VERSION 5.8 ;
BUSBITCHARS "[]" ;
DIVIDERCHAR "/" ;
UNITS
    DATABASE MICRONS 1000 ;
END UNITS

VIA CF_CARAVEL_SOC_via2_3_3100_480_1_9_320_320
  VIARULE M1M2_PR ;
  CUTSIZE 0.15 0.15 ;
  LAYERS met1 via met2 ;
  CUTSPACING 0.17 0.17 ;
  ENCLOSURE 0.085 0.165 0.055 0.085 ;
  ROWCOL 1 9 ;
END CF_CARAVEL_SOC_via2_3_3100_480_1_9_320_320

VIA CF_CARAVEL_SOC_via3_4_3100_480_1_7_400_400
  VIARULE M2M3_PR ;
  CUTSIZE 0.2 0.2 ;
  LAYERS met2 via2 met3 ;
  CUTSPACING 0.2 0.2 ;
  ENCLOSURE 0.04 0.085 0.065 0.065 ;
  ROWCOL 1 7 ;
END CF_CARAVEL_SOC_via3_4_3100_480_1_7_400_400

VIA CF_CARAVEL_SOC_via4_5_3100_480_1_7_400_400
  VIARULE M3M4_PR ;
  CUTSIZE 0.2 0.2 ;
  LAYERS met3 via3 met4 ;
  CUTSPACING 0.2 0.2 ;
  ENCLOSURE 0.09 0.06 0.25 0.065 ;
  ROWCOL 1 7 ;
END CF_CARAVEL_SOC_via4_5_3100_480_1_7_400_400

VIA CF_CARAVEL_SOC_via5_6_3100_3100_2_2_1600_1600
  VIARULE M4M5_PR ;
  CUTSIZE 0.8 0.8 ;
  LAYERS met4 via4 met5 ;
  CUTSPACING 0.8 0.8 ;
  ENCLOSURE 0.35 0.19 0.31 0.35 ;
  ROWCOL 2 2 ;
END CF_CARAVEL_SOC_via5_6_3100_3100_2_2_1600_1600

VIA CF_CARAVEL_SOC_via5_6_1600_3100_2_1_1600_1600
  VIARULE M4M5_PR ;
  CUTSIZE 0.8 0.8 ;
  LAYERS met4 via4 met5 ;
  CUTSPACING 0.8 0.8 ;
  ENCLOSURE 0.4 0.35 0.31 0.35 ;
  ROWCOL 2 1 ;
END CF_CARAVEL_SOC_via5_6_1600_3100_2_1_1600_1600

VIA CF_CARAVEL_SOC_via5_6_1600_1600_1_1_1600_1600
  VIARULE M4M5_PR ;
  CUTSIZE 0.8 0.8 ;
  LAYERS met4 via4 met5 ;
  CUTSPACING 0.8 0.8 ;
  ENCLOSURE 0.4 0.4 0.4 0.4 ;
END CF_CARAVEL_SOC_via5_6_1600_1600_1_1_1600_1600

VIA CF_CARAVEL_SOC_via5_6_3100_1600_1_2_1600_1600
  VIARULE M4M5_PR ;
  CUTSIZE 0.8 0.8 ;
  LAYERS met4 via4 met5 ;
  CUTSPACING 0.8 0.8 ;
  ENCLOSURE 0.35 0.19 0.35 0.4 ;
  ROWCOL 1 2 ;
END CF_CARAVEL_SOC_via5_6_3100_1600_1_2_1600_1600

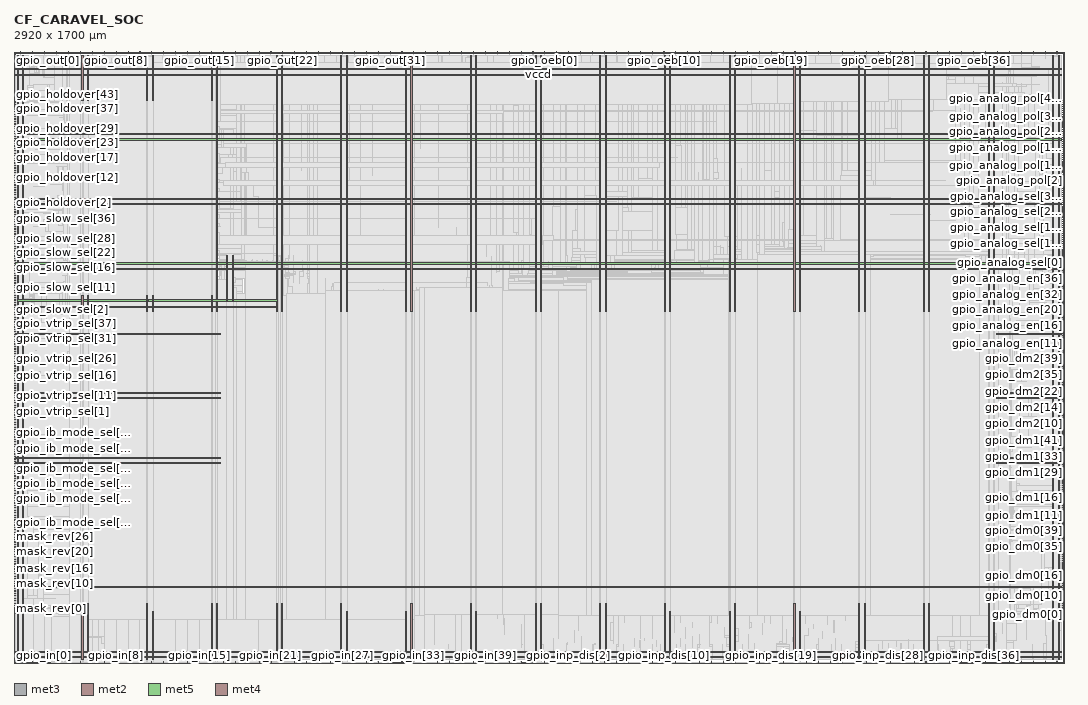
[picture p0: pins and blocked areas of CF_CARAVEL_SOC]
MACRO CF_CARAVEL_SOC
  FOREIGN CF_CARAVEL_SOC 0 0 ;
  CLASS BLOCK ;
  SIZE 2920 BY 1700 ;
  PIN gpio_analog_en[0]
    DIRECTION OUTPUT ;
    USE SIGNAL ;
    PORT
      LAYER met3 ;
        RECT  2916 851.4 2920 852 ;
    END
  END gpio_analog_en[0]
  PIN gpio_analog_en[10]
    DIRECTION OUTPUT ;
    USE SIGNAL ;
    PORT
      LAYER met3 ;
        RECT  2916 905.8 2920 906.4 ;
    END
  END gpio_analog_en[10]
  PIN gpio_analog_en[11]
    DIRECTION OUTPUT ;
    USE SIGNAL ;
    PORT
      LAYER met3 ;
        RECT  2916 911.24 2920 911.84 ;
    END
  END gpio_analog_en[11]
  PIN gpio_analog_en[12]
    DIRECTION OUTPUT ;
    USE SIGNAL ;
    PORT
      LAYER met3 ;
        RECT  2916 916.68 2920 917.28 ;
    END
  END gpio_analog_en[12]
  PIN gpio_analog_en[13]
    DIRECTION OUTPUT ;
    USE SIGNAL ;
    PORT
      LAYER met3 ;
        RECT  2916 922.12 2920 922.72 ;
    END
  END gpio_analog_en[13]
  PIN gpio_analog_en[14]
    DIRECTION OUTPUT ;
    USE SIGNAL ;
    PORT
      LAYER met3 ;
        RECT  2916 927.56 2920 928.16 ;
    END
  END gpio_analog_en[14]
  PIN gpio_analog_en[15]
    DIRECTION OUTPUT ;
    USE SIGNAL ;
    PORT
      LAYER met3 ;
        RECT  2916 933 2920 933.6 ;
    END
  END gpio_analog_en[15]
  PIN gpio_analog_en[16]
    DIRECTION OUTPUT ;
    USE SIGNAL ;
    PORT
      LAYER met3 ;
        RECT  2916 938.44 2920 939.04 ;
    END
  END gpio_analog_en[16]
  PIN gpio_analog_en[17]
    DIRECTION OUTPUT ;
    USE SIGNAL ;
    PORT
      LAYER met3 ;
        RECT  2916 943.88 2920 944.48 ;
    END
  END gpio_analog_en[17]
  PIN gpio_analog_en[18]
    DIRECTION OUTPUT ;
    USE SIGNAL ;
    PORT
      LAYER met3 ;
        RECT  2916 949.32 2920 949.92 ;
    END
  END gpio_analog_en[18]
  PIN gpio_analog_en[19]
    DIRECTION OUTPUT ;
    USE SIGNAL ;
    PORT
      LAYER met3 ;
        RECT  2916 954.76 2920 955.36 ;
    END
  END gpio_analog_en[19]
  PIN gpio_analog_en[1]
    DIRECTION OUTPUT ;
    USE SIGNAL ;
    PORT
      LAYER met3 ;
        RECT  2916 856.84 2920 857.44 ;
    END
  END gpio_analog_en[1]
  PIN gpio_analog_en[20]
    DIRECTION OUTPUT ;
    USE SIGNAL ;
    PORT
      LAYER met3 ;
        RECT  2916 960.2 2920 960.8 ;
    END
  END gpio_analog_en[20]
  PIN gpio_analog_en[21]
    DIRECTION OUTPUT ;
    USE SIGNAL ;
    PORT
      LAYER met3 ;
        RECT  2916 965.64 2920 966.24 ;
    END
  END gpio_analog_en[21]
  PIN gpio_analog_en[22]
    DIRECTION OUTPUT ;
    USE SIGNAL ;
    PORT
      LAYER met3 ;
        RECT  2916 971.08 2920 971.68 ;
    END
  END gpio_analog_en[22]
  PIN gpio_analog_en[23]
    DIRECTION OUTPUT ;
    USE SIGNAL ;
    PORT
      LAYER met3 ;
        RECT  2916 976.52 2920 977.12 ;
    END
  END gpio_analog_en[23]
  PIN gpio_analog_en[24]
    DIRECTION OUTPUT ;
    USE SIGNAL ;
    PORT
      LAYER met3 ;
        RECT  2916 981.96 2920 982.56 ;
    END
  END gpio_analog_en[24]
  PIN gpio_analog_en[25]
    DIRECTION OUTPUT ;
    USE SIGNAL ;
    PORT
      LAYER met3 ;
        RECT  2916 987.4 2920 988 ;
    END
  END gpio_analog_en[25]
  PIN gpio_analog_en[26]
    DIRECTION OUTPUT ;
    USE SIGNAL ;
    PORT
      LAYER met3 ;
        RECT  2916 992.84 2920 993.44 ;
    END
  END gpio_analog_en[26]
  PIN gpio_analog_en[27]
    DIRECTION OUTPUT ;
    USE SIGNAL ;
    PORT
      LAYER met3 ;
        RECT  2916 998.28 2920 998.88 ;
    END
  END gpio_analog_en[27]
  PIN gpio_analog_en[28]
    DIRECTION OUTPUT ;
    USE SIGNAL ;
    PORT
      LAYER met3 ;
        RECT  2916 1003.72 2920 1004.32 ;
    END
  END gpio_analog_en[28]
  PIN gpio_analog_en[29]
    DIRECTION OUTPUT ;
    USE SIGNAL ;
    PORT
      LAYER met3 ;
        RECT  2916 1009.16 2920 1009.76 ;
    END
  END gpio_analog_en[29]
  PIN gpio_analog_en[2]
    DIRECTION OUTPUT ;
    USE SIGNAL ;
    PORT
      LAYER met3 ;
        RECT  2916 862.28 2920 862.88 ;
    END
  END gpio_analog_en[2]
  PIN gpio_analog_en[30]
    DIRECTION OUTPUT ;
    USE SIGNAL ;
    PORT
      LAYER met3 ;
        RECT  2916 1014.6 2920 1015.2 ;
    END
  END gpio_analog_en[30]
  PIN gpio_analog_en[31]
    DIRECTION OUTPUT ;
    USE SIGNAL ;
    PORT
      LAYER met3 ;
        RECT  2916 1020.04 2920 1020.64 ;
    END
  END gpio_analog_en[31]
  PIN gpio_analog_en[32]
    DIRECTION OUTPUT ;
    USE SIGNAL ;
    PORT
      LAYER met3 ;
        RECT  2916 1025.48 2920 1026.08 ;
    END
  END gpio_analog_en[32]
  PIN gpio_analog_en[33]
    DIRECTION OUTPUT ;
    USE SIGNAL ;
    PORT
      LAYER met3 ;
        RECT  2916 1030.92 2920 1031.52 ;
    END
  END gpio_analog_en[33]
  PIN gpio_analog_en[34]
    DIRECTION OUTPUT ;
    USE SIGNAL ;
    PORT
      LAYER met3 ;
        RECT  2916 1036.36 2920 1036.96 ;
    END
  END gpio_analog_en[34]
  PIN gpio_analog_en[35]
    DIRECTION OUTPUT ;
    USE SIGNAL ;
    PORT
      LAYER met3 ;
        RECT  2916 1041.8 2920 1042.4 ;
    END
  END gpio_analog_en[35]
  PIN gpio_analog_en[36]
    DIRECTION OUTPUT ;
    USE SIGNAL ;
    PORT
      LAYER met3 ;
        RECT  2916 1047.24 2920 1047.84 ;
    END
  END gpio_analog_en[36]
  PIN gpio_analog_en[37]
    DIRECTION OUTPUT ;
    USE SIGNAL ;
    PORT
      LAYER met3 ;
        RECT  2916 1052.68 2920 1053.28 ;
    END
  END gpio_analog_en[37]
  PIN gpio_analog_en[38]
    DIRECTION OUTPUT ;
    USE SIGNAL ;
    PORT
      LAYER met3 ;
        RECT  2916 1058.12 2920 1058.72 ;
    END
  END gpio_analog_en[38]
  PIN gpio_analog_en[39]
    DIRECTION OUTPUT ;
    USE SIGNAL ;
    PORT
      LAYER met3 ;
        RECT  2916 1063.56 2920 1064.16 ;
    END
  END gpio_analog_en[39]
  PIN gpio_analog_en[3]
    DIRECTION OUTPUT ;
    USE SIGNAL ;
    PORT
      LAYER met3 ;
        RECT  2916 867.72 2920 868.32 ;
    END
  END gpio_analog_en[3]
  PIN gpio_analog_en[40]
    DIRECTION OUTPUT ;
    USE SIGNAL ;
    PORT
      LAYER met3 ;
        RECT  2916 1069 2920 1069.6 ;
    END
  END gpio_analog_en[40]
  PIN gpio_analog_en[41]
    DIRECTION OUTPUT ;
    USE SIGNAL ;
    PORT
      LAYER met3 ;
        RECT  2916 1074.44 2920 1075.04 ;
    END
  END gpio_analog_en[41]
  PIN gpio_analog_en[42]
    DIRECTION OUTPUT ;
    USE SIGNAL ;
    PORT
      LAYER met3 ;
        RECT  2916 1079.88 2920 1080.48 ;
    END
  END gpio_analog_en[42]
  PIN gpio_analog_en[43]
    DIRECTION OUTPUT ;
    USE SIGNAL ;
    PORT
      LAYER met3 ;
        RECT  2916 1085.32 2920 1085.92 ;
    END
  END gpio_analog_en[43]
  PIN gpio_analog_en[4]
    DIRECTION OUTPUT ;
    USE SIGNAL ;
    PORT
      LAYER met3 ;
        RECT  2916 873.16 2920 873.76 ;
    END
  END gpio_analog_en[4]
  PIN gpio_analog_en[5]
    DIRECTION OUTPUT ;
    USE SIGNAL ;
    PORT
      LAYER met3 ;
        RECT  2916 878.6 2920 879.2 ;
    END
  END gpio_analog_en[5]
  PIN gpio_analog_en[6]
    DIRECTION OUTPUT ;
    USE SIGNAL ;
    PORT
      LAYER met3 ;
        RECT  2916 884.04 2920 884.64 ;
    END
  END gpio_analog_en[6]
  PIN gpio_analog_en[7]
    DIRECTION OUTPUT ;
    USE SIGNAL ;
    PORT
      LAYER met3 ;
        RECT  2916 889.48 2920 890.08 ;
    END
  END gpio_analog_en[7]
  PIN gpio_analog_en[8]
    DIRECTION OUTPUT ;
    USE SIGNAL ;
    PORT
      LAYER met3 ;
        RECT  2916 894.92 2920 895.52 ;
    END
  END gpio_analog_en[8]
  PIN gpio_analog_en[9]
    DIRECTION OUTPUT ;
    USE SIGNAL ;
    PORT
      LAYER met3 ;
        RECT  2916 900.36 2920 900.96 ;
    END
  END gpio_analog_en[9]
  PIN gpio_analog_pol[0]
    DIRECTION OUTPUT ;
    USE SIGNAL ;
    PORT
      LAYER met3 ;
        RECT  2916 1330.12 2920 1330.72 ;
    END
  END gpio_analog_pol[0]
  PIN gpio_analog_pol[10]
    DIRECTION OUTPUT ;
    USE SIGNAL ;
    PORT
      LAYER met3 ;
        RECT  2916 1384.52 2920 1385.12 ;
    END
  END gpio_analog_pol[10]
  PIN gpio_analog_pol[11]
    DIRECTION OUTPUT ;
    USE SIGNAL ;
    PORT
      LAYER met3 ;
        RECT  2916 1389.96 2920 1390.56 ;
    END
  END gpio_analog_pol[11]
  PIN gpio_analog_pol[12]
    DIRECTION OUTPUT ;
    USE SIGNAL ;
    PORT
      LAYER met3 ;
        RECT  2916 1395.4 2920 1396 ;
    END
  END gpio_analog_pol[12]
  PIN gpio_analog_pol[13]
    DIRECTION OUTPUT ;
    USE SIGNAL ;
    PORT
      LAYER met3 ;
        RECT  2916 1400.84 2920 1401.44 ;
    END
  END gpio_analog_pol[13]
  PIN gpio_analog_pol[14]
    DIRECTION OUTPUT ;
    USE SIGNAL ;
    PORT
      LAYER met3 ;
        RECT  2916 1406.28 2920 1406.88 ;
    END
  END gpio_analog_pol[14]
  PIN gpio_analog_pol[15]
    DIRECTION OUTPUT ;
    USE SIGNAL ;
    PORT
      LAYER met3 ;
        RECT  2916 1411.72 2920 1412.32 ;
    END
  END gpio_analog_pol[15]
  PIN gpio_analog_pol[16]
    DIRECTION OUTPUT ;
    USE SIGNAL ;
    PORT
      LAYER met3 ;
        RECT  2916 1417.16 2920 1417.76 ;
    END
  END gpio_analog_pol[16]
  PIN gpio_analog_pol[17]
    DIRECTION OUTPUT ;
    USE SIGNAL ;
    PORT
      LAYER met3 ;
        RECT  2916 1422.6 2920 1423.2 ;
    END
  END gpio_analog_pol[17]
  PIN gpio_analog_pol[18]
    DIRECTION OUTPUT ;
    USE SIGNAL ;
    PORT
      LAYER met3 ;
        RECT  2916 1428.04 2920 1428.64 ;
    END
  END gpio_analog_pol[18]
  PIN gpio_analog_pol[19]
    DIRECTION OUTPUT ;
    USE SIGNAL ;
    PORT
      LAYER met3 ;
        RECT  2916 1433.48 2920 1434.08 ;
    END
  END gpio_analog_pol[19]
  PIN gpio_analog_pol[1]
    DIRECTION OUTPUT ;
    USE SIGNAL ;
    PORT
      LAYER met3 ;
        RECT  2916 1335.56 2920 1336.16 ;
    END
  END gpio_analog_pol[1]
  PIN gpio_analog_pol[20]
    DIRECTION OUTPUT ;
    USE SIGNAL ;
    PORT
      LAYER met3 ;
        RECT  2916 1438.92 2920 1439.52 ;
    END
  END gpio_analog_pol[20]
  PIN gpio_analog_pol[21]
    DIRECTION OUTPUT ;
    USE SIGNAL ;
    PORT
      LAYER met3 ;
        RECT  2916 1444.36 2920 1444.96 ;
    END
  END gpio_analog_pol[21]
  PIN gpio_analog_pol[22]
    DIRECTION OUTPUT ;
    USE SIGNAL ;
    PORT
      LAYER met3 ;
        RECT  2916 1449.8 2920 1450.4 ;
    END
  END gpio_analog_pol[22]
  PIN gpio_analog_pol[23]
    DIRECTION OUTPUT ;
    USE SIGNAL ;
    PORT
      LAYER met3 ;
        RECT  2916 1455.24 2920 1455.84 ;
    END
  END gpio_analog_pol[23]
  PIN gpio_analog_pol[24]
    DIRECTION OUTPUT ;
    USE SIGNAL ;
    PORT
      LAYER met3 ;
        RECT  2916 1460.68 2920 1461.28 ;
    END
  END gpio_analog_pol[24]
  PIN gpio_analog_pol[25]
    DIRECTION OUTPUT ;
    USE SIGNAL ;
    PORT
      LAYER met3 ;
        RECT  2916 1466.12 2920 1466.72 ;
    END
  END gpio_analog_pol[25]
  PIN gpio_analog_pol[26]
    DIRECTION OUTPUT ;
    USE SIGNAL ;
    PORT
      LAYER met3 ;
        RECT  2916 1471.56 2920 1472.16 ;
    END
  END gpio_analog_pol[26]
  PIN gpio_analog_pol[27]
    DIRECTION OUTPUT ;
    USE SIGNAL ;
    PORT
      LAYER met3 ;
        RECT  2916 1477 2920 1477.6 ;
    END
  END gpio_analog_pol[27]
  PIN gpio_analog_pol[28]
    DIRECTION OUTPUT ;
    USE SIGNAL ;
    PORT
      LAYER met3 ;
        RECT  2916 1482.44 2920 1483.04 ;
    END
  END gpio_analog_pol[28]
  PIN gpio_analog_pol[29]
    DIRECTION OUTPUT ;
    USE SIGNAL ;
    PORT
      LAYER met3 ;
        RECT  2916 1487.88 2920 1488.48 ;
    END
  END gpio_analog_pol[29]
  PIN gpio_analog_pol[2]
    DIRECTION OUTPUT ;
    USE SIGNAL ;
    PORT
      LAYER met3 ;
        RECT  2916 1341 2920 1341.6 ;
    END
  END gpio_analog_pol[2]
  PIN gpio_analog_pol[30]
    DIRECTION OUTPUT ;
    USE SIGNAL ;
    PORT
      LAYER met3 ;
        RECT  2916 1493.32 2920 1493.92 ;
    END
  END gpio_analog_pol[30]
  PIN gpio_analog_pol[31]
    DIRECTION OUTPUT ;
    USE SIGNAL ;
    PORT
      LAYER met3 ;
        RECT  2916 1498.76 2920 1499.36 ;
    END
  END gpio_analog_pol[31]
  PIN gpio_analog_pol[32]
    DIRECTION OUTPUT ;
    USE SIGNAL ;
    PORT
      LAYER met3 ;
        RECT  2916 1504.2 2920 1504.8 ;
    END
  END gpio_analog_pol[32]
  PIN gpio_analog_pol[33]
    DIRECTION OUTPUT ;
    USE SIGNAL ;
    PORT
      LAYER met3 ;
        RECT  2916 1509.64 2920 1510.24 ;
    END
  END gpio_analog_pol[33]
  PIN gpio_analog_pol[34]
    DIRECTION OUTPUT ;
    USE SIGNAL ;
    PORT
      LAYER met3 ;
        RECT  2916 1515.08 2920 1515.68 ;
    END
  END gpio_analog_pol[34]
  PIN gpio_analog_pol[35]
    DIRECTION OUTPUT ;
    USE SIGNAL ;
    PORT
      LAYER met3 ;
        RECT  2916 1520.52 2920 1521.12 ;
    END
  END gpio_analog_pol[35]
  PIN gpio_analog_pol[36]
    DIRECTION OUTPUT ;
    USE SIGNAL ;
    PORT
      LAYER met3 ;
        RECT  2916 1525.96 2920 1526.56 ;
    END
  END gpio_analog_pol[36]
  PIN gpio_analog_pol[37]
    DIRECTION OUTPUT ;
    USE SIGNAL ;
    PORT
      LAYER met3 ;
        RECT  2916 1531.4 2920 1532 ;
    END
  END gpio_analog_pol[37]
  PIN gpio_analog_pol[38]
    DIRECTION OUTPUT ;
    USE SIGNAL ;
    PORT
      LAYER met3 ;
        RECT  2916 1536.84 2920 1537.44 ;
    END
  END gpio_analog_pol[38]
  PIN gpio_analog_pol[39]
    DIRECTION OUTPUT ;
    USE SIGNAL ;
    PORT
      LAYER met3 ;
        RECT  2916 1542.28 2920 1542.88 ;
    END
  END gpio_analog_pol[39]
  PIN gpio_analog_pol[3]
    DIRECTION OUTPUT ;
    USE SIGNAL ;
    PORT
      LAYER met3 ;
        RECT  2916 1346.44 2920 1347.04 ;
    END
  END gpio_analog_pol[3]
  PIN gpio_analog_pol[40]
    DIRECTION OUTPUT ;
    USE SIGNAL ;
    PORT
      LAYER met3 ;
        RECT  2916 1547.72 2920 1548.32 ;
    END
  END gpio_analog_pol[40]
  PIN gpio_analog_pol[41]
    DIRECTION OUTPUT ;
    USE SIGNAL ;
    PORT
      LAYER met3 ;
        RECT  2916 1553.16 2920 1553.76 ;
    END
  END gpio_analog_pol[41]
  PIN gpio_analog_pol[42]
    DIRECTION OUTPUT ;
    USE SIGNAL ;
    PORT
      LAYER met3 ;
        RECT  2916 1558.6 2920 1559.2 ;
    END
  END gpio_analog_pol[42]
  PIN gpio_analog_pol[43]
    DIRECTION OUTPUT ;
    USE SIGNAL ;
    PORT
      LAYER met3 ;
        RECT  2916 1564.04 2920 1564.64 ;
    END
  END gpio_analog_pol[43]
  PIN gpio_analog_pol[4]
    DIRECTION OUTPUT ;
    USE SIGNAL ;
    PORT
      LAYER met3 ;
        RECT  2916 1351.88 2920 1352.48 ;
    END
  END gpio_analog_pol[4]
  PIN gpio_analog_pol[5]
    DIRECTION OUTPUT ;
    USE SIGNAL ;
    PORT
      LAYER met3 ;
        RECT  2916 1357.32 2920 1357.92 ;
    END
  END gpio_analog_pol[5]
  PIN gpio_analog_pol[6]
    DIRECTION OUTPUT ;
    USE SIGNAL ;
    PORT
      LAYER met3 ;
        RECT  2916 1362.76 2920 1363.36 ;
    END
  END gpio_analog_pol[6]
  PIN gpio_analog_pol[7]
    DIRECTION OUTPUT ;
    USE SIGNAL ;
    PORT
      LAYER met3 ;
        RECT  2916 1368.2 2920 1368.8 ;
    END
  END gpio_analog_pol[7]
  PIN gpio_analog_pol[8]
    DIRECTION OUTPUT ;
    USE SIGNAL ;
    PORT
      LAYER met3 ;
        RECT  2916 1373.64 2920 1374.24 ;
    END
  END gpio_analog_pol[8]
  PIN gpio_analog_pol[9]
    DIRECTION OUTPUT ;
    USE SIGNAL ;
    PORT
      LAYER met3 ;
        RECT  2916 1379.08 2920 1379.68 ;
    END
  END gpio_analog_pol[9]
  PIN gpio_analog_sel[0]
    DIRECTION OUTPUT ;
    USE SIGNAL ;
    PORT
      LAYER met3 ;
        RECT  2916 1090.76 2920 1091.36 ;
    END
  END gpio_analog_sel[0]
  PIN gpio_analog_sel[10]
    DIRECTION OUTPUT ;
    USE SIGNAL ;
    PORT
      LAYER met3 ;
        RECT  2916 1145.16 2920 1145.76 ;
    END
  END gpio_analog_sel[10]
  PIN gpio_analog_sel[11]
    DIRECTION OUTPUT ;
    USE SIGNAL ;
    PORT
      LAYER met3 ;
        RECT  2916 1150.6 2920 1151.2 ;
    END
  END gpio_analog_sel[11]
  PIN gpio_analog_sel[12]
    DIRECTION OUTPUT ;
    USE SIGNAL ;
    PORT
      LAYER met3 ;
        RECT  2916 1156.04 2920 1156.64 ;
    END
  END gpio_analog_sel[12]
  PIN gpio_analog_sel[13]
    DIRECTION OUTPUT ;
    USE SIGNAL ;
    PORT
      LAYER met3 ;
        RECT  2916 1161.48 2920 1162.08 ;
    END
  END gpio_analog_sel[13]
  PIN gpio_analog_sel[14]
    DIRECTION OUTPUT ;
    USE SIGNAL ;
    PORT
      LAYER met3 ;
        RECT  2916 1166.92 2920 1167.52 ;
    END
  END gpio_analog_sel[14]
  PIN gpio_analog_sel[15]
    DIRECTION OUTPUT ;
    USE SIGNAL ;
    PORT
      LAYER met3 ;
        RECT  2916 1172.36 2920 1172.96 ;
    END
  END gpio_analog_sel[15]
  PIN gpio_analog_sel[16]
    DIRECTION OUTPUT ;
    USE SIGNAL ;
    PORT
      LAYER met3 ;
        RECT  2916 1177.8 2920 1178.4 ;
    END
  END gpio_analog_sel[16]
  PIN gpio_analog_sel[17]
    DIRECTION OUTPUT ;
    USE SIGNAL ;
    PORT
      LAYER met3 ;
        RECT  2916 1183.24 2920 1183.84 ;
    END
  END gpio_analog_sel[17]
  PIN gpio_analog_sel[18]
    DIRECTION OUTPUT ;
    USE SIGNAL ;
    PORT
      LAYER met3 ;
        RECT  2916 1188.68 2920 1189.28 ;
    END
  END gpio_analog_sel[18]
  PIN gpio_analog_sel[19]
    DIRECTION OUTPUT ;
    USE SIGNAL ;
    PORT
      LAYER met3 ;
        RECT  2916 1194.12 2920 1194.72 ;
    END
  END gpio_analog_sel[19]
  PIN gpio_analog_sel[1]
    DIRECTION OUTPUT ;
    USE SIGNAL ;
    PORT
      LAYER met3 ;
        RECT  2916 1096.2 2920 1096.8 ;
    END
  END gpio_analog_sel[1]
  PIN gpio_analog_sel[20]
    DIRECTION OUTPUT ;
    USE SIGNAL ;
    PORT
      LAYER met3 ;
        RECT  2916 1199.56 2920 1200.16 ;
    END
  END gpio_analog_sel[20]
  PIN gpio_analog_sel[21]
    DIRECTION OUTPUT ;
    USE SIGNAL ;
    PORT
      LAYER met3 ;
        RECT  2916 1205 2920 1205.6 ;
    END
  END gpio_analog_sel[21]
  PIN gpio_analog_sel[22]
    DIRECTION OUTPUT ;
    USE SIGNAL ;
    PORT
      LAYER met3 ;
        RECT  2916 1210.44 2920 1211.04 ;
    END
  END gpio_analog_sel[22]
  PIN gpio_analog_sel[23]
    DIRECTION OUTPUT ;
    USE SIGNAL ;
    PORT
      LAYER met3 ;
        RECT  2916 1215.88 2920 1216.48 ;
    END
  END gpio_analog_sel[23]
  PIN gpio_analog_sel[24]
    DIRECTION OUTPUT ;
    USE SIGNAL ;
    PORT
      LAYER met3 ;
        RECT  2916 1221.32 2920 1221.92 ;
    END
  END gpio_analog_sel[24]
  PIN gpio_analog_sel[25]
    DIRECTION OUTPUT ;
    USE SIGNAL ;
    PORT
      LAYER met3 ;
        RECT  2916 1226.76 2920 1227.36 ;
    END
  END gpio_analog_sel[25]
  PIN gpio_analog_sel[26]
    DIRECTION OUTPUT ;
    USE SIGNAL ;
    PORT
      LAYER met3 ;
        RECT  2916 1232.2 2920 1232.8 ;
    END
  END gpio_analog_sel[26]
  PIN gpio_analog_sel[27]
    DIRECTION OUTPUT ;
    USE SIGNAL ;
    PORT
      LAYER met3 ;
        RECT  2916 1237.64 2920 1238.24 ;
    END
  END gpio_analog_sel[27]
  PIN gpio_analog_sel[28]
    DIRECTION OUTPUT ;
    USE SIGNAL ;
    PORT
      LAYER met3 ;
        RECT  2916 1243.08 2920 1243.68 ;
    END
  END gpio_analog_sel[28]
  PIN gpio_analog_sel[29]
    DIRECTION OUTPUT ;
    USE SIGNAL ;
    PORT
      LAYER met3 ;
        RECT  2916 1248.52 2920 1249.12 ;
    END
  END gpio_analog_sel[29]
  PIN gpio_analog_sel[2]
    DIRECTION OUTPUT ;
    USE SIGNAL ;
    PORT
      LAYER met3 ;
        RECT  2916 1101.64 2920 1102.24 ;
    END
  END gpio_analog_sel[2]
  PIN gpio_analog_sel[30]
    DIRECTION OUTPUT ;
    USE SIGNAL ;
    PORT
      LAYER met3 ;
        RECT  2916 1253.96 2920 1254.56 ;
    END
  END gpio_analog_sel[30]
  PIN gpio_analog_sel[31]
    DIRECTION OUTPUT ;
    USE SIGNAL ;
    PORT
      LAYER met3 ;
        RECT  2916 1259.4 2920 1260 ;
    END
  END gpio_analog_sel[31]
  PIN gpio_analog_sel[32]
    DIRECTION OUTPUT ;
    USE SIGNAL ;
    PORT
      LAYER met3 ;
        RECT  2916 1264.84 2920 1265.44 ;
    END
  END gpio_analog_sel[32]
  PIN gpio_analog_sel[33]
    DIRECTION OUTPUT ;
    USE SIGNAL ;
    PORT
      LAYER met3 ;
        RECT  2916 1270.28 2920 1270.88 ;
    END
  END gpio_analog_sel[33]
  PIN gpio_analog_sel[34]
    DIRECTION OUTPUT ;
    USE SIGNAL ;
    PORT
      LAYER met3 ;
        RECT  2916 1275.72 2920 1276.32 ;
    END
  END gpio_analog_sel[34]
  PIN gpio_analog_sel[35]
    DIRECTION OUTPUT ;
    USE SIGNAL ;
    PORT
      LAYER met3 ;
        RECT  2916 1281.16 2920 1281.76 ;
    END
  END gpio_analog_sel[35]
  PIN gpio_analog_sel[36]
    DIRECTION OUTPUT ;
    USE SIGNAL ;
    PORT
      LAYER met3 ;
        RECT  2916 1286.6 2920 1287.2 ;
    END
  END gpio_analog_sel[36]
  PIN gpio_analog_sel[37]
    DIRECTION OUTPUT ;
    USE SIGNAL ;
    PORT
      LAYER met3 ;
        RECT  2916 1292.04 2920 1292.64 ;
    END
  END gpio_analog_sel[37]
  PIN gpio_analog_sel[38]
    DIRECTION OUTPUT ;
    USE SIGNAL ;
    PORT
      LAYER met3 ;
        RECT  2916 1297.48 2920 1298.08 ;
    END
  END gpio_analog_sel[38]
  PIN gpio_analog_sel[39]
    DIRECTION OUTPUT ;
    USE SIGNAL ;
    PORT
      LAYER met3 ;
        RECT  2916 1302.92 2920 1303.52 ;
    END
  END gpio_analog_sel[39]
  PIN gpio_analog_sel[3]
    DIRECTION OUTPUT ;
    USE SIGNAL ;
    PORT
      LAYER met3 ;
        RECT  2916 1107.08 2920 1107.68 ;
    END
  END gpio_analog_sel[3]
  PIN gpio_analog_sel[40]
    DIRECTION OUTPUT ;
    USE SIGNAL ;
    PORT
      LAYER met3 ;
        RECT  2916 1308.36 2920 1308.96 ;
    END
  END gpio_analog_sel[40]
  PIN gpio_analog_sel[41]
    DIRECTION OUTPUT ;
    USE SIGNAL ;
    PORT
      LAYER met3 ;
        RECT  2916 1313.8 2920 1314.4 ;
    END
  END gpio_analog_sel[41]
  PIN gpio_analog_sel[42]
    DIRECTION OUTPUT ;
    USE SIGNAL ;
    PORT
      LAYER met3 ;
        RECT  2916 1319.24 2920 1319.84 ;
    END
  END gpio_analog_sel[42]
  PIN gpio_analog_sel[43]
    DIRECTION OUTPUT ;
    USE SIGNAL ;
    PORT
      LAYER met3 ;
        RECT  2916 1324.68 2920 1325.28 ;
    END
  END gpio_analog_sel[43]
  PIN gpio_analog_sel[4]
    DIRECTION OUTPUT ;
    USE SIGNAL ;
    PORT
      LAYER met3 ;
        RECT  2916 1112.52 2920 1113.12 ;
    END
  END gpio_analog_sel[4]
  PIN gpio_analog_sel[5]
    DIRECTION OUTPUT ;
    USE SIGNAL ;
    PORT
      LAYER met3 ;
        RECT  2916 1117.96 2920 1118.56 ;
    END
  END gpio_analog_sel[5]
  PIN gpio_analog_sel[6]
    DIRECTION OUTPUT ;
    USE SIGNAL ;
    PORT
      LAYER met3 ;
        RECT  2916 1123.4 2920 1124 ;
    END
  END gpio_analog_sel[6]
  PIN gpio_analog_sel[7]
    DIRECTION OUTPUT ;
    USE SIGNAL ;
    PORT
      LAYER met3 ;
        RECT  2916 1128.84 2920 1129.44 ;
    END
  END gpio_analog_sel[7]
  PIN gpio_analog_sel[8]
    DIRECTION OUTPUT ;
    USE SIGNAL ;
    PORT
      LAYER met3 ;
        RECT  2916 1134.28 2920 1134.88 ;
    END
  END gpio_analog_sel[8]
  PIN gpio_analog_sel[9]
    DIRECTION OUTPUT ;
    USE SIGNAL ;
    PORT
      LAYER met3 ;
        RECT  2916 1139.72 2920 1140.32 ;
    END
  END gpio_analog_sel[9]
  PIN gpio_dm0[0]
    DIRECTION OUTPUT ;
    USE SIGNAL ;
    PORT
      LAYER met3 ;
        RECT  2916 133.32 2920 133.92 ;
    END
  END gpio_dm0[0]
  PIN gpio_dm0[10]
    DIRECTION OUTPUT ;
    USE SIGNAL ;
    PORT
      LAYER met3 ;
        RECT  2916 187.72 2920 188.32 ;
    END
  END gpio_dm0[10]
  PIN gpio_dm0[11]
    DIRECTION OUTPUT ;
    USE SIGNAL ;
    PORT
      LAYER met3 ;
        RECT  2916 193.16 2920 193.76 ;
    END
  END gpio_dm0[11]
  PIN gpio_dm0[12]
    DIRECTION OUTPUT ;
    USE SIGNAL ;
    PORT
      LAYER met3 ;
        RECT  2916 198.6 2920 199.2 ;
    END
  END gpio_dm0[12]
  PIN gpio_dm0[13]
    DIRECTION OUTPUT ;
    USE SIGNAL ;
    PORT
      LAYER met3 ;
        RECT  2916 204.04 2920 204.64 ;
    END
  END gpio_dm0[13]
  PIN gpio_dm0[14]
    DIRECTION OUTPUT ;
    USE SIGNAL ;
    PORT
      LAYER met3 ;
        RECT  2916 209.48 2920 210.08 ;
    END
  END gpio_dm0[14]
  PIN gpio_dm0[15]
    DIRECTION OUTPUT ;
    USE SIGNAL ;
    PORT
      LAYER met3 ;
        RECT  2916 214.92 2920 215.52 ;
    END
  END gpio_dm0[15]
  PIN gpio_dm0[16]
    DIRECTION OUTPUT ;
    USE SIGNAL ;
    PORT
      LAYER met3 ;
        RECT  2916 220.36 2920 220.96 ;
    END
  END gpio_dm0[16]
  PIN gpio_dm0[17]
    DIRECTION OUTPUT ;
    USE SIGNAL ;
    PORT
      LAYER met3 ;
        RECT  2916 225.8 2920 226.4 ;
    END
  END gpio_dm0[17]
  PIN gpio_dm0[18]
    DIRECTION OUTPUT ;
    USE SIGNAL ;
    PORT
      LAYER met3 ;
        RECT  2916 231.24 2920 231.84 ;
    END
  END gpio_dm0[18]
  PIN gpio_dm0[19]
    DIRECTION OUTPUT ;
    USE SIGNAL ;
    PORT
      LAYER met3 ;
        RECT  2916 236.68 2920 237.28 ;
    END
  END gpio_dm0[19]
  PIN gpio_dm0[1]
    DIRECTION OUTPUT ;
    USE SIGNAL ;
    PORT
      LAYER met3 ;
        RECT  2916 138.76 2920 139.36 ;
    END
  END gpio_dm0[1]
  PIN gpio_dm0[20]
    DIRECTION OUTPUT ;
    USE SIGNAL ;
    PORT
      LAYER met3 ;
        RECT  2916 242.12 2920 242.72 ;
    END
  END gpio_dm0[20]
  PIN gpio_dm0[21]
    DIRECTION OUTPUT ;
    USE SIGNAL ;
    PORT
      LAYER met3 ;
        RECT  2916 247.56 2920 248.16 ;
    END
  END gpio_dm0[21]
  PIN gpio_dm0[22]
    DIRECTION OUTPUT ;
    USE SIGNAL ;
    PORT
      LAYER met3 ;
        RECT  2916 253 2920 253.6 ;
    END
  END gpio_dm0[22]
  PIN gpio_dm0[23]
    DIRECTION OUTPUT ;
    USE SIGNAL ;
    PORT
      LAYER met3 ;
        RECT  2916 258.44 2920 259.04 ;
    END
  END gpio_dm0[23]
  PIN gpio_dm0[24]
    DIRECTION OUTPUT ;
    USE SIGNAL ;
    PORT
      LAYER met3 ;
        RECT  2916 263.88 2920 264.48 ;
    END
  END gpio_dm0[24]
  PIN gpio_dm0[25]
    DIRECTION OUTPUT ;
    USE SIGNAL ;
    PORT
      LAYER met3 ;
        RECT  2916 269.32 2920 269.92 ;
    END
  END gpio_dm0[25]
  PIN gpio_dm0[26]
    DIRECTION OUTPUT ;
    USE SIGNAL ;
    PORT
      LAYER met3 ;
        RECT  2916 274.76 2920 275.36 ;
    END
  END gpio_dm0[26]
  PIN gpio_dm0[27]
    DIRECTION OUTPUT ;
    USE SIGNAL ;
    PORT
      LAYER met3 ;
        RECT  2916 280.2 2920 280.8 ;
    END
  END gpio_dm0[27]
  PIN gpio_dm0[28]
    DIRECTION OUTPUT ;
    USE SIGNAL ;
    PORT
      LAYER met3 ;
        RECT  2916 285.64 2920 286.24 ;
    END
  END gpio_dm0[28]
  PIN gpio_dm0[29]
    DIRECTION OUTPUT ;
    USE SIGNAL ;
    PORT
      LAYER met3 ;
        RECT  2916 291.08 2920 291.68 ;
    END
  END gpio_dm0[29]
  PIN gpio_dm0[2]
    DIRECTION OUTPUT ;
    USE SIGNAL ;
    PORT
      LAYER met3 ;
        RECT  2916 144.2 2920 144.8 ;
    END
  END gpio_dm0[2]
  PIN gpio_dm0[30]
    DIRECTION OUTPUT ;
    USE SIGNAL ;
    PORT
      LAYER met3 ;
        RECT  2916 296.52 2920 297.12 ;
    END
  END gpio_dm0[30]
  PIN gpio_dm0[31]
    DIRECTION OUTPUT ;
    USE SIGNAL ;
    PORT
      LAYER met3 ;
        RECT  2916 301.96 2920 302.56 ;
    END
  END gpio_dm0[31]
  PIN gpio_dm0[32]
    DIRECTION OUTPUT ;
    USE SIGNAL ;
    PORT
      LAYER met3 ;
        RECT  2916 307.4 2920 308 ;
    END
  END gpio_dm0[32]
  PIN gpio_dm0[33]
    DIRECTION OUTPUT ;
    USE SIGNAL ;
    PORT
      LAYER met3 ;
        RECT  2916 312.84 2920 313.44 ;
    END
  END gpio_dm0[33]
  PIN gpio_dm0[34]
    DIRECTION OUTPUT ;
    USE SIGNAL ;
    PORT
      LAYER met3 ;
        RECT  2916 318.28 2920 318.88 ;
    END
  END gpio_dm0[34]
  PIN gpio_dm0[35]
    DIRECTION OUTPUT ;
    USE SIGNAL ;
    PORT
      LAYER met3 ;
        RECT  2916 323.72 2920 324.32 ;
    END
  END gpio_dm0[35]
  PIN gpio_dm0[36]
    DIRECTION OUTPUT ;
    USE SIGNAL ;
    PORT
      LAYER met3 ;
        RECT  2916 329.16 2920 329.76 ;
    END
  END gpio_dm0[36]
  PIN gpio_dm0[37]
    DIRECTION OUTPUT ;
    USE SIGNAL ;
    PORT
      LAYER met3 ;
        RECT  2916 334.6 2920 335.2 ;
    END
  END gpio_dm0[37]
  PIN gpio_dm0[38]
    DIRECTION OUTPUT ;
    USE SIGNAL ;
    PORT
      LAYER met3 ;
        RECT  2916 340.04 2920 340.64 ;
    END
  END gpio_dm0[38]
  PIN gpio_dm0[39]
    DIRECTION OUTPUT ;
    USE SIGNAL ;
    PORT
      LAYER met3 ;
        RECT  2916 345.48 2920 346.08 ;
    END
  END gpio_dm0[39]
  PIN gpio_dm0[3]
    DIRECTION OUTPUT ;
    USE SIGNAL ;
    PORT
      LAYER met3 ;
        RECT  2916 149.64 2920 150.24 ;
    END
  END gpio_dm0[3]
  PIN gpio_dm0[40]
    DIRECTION OUTPUT ;
    USE SIGNAL ;
    PORT
      LAYER met3 ;
        RECT  2916 350.92 2920 351.52 ;
    END
  END gpio_dm0[40]
  PIN gpio_dm0[41]
    DIRECTION OUTPUT ;
    USE SIGNAL ;
    PORT
      LAYER met3 ;
        RECT  2916 356.36 2920 356.96 ;
    END
  END gpio_dm0[41]
  PIN gpio_dm0[42]
    DIRECTION OUTPUT ;
    USE SIGNAL ;
    PORT
      LAYER met3 ;
        RECT  2916 361.8 2920 362.4 ;
    END
  END gpio_dm0[42]
  PIN gpio_dm0[43]
    DIRECTION OUTPUT ;
    USE SIGNAL ;
    PORT
      LAYER met3 ;
        RECT  2916 367.24 2920 367.84 ;
    END
  END gpio_dm0[43]
  PIN gpio_dm0[4]
    DIRECTION OUTPUT ;
    USE SIGNAL ;
    PORT
      LAYER met3 ;
        RECT  2916 155.08 2920 155.68 ;
    END
  END gpio_dm0[4]
  PIN gpio_dm0[5]
    DIRECTION OUTPUT ;
    USE SIGNAL ;
    PORT
      LAYER met3 ;
        RECT  2916 160.52 2920 161.12 ;
    END
  END gpio_dm0[5]
  PIN gpio_dm0[6]
    DIRECTION OUTPUT ;
    USE SIGNAL ;
    PORT
      LAYER met3 ;
        RECT  2916 165.96 2920 166.56 ;
    END
  END gpio_dm0[6]
  PIN gpio_dm0[7]
    DIRECTION OUTPUT ;
    USE SIGNAL ;
    PORT
      LAYER met3 ;
        RECT  2916 171.4 2920 172 ;
    END
  END gpio_dm0[7]
  PIN gpio_dm0[8]
    DIRECTION OUTPUT ;
    USE SIGNAL ;
    PORT
      LAYER met3 ;
        RECT  2916 176.84 2920 177.44 ;
    END
  END gpio_dm0[8]
  PIN gpio_dm0[9]
    DIRECTION OUTPUT ;
    USE SIGNAL ;
    PORT
      LAYER met3 ;
        RECT  2916 182.28 2920 182.88 ;
    END
  END gpio_dm0[9]
  PIN gpio_dm1[0]
    DIRECTION OUTPUT ;
    USE SIGNAL ;
    PORT
      LAYER met3 ;
        RECT  2916 372.68 2920 373.28 ;
    END
  END gpio_dm1[0]
  PIN gpio_dm1[10]
    DIRECTION OUTPUT ;
    USE SIGNAL ;
    PORT
      LAYER met3 ;
        RECT  2916 427.08 2920 427.68 ;
    END
  END gpio_dm1[10]
  PIN gpio_dm1[11]
    DIRECTION OUTPUT ;
    USE SIGNAL ;
    PORT
      LAYER met3 ;
        RECT  2916 432.52 2920 433.12 ;
    END
  END gpio_dm1[11]
  PIN gpio_dm1[12]
    DIRECTION OUTPUT ;
    USE SIGNAL ;
    PORT
      LAYER met3 ;
        RECT  2916 437.96 2920 438.56 ;
    END
  END gpio_dm1[12]
  PIN gpio_dm1[13]
    DIRECTION OUTPUT ;
    USE SIGNAL ;
    PORT
      LAYER met3 ;
        RECT  2916 443.4 2920 444 ;
    END
  END gpio_dm1[13]
  PIN gpio_dm1[14]
    DIRECTION OUTPUT ;
    USE SIGNAL ;
    PORT
      LAYER met3 ;
        RECT  2916 448.84 2920 449.44 ;
    END
  END gpio_dm1[14]
  PIN gpio_dm1[15]
    DIRECTION OUTPUT ;
    USE SIGNAL ;
    PORT
      LAYER met3 ;
        RECT  2916 454.28 2920 454.88 ;
    END
  END gpio_dm1[15]
  PIN gpio_dm1[16]
    DIRECTION OUTPUT ;
    USE SIGNAL ;
    PORT
      LAYER met3 ;
        RECT  2916 459.72 2920 460.32 ;
    END
  END gpio_dm1[16]
  PIN gpio_dm1[17]
    DIRECTION OUTPUT ;
    USE SIGNAL ;
    PORT
      LAYER met3 ;
        RECT  2916 465.16 2920 465.76 ;
    END
  END gpio_dm1[17]
  PIN gpio_dm1[18]
    DIRECTION OUTPUT ;
    USE SIGNAL ;
    PORT
      LAYER met3 ;
        RECT  2916 470.6 2920 471.2 ;
    END
  END gpio_dm1[18]
  PIN gpio_dm1[19]
    DIRECTION OUTPUT ;
    USE SIGNAL ;
    PORT
      LAYER met3 ;
        RECT  2916 476.04 2920 476.64 ;
    END
  END gpio_dm1[19]
  PIN gpio_dm1[1]
    DIRECTION OUTPUT ;
    USE SIGNAL ;
    PORT
      LAYER met3 ;
        RECT  2916 378.12 2920 378.72 ;
    END
  END gpio_dm1[1]
  PIN gpio_dm1[20]
    DIRECTION OUTPUT ;
    USE SIGNAL ;
    PORT
      LAYER met3 ;
        RECT  2916 481.48 2920 482.08 ;
    END
  END gpio_dm1[20]
  PIN gpio_dm1[21]
    DIRECTION OUTPUT ;
    USE SIGNAL ;
    PORT
      LAYER met3 ;
        RECT  2916 486.92 2920 487.52 ;
    END
  END gpio_dm1[21]
  PIN gpio_dm1[22]
    DIRECTION OUTPUT ;
    USE SIGNAL ;
    PORT
      LAYER met3 ;
        RECT  2916 492.36 2920 492.96 ;
    END
  END gpio_dm1[22]
  PIN gpio_dm1[23]
    DIRECTION OUTPUT ;
    USE SIGNAL ;
    PORT
      LAYER met3 ;
        RECT  2916 497.8 2920 498.4 ;
    END
  END gpio_dm1[23]
  PIN gpio_dm1[24]
    DIRECTION OUTPUT ;
    USE SIGNAL ;
    PORT
      LAYER met3 ;
        RECT  2916 503.24 2920 503.84 ;
    END
  END gpio_dm1[24]
  PIN gpio_dm1[25]
    DIRECTION OUTPUT ;
    USE SIGNAL ;
    PORT
      LAYER met3 ;
        RECT  2916 508.68 2920 509.28 ;
    END
  END gpio_dm1[25]
  PIN gpio_dm1[26]
    DIRECTION OUTPUT ;
    USE SIGNAL ;
    PORT
      LAYER met3 ;
        RECT  2916 514.12 2920 514.72 ;
    END
  END gpio_dm1[26]
  PIN gpio_dm1[27]
    DIRECTION OUTPUT ;
    USE SIGNAL ;
    PORT
      LAYER met3 ;
        RECT  2916 519.56 2920 520.16 ;
    END
  END gpio_dm1[27]
  PIN gpio_dm1[28]
    DIRECTION OUTPUT ;
    USE SIGNAL ;
    PORT
      LAYER met3 ;
        RECT  2916 525 2920 525.6 ;
    END
  END gpio_dm1[28]
  PIN gpio_dm1[29]
    DIRECTION OUTPUT ;
    USE SIGNAL ;
    PORT
      LAYER met3 ;
        RECT  2916 530.44 2920 531.04 ;
    END
  END gpio_dm1[29]
  PIN gpio_dm1[2]
    DIRECTION OUTPUT ;
    USE SIGNAL ;
    PORT
      LAYER met3 ;
        RECT  2916 383.56 2920 384.16 ;
    END
  END gpio_dm1[2]
  PIN gpio_dm1[30]
    DIRECTION OUTPUT ;
    USE SIGNAL ;
    PORT
      LAYER met3 ;
        RECT  2916 535.88 2920 536.48 ;
    END
  END gpio_dm1[30]
  PIN gpio_dm1[31]
    DIRECTION OUTPUT ;
    USE SIGNAL ;
    PORT
      LAYER met3 ;
        RECT  2916 541.32 2920 541.92 ;
    END
  END gpio_dm1[31]
  PIN gpio_dm1[32]
    DIRECTION OUTPUT ;
    USE SIGNAL ;
    PORT
      LAYER met3 ;
        RECT  2916 546.76 2920 547.36 ;
    END
  END gpio_dm1[32]
  PIN gpio_dm1[33]
    DIRECTION OUTPUT ;
    USE SIGNAL ;
    PORT
      LAYER met3 ;
        RECT  2916 552.2 2920 552.8 ;
    END
  END gpio_dm1[33]
  PIN gpio_dm1[34]
    DIRECTION OUTPUT ;
    USE SIGNAL ;
    PORT
      LAYER met3 ;
        RECT  2916 557.64 2920 558.24 ;
    END
  END gpio_dm1[34]
  PIN gpio_dm1[35]
    DIRECTION OUTPUT ;
    USE SIGNAL ;
    PORT
      LAYER met3 ;
        RECT  2916 563.08 2920 563.68 ;
    END
  END gpio_dm1[35]
  PIN gpio_dm1[36]
    DIRECTION OUTPUT ;
    USE SIGNAL ;
    PORT
      LAYER met3 ;
        RECT  2916 568.52 2920 569.12 ;
    END
  END gpio_dm1[36]
  PIN gpio_dm1[37]
    DIRECTION OUTPUT ;
    USE SIGNAL ;
    PORT
      LAYER met3 ;
        RECT  2916 573.96 2920 574.56 ;
    END
  END gpio_dm1[37]
  PIN gpio_dm1[38]
    DIRECTION OUTPUT ;
    USE SIGNAL ;
    PORT
      LAYER met3 ;
        RECT  2916 579.4 2920 580 ;
    END
  END gpio_dm1[38]
  PIN gpio_dm1[39]
    DIRECTION OUTPUT ;
    USE SIGNAL ;
    PORT
      LAYER met3 ;
        RECT  2916 584.84 2920 585.44 ;
    END
  END gpio_dm1[39]
  PIN gpio_dm1[3]
    DIRECTION OUTPUT ;
    USE SIGNAL ;
    PORT
      LAYER met3 ;
        RECT  2916 389 2920 389.6 ;
    END
  END gpio_dm1[3]
  PIN gpio_dm1[40]
    DIRECTION OUTPUT ;
    USE SIGNAL ;
    PORT
      LAYER met3 ;
        RECT  2916 590.28 2920 590.88 ;
    END
  END gpio_dm1[40]
  PIN gpio_dm1[41]
    DIRECTION OUTPUT ;
    USE SIGNAL ;
    PORT
      LAYER met3 ;
        RECT  2916 595.72 2920 596.32 ;
    END
  END gpio_dm1[41]
  PIN gpio_dm1[42]
    DIRECTION OUTPUT ;
    USE SIGNAL ;
    PORT
      LAYER met3 ;
        RECT  2916 601.16 2920 601.76 ;
    END
  END gpio_dm1[42]
  PIN gpio_dm1[43]
    DIRECTION OUTPUT ;
    USE SIGNAL ;
    PORT
      LAYER met3 ;
        RECT  2916 606.6 2920 607.2 ;
    END
  END gpio_dm1[43]
  PIN gpio_dm1[4]
    DIRECTION OUTPUT ;
    USE SIGNAL ;
    PORT
      LAYER met3 ;
        RECT  2916 394.44 2920 395.04 ;
    END
  END gpio_dm1[4]
  PIN gpio_dm1[5]
    DIRECTION OUTPUT ;
    USE SIGNAL ;
    PORT
      LAYER met3 ;
        RECT  2916 399.88 2920 400.48 ;
    END
  END gpio_dm1[5]
  PIN gpio_dm1[6]
    DIRECTION OUTPUT ;
    USE SIGNAL ;
    PORT
      LAYER met3 ;
        RECT  2916 405.32 2920 405.92 ;
    END
  END gpio_dm1[6]
  PIN gpio_dm1[7]
    DIRECTION OUTPUT ;
    USE SIGNAL ;
    PORT
      LAYER met3 ;
        RECT  2916 410.76 2920 411.36 ;
    END
  END gpio_dm1[7]
  PIN gpio_dm1[8]
    DIRECTION OUTPUT ;
    USE SIGNAL ;
    PORT
      LAYER met3 ;
        RECT  2916 416.2 2920 416.8 ;
    END
  END gpio_dm1[8]
  PIN gpio_dm1[9]
    DIRECTION OUTPUT ;
    USE SIGNAL ;
    PORT
      LAYER met3 ;
        RECT  2916 421.64 2920 422.24 ;
    END
  END gpio_dm1[9]
  PIN gpio_dm2[0]
    DIRECTION OUTPUT ;
    USE SIGNAL ;
    PORT
      LAYER met3 ;
        RECT  2916 612.04 2920 612.64 ;
    END
  END gpio_dm2[0]
  PIN gpio_dm2[10]
    DIRECTION OUTPUT ;
    USE SIGNAL ;
    PORT
      LAYER met3 ;
        RECT  2916 666.44 2920 667.04 ;
    END
  END gpio_dm2[10]
  PIN gpio_dm2[11]
    DIRECTION OUTPUT ;
    USE SIGNAL ;
    PORT
      LAYER met3 ;
        RECT  2916 671.88 2920 672.48 ;
    END
  END gpio_dm2[11]
  PIN gpio_dm2[12]
    DIRECTION OUTPUT ;
    USE SIGNAL ;
    PORT
      LAYER met3 ;
        RECT  2916 677.32 2920 677.92 ;
    END
  END gpio_dm2[12]
  PIN gpio_dm2[13]
    DIRECTION OUTPUT ;
    USE SIGNAL ;
    PORT
      LAYER met3 ;
        RECT  2916 682.76 2920 683.36 ;
    END
  END gpio_dm2[13]
  PIN gpio_dm2[14]
    DIRECTION OUTPUT ;
    USE SIGNAL ;
    PORT
      LAYER met3 ;
        RECT  2916 688.2 2920 688.8 ;
    END
  END gpio_dm2[14]
  PIN gpio_dm2[15]
    DIRECTION OUTPUT ;
    USE SIGNAL ;
    PORT
      LAYER met3 ;
        RECT  2916 693.64 2920 694.24 ;
    END
  END gpio_dm2[15]
  PIN gpio_dm2[16]
    DIRECTION OUTPUT ;
    USE SIGNAL ;
    PORT
      LAYER met3 ;
        RECT  2916 699.08 2920 699.68 ;
    END
  END gpio_dm2[16]
  PIN gpio_dm2[17]
    DIRECTION OUTPUT ;
    USE SIGNAL ;
    PORT
      LAYER met3 ;
        RECT  2916 704.52 2920 705.12 ;
    END
  END gpio_dm2[17]
  PIN gpio_dm2[18]
    DIRECTION OUTPUT ;
    USE SIGNAL ;
    PORT
      LAYER met3 ;
        RECT  2916 709.96 2920 710.56 ;
    END
  END gpio_dm2[18]
  PIN gpio_dm2[19]
    DIRECTION OUTPUT ;
    USE SIGNAL ;
    PORT
      LAYER met3 ;
        RECT  2916 715.4 2920 716 ;
    END
  END gpio_dm2[19]
  PIN gpio_dm2[1]
    DIRECTION OUTPUT ;
    USE SIGNAL ;
    PORT
      LAYER met3 ;
        RECT  2916 617.48 2920 618.08 ;
    END
  END gpio_dm2[1]
  PIN gpio_dm2[20]
    DIRECTION OUTPUT ;
    USE SIGNAL ;
    PORT
      LAYER met3 ;
        RECT  2916 720.84 2920 721.44 ;
    END
  END gpio_dm2[20]
  PIN gpio_dm2[21]
    DIRECTION OUTPUT ;
    USE SIGNAL ;
    PORT
      LAYER met3 ;
        RECT  2916 726.28 2920 726.88 ;
    END
  END gpio_dm2[21]
  PIN gpio_dm2[22]
    DIRECTION OUTPUT ;
    USE SIGNAL ;
    PORT
      LAYER met3 ;
        RECT  2916 731.72 2920 732.32 ;
    END
  END gpio_dm2[22]
  PIN gpio_dm2[23]
    DIRECTION OUTPUT ;
    USE SIGNAL ;
    PORT
      LAYER met3 ;
        RECT  2916 737.16 2920 737.76 ;
    END
  END gpio_dm2[23]
  PIN gpio_dm2[24]
    DIRECTION OUTPUT ;
    USE SIGNAL ;
    PORT
      LAYER met3 ;
        RECT  2916 742.6 2920 743.2 ;
    END
  END gpio_dm2[24]
  PIN gpio_dm2[25]
    DIRECTION OUTPUT ;
    USE SIGNAL ;
    PORT
      LAYER met3 ;
        RECT  2916 748.04 2920 748.64 ;
    END
  END gpio_dm2[25]
  PIN gpio_dm2[26]
    DIRECTION OUTPUT ;
    USE SIGNAL ;
    PORT
      LAYER met3 ;
        RECT  2916 753.48 2920 754.08 ;
    END
  END gpio_dm2[26]
  PIN gpio_dm2[27]
    DIRECTION OUTPUT ;
    USE SIGNAL ;
    PORT
      LAYER met3 ;
        RECT  2916 758.92 2920 759.52 ;
    END
  END gpio_dm2[27]
  PIN gpio_dm2[28]
    DIRECTION OUTPUT ;
    USE SIGNAL ;
    PORT
      LAYER met3 ;
        RECT  2916 764.36 2920 764.96 ;
    END
  END gpio_dm2[28]
  PIN gpio_dm2[29]
    DIRECTION OUTPUT ;
    USE SIGNAL ;
    PORT
      LAYER met3 ;
        RECT  2916 769.8 2920 770.4 ;
    END
  END gpio_dm2[29]
  PIN gpio_dm2[2]
    DIRECTION OUTPUT ;
    USE SIGNAL ;
    PORT
      LAYER met3 ;
        RECT  2916 622.92 2920 623.52 ;
    END
  END gpio_dm2[2]
  PIN gpio_dm2[30]
    DIRECTION OUTPUT ;
    USE SIGNAL ;
    PORT
      LAYER met3 ;
        RECT  2916 775.24 2920 775.84 ;
    END
  END gpio_dm2[30]
  PIN gpio_dm2[31]
    DIRECTION OUTPUT ;
    USE SIGNAL ;
    PORT
      LAYER met3 ;
        RECT  2916 780.68 2920 781.28 ;
    END
  END gpio_dm2[31]
  PIN gpio_dm2[32]
    DIRECTION OUTPUT ;
    USE SIGNAL ;
    PORT
      LAYER met3 ;
        RECT  2916 786.12 2920 786.72 ;
    END
  END gpio_dm2[32]
  PIN gpio_dm2[33]
    DIRECTION OUTPUT ;
    USE SIGNAL ;
    PORT
      LAYER met3 ;
        RECT  2916 791.56 2920 792.16 ;
    END
  END gpio_dm2[33]
  PIN gpio_dm2[34]
    DIRECTION OUTPUT ;
    USE SIGNAL ;
    PORT
      LAYER met3 ;
        RECT  2916 797 2920 797.6 ;
    END
  END gpio_dm2[34]
  PIN gpio_dm2[35]
    DIRECTION OUTPUT ;
    USE SIGNAL ;
    PORT
      LAYER met3 ;
        RECT  2916 802.44 2920 803.04 ;
    END
  END gpio_dm2[35]
  PIN gpio_dm2[36]
    DIRECTION OUTPUT ;
    USE SIGNAL ;
    PORT
      LAYER met3 ;
        RECT  2916 807.88 2920 808.48 ;
    END
  END gpio_dm2[36]
  PIN gpio_dm2[37]
    DIRECTION OUTPUT ;
    USE SIGNAL ;
    PORT
      LAYER met3 ;
        RECT  2916 813.32 2920 813.92 ;
    END
  END gpio_dm2[37]
  PIN gpio_dm2[38]
    DIRECTION OUTPUT ;
    USE SIGNAL ;
    PORT
      LAYER met3 ;
        RECT  2916 818.76 2920 819.36 ;
    END
  END gpio_dm2[38]
  PIN gpio_dm2[39]
    DIRECTION OUTPUT ;
    USE SIGNAL ;
    PORT
      LAYER met3 ;
        RECT  2916 824.2 2920 824.8 ;
    END
  END gpio_dm2[39]
  PIN gpio_dm2[3]
    DIRECTION OUTPUT ;
    USE SIGNAL ;
    PORT
      LAYER met3 ;
        RECT  2916 628.36 2920 628.96 ;
    END
  END gpio_dm2[3]
  PIN gpio_dm2[40]
    DIRECTION OUTPUT ;
    USE SIGNAL ;
    PORT
      LAYER met3 ;
        RECT  2916 829.64 2920 830.24 ;
    END
  END gpio_dm2[40]
  PIN gpio_dm2[41]
    DIRECTION OUTPUT ;
    USE SIGNAL ;
    PORT
      LAYER met3 ;
        RECT  2916 835.08 2920 835.68 ;
    END
  END gpio_dm2[41]
  PIN gpio_dm2[42]
    DIRECTION OUTPUT ;
    USE SIGNAL ;
    PORT
      LAYER met3 ;
        RECT  2916 840.52 2920 841.12 ;
    END
  END gpio_dm2[42]
  PIN gpio_dm2[43]
    DIRECTION OUTPUT ;
    USE SIGNAL ;
    PORT
      LAYER met3 ;
        RECT  2916 845.96 2920 846.56 ;
    END
  END gpio_dm2[43]
  PIN gpio_dm2[4]
    DIRECTION OUTPUT ;
    USE SIGNAL ;
    PORT
      LAYER met3 ;
        RECT  2916 633.8 2920 634.4 ;
    END
  END gpio_dm2[4]
  PIN gpio_dm2[5]
    DIRECTION OUTPUT ;
    USE SIGNAL ;
    PORT
      LAYER met3 ;
        RECT  2916 639.24 2920 639.84 ;
    END
  END gpio_dm2[5]
  PIN gpio_dm2[6]
    DIRECTION OUTPUT ;
    USE SIGNAL ;
    PORT
      LAYER met3 ;
        RECT  2916 644.68 2920 645.28 ;
    END
  END gpio_dm2[6]
  PIN gpio_dm2[7]
    DIRECTION OUTPUT ;
    USE SIGNAL ;
    PORT
      LAYER met3 ;
        RECT  2916 650.12 2920 650.72 ;
    END
  END gpio_dm2[7]
  PIN gpio_dm2[8]
    DIRECTION OUTPUT ;
    USE SIGNAL ;
    PORT
      LAYER met3 ;
        RECT  2916 655.56 2920 656.16 ;
    END
  END gpio_dm2[8]
  PIN gpio_dm2[9]
    DIRECTION OUTPUT ;
    USE SIGNAL ;
    PORT
      LAYER met3 ;
        RECT  2916 661 2920 661.6 ;
    END
  END gpio_dm2[9]
  PIN gpio_holdover[0]
    DIRECTION OUTPUT ;
    USE SIGNAL ;
    PORT
      LAYER met3 ;
        RECT  0 1267.56 4 1268.16 ;
    END
  END gpio_holdover[0]
  PIN gpio_holdover[10]
    DIRECTION OUTPUT ;
    USE SIGNAL ;
    PORT
      LAYER met3 ;
        RECT  0 1335.56 4 1336.16 ;
    END
  END gpio_holdover[10]
  PIN gpio_holdover[11]
    DIRECTION OUTPUT ;
    USE SIGNAL ;
    PORT
      LAYER met3 ;
        RECT  0 1342.36 4 1342.96 ;
    END
  END gpio_holdover[11]
  PIN gpio_holdover[12]
    DIRECTION OUTPUT ;
    USE SIGNAL ;
    PORT
      LAYER met3 ;
        RECT  0 1349.16 4 1349.76 ;
    END
  END gpio_holdover[12]
  PIN gpio_holdover[13]
    DIRECTION OUTPUT ;
    USE SIGNAL ;
    PORT
      LAYER met3 ;
        RECT  0 1355.96 4 1356.56 ;
    END
  END gpio_holdover[13]
  PIN gpio_holdover[14]
    DIRECTION OUTPUT ;
    USE SIGNAL ;
    PORT
      LAYER met3 ;
        RECT  0 1362.76 4 1363.36 ;
    END
  END gpio_holdover[14]
  PIN gpio_holdover[15]
    DIRECTION OUTPUT ;
    USE SIGNAL ;
    PORT
      LAYER met3 ;
        RECT  0 1369.56 4 1370.16 ;
    END
  END gpio_holdover[15]
  PIN gpio_holdover[16]
    DIRECTION OUTPUT ;
    USE SIGNAL ;
    PORT
      LAYER met3 ;
        RECT  0 1376.36 4 1376.96 ;
    END
  END gpio_holdover[16]
  PIN gpio_holdover[17]
    DIRECTION OUTPUT ;
    USE SIGNAL ;
    PORT
      LAYER met3 ;
        RECT  0 1383.16 4 1383.76 ;
    END
  END gpio_holdover[17]
  PIN gpio_holdover[18]
    DIRECTION OUTPUT ;
    USE SIGNAL ;
    PORT
      LAYER met3 ;
        RECT  0 1389.96 4 1390.56 ;
    END
  END gpio_holdover[18]
  PIN gpio_holdover[19]
    DIRECTION OUTPUT ;
    USE SIGNAL ;
    PORT
      LAYER met3 ;
        RECT  0 1396.76 4 1397.36 ;
    END
  END gpio_holdover[19]
  PIN gpio_holdover[1]
    DIRECTION OUTPUT ;
    USE SIGNAL ;
    PORT
      LAYER met3 ;
        RECT  0 1274.36 4 1274.96 ;
    END
  END gpio_holdover[1]
  PIN gpio_holdover[20]
    DIRECTION OUTPUT ;
    USE SIGNAL ;
    PORT
      LAYER met3 ;
        RECT  0 1403.56 4 1404.16 ;
    END
  END gpio_holdover[20]
  PIN gpio_holdover[21]
    DIRECTION OUTPUT ;
    USE SIGNAL ;
    PORT
      LAYER met3 ;
        RECT  0 1410.36 4 1410.96 ;
    END
  END gpio_holdover[21]
  PIN gpio_holdover[22]
    DIRECTION OUTPUT ;
    USE SIGNAL ;
    PORT
      LAYER met3 ;
        RECT  0 1417.16 4 1417.76 ;
    END
  END gpio_holdover[22]
  PIN gpio_holdover[23]
    DIRECTION OUTPUT ;
    USE SIGNAL ;
    PORT
      LAYER met3 ;
        RECT  0 1423.96 4 1424.56 ;
    END
  END gpio_holdover[23]
  PIN gpio_holdover[24]
    DIRECTION OUTPUT ;
    USE SIGNAL ;
    PORT
      LAYER met3 ;
        RECT  0 1430.76 4 1431.36 ;
    END
  END gpio_holdover[24]
  PIN gpio_holdover[25]
    DIRECTION OUTPUT ;
    USE SIGNAL ;
    PORT
      LAYER met3 ;
        RECT  0 1437.56 4 1438.16 ;
    END
  END gpio_holdover[25]
  PIN gpio_holdover[26]
    DIRECTION OUTPUT ;
    USE SIGNAL ;
    PORT
      LAYER met3 ;
        RECT  0 1444.36 4 1444.96 ;
    END
  END gpio_holdover[26]
  PIN gpio_holdover[27]
    DIRECTION OUTPUT ;
    USE SIGNAL ;
    PORT
      LAYER met3 ;
        RECT  0 1451.16 4 1451.76 ;
    END
  END gpio_holdover[27]
  PIN gpio_holdover[28]
    DIRECTION OUTPUT ;
    USE SIGNAL ;
    PORT
      LAYER met3 ;
        RECT  0 1457.96 4 1458.56 ;
    END
  END gpio_holdover[28]
  PIN gpio_holdover[29]
    DIRECTION OUTPUT ;
    USE SIGNAL ;
    PORT
      LAYER met3 ;
        RECT  0 1464.76 4 1465.36 ;
    END
  END gpio_holdover[29]
  PIN gpio_holdover[2]
    DIRECTION OUTPUT ;
    USE SIGNAL ;
    PORT
      LAYER met3 ;
        RECT  0 1281.16 4 1281.76 ;
    END
  END gpio_holdover[2]
  PIN gpio_holdover[30]
    DIRECTION OUTPUT ;
    USE SIGNAL ;
    PORT
      LAYER met3 ;
        RECT  0 1471.56 4 1472.16 ;
    END
  END gpio_holdover[30]
  PIN gpio_holdover[31]
    DIRECTION OUTPUT ;
    USE SIGNAL ;
    PORT
      LAYER met3 ;
        RECT  0 1478.36 4 1478.96 ;
    END
  END gpio_holdover[31]
  PIN gpio_holdover[32]
    DIRECTION OUTPUT ;
    USE SIGNAL ;
    PORT
      LAYER met3 ;
        RECT  0 1485.16 4 1485.76 ;
    END
  END gpio_holdover[32]
  PIN gpio_holdover[33]
    DIRECTION OUTPUT ;
    USE SIGNAL ;
    PORT
      LAYER met3 ;
        RECT  0 1491.96 4 1492.56 ;
    END
  END gpio_holdover[33]
  PIN gpio_holdover[34]
    DIRECTION OUTPUT ;
    USE SIGNAL ;
    PORT
      LAYER met3 ;
        RECT  0 1498.76 4 1499.36 ;
    END
  END gpio_holdover[34]
  PIN gpio_holdover[35]
    DIRECTION OUTPUT ;
    USE SIGNAL ;
    PORT
      LAYER met3 ;
        RECT  0 1505.56 4 1506.16 ;
    END
  END gpio_holdover[35]
  PIN gpio_holdover[36]
    DIRECTION OUTPUT ;
    USE SIGNAL ;
    PORT
      LAYER met3 ;
        RECT  0 1512.36 4 1512.96 ;
    END
  END gpio_holdover[36]
  PIN gpio_holdover[37]
    DIRECTION OUTPUT ;
    USE SIGNAL ;
    PORT
      LAYER met3 ;
        RECT  0 1519.16 4 1519.76 ;
    END
  END gpio_holdover[37]
  PIN gpio_holdover[38]
    DIRECTION OUTPUT ;
    USE SIGNAL ;
    PORT
      LAYER met3 ;
        RECT  0 1525.96 4 1526.56 ;
    END
  END gpio_holdover[38]
  PIN gpio_holdover[39]
    DIRECTION OUTPUT ;
    USE SIGNAL ;
    PORT
      LAYER met3 ;
        RECT  0 1532.76 4 1533.36 ;
    END
  END gpio_holdover[39]
  PIN gpio_holdover[3]
    DIRECTION OUTPUT ;
    USE SIGNAL ;
    PORT
      LAYER met3 ;
        RECT  0 1287.96 4 1288.56 ;
    END
  END gpio_holdover[3]
  PIN gpio_holdover[40]
    DIRECTION OUTPUT ;
    USE SIGNAL ;
    PORT
      LAYER met3 ;
        RECT  0 1539.56 4 1540.16 ;
    END
  END gpio_holdover[40]
  PIN gpio_holdover[41]
    DIRECTION OUTPUT ;
    USE SIGNAL ;
    PORT
      LAYER met3 ;
        RECT  0 1546.36 4 1546.96 ;
    END
  END gpio_holdover[41]
  PIN gpio_holdover[42]
    DIRECTION OUTPUT ;
    USE SIGNAL ;
    PORT
      LAYER met3 ;
        RECT  0 1553.16 4 1553.76 ;
    END
  END gpio_holdover[42]
  PIN gpio_holdover[43]
    DIRECTION OUTPUT ;
    USE SIGNAL ;
    PORT
      LAYER met3 ;
        RECT  0 1559.96 4 1560.56 ;
    END
  END gpio_holdover[43]
  PIN gpio_holdover[4]
    DIRECTION OUTPUT ;
    USE SIGNAL ;
    PORT
      LAYER met3 ;
        RECT  0 1294.76 4 1295.36 ;
    END
  END gpio_holdover[4]
  PIN gpio_holdover[5]
    DIRECTION OUTPUT ;
    USE SIGNAL ;
    PORT
      LAYER met3 ;
        RECT  0 1301.56 4 1302.16 ;
    END
  END gpio_holdover[5]
  PIN gpio_holdover[6]
    DIRECTION OUTPUT ;
    USE SIGNAL ;
    PORT
      LAYER met3 ;
        RECT  0 1308.36 4 1308.96 ;
    END
  END gpio_holdover[6]
  PIN gpio_holdover[7]
    DIRECTION OUTPUT ;
    USE SIGNAL ;
    PORT
      LAYER met3 ;
        RECT  0 1315.16 4 1315.76 ;
    END
  END gpio_holdover[7]
  PIN gpio_holdover[8]
    DIRECTION OUTPUT ;
    USE SIGNAL ;
    PORT
      LAYER met3 ;
        RECT  0 1321.96 4 1322.56 ;
    END
  END gpio_holdover[8]
  PIN gpio_holdover[9]
    DIRECTION OUTPUT ;
    USE SIGNAL ;
    PORT
      LAYER met3 ;
        RECT  0 1328.76 4 1329.36 ;
    END
  END gpio_holdover[9]
  PIN gpio_ib_mode_sel[0]
    DIRECTION OUTPUT ;
    USE SIGNAL ;
    PORT
      LAYER met3 ;
        RECT  0 369.96 4 370.56 ;
    END
  END gpio_ib_mode_sel[0]
  PIN gpio_ib_mode_sel[10]
    DIRECTION OUTPUT ;
    USE SIGNAL ;
    PORT
      LAYER met3 ;
        RECT  0 437.96 4 438.56 ;
    END
  END gpio_ib_mode_sel[10]
  PIN gpio_ib_mode_sel[11]
    DIRECTION OUTPUT ;
    USE SIGNAL ;
    PORT
      LAYER met3 ;
        RECT  0 444.76 4 445.36 ;
    END
  END gpio_ib_mode_sel[11]
  PIN gpio_ib_mode_sel[12]
    DIRECTION OUTPUT ;
    USE SIGNAL ;
    PORT
      LAYER met3 ;
        RECT  0 451.56 4 452.16 ;
    END
  END gpio_ib_mode_sel[12]
  PIN gpio_ib_mode_sel[13]
    DIRECTION OUTPUT ;
    USE SIGNAL ;
    PORT
      LAYER met3 ;
        RECT  0 458.36 4 458.96 ;
    END
  END gpio_ib_mode_sel[13]
  PIN gpio_ib_mode_sel[14]
    DIRECTION OUTPUT ;
    USE SIGNAL ;
    PORT
      LAYER met3 ;
        RECT  0 465.16 4 465.76 ;
    END
  END gpio_ib_mode_sel[14]
  PIN gpio_ib_mode_sel[15]
    DIRECTION OUTPUT ;
    USE SIGNAL ;
    PORT
      LAYER met3 ;
        RECT  0 471.96 4 472.56 ;
    END
  END gpio_ib_mode_sel[15]
  PIN gpio_ib_mode_sel[16]
    DIRECTION OUTPUT ;
    USE SIGNAL ;
    PORT
      LAYER met3 ;
        RECT  0 478.76 4 479.36 ;
    END
  END gpio_ib_mode_sel[16]
  PIN gpio_ib_mode_sel[17]
    DIRECTION OUTPUT ;
    USE SIGNAL ;
    PORT
      LAYER met3 ;
        RECT  0 485.56 4 486.16 ;
    END
  END gpio_ib_mode_sel[17]
  PIN gpio_ib_mode_sel[18]
    DIRECTION OUTPUT ;
    USE SIGNAL ;
    PORT
      LAYER met3 ;
        RECT  0 492.36 4 492.96 ;
    END
  END gpio_ib_mode_sel[18]
  PIN gpio_ib_mode_sel[19]
    DIRECTION OUTPUT ;
    USE SIGNAL ;
    PORT
      LAYER met3 ;
        RECT  0 499.16 4 499.76 ;
    END
  END gpio_ib_mode_sel[19]
  PIN gpio_ib_mode_sel[1]
    DIRECTION OUTPUT ;
    USE SIGNAL ;
    PORT
      LAYER met3 ;
        RECT  0 376.76 4 377.36 ;
    END
  END gpio_ib_mode_sel[1]
  PIN gpio_ib_mode_sel[20]
    DIRECTION OUTPUT ;
    USE SIGNAL ;
    PORT
      LAYER met3 ;
        RECT  0 505.96 4 506.56 ;
    END
  END gpio_ib_mode_sel[20]
  PIN gpio_ib_mode_sel[21]
    DIRECTION OUTPUT ;
    USE SIGNAL ;
    PORT
      LAYER met3 ;
        RECT  0 512.76 4 513.36 ;
    END
  END gpio_ib_mode_sel[21]
  PIN gpio_ib_mode_sel[22]
    DIRECTION OUTPUT ;
    USE SIGNAL ;
    PORT
      LAYER met3 ;
        RECT  0 519.56 4 520.16 ;
    END
  END gpio_ib_mode_sel[22]
  PIN gpio_ib_mode_sel[23]
    DIRECTION OUTPUT ;
    USE SIGNAL ;
    PORT
      LAYER met3 ;
        RECT  0 526.36 4 526.96 ;
    END
  END gpio_ib_mode_sel[23]
  PIN gpio_ib_mode_sel[24]
    DIRECTION OUTPUT ;
    USE SIGNAL ;
    PORT
      LAYER met3 ;
        RECT  0 533.16 4 533.76 ;
    END
  END gpio_ib_mode_sel[24]
  PIN gpio_ib_mode_sel[25]
    DIRECTION OUTPUT ;
    USE SIGNAL ;
    PORT
      LAYER met3 ;
        RECT  0 539.96 4 540.56 ;
    END
  END gpio_ib_mode_sel[25]
  PIN gpio_ib_mode_sel[26]
    DIRECTION OUTPUT ;
    USE SIGNAL ;
    PORT
      LAYER met3 ;
        RECT  0 546.76 4 547.36 ;
    END
  END gpio_ib_mode_sel[26]
  PIN gpio_ib_mode_sel[27]
    DIRECTION OUTPUT ;
    USE SIGNAL ;
    PORT
      LAYER met3 ;
        RECT  0 553.56 4 554.16 ;
    END
  END gpio_ib_mode_sel[27]
  PIN gpio_ib_mode_sel[28]
    DIRECTION OUTPUT ;
    USE SIGNAL ;
    PORT
      LAYER met3 ;
        RECT  0 560.36 4 560.96 ;
    END
  END gpio_ib_mode_sel[28]
  PIN gpio_ib_mode_sel[29]
    DIRECTION OUTPUT ;
    USE SIGNAL ;
    PORT
      LAYER met3 ;
        RECT  0 567.16 4 567.76 ;
    END
  END gpio_ib_mode_sel[29]
  PIN gpio_ib_mode_sel[2]
    DIRECTION OUTPUT ;
    USE SIGNAL ;
    PORT
      LAYER met3 ;
        RECT  0 383.56 4 384.16 ;
    END
  END gpio_ib_mode_sel[2]
  PIN gpio_ib_mode_sel[30]
    DIRECTION OUTPUT ;
    USE SIGNAL ;
    PORT
      LAYER met3 ;
        RECT  0 573.96 4 574.56 ;
    END
  END gpio_ib_mode_sel[30]
  PIN gpio_ib_mode_sel[31]
    DIRECTION OUTPUT ;
    USE SIGNAL ;
    PORT
      LAYER met3 ;
        RECT  0 580.76 4 581.36 ;
    END
  END gpio_ib_mode_sel[31]
  PIN gpio_ib_mode_sel[32]
    DIRECTION OUTPUT ;
    USE SIGNAL ;
    PORT
      LAYER met3 ;
        RECT  0 587.56 4 588.16 ;
    END
  END gpio_ib_mode_sel[32]
  PIN gpio_ib_mode_sel[33]
    DIRECTION OUTPUT ;
    USE SIGNAL ;
    PORT
      LAYER met3 ;
        RECT  0 594.36 4 594.96 ;
    END
  END gpio_ib_mode_sel[33]
  PIN gpio_ib_mode_sel[34]
    DIRECTION OUTPUT ;
    USE SIGNAL ;
    PORT
      LAYER met3 ;
        RECT  0 601.16 4 601.76 ;
    END
  END gpio_ib_mode_sel[34]
  PIN gpio_ib_mode_sel[35]
    DIRECTION OUTPUT ;
    USE SIGNAL ;
    PORT
      LAYER met3 ;
        RECT  0 607.96 4 608.56 ;
    END
  END gpio_ib_mode_sel[35]
  PIN gpio_ib_mode_sel[36]
    DIRECTION OUTPUT ;
    USE SIGNAL ;
    PORT
      LAYER met3 ;
        RECT  0 614.76 4 615.36 ;
    END
  END gpio_ib_mode_sel[36]
  PIN gpio_ib_mode_sel[37]
    DIRECTION OUTPUT ;
    USE SIGNAL ;
    PORT
      LAYER met3 ;
        RECT  0 621.56 4 622.16 ;
    END
  END gpio_ib_mode_sel[37]
  PIN gpio_ib_mode_sel[38]
    DIRECTION OUTPUT ;
    USE SIGNAL ;
    PORT
      LAYER met3 ;
        RECT  0 628.36 4 628.96 ;
    END
  END gpio_ib_mode_sel[38]
  PIN gpio_ib_mode_sel[39]
    DIRECTION OUTPUT ;
    USE SIGNAL ;
    PORT
      LAYER met3 ;
        RECT  0 635.16 4 635.76 ;
    END
  END gpio_ib_mode_sel[39]
  PIN gpio_ib_mode_sel[3]
    DIRECTION OUTPUT ;
    USE SIGNAL ;
    PORT
      LAYER met3 ;
        RECT  0 390.36 4 390.96 ;
    END
  END gpio_ib_mode_sel[3]
  PIN gpio_ib_mode_sel[40]
    DIRECTION OUTPUT ;
    USE SIGNAL ;
    PORT
      LAYER met3 ;
        RECT  0 641.96 4 642.56 ;
    END
  END gpio_ib_mode_sel[40]
  PIN gpio_ib_mode_sel[41]
    DIRECTION OUTPUT ;
    USE SIGNAL ;
    PORT
      LAYER met3 ;
        RECT  0 648.76 4 649.36 ;
    END
  END gpio_ib_mode_sel[41]
  PIN gpio_ib_mode_sel[42]
    DIRECTION OUTPUT ;
    USE SIGNAL ;
    PORT
      LAYER met3 ;
        RECT  0 655.56 4 656.16 ;
    END
  END gpio_ib_mode_sel[42]
  PIN gpio_ib_mode_sel[43]
    DIRECTION OUTPUT ;
    USE SIGNAL ;
    PORT
      LAYER met3 ;
        RECT  0 662.36 4 662.96 ;
    END
  END gpio_ib_mode_sel[43]
  PIN gpio_ib_mode_sel[4]
    DIRECTION OUTPUT ;
    USE SIGNAL ;
    PORT
      LAYER met3 ;
        RECT  0 397.16 4 397.76 ;
    END
  END gpio_ib_mode_sel[4]
  PIN gpio_ib_mode_sel[5]
    DIRECTION OUTPUT ;
    USE SIGNAL ;
    PORT
      LAYER met3 ;
        RECT  0 403.96 4 404.56 ;
    END
  END gpio_ib_mode_sel[5]
  PIN gpio_ib_mode_sel[6]
    DIRECTION OUTPUT ;
    USE SIGNAL ;
    PORT
      LAYER met3 ;
        RECT  0 410.76 4 411.36 ;
    END
  END gpio_ib_mode_sel[6]
  PIN gpio_ib_mode_sel[7]
    DIRECTION OUTPUT ;
    USE SIGNAL ;
    PORT
      LAYER met3 ;
        RECT  0 417.56 4 418.16 ;
    END
  END gpio_ib_mode_sel[7]
  PIN gpio_ib_mode_sel[8]
    DIRECTION OUTPUT ;
    USE SIGNAL ;
    PORT
      LAYER met3 ;
        RECT  0 424.36 4 424.96 ;
    END
  END gpio_ib_mode_sel[8]
  PIN gpio_ib_mode_sel[9]
    DIRECTION OUTPUT ;
    USE SIGNAL ;
    PORT
      LAYER met3 ;
        RECT  0 431.16 4 431.76 ;
    END
  END gpio_ib_mode_sel[9]
  PIN gpio_in[0]
    DIRECTION INPUT ;
    USE SIGNAL ;
    PORT
      LAYER met2 ;
        RECT  18.95 0 19.23 4 ;
    END
  END gpio_in[0]
  PIN gpio_in[10]
    DIRECTION INPUT ;
    USE SIGNAL ;
    PORT
      LAYER met2 ;
        RECT  350.15 0 350.43 4 ;
    END
  END gpio_in[10]
  PIN gpio_in[11]
    DIRECTION INPUT ;
    USE SIGNAL ;
    PORT
      LAYER met2 ;
        RECT  383.27 0 383.55 4 ;
    END
  END gpio_in[11]
  PIN gpio_in[12]
    DIRECTION INPUT ;
    USE SIGNAL ;
    PORT
      LAYER met2 ;
        RECT  416.39 0 416.67 4 ;
    END
  END gpio_in[12]
  PIN gpio_in[13]
    DIRECTION INPUT ;
    USE SIGNAL ;
    PORT
      LAYER met2 ;
        RECT  449.51 0 449.79 4 ;
    END
  END gpio_in[13]
  PIN gpio_in[14]
    DIRECTION INPUT ;
    USE SIGNAL ;
    PORT
      LAYER met2 ;
        RECT  482.63 0 482.91 4 ;
    END
  END gpio_in[14]
  PIN gpio_in[15]
    DIRECTION INPUT ;
    USE SIGNAL ;
    PORT
      LAYER met2 ;
        RECT  515.75 0 516.03 4 ;
    END
  END gpio_in[15]
  PIN gpio_in[16]
    DIRECTION INPUT ;
    USE SIGNAL ;
    PORT
      LAYER met2 ;
        RECT  548.87 0 549.15 4 ;
    END
  END gpio_in[16]
  PIN gpio_in[17]
    DIRECTION INPUT ;
    USE SIGNAL ;
    PORT
      LAYER met2 ;
        RECT  581.99 0 582.27 4 ;
    END
  END gpio_in[17]
  PIN gpio_in[18]
    DIRECTION INPUT ;
    USE SIGNAL ;
    PORT
      LAYER met2 ;
        RECT  615.11 0 615.39 4 ;
    END
  END gpio_in[18]
  PIN gpio_in[19]
    DIRECTION INPUT ;
    USE SIGNAL ;
    PORT
      LAYER met2 ;
        RECT  648.23 0 648.51 4 ;
    END
  END gpio_in[19]
  PIN gpio_in[1]
    DIRECTION INPUT ;
    USE SIGNAL ;
    PORT
      LAYER met2 ;
        RECT  52.07 0 52.35 4 ;
    END
  END gpio_in[1]
  PIN gpio_in[20]
    DIRECTION INPUT ;
    USE SIGNAL ;
    PORT
      LAYER met2 ;
        RECT  681.35 0 681.63 4 ;
    END
  END gpio_in[20]
  PIN gpio_in[21]
    DIRECTION INPUT ;
    USE SIGNAL ;
    PORT
      LAYER met2 ;
        RECT  714.47 0 714.75 4 ;
    END
  END gpio_in[21]
  PIN gpio_in[22]
    DIRECTION INPUT ;
    USE SIGNAL ;
    PORT
      LAYER met2 ;
        RECT  747.59 0 747.87 4 ;
    END
  END gpio_in[22]
  PIN gpio_in[23]
    DIRECTION INPUT ;
    USE SIGNAL ;
    PORT
      LAYER met2 ;
        RECT  780.71 0 780.99 4 ;
    END
  END gpio_in[23]
  PIN gpio_in[24]
    DIRECTION INPUT ;
    USE SIGNAL ;
    PORT
      LAYER met2 ;
        RECT  813.83 0 814.11 4 ;
    END
  END gpio_in[24]
  PIN gpio_in[25]
    DIRECTION INPUT ;
    USE SIGNAL ;
    PORT
      LAYER met2 ;
        RECT  846.95 0 847.23 4 ;
    END
  END gpio_in[25]
  PIN gpio_in[26]
    DIRECTION INPUT ;
    USE SIGNAL ;
    PORT
      LAYER met2 ;
        RECT  880.07 0 880.35 4 ;
    END
  END gpio_in[26]
  PIN gpio_in[27]
    DIRECTION INPUT ;
    USE SIGNAL ;
    PORT
      LAYER met2 ;
        RECT  913.19 0 913.47 4 ;
    END
  END gpio_in[27]
  PIN gpio_in[28]
    DIRECTION INPUT ;
    USE SIGNAL ;
    PORT
      LAYER met2 ;
        RECT  946.31 0 946.59 4 ;
    END
  END gpio_in[28]
  PIN gpio_in[29]
    DIRECTION INPUT ;
    USE SIGNAL ;
    PORT
      LAYER met2 ;
        RECT  979.43 0 979.71 4 ;
    END
  END gpio_in[29]
  PIN gpio_in[2]
    DIRECTION INPUT ;
    USE SIGNAL ;
    PORT
      LAYER met2 ;
        RECT  85.19 0 85.47 4 ;
    END
  END gpio_in[2]
  PIN gpio_in[30]
    DIRECTION INPUT ;
    USE SIGNAL ;
    PORT
      LAYER met2 ;
        RECT  1012.55 0 1012.83 4 ;
    END
  END gpio_in[30]
  PIN gpio_in[31]
    DIRECTION INPUT ;
    USE SIGNAL ;
    PORT
      LAYER met2 ;
        RECT  1045.67 0 1045.95 4 ;
    END
  END gpio_in[31]
  PIN gpio_in[32]
    DIRECTION INPUT ;
    USE SIGNAL ;
    PORT
      LAYER met2 ;
        RECT  1078.79 0 1079.07 4 ;
    END
  END gpio_in[32]
  PIN gpio_in[33]
    DIRECTION INPUT ;
    USE SIGNAL ;
    PORT
      LAYER met2 ;
        RECT  1111.91 0 1112.19 4 ;
    END
  END gpio_in[33]
  PIN gpio_in[34]
    DIRECTION INPUT ;
    USE SIGNAL ;
    PORT
      LAYER met2 ;
        RECT  1145.03 0 1145.31 4 ;
    END
  END gpio_in[34]
  PIN gpio_in[35]
    DIRECTION INPUT ;
    USE SIGNAL ;
    PORT
      LAYER met2 ;
        RECT  1178.15 0 1178.43 4 ;
    END
  END gpio_in[35]
  PIN gpio_in[36]
    DIRECTION INPUT ;
    USE SIGNAL ;
    PORT
      LAYER met2 ;
        RECT  1211.27 0 1211.55 4 ;
    END
  END gpio_in[36]
  PIN gpio_in[37]
    DIRECTION INPUT ;
    USE SIGNAL ;
    PORT
      LAYER met2 ;
        RECT  1244.39 0 1244.67 4 ;
    END
  END gpio_in[37]
  PIN gpio_in[38]
    DIRECTION INPUT ;
    USE SIGNAL ;
    PORT
      LAYER met2 ;
        RECT  1277.51 0 1277.79 4 ;
    END
  END gpio_in[38]
  PIN gpio_in[39]
    DIRECTION INPUT ;
    USE SIGNAL ;
    PORT
      LAYER met2 ;
        RECT  1310.63 0 1310.91 4 ;
    END
  END gpio_in[39]
  PIN gpio_in[3]
    DIRECTION INPUT ;
    USE SIGNAL ;
    PORT
      LAYER met2 ;
        RECT  118.31 0 118.59 4 ;
    END
  END gpio_in[3]
  PIN gpio_in[40]
    DIRECTION INPUT ;
    USE SIGNAL ;
    PORT
      LAYER met2 ;
        RECT  1343.75 0 1344.03 4 ;
    END
  END gpio_in[40]
  PIN gpio_in[41]
    DIRECTION INPUT ;
    USE SIGNAL ;
    PORT
      LAYER met2 ;
        RECT  1376.87 0 1377.15 4 ;
    END
  END gpio_in[41]
  PIN gpio_in[42]
    DIRECTION INPUT ;
    USE SIGNAL ;
    PORT
      LAYER met2 ;
        RECT  1409.99 0 1410.27 4 ;
    END
  END gpio_in[42]
  PIN gpio_in[43]
    DIRECTION INPUT ;
    USE SIGNAL ;
    PORT
      LAYER met2 ;
        RECT  1443.11 0 1443.39 4 ;
    END
  END gpio_in[43]
  PIN gpio_in[4]
    DIRECTION INPUT ;
    USE SIGNAL ;
    PORT
      LAYER met2 ;
        RECT  151.43 0 151.71 4 ;
    END
  END gpio_in[4]
  PIN gpio_in[5]
    DIRECTION INPUT ;
    USE SIGNAL ;
    PORT
      LAYER met2 ;
        RECT  184.55 0 184.83 4 ;
    END
  END gpio_in[5]
  PIN gpio_in[6]
    DIRECTION INPUT ;
    USE SIGNAL ;
    PORT
      LAYER met2 ;
        RECT  217.67 0 217.95 4 ;
    END
  END gpio_in[6]
  PIN gpio_in[7]
    DIRECTION INPUT ;
    USE SIGNAL ;
    PORT
      LAYER met2 ;
        RECT  250.79 0 251.07 4 ;
    END
  END gpio_in[7]
  PIN gpio_in[8]
    DIRECTION INPUT ;
    USE SIGNAL ;
    PORT
      LAYER met2 ;
        RECT  283.91 0 284.19 4 ;
    END
  END gpio_in[8]
  PIN gpio_in[9]
    DIRECTION INPUT ;
    USE SIGNAL ;
    PORT
      LAYER met2 ;
        RECT  317.03 0 317.31 4 ;
    END
  END gpio_in[9]
  PIN gpio_inp_dis[0]
    DIRECTION OUTPUT ;
    USE SIGNAL ;
    PORT
      LAYER met2 ;
        RECT  1476.23 0 1476.51 4 ;
    END
  END gpio_inp_dis[0]
  PIN gpio_inp_dis[10]
    DIRECTION OUTPUT ;
    USE SIGNAL ;
    PORT
      LAYER met2 ;
        RECT  1807.43 0 1807.71 4 ;
    END
  END gpio_inp_dis[10]
  PIN gpio_inp_dis[11]
    DIRECTION OUTPUT ;
    USE SIGNAL ;
    PORT
      LAYER met2 ;
        RECT  1840.55 0 1840.83 4 ;
    END
  END gpio_inp_dis[11]
  PIN gpio_inp_dis[12]
    DIRECTION OUTPUT ;
    USE SIGNAL ;
    PORT
      LAYER met2 ;
        RECT  1873.67 0 1873.95 4 ;
    END
  END gpio_inp_dis[12]
  PIN gpio_inp_dis[13]
    DIRECTION OUTPUT ;
    USE SIGNAL ;
    PORT
      LAYER met2 ;
        RECT  1906.79 0 1907.07 4 ;
    END
  END gpio_inp_dis[13]
  PIN gpio_inp_dis[14]
    DIRECTION OUTPUT ;
    USE SIGNAL ;
    PORT
      LAYER met2 ;
        RECT  1939.91 0 1940.19 4 ;
    END
  END gpio_inp_dis[14]
  PIN gpio_inp_dis[15]
    DIRECTION OUTPUT ;
    USE SIGNAL ;
    PORT
      LAYER met2 ;
        RECT  1973.03 0 1973.31 4 ;
    END
  END gpio_inp_dis[15]
  PIN gpio_inp_dis[16]
    DIRECTION OUTPUT ;
    USE SIGNAL ;
    PORT
      LAYER met2 ;
        RECT  2006.15 0 2006.43 4 ;
    END
  END gpio_inp_dis[16]
  PIN gpio_inp_dis[17]
    DIRECTION OUTPUT ;
    USE SIGNAL ;
    PORT
      LAYER met2 ;
        RECT  2039.27 0 2039.55 4 ;
    END
  END gpio_inp_dis[17]
  PIN gpio_inp_dis[18]
    DIRECTION OUTPUT ;
    USE SIGNAL ;
    PORT
      LAYER met2 ;
        RECT  2072.39 0 2072.67 4 ;
    END
  END gpio_inp_dis[18]
  PIN gpio_inp_dis[19]
    DIRECTION OUTPUT ;
    USE SIGNAL ;
    PORT
      LAYER met2 ;
        RECT  2105.51 0 2105.79 4 ;
    END
  END gpio_inp_dis[19]
  PIN gpio_inp_dis[1]
    DIRECTION OUTPUT ;
    USE SIGNAL ;
    PORT
      LAYER met2 ;
        RECT  1509.35 0 1509.63 4 ;
    END
  END gpio_inp_dis[1]
  PIN gpio_inp_dis[20]
    DIRECTION OUTPUT ;
    USE SIGNAL ;
    PORT
      LAYER met2 ;
        RECT  2138.63 0 2138.91 4 ;
    END
  END gpio_inp_dis[20]
  PIN gpio_inp_dis[21]
    DIRECTION OUTPUT ;
    USE SIGNAL ;
    PORT
      LAYER met2 ;
        RECT  2171.75 0 2172.03 4 ;
    END
  END gpio_inp_dis[21]
  PIN gpio_inp_dis[22]
    DIRECTION OUTPUT ;
    USE SIGNAL ;
    PORT
      LAYER met2 ;
        RECT  2204.87 0 2205.15 4 ;
    END
  END gpio_inp_dis[22]
  PIN gpio_inp_dis[23]
    DIRECTION OUTPUT ;
    USE SIGNAL ;
    PORT
      LAYER met2 ;
        RECT  2237.99 0 2238.27 4 ;
    END
  END gpio_inp_dis[23]
  PIN gpio_inp_dis[24]
    DIRECTION OUTPUT ;
    USE SIGNAL ;
    PORT
      LAYER met2 ;
        RECT  2271.11 0 2271.39 4 ;
    END
  END gpio_inp_dis[24]
  PIN gpio_inp_dis[25]
    DIRECTION OUTPUT ;
    USE SIGNAL ;
    PORT
      LAYER met2 ;
        RECT  2304.23 0 2304.51 4 ;
    END
  END gpio_inp_dis[25]
  PIN gpio_inp_dis[26]
    DIRECTION OUTPUT ;
    USE SIGNAL ;
    PORT
      LAYER met2 ;
        RECT  2337.35 0 2337.63 4 ;
    END
  END gpio_inp_dis[26]
  PIN gpio_inp_dis[27]
    DIRECTION OUTPUT ;
    USE SIGNAL ;
    PORT
      LAYER met2 ;
        RECT  2370.47 0 2370.75 4 ;
    END
  END gpio_inp_dis[27]
  PIN gpio_inp_dis[28]
    DIRECTION OUTPUT ;
    USE SIGNAL ;
    PORT
      LAYER met2 ;
        RECT  2403.59 0 2403.87 4 ;
    END
  END gpio_inp_dis[28]
  PIN gpio_inp_dis[29]
    DIRECTION OUTPUT ;
    USE SIGNAL ;
    PORT
      LAYER met2 ;
        RECT  2436.71 0 2436.99 4 ;
    END
  END gpio_inp_dis[29]
  PIN gpio_inp_dis[2]
    DIRECTION OUTPUT ;
    USE SIGNAL ;
    PORT
      LAYER met2 ;
        RECT  1542.47 0 1542.75 4 ;
    END
  END gpio_inp_dis[2]
  PIN gpio_inp_dis[30]
    DIRECTION OUTPUT ;
    USE SIGNAL ;
    PORT
      LAYER met2 ;
        RECT  2469.83 0 2470.11 4 ;
    END
  END gpio_inp_dis[30]
  PIN gpio_inp_dis[31]
    DIRECTION OUTPUT ;
    USE SIGNAL ;
    PORT
      LAYER met2 ;
        RECT  2502.95 0 2503.23 4 ;
    END
  END gpio_inp_dis[31]
  PIN gpio_inp_dis[32]
    DIRECTION OUTPUT ;
    USE SIGNAL ;
    PORT
      LAYER met2 ;
        RECT  2536.07 0 2536.35 4 ;
    END
  END gpio_inp_dis[32]
  PIN gpio_inp_dis[33]
    DIRECTION OUTPUT ;
    USE SIGNAL ;
    PORT
      LAYER met2 ;
        RECT  2569.19 0 2569.47 4 ;
    END
  END gpio_inp_dis[33]
  PIN gpio_inp_dis[34]
    DIRECTION OUTPUT ;
    USE SIGNAL ;
    PORT
      LAYER met2 ;
        RECT  2602.31 0 2602.59 4 ;
    END
  END gpio_inp_dis[34]
  PIN gpio_inp_dis[35]
    DIRECTION OUTPUT ;
    USE SIGNAL ;
    PORT
      LAYER met2 ;
        RECT  2635.43 0 2635.71 4 ;
    END
  END gpio_inp_dis[35]
  PIN gpio_inp_dis[36]
    DIRECTION OUTPUT ;
    USE SIGNAL ;
    PORT
      LAYER met2 ;
        RECT  2668.55 0 2668.83 4 ;
    END
  END gpio_inp_dis[36]
  PIN gpio_inp_dis[37]
    DIRECTION OUTPUT ;
    USE SIGNAL ;
    PORT
      LAYER met2 ;
        RECT  2701.67 0 2701.95 4 ;
    END
  END gpio_inp_dis[37]
  PIN gpio_inp_dis[38]
    DIRECTION OUTPUT ;
    USE SIGNAL ;
    PORT
      LAYER met2 ;
        RECT  2734.79 0 2735.07 4 ;
    END
  END gpio_inp_dis[38]
  PIN gpio_inp_dis[39]
    DIRECTION OUTPUT ;
    USE SIGNAL ;
    PORT
      LAYER met2 ;
        RECT  2767.91 0 2768.19 4 ;
    END
  END gpio_inp_dis[39]
  PIN gpio_inp_dis[3]
    DIRECTION OUTPUT ;
    USE SIGNAL ;
    PORT
      LAYER met2 ;
        RECT  1575.59 0 1575.87 4 ;
    END
  END gpio_inp_dis[3]
  PIN gpio_inp_dis[40]
    DIRECTION OUTPUT ;
    USE SIGNAL ;
    PORT
      LAYER met2 ;
        RECT  2801.03 0 2801.31 4 ;
    END
  END gpio_inp_dis[40]
  PIN gpio_inp_dis[41]
    DIRECTION OUTPUT ;
    USE SIGNAL ;
    PORT
      LAYER met2 ;
        RECT  2834.15 0 2834.43 4 ;
    END
  END gpio_inp_dis[41]
  PIN gpio_inp_dis[42]
    DIRECTION OUTPUT ;
    USE SIGNAL ;
    PORT
      LAYER met2 ;
        RECT  2867.27 0 2867.55 4 ;
    END
  END gpio_inp_dis[42]
  PIN gpio_inp_dis[43]
    DIRECTION OUTPUT ;
    USE SIGNAL ;
    PORT
      LAYER met2 ;
        RECT  2900.39 0 2900.67 4 ;
    END
  END gpio_inp_dis[43]
  PIN gpio_inp_dis[4]
    DIRECTION OUTPUT ;
    USE SIGNAL ;
    PORT
      LAYER met2 ;
        RECT  1608.71 0 1608.99 4 ;
    END
  END gpio_inp_dis[4]
  PIN gpio_inp_dis[5]
    DIRECTION OUTPUT ;
    USE SIGNAL ;
    PORT
      LAYER met2 ;
        RECT  1641.83 0 1642.11 4 ;
    END
  END gpio_inp_dis[5]
  PIN gpio_inp_dis[6]
    DIRECTION OUTPUT ;
    USE SIGNAL ;
    PORT
      LAYER met2 ;
        RECT  1674.95 0 1675.23 4 ;
    END
  END gpio_inp_dis[6]
  PIN gpio_inp_dis[7]
    DIRECTION OUTPUT ;
    USE SIGNAL ;
    PORT
      LAYER met2 ;
        RECT  1708.07 0 1708.35 4 ;
    END
  END gpio_inp_dis[7]
  PIN gpio_inp_dis[8]
    DIRECTION OUTPUT ;
    USE SIGNAL ;
    PORT
      LAYER met2 ;
        RECT  1741.19 0 1741.47 4 ;
    END
  END gpio_inp_dis[8]
  PIN gpio_inp_dis[9]
    DIRECTION OUTPUT ;
    USE SIGNAL ;
    PORT
      LAYER met2 ;
        RECT  1774.31 0 1774.59 4 ;
    END
  END gpio_inp_dis[9]
  PIN gpio_oeb[0]
    DIRECTION OUTPUT ;
    USE SIGNAL ;
    PORT
      LAYER met2 ;
        RECT  1476.23 1696 1476.51 1700 ;
    END
  END gpio_oeb[0]
  PIN gpio_oeb[10]
    DIRECTION OUTPUT ;
    USE SIGNAL ;
    PORT
      LAYER met2 ;
        RECT  1807.43 1696 1807.71 1700 ;
    END
  END gpio_oeb[10]
  PIN gpio_oeb[11]
    DIRECTION OUTPUT ;
    USE SIGNAL ;
    PORT
      LAYER met2 ;
        RECT  1840.55 1696 1840.83 1700 ;
    END
  END gpio_oeb[11]
  PIN gpio_oeb[12]
    DIRECTION OUTPUT ;
    USE SIGNAL ;
    PORT
      LAYER met2 ;
        RECT  1873.67 1696 1873.95 1700 ;
    END
  END gpio_oeb[12]
  PIN gpio_oeb[13]
    DIRECTION OUTPUT ;
    USE SIGNAL ;
    PORT
      LAYER met2 ;
        RECT  1906.79 1696 1907.07 1700 ;
    END
  END gpio_oeb[13]
  PIN gpio_oeb[14]
    DIRECTION OUTPUT ;
    USE SIGNAL ;
    PORT
      LAYER met2 ;
        RECT  1939.91 1696 1940.19 1700 ;
    END
  END gpio_oeb[14]
  PIN gpio_oeb[15]
    DIRECTION OUTPUT ;
    USE SIGNAL ;
    PORT
      LAYER met2 ;
        RECT  1973.03 1696 1973.31 1700 ;
    END
  END gpio_oeb[15]
  PIN gpio_oeb[16]
    DIRECTION OUTPUT ;
    USE SIGNAL ;
    PORT
      LAYER met2 ;
        RECT  2006.15 1696 2006.43 1700 ;
    END
  END gpio_oeb[16]
  PIN gpio_oeb[17]
    DIRECTION OUTPUT ;
    USE SIGNAL ;
    PORT
      LAYER met2 ;
        RECT  2039.27 1696 2039.55 1700 ;
    END
  END gpio_oeb[17]
  PIN gpio_oeb[18]
    DIRECTION OUTPUT ;
    USE SIGNAL ;
    PORT
      LAYER met2 ;
        RECT  2072.39 1696 2072.67 1700 ;
    END
  END gpio_oeb[18]
  PIN gpio_oeb[19]
    DIRECTION OUTPUT ;
    USE SIGNAL ;
    PORT
      LAYER met2 ;
        RECT  2105.51 1696 2105.79 1700 ;
    END
  END gpio_oeb[19]
  PIN gpio_oeb[1]
    DIRECTION OUTPUT ;
    USE SIGNAL ;
    PORT
      LAYER met2 ;
        RECT  1509.35 1696 1509.63 1700 ;
    END
  END gpio_oeb[1]
  PIN gpio_oeb[20]
    DIRECTION OUTPUT ;
    USE SIGNAL ;
    PORT
      LAYER met2 ;
        RECT  2138.63 1696 2138.91 1700 ;
    END
  END gpio_oeb[20]
  PIN gpio_oeb[21]
    DIRECTION OUTPUT ;
    USE SIGNAL ;
    PORT
      LAYER met2 ;
        RECT  2171.75 1696 2172.03 1700 ;
    END
  END gpio_oeb[21]
  PIN gpio_oeb[22]
    DIRECTION OUTPUT ;
    USE SIGNAL ;
    PORT
      LAYER met2 ;
        RECT  2204.87 1696 2205.15 1700 ;
    END
  END gpio_oeb[22]
  PIN gpio_oeb[23]
    DIRECTION OUTPUT ;
    USE SIGNAL ;
    PORT
      LAYER met2 ;
        RECT  2237.99 1696 2238.27 1700 ;
    END
  END gpio_oeb[23]
  PIN gpio_oeb[24]
    DIRECTION OUTPUT ;
    USE SIGNAL ;
    PORT
      LAYER met2 ;
        RECT  2271.11 1696 2271.39 1700 ;
    END
  END gpio_oeb[24]
  PIN gpio_oeb[25]
    DIRECTION OUTPUT ;
    USE SIGNAL ;
    PORT
      LAYER met2 ;
        RECT  2304.23 1696 2304.51 1700 ;
    END
  END gpio_oeb[25]
  PIN gpio_oeb[26]
    DIRECTION OUTPUT ;
    USE SIGNAL ;
    PORT
      LAYER met2 ;
        RECT  2337.35 1696 2337.63 1700 ;
    END
  END gpio_oeb[26]
  PIN gpio_oeb[27]
    DIRECTION OUTPUT ;
    USE SIGNAL ;
    PORT
      LAYER met2 ;
        RECT  2370.47 1696 2370.75 1700 ;
    END
  END gpio_oeb[27]
  PIN gpio_oeb[28]
    DIRECTION OUTPUT ;
    USE SIGNAL ;
    PORT
      LAYER met2 ;
        RECT  2403.59 1696 2403.87 1700 ;
    END
  END gpio_oeb[28]
  PIN gpio_oeb[29]
    DIRECTION OUTPUT ;
    USE SIGNAL ;
    PORT
      LAYER met2 ;
        RECT  2436.71 1696 2436.99 1700 ;
    END
  END gpio_oeb[29]
  PIN gpio_oeb[2]
    DIRECTION OUTPUT ;
    USE SIGNAL ;
    PORT
      LAYER met2 ;
        RECT  1542.47 1696 1542.75 1700 ;
    END
  END gpio_oeb[2]
  PIN gpio_oeb[30]
    DIRECTION OUTPUT ;
    USE SIGNAL ;
    PORT
      LAYER met2 ;
        RECT  2469.83 1696 2470.11 1700 ;
    END
  END gpio_oeb[30]
  PIN gpio_oeb[31]
    DIRECTION OUTPUT ;
    USE SIGNAL ;
    PORT
      LAYER met2 ;
        RECT  2502.95 1696 2503.23 1700 ;
    END
  END gpio_oeb[31]
  PIN gpio_oeb[32]
    DIRECTION OUTPUT ;
    USE SIGNAL ;
    PORT
      LAYER met2 ;
        RECT  2536.07 1696 2536.35 1700 ;
    END
  END gpio_oeb[32]
  PIN gpio_oeb[33]
    DIRECTION OUTPUT ;
    USE SIGNAL ;
    PORT
      LAYER met2 ;
        RECT  2569.19 1696 2569.47 1700 ;
    END
  END gpio_oeb[33]
  PIN gpio_oeb[34]
    DIRECTION OUTPUT ;
    USE SIGNAL ;
    PORT
      LAYER met2 ;
        RECT  2602.31 1696 2602.59 1700 ;
    END
  END gpio_oeb[34]
  PIN gpio_oeb[35]
    DIRECTION OUTPUT ;
    USE SIGNAL ;
    PORT
      LAYER met2 ;
        RECT  2635.43 1696 2635.71 1700 ;
    END
  END gpio_oeb[35]
  PIN gpio_oeb[36]
    DIRECTION OUTPUT ;
    USE SIGNAL ;
    PORT
      LAYER met2 ;
        RECT  2668.55 1696 2668.83 1700 ;
    END
  END gpio_oeb[36]
  PIN gpio_oeb[37]
    DIRECTION OUTPUT ;
    USE SIGNAL ;
    PORT
      LAYER met2 ;
        RECT  2701.67 1696 2701.95 1700 ;
    END
  END gpio_oeb[37]
  PIN gpio_oeb[38]
    DIRECTION OUTPUT ;
    USE SIGNAL ;
    PORT
      LAYER met2 ;
        RECT  2734.79 1696 2735.07 1700 ;
    END
  END gpio_oeb[38]
  PIN gpio_oeb[39]
    DIRECTION OUTPUT ;
    USE SIGNAL ;
    PORT
      LAYER met2 ;
        RECT  2767.91 1696 2768.19 1700 ;
    END
  END gpio_oeb[39]
  PIN gpio_oeb[3]
    DIRECTION OUTPUT ;
    USE SIGNAL ;
    PORT
      LAYER met2 ;
        RECT  1575.59 1696 1575.87 1700 ;
    END
  END gpio_oeb[3]
  PIN gpio_oeb[40]
    DIRECTION OUTPUT ;
    USE SIGNAL ;
    PORT
      LAYER met2 ;
        RECT  2801.03 1696 2801.31 1700 ;
    END
  END gpio_oeb[40]
  PIN gpio_oeb[41]
    DIRECTION OUTPUT ;
    USE SIGNAL ;
    PORT
      LAYER met2 ;
        RECT  2834.15 1696 2834.43 1700 ;
    END
  END gpio_oeb[41]
  PIN gpio_oeb[42]
    DIRECTION OUTPUT ;
    USE SIGNAL ;
    PORT
      LAYER met2 ;
        RECT  2867.27 1696 2867.55 1700 ;
    END
  END gpio_oeb[42]
  PIN gpio_oeb[43]
    DIRECTION OUTPUT ;
    USE SIGNAL ;
    PORT
      LAYER met2 ;
        RECT  2900.39 1696 2900.67 1700 ;
    END
  END gpio_oeb[43]
  PIN gpio_oeb[4]
    DIRECTION OUTPUT ;
    USE SIGNAL ;
    PORT
      LAYER met2 ;
        RECT  1608.71 1696 1608.99 1700 ;
    END
  END gpio_oeb[4]
  PIN gpio_oeb[5]
    DIRECTION OUTPUT ;
    USE SIGNAL ;
    PORT
      LAYER met2 ;
        RECT  1641.83 1696 1642.11 1700 ;
    END
  END gpio_oeb[5]
  PIN gpio_oeb[6]
    DIRECTION OUTPUT ;
    USE SIGNAL ;
    PORT
      LAYER met2 ;
        RECT  1674.95 1696 1675.23 1700 ;
    END
  END gpio_oeb[6]
  PIN gpio_oeb[7]
    DIRECTION OUTPUT ;
    USE SIGNAL ;
    PORT
      LAYER met2 ;
        RECT  1708.07 1696 1708.35 1700 ;
    END
  END gpio_oeb[7]
  PIN gpio_oeb[8]
    DIRECTION OUTPUT ;
    USE SIGNAL ;
    PORT
      LAYER met2 ;
        RECT  1741.19 1696 1741.47 1700 ;
    END
  END gpio_oeb[8]
  PIN gpio_oeb[9]
    DIRECTION OUTPUT ;
    USE SIGNAL ;
    PORT
      LAYER met2 ;
        RECT  1774.31 1696 1774.59 1700 ;
    END
  END gpio_oeb[9]
  PIN gpio_out[0]
    DIRECTION OUTPUT ;
    USE SIGNAL ;
    PORT
      LAYER met2 ;
        RECT  18.95 1696 19.23 1700 ;
    END
  END gpio_out[0]
  PIN gpio_out[10]
    DIRECTION OUTPUT ;
    USE SIGNAL ;
    PORT
      LAYER met2 ;
        RECT  350.15 1696 350.43 1700 ;
    END
  END gpio_out[10]
  PIN gpio_out[11]
    DIRECTION OUTPUT ;
    USE SIGNAL ;
    PORT
      LAYER met2 ;
        RECT  383.27 1696 383.55 1700 ;
    END
  END gpio_out[11]
  PIN gpio_out[12]
    DIRECTION OUTPUT ;
    USE SIGNAL ;
    PORT
      LAYER met2 ;
        RECT  416.39 1696 416.67 1700 ;
    END
  END gpio_out[12]
  PIN gpio_out[13]
    DIRECTION OUTPUT ;
    USE SIGNAL ;
    PORT
      LAYER met2 ;
        RECT  449.51 1696 449.79 1700 ;
    END
  END gpio_out[13]
  PIN gpio_out[14]
    DIRECTION OUTPUT ;
    USE SIGNAL ;
    PORT
      LAYER met2 ;
        RECT  482.63 1696 482.91 1700 ;
    END
  END gpio_out[14]
  PIN gpio_out[15]
    DIRECTION OUTPUT ;
    USE SIGNAL ;
    PORT
      LAYER met2 ;
        RECT  515.75 1696 516.03 1700 ;
    END
  END gpio_out[15]
  PIN gpio_out[16]
    DIRECTION OUTPUT ;
    USE SIGNAL ;
    PORT
      LAYER met2 ;
        RECT  548.87 1696 549.15 1700 ;
    END
  END gpio_out[16]
  PIN gpio_out[17]
    DIRECTION OUTPUT ;
    USE SIGNAL ;
    PORT
      LAYER met2 ;
        RECT  581.99 1696 582.27 1700 ;
    END
  END gpio_out[17]
  PIN gpio_out[18]
    DIRECTION OUTPUT ;
    USE SIGNAL ;
    PORT
      LAYER met2 ;
        RECT  615.11 1696 615.39 1700 ;
    END
  END gpio_out[18]
  PIN gpio_out[19]
    DIRECTION OUTPUT ;
    USE SIGNAL ;
    PORT
      LAYER met2 ;
        RECT  648.23 1696 648.51 1700 ;
    END
  END gpio_out[19]
  PIN gpio_out[1]
    DIRECTION OUTPUT ;
    USE SIGNAL ;
    PORT
      LAYER met2 ;
        RECT  52.07 1696 52.35 1700 ;
    END
  END gpio_out[1]
  PIN gpio_out[20]
    DIRECTION OUTPUT ;
    USE SIGNAL ;
    PORT
      LAYER met2 ;
        RECT  681.35 1696 681.63 1700 ;
    END
  END gpio_out[20]
  PIN gpio_out[21]
    DIRECTION OUTPUT ;
    USE SIGNAL ;
    PORT
      LAYER met2 ;
        RECT  714.47 1696 714.75 1700 ;
    END
  END gpio_out[21]
  PIN gpio_out[22]
    DIRECTION OUTPUT ;
    USE SIGNAL ;
    PORT
      LAYER met2 ;
        RECT  747.59 1696 747.87 1700 ;
    END
  END gpio_out[22]
  PIN gpio_out[23]
    DIRECTION OUTPUT ;
    USE SIGNAL ;
    PORT
      LAYER met2 ;
        RECT  780.71 1696 780.99 1700 ;
    END
  END gpio_out[23]
  PIN gpio_out[24]
    DIRECTION OUTPUT ;
    USE SIGNAL ;
    PORT
      LAYER met2 ;
        RECT  813.83 1696 814.11 1700 ;
    END
  END gpio_out[24]
  PIN gpio_out[25]
    DIRECTION OUTPUT ;
    USE SIGNAL ;
    PORT
      LAYER met2 ;
        RECT  846.95 1696 847.23 1700 ;
    END
  END gpio_out[25]
  PIN gpio_out[26]
    DIRECTION OUTPUT ;
    USE SIGNAL ;
    PORT
      LAYER met2 ;
        RECT  880.07 1696 880.35 1700 ;
    END
  END gpio_out[26]
  PIN gpio_out[27]
    DIRECTION OUTPUT ;
    USE SIGNAL ;
    PORT
      LAYER met2 ;
        RECT  913.19 1696 913.47 1700 ;
    END
  END gpio_out[27]
  PIN gpio_out[28]
    DIRECTION OUTPUT ;
    USE SIGNAL ;
    PORT
      LAYER met2 ;
        RECT  946.31 1696 946.59 1700 ;
    END
  END gpio_out[28]
  PIN gpio_out[29]
    DIRECTION OUTPUT ;
    USE SIGNAL ;
    PORT
      LAYER met2 ;
        RECT  979.43 1696 979.71 1700 ;
    END
  END gpio_out[29]
  PIN gpio_out[2]
    DIRECTION OUTPUT ;
    USE SIGNAL ;
    PORT
      LAYER met2 ;
        RECT  85.19 1696 85.47 1700 ;
    END
  END gpio_out[2]
  PIN gpio_out[30]
    DIRECTION OUTPUT ;
    USE SIGNAL ;
    PORT
      LAYER met2 ;
        RECT  1012.55 1696 1012.83 1700 ;
    END
  END gpio_out[30]
  PIN gpio_out[31]
    DIRECTION OUTPUT ;
    USE SIGNAL ;
    PORT
      LAYER met2 ;
        RECT  1045.67 1696 1045.95 1700 ;
    END
  END gpio_out[31]
  PIN gpio_out[32]
    DIRECTION OUTPUT ;
    USE SIGNAL ;
    PORT
      LAYER met2 ;
        RECT  1078.79 1696 1079.07 1700 ;
    END
  END gpio_out[32]
  PIN gpio_out[33]
    DIRECTION OUTPUT ;
    USE SIGNAL ;
    PORT
      LAYER met2 ;
        RECT  1111.91 1696 1112.19 1700 ;
    END
  END gpio_out[33]
  PIN gpio_out[34]
    DIRECTION OUTPUT ;
    USE SIGNAL ;
    PORT
      LAYER met2 ;
        RECT  1145.03 1696 1145.31 1700 ;
    END
  END gpio_out[34]
  PIN gpio_out[35]
    DIRECTION OUTPUT ;
    USE SIGNAL ;
    PORT
      LAYER met2 ;
        RECT  1178.15 1696 1178.43 1700 ;
    END
  END gpio_out[35]
  PIN gpio_out[36]
    DIRECTION OUTPUT ;
    USE SIGNAL ;
    PORT
      LAYER met2 ;
        RECT  1211.27 1696 1211.55 1700 ;
    END
  END gpio_out[36]
  PIN gpio_out[37]
    DIRECTION OUTPUT ;
    USE SIGNAL ;
    PORT
      LAYER met2 ;
        RECT  1244.39 1696 1244.67 1700 ;
    END
  END gpio_out[37]
  PIN gpio_out[38]
    DIRECTION OUTPUT ;
    USE SIGNAL ;
    PORT
      LAYER met2 ;
        RECT  1277.51 1696 1277.79 1700 ;
    END
  END gpio_out[38]
  PIN gpio_out[39]
    DIRECTION OUTPUT ;
    USE SIGNAL ;
    PORT
      LAYER met2 ;
        RECT  1310.63 1696 1310.91 1700 ;
    END
  END gpio_out[39]
  PIN gpio_out[3]
    DIRECTION OUTPUT ;
    USE SIGNAL ;
    PORT
      LAYER met2 ;
        RECT  118.31 1696 118.59 1700 ;
    END
  END gpio_out[3]
  PIN gpio_out[40]
    DIRECTION OUTPUT ;
    USE SIGNAL ;
    PORT
      LAYER met2 ;
        RECT  1343.75 1696 1344.03 1700 ;
    END
  END gpio_out[40]
  PIN gpio_out[41]
    DIRECTION OUTPUT ;
    USE SIGNAL ;
    PORT
      LAYER met2 ;
        RECT  1376.87 1696 1377.15 1700 ;
    END
  END gpio_out[41]
  PIN gpio_out[42]
    DIRECTION OUTPUT ;
    USE SIGNAL ;
    PORT
      LAYER met2 ;
        RECT  1409.99 1696 1410.27 1700 ;
    END
  END gpio_out[42]
  PIN gpio_out[43]
    DIRECTION OUTPUT ;
    USE SIGNAL ;
    PORT
      LAYER met2 ;
        RECT  1443.11 1696 1443.39 1700 ;
    END
  END gpio_out[43]
  PIN gpio_out[4]
    DIRECTION OUTPUT ;
    USE SIGNAL ;
    PORT
      LAYER met2 ;
        RECT  151.43 1696 151.71 1700 ;
    END
  END gpio_out[4]
  PIN gpio_out[5]
    DIRECTION OUTPUT ;
    USE SIGNAL ;
    PORT
      LAYER met2 ;
        RECT  184.55 1696 184.83 1700 ;
    END
  END gpio_out[5]
  PIN gpio_out[6]
    DIRECTION OUTPUT ;
    USE SIGNAL ;
    PORT
      LAYER met2 ;
        RECT  217.67 1696 217.95 1700 ;
    END
  END gpio_out[6]
  PIN gpio_out[7]
    DIRECTION OUTPUT ;
    USE SIGNAL ;
    PORT
      LAYER met2 ;
        RECT  250.79 1696 251.07 1700 ;
    END
  END gpio_out[7]
  PIN gpio_out[8]
    DIRECTION OUTPUT ;
    USE SIGNAL ;
    PORT
      LAYER met2 ;
        RECT  283.91 1696 284.19 1700 ;
    END
  END gpio_out[8]
  PIN gpio_out[9]
    DIRECTION OUTPUT ;
    USE SIGNAL ;
    PORT
      LAYER met2 ;
        RECT  317.03 1696 317.31 1700 ;
    END
  END gpio_out[9]
  PIN gpio_slow_sel[0]
    DIRECTION OUTPUT ;
    USE SIGNAL ;
    PORT
      LAYER met3 ;
        RECT  0 968.36 4 968.96 ;
    END
  END gpio_slow_sel[0]
  PIN gpio_slow_sel[10]
    DIRECTION OUTPUT ;
    USE SIGNAL ;
    PORT
      LAYER met3 ;
        RECT  0 1036.36 4 1036.96 ;
    END
  END gpio_slow_sel[10]
  PIN gpio_slow_sel[11]
    DIRECTION OUTPUT ;
    USE SIGNAL ;
    PORT
      LAYER met3 ;
        RECT  0 1043.16 4 1043.76 ;
    END
  END gpio_slow_sel[11]
  PIN gpio_slow_sel[12]
    DIRECTION OUTPUT ;
    USE SIGNAL ;
    PORT
      LAYER met3 ;
        RECT  0 1049.96 4 1050.56 ;
    END
  END gpio_slow_sel[12]
  PIN gpio_slow_sel[13]
    DIRECTION OUTPUT ;
    USE SIGNAL ;
    PORT
      LAYER met3 ;
        RECT  0 1056.76 4 1057.36 ;
    END
  END gpio_slow_sel[13]
  PIN gpio_slow_sel[14]
    DIRECTION OUTPUT ;
    USE SIGNAL ;
    PORT
      LAYER met3 ;
        RECT  0 1063.56 4 1064.16 ;
    END
  END gpio_slow_sel[14]
  PIN gpio_slow_sel[15]
    DIRECTION OUTPUT ;
    USE SIGNAL ;
    PORT
      LAYER met3 ;
        RECT  0 1070.36 4 1070.96 ;
    END
  END gpio_slow_sel[15]
  PIN gpio_slow_sel[16]
    DIRECTION OUTPUT ;
    USE SIGNAL ;
    PORT
      LAYER met3 ;
        RECT  0 1077.16 4 1077.76 ;
    END
  END gpio_slow_sel[16]
  PIN gpio_slow_sel[17]
    DIRECTION OUTPUT ;
    USE SIGNAL ;
    PORT
      LAYER met3 ;
        RECT  0 1083.96 4 1084.56 ;
    END
  END gpio_slow_sel[17]
  PIN gpio_slow_sel[18]
    DIRECTION OUTPUT ;
    USE SIGNAL ;
    PORT
      LAYER met3 ;
        RECT  0 1090.76 4 1091.36 ;
    END
  END gpio_slow_sel[18]
  PIN gpio_slow_sel[19]
    DIRECTION OUTPUT ;
    USE SIGNAL ;
    PORT
      LAYER met3 ;
        RECT  0 1097.56 4 1098.16 ;
    END
  END gpio_slow_sel[19]
  PIN gpio_slow_sel[1]
    DIRECTION OUTPUT ;
    USE SIGNAL ;
    PORT
      LAYER met3 ;
        RECT  0 975.16 4 975.76 ;
    END
  END gpio_slow_sel[1]
  PIN gpio_slow_sel[20]
    DIRECTION OUTPUT ;
    USE SIGNAL ;
    PORT
      LAYER met3 ;
        RECT  0 1104.36 4 1104.96 ;
    END
  END gpio_slow_sel[20]
  PIN gpio_slow_sel[21]
    DIRECTION OUTPUT ;
    USE SIGNAL ;
    PORT
      LAYER met3 ;
        RECT  0 1111.16 4 1111.76 ;
    END
  END gpio_slow_sel[21]
  PIN gpio_slow_sel[22]
    DIRECTION OUTPUT ;
    USE SIGNAL ;
    PORT
      LAYER met3 ;
        RECT  0 1117.96 4 1118.56 ;
    END
  END gpio_slow_sel[22]
  PIN gpio_slow_sel[23]
    DIRECTION OUTPUT ;
    USE SIGNAL ;
    PORT
      LAYER met3 ;
        RECT  0 1124.76 4 1125.36 ;
    END
  END gpio_slow_sel[23]
  PIN gpio_slow_sel[24]
    DIRECTION OUTPUT ;
    USE SIGNAL ;
    PORT
      LAYER met3 ;
        RECT  0 1131.56 4 1132.16 ;
    END
  END gpio_slow_sel[24]
  PIN gpio_slow_sel[25]
    DIRECTION OUTPUT ;
    USE SIGNAL ;
    PORT
      LAYER met3 ;
        RECT  0 1138.36 4 1138.96 ;
    END
  END gpio_slow_sel[25]
  PIN gpio_slow_sel[26]
    DIRECTION OUTPUT ;
    USE SIGNAL ;
    PORT
      LAYER met3 ;
        RECT  0 1145.16 4 1145.76 ;
    END
  END gpio_slow_sel[26]
  PIN gpio_slow_sel[27]
    DIRECTION OUTPUT ;
    USE SIGNAL ;
    PORT
      LAYER met3 ;
        RECT  0 1151.96 4 1152.56 ;
    END
  END gpio_slow_sel[27]
  PIN gpio_slow_sel[28]
    DIRECTION OUTPUT ;
    USE SIGNAL ;
    PORT
      LAYER met3 ;
        RECT  0 1158.76 4 1159.36 ;
    END
  END gpio_slow_sel[28]
  PIN gpio_slow_sel[29]
    DIRECTION OUTPUT ;
    USE SIGNAL ;
    PORT
      LAYER met3 ;
        RECT  0 1165.56 4 1166.16 ;
    END
  END gpio_slow_sel[29]
  PIN gpio_slow_sel[2]
    DIRECTION OUTPUT ;
    USE SIGNAL ;
    PORT
      LAYER met3 ;
        RECT  0 981.96 4 982.56 ;
    END
  END gpio_slow_sel[2]
  PIN gpio_slow_sel[30]
    DIRECTION OUTPUT ;
    USE SIGNAL ;
    PORT
      LAYER met3 ;
        RECT  0 1172.36 4 1172.96 ;
    END
  END gpio_slow_sel[30]
  PIN gpio_slow_sel[31]
    DIRECTION OUTPUT ;
    USE SIGNAL ;
    PORT
      LAYER met3 ;
        RECT  0 1179.16 4 1179.76 ;
    END
  END gpio_slow_sel[31]
  PIN gpio_slow_sel[32]
    DIRECTION OUTPUT ;
    USE SIGNAL ;
    PORT
      LAYER met3 ;
        RECT  0 1185.96 4 1186.56 ;
    END
  END gpio_slow_sel[32]
  PIN gpio_slow_sel[33]
    DIRECTION OUTPUT ;
    USE SIGNAL ;
    PORT
      LAYER met3 ;
        RECT  0 1192.76 4 1193.36 ;
    END
  END gpio_slow_sel[33]
  PIN gpio_slow_sel[34]
    DIRECTION OUTPUT ;
    USE SIGNAL ;
    PORT
      LAYER met3 ;
        RECT  0 1199.56 4 1200.16 ;
    END
  END gpio_slow_sel[34]
  PIN gpio_slow_sel[35]
    DIRECTION OUTPUT ;
    USE SIGNAL ;
    PORT
      LAYER met3 ;
        RECT  0 1206.36 4 1206.96 ;
    END
  END gpio_slow_sel[35]
  PIN gpio_slow_sel[36]
    DIRECTION OUTPUT ;
    USE SIGNAL ;
    PORT
      LAYER met3 ;
        RECT  0 1213.16 4 1213.76 ;
    END
  END gpio_slow_sel[36]
  PIN gpio_slow_sel[37]
    DIRECTION OUTPUT ;
    USE SIGNAL ;
    PORT
      LAYER met3 ;
        RECT  0 1219.96 4 1220.56 ;
    END
  END gpio_slow_sel[37]
  PIN gpio_slow_sel[38]
    DIRECTION OUTPUT ;
    USE SIGNAL ;
    PORT
      LAYER met3 ;
        RECT  0 1226.76 4 1227.36 ;
    END
  END gpio_slow_sel[38]
  PIN gpio_slow_sel[39]
    DIRECTION OUTPUT ;
    USE SIGNAL ;
    PORT
      LAYER met3 ;
        RECT  0 1233.56 4 1234.16 ;
    END
  END gpio_slow_sel[39]
  PIN gpio_slow_sel[3]
    DIRECTION OUTPUT ;
    USE SIGNAL ;
    PORT
      LAYER met3 ;
        RECT  0 988.76 4 989.36 ;
    END
  END gpio_slow_sel[3]
  PIN gpio_slow_sel[40]
    DIRECTION OUTPUT ;
    USE SIGNAL ;
    PORT
      LAYER met3 ;
        RECT  0 1240.36 4 1240.96 ;
    END
  END gpio_slow_sel[40]
  PIN gpio_slow_sel[41]
    DIRECTION OUTPUT ;
    USE SIGNAL ;
    PORT
      LAYER met3 ;
        RECT  0 1247.16 4 1247.76 ;
    END
  END gpio_slow_sel[41]
  PIN gpio_slow_sel[42]
    DIRECTION OUTPUT ;
    USE SIGNAL ;
    PORT
      LAYER met3 ;
        RECT  0 1253.96 4 1254.56 ;
    END
  END gpio_slow_sel[42]
  PIN gpio_slow_sel[43]
    DIRECTION OUTPUT ;
    USE SIGNAL ;
    PORT
      LAYER met3 ;
        RECT  0 1260.76 4 1261.36 ;
    END
  END gpio_slow_sel[43]
  PIN gpio_slow_sel[4]
    DIRECTION OUTPUT ;
    USE SIGNAL ;
    PORT
      LAYER met3 ;
        RECT  0 995.56 4 996.16 ;
    END
  END gpio_slow_sel[4]
  PIN gpio_slow_sel[5]
    DIRECTION OUTPUT ;
    USE SIGNAL ;
    PORT
      LAYER met3 ;
        RECT  0 1002.36 4 1002.96 ;
    END
  END gpio_slow_sel[5]
  PIN gpio_slow_sel[6]
    DIRECTION OUTPUT ;
    USE SIGNAL ;
    PORT
      LAYER met3 ;
        RECT  0 1009.16 4 1009.76 ;
    END
  END gpio_slow_sel[6]
  PIN gpio_slow_sel[7]
    DIRECTION OUTPUT ;
    USE SIGNAL ;
    PORT
      LAYER met3 ;
        RECT  0 1015.96 4 1016.56 ;
    END
  END gpio_slow_sel[7]
  PIN gpio_slow_sel[8]
    DIRECTION OUTPUT ;
    USE SIGNAL ;
    PORT
      LAYER met3 ;
        RECT  0 1022.76 4 1023.36 ;
    END
  END gpio_slow_sel[8]
  PIN gpio_slow_sel[9]
    DIRECTION OUTPUT ;
    USE SIGNAL ;
    PORT
      LAYER met3 ;
        RECT  0 1029.56 4 1030.16 ;
    END
  END gpio_slow_sel[9]
  PIN gpio_vtrip_sel[0]
    DIRECTION OUTPUT ;
    USE SIGNAL ;
    PORT
      LAYER met3 ;
        RECT  0 669.16 4 669.76 ;
    END
  END gpio_vtrip_sel[0]
  PIN gpio_vtrip_sel[10]
    DIRECTION OUTPUT ;
    USE SIGNAL ;
    PORT
      LAYER met3 ;
        RECT  0 737.16 4 737.76 ;
    END
  END gpio_vtrip_sel[10]
  PIN gpio_vtrip_sel[11]
    DIRECTION OUTPUT ;
    USE SIGNAL ;
    PORT
      LAYER met3 ;
        RECT  0 743.96 4 744.56 ;
    END
  END gpio_vtrip_sel[11]
  PIN gpio_vtrip_sel[12]
    DIRECTION OUTPUT ;
    USE SIGNAL ;
    PORT
      LAYER met3 ;
        RECT  0 750.76 4 751.36 ;
    END
  END gpio_vtrip_sel[12]
  PIN gpio_vtrip_sel[13]
    DIRECTION OUTPUT ;
    USE SIGNAL ;
    PORT
      LAYER met3 ;
        RECT  0 757.56 4 758.16 ;
    END
  END gpio_vtrip_sel[13]
  PIN gpio_vtrip_sel[14]
    DIRECTION OUTPUT ;
    USE SIGNAL ;
    PORT
      LAYER met3 ;
        RECT  0 764.36 4 764.96 ;
    END
  END gpio_vtrip_sel[14]
  PIN gpio_vtrip_sel[15]
    DIRECTION OUTPUT ;
    USE SIGNAL ;
    PORT
      LAYER met3 ;
        RECT  0 771.16 4 771.76 ;
    END
  END gpio_vtrip_sel[15]
  PIN gpio_vtrip_sel[16]
    DIRECTION OUTPUT ;
    USE SIGNAL ;
    PORT
      LAYER met3 ;
        RECT  0 777.96 4 778.56 ;
    END
  END gpio_vtrip_sel[16]
  PIN gpio_vtrip_sel[17]
    DIRECTION OUTPUT ;
    USE SIGNAL ;
    PORT
      LAYER met3 ;
        RECT  0 784.76 4 785.36 ;
    END
  END gpio_vtrip_sel[17]
  PIN gpio_vtrip_sel[18]
    DIRECTION OUTPUT ;
    USE SIGNAL ;
    PORT
      LAYER met3 ;
        RECT  0 791.56 4 792.16 ;
    END
  END gpio_vtrip_sel[18]
  PIN gpio_vtrip_sel[19]
    DIRECTION OUTPUT ;
    USE SIGNAL ;
    PORT
      LAYER met3 ;
        RECT  0 798.36 4 798.96 ;
    END
  END gpio_vtrip_sel[19]
  PIN gpio_vtrip_sel[1]
    DIRECTION OUTPUT ;
    USE SIGNAL ;
    PORT
      LAYER met3 ;
        RECT  0 675.96 4 676.56 ;
    END
  END gpio_vtrip_sel[1]
  PIN gpio_vtrip_sel[20]
    DIRECTION OUTPUT ;
    USE SIGNAL ;
    PORT
      LAYER met3 ;
        RECT  0 805.16 4 805.76 ;
    END
  END gpio_vtrip_sel[20]
  PIN gpio_vtrip_sel[21]
    DIRECTION OUTPUT ;
    USE SIGNAL ;
    PORT
      LAYER met3 ;
        RECT  0 811.96 4 812.56 ;
    END
  END gpio_vtrip_sel[21]
  PIN gpio_vtrip_sel[22]
    DIRECTION OUTPUT ;
    USE SIGNAL ;
    PORT
      LAYER met3 ;
        RECT  0 818.76 4 819.36 ;
    END
  END gpio_vtrip_sel[22]
  PIN gpio_vtrip_sel[23]
    DIRECTION OUTPUT ;
    USE SIGNAL ;
    PORT
      LAYER met3 ;
        RECT  0 825.56 4 826.16 ;
    END
  END gpio_vtrip_sel[23]
  PIN gpio_vtrip_sel[24]
    DIRECTION OUTPUT ;
    USE SIGNAL ;
    PORT
      LAYER met3 ;
        RECT  0 832.36 4 832.96 ;
    END
  END gpio_vtrip_sel[24]
  PIN gpio_vtrip_sel[25]
    DIRECTION OUTPUT ;
    USE SIGNAL ;
    PORT
      LAYER met3 ;
        RECT  0 839.16 4 839.76 ;
    END
  END gpio_vtrip_sel[25]
  PIN gpio_vtrip_sel[26]
    DIRECTION OUTPUT ;
    USE SIGNAL ;
    PORT
      LAYER met3 ;
        RECT  0 845.96 4 846.56 ;
    END
  END gpio_vtrip_sel[26]
  PIN gpio_vtrip_sel[27]
    DIRECTION OUTPUT ;
    USE SIGNAL ;
    PORT
      LAYER met3 ;
        RECT  0 852.76 4 853.36 ;
    END
  END gpio_vtrip_sel[27]
  PIN gpio_vtrip_sel[28]
    DIRECTION OUTPUT ;
    USE SIGNAL ;
    PORT
      LAYER met3 ;
        RECT  0 859.56 4 860.16 ;
    END
  END gpio_vtrip_sel[28]
  PIN gpio_vtrip_sel[29]
    DIRECTION OUTPUT ;
    USE SIGNAL ;
    PORT
      LAYER met3 ;
        RECT  0 866.36 4 866.96 ;
    END
  END gpio_vtrip_sel[29]
  PIN gpio_vtrip_sel[2]
    DIRECTION OUTPUT ;
    USE SIGNAL ;
    PORT
      LAYER met3 ;
        RECT  0 682.76 4 683.36 ;
    END
  END gpio_vtrip_sel[2]
  PIN gpio_vtrip_sel[30]
    DIRECTION OUTPUT ;
    USE SIGNAL ;
    PORT
      LAYER met3 ;
        RECT  0 873.16 4 873.76 ;
    END
  END gpio_vtrip_sel[30]
  PIN gpio_vtrip_sel[31]
    DIRECTION OUTPUT ;
    USE SIGNAL ;
    PORT
      LAYER met3 ;
        RECT  0 879.96 4 880.56 ;
    END
  END gpio_vtrip_sel[31]
  PIN gpio_vtrip_sel[32]
    DIRECTION OUTPUT ;
    USE SIGNAL ;
    PORT
      LAYER met3 ;
        RECT  0 886.76 4 887.36 ;
    END
  END gpio_vtrip_sel[32]
  PIN gpio_vtrip_sel[33]
    DIRECTION OUTPUT ;
    USE SIGNAL ;
    PORT
      LAYER met3 ;
        RECT  0 893.56 4 894.16 ;
    END
  END gpio_vtrip_sel[33]
  PIN gpio_vtrip_sel[34]
    DIRECTION OUTPUT ;
    USE SIGNAL ;
    PORT
      LAYER met3 ;
        RECT  0 900.36 4 900.96 ;
    END
  END gpio_vtrip_sel[34]
  PIN gpio_vtrip_sel[35]
    DIRECTION OUTPUT ;
    USE SIGNAL ;
    PORT
      LAYER met3 ;
        RECT  0 907.16 4 907.76 ;
    END
  END gpio_vtrip_sel[35]
  PIN gpio_vtrip_sel[36]
    DIRECTION OUTPUT ;
    USE SIGNAL ;
    PORT
      LAYER met3 ;
        RECT  0 913.96 4 914.56 ;
    END
  END gpio_vtrip_sel[36]
  PIN gpio_vtrip_sel[37]
    DIRECTION OUTPUT ;
    USE SIGNAL ;
    PORT
      LAYER met3 ;
        RECT  0 920.76 4 921.36 ;
    END
  END gpio_vtrip_sel[37]
  PIN gpio_vtrip_sel[38]
    DIRECTION OUTPUT ;
    USE SIGNAL ;
    PORT
      LAYER met3 ;
        RECT  0 927.56 4 928.16 ;
    END
  END gpio_vtrip_sel[38]
  PIN gpio_vtrip_sel[39]
    DIRECTION OUTPUT ;
    USE SIGNAL ;
    PORT
      LAYER met3 ;
        RECT  0 934.36 4 934.96 ;
    END
  END gpio_vtrip_sel[39]
  PIN gpio_vtrip_sel[3]
    DIRECTION OUTPUT ;
    USE SIGNAL ;
    PORT
      LAYER met3 ;
        RECT  0 689.56 4 690.16 ;
    END
  END gpio_vtrip_sel[3]
  PIN gpio_vtrip_sel[40]
    DIRECTION OUTPUT ;
    USE SIGNAL ;
    PORT
      LAYER met3 ;
        RECT  0 941.16 4 941.76 ;
    END
  END gpio_vtrip_sel[40]
  PIN gpio_vtrip_sel[41]
    DIRECTION OUTPUT ;
    USE SIGNAL ;
    PORT
      LAYER met3 ;
        RECT  0 947.96 4 948.56 ;
    END
  END gpio_vtrip_sel[41]
  PIN gpio_vtrip_sel[42]
    DIRECTION OUTPUT ;
    USE SIGNAL ;
    PORT
      LAYER met3 ;
        RECT  0 954.76 4 955.36 ;
    END
  END gpio_vtrip_sel[42]
  PIN gpio_vtrip_sel[43]
    DIRECTION OUTPUT ;
    USE SIGNAL ;
    PORT
      LAYER met3 ;
        RECT  0 961.56 4 962.16 ;
    END
  END gpio_vtrip_sel[43]
  PIN gpio_vtrip_sel[4]
    DIRECTION OUTPUT ;
    USE SIGNAL ;
    PORT
      LAYER met3 ;
        RECT  0 696.36 4 696.96 ;
    END
  END gpio_vtrip_sel[4]
  PIN gpio_vtrip_sel[5]
    DIRECTION OUTPUT ;
    USE SIGNAL ;
    PORT
      LAYER met3 ;
        RECT  0 703.16 4 703.76 ;
    END
  END gpio_vtrip_sel[5]
  PIN gpio_vtrip_sel[6]
    DIRECTION OUTPUT ;
    USE SIGNAL ;
    PORT
      LAYER met3 ;
        RECT  0 709.96 4 710.56 ;
    END
  END gpio_vtrip_sel[6]
  PIN gpio_vtrip_sel[7]
    DIRECTION OUTPUT ;
    USE SIGNAL ;
    PORT
      LAYER met3 ;
        RECT  0 716.76 4 717.36 ;
    END
  END gpio_vtrip_sel[7]
  PIN gpio_vtrip_sel[8]
    DIRECTION OUTPUT ;
    USE SIGNAL ;
    PORT
      LAYER met3 ;
        RECT  0 723.56 4 724.16 ;
    END
  END gpio_vtrip_sel[8]
  PIN gpio_vtrip_sel[9]
    DIRECTION OUTPUT ;
    USE SIGNAL ;
    PORT
      LAYER met3 ;
        RECT  0 730.36 4 730.96 ;
    END
  END gpio_vtrip_sel[9]
  PIN mask_rev[0]
    DIRECTION INPUT ;
    USE SIGNAL ;
    PORT
      LAYER met3 ;
        RECT  0 152.36 4 152.96 ;
    END
  END mask_rev[0]
  PIN mask_rev[10]
    DIRECTION INPUT ;
    USE SIGNAL ;
    PORT
      LAYER met3 ;
        RECT  0 220.36 4 220.96 ;
    END
  END mask_rev[10]
  PIN mask_rev[11]
    DIRECTION INPUT ;
    USE SIGNAL ;
    PORT
      LAYER met3 ;
        RECT  0 227.16 4 227.76 ;
    END
  END mask_rev[11]
  PIN mask_rev[12]
    DIRECTION INPUT ;
    USE SIGNAL ;
    PORT
      LAYER met3 ;
        RECT  0 233.96 4 234.56 ;
    END
  END mask_rev[12]
  PIN mask_rev[13]
    DIRECTION INPUT ;
    USE SIGNAL ;
    PORT
      LAYER met3 ;
        RECT  0 240.76 4 241.36 ;
    END
  END mask_rev[13]
  PIN mask_rev[14]
    DIRECTION INPUT ;
    USE SIGNAL ;
    PORT
      LAYER met3 ;
        RECT  0 247.56 4 248.16 ;
    END
  END mask_rev[14]
  PIN mask_rev[15]
    DIRECTION INPUT ;
    USE SIGNAL ;
    PORT
      LAYER met3 ;
        RECT  0 254.36 4 254.96 ;
    END
  END mask_rev[15]
  PIN mask_rev[16]
    DIRECTION INPUT ;
    USE SIGNAL ;
    PORT
      LAYER met3 ;
        RECT  0 261.16 4 261.76 ;
    END
  END mask_rev[16]
  PIN mask_rev[17]
    DIRECTION INPUT ;
    USE SIGNAL ;
    PORT
      LAYER met3 ;
        RECT  0 267.96 4 268.56 ;
    END
  END mask_rev[17]
  PIN mask_rev[18]
    DIRECTION INPUT ;
    USE SIGNAL ;
    PORT
      LAYER met3 ;
        RECT  0 274.76 4 275.36 ;
    END
  END mask_rev[18]
  PIN mask_rev[19]
    DIRECTION INPUT ;
    USE SIGNAL ;
    PORT
      LAYER met3 ;
        RECT  0 281.56 4 282.16 ;
    END
  END mask_rev[19]
  PIN mask_rev[1]
    DIRECTION INPUT ;
    USE SIGNAL ;
    PORT
      LAYER met3 ;
        RECT  0 159.16 4 159.76 ;
    END
  END mask_rev[1]
  PIN mask_rev[20]
    DIRECTION INPUT ;
    USE SIGNAL ;
    PORT
      LAYER met3 ;
        RECT  0 288.36 4 288.96 ;
    END
  END mask_rev[20]
  PIN mask_rev[21]
    DIRECTION INPUT ;
    USE SIGNAL ;
    PORT
      LAYER met3 ;
        RECT  0 295.16 4 295.76 ;
    END
  END mask_rev[21]
  PIN mask_rev[22]
    DIRECTION INPUT ;
    USE SIGNAL ;
    PORT
      LAYER met3 ;
        RECT  0 301.96 4 302.56 ;
    END
  END mask_rev[22]
  PIN mask_rev[23]
    DIRECTION INPUT ;
    USE SIGNAL ;
    PORT
      LAYER met3 ;
        RECT  0 308.76 4 309.36 ;
    END
  END mask_rev[23]
  PIN mask_rev[24]
    DIRECTION INPUT ;
    USE SIGNAL ;
    PORT
      LAYER met3 ;
        RECT  0 315.56 4 316.16 ;
    END
  END mask_rev[24]
  PIN mask_rev[25]
    DIRECTION INPUT ;
    USE SIGNAL ;
    PORT
      LAYER met3 ;
        RECT  0 322.36 4 322.96 ;
    END
  END mask_rev[25]
  PIN mask_rev[26]
    DIRECTION INPUT ;
    USE SIGNAL ;
    PORT
      LAYER met3 ;
        RECT  0 329.16 4 329.76 ;
    END
  END mask_rev[26]
  PIN mask_rev[27]
    DIRECTION INPUT ;
    USE SIGNAL ;
    PORT
      LAYER met3 ;
        RECT  0 335.96 4 336.56 ;
    END
  END mask_rev[27]
  PIN mask_rev[28]
    DIRECTION INPUT ;
    USE SIGNAL ;
    PORT
      LAYER met3 ;
        RECT  0 342.76 4 343.36 ;
    END
  END mask_rev[28]
  PIN mask_rev[29]
    DIRECTION INPUT ;
    USE SIGNAL ;
    PORT
      LAYER met3 ;
        RECT  0 349.56 4 350.16 ;
    END
  END mask_rev[29]
  PIN mask_rev[2]
    DIRECTION INPUT ;
    USE SIGNAL ;
    PORT
      LAYER met3 ;
        RECT  0 165.96 4 166.56 ;
    END
  END mask_rev[2]
  PIN mask_rev[30]
    DIRECTION INPUT ;
    USE SIGNAL ;
    PORT
      LAYER met3 ;
        RECT  0 356.36 4 356.96 ;
    END
  END mask_rev[30]
  PIN mask_rev[31]
    DIRECTION INPUT ;
    USE SIGNAL ;
    PORT
      LAYER met3 ;
        RECT  0 363.16 4 363.76 ;
    END
  END mask_rev[31]
  PIN mask_rev[3]
    DIRECTION INPUT ;
    USE SIGNAL ;
    PORT
      LAYER met3 ;
        RECT  0 172.76 4 173.36 ;
    END
  END mask_rev[3]
  PIN mask_rev[4]
    DIRECTION INPUT ;
    USE SIGNAL ;
    PORT
      LAYER met3 ;
        RECT  0 179.56 4 180.16 ;
    END
  END mask_rev[4]
  PIN mask_rev[5]
    DIRECTION INPUT ;
    USE SIGNAL ;
    PORT
      LAYER met3 ;
        RECT  0 186.36 4 186.96 ;
    END
  END mask_rev[5]
  PIN mask_rev[6]
    DIRECTION INPUT ;
    USE SIGNAL ;
    PORT
      LAYER met3 ;
        RECT  0 193.16 4 193.76 ;
    END
  END mask_rev[6]
  PIN mask_rev[7]
    DIRECTION INPUT ;
    USE SIGNAL ;
    PORT
      LAYER met3 ;
        RECT  0 199.96 4 200.56 ;
    END
  END mask_rev[7]
  PIN mask_rev[8]
    DIRECTION INPUT ;
    USE SIGNAL ;
    PORT
      LAYER met3 ;
        RECT  0 206.76 4 207.36 ;
    END
  END mask_rev[8]
  PIN mask_rev[9]
    DIRECTION INPUT ;
    USE SIGNAL ;
    PORT
      LAYER met3 ;
        RECT  0 213.56 4 214.16 ;
    END
  END mask_rev[9]
  PIN porb_l
    DIRECTION INPUT ;
    USE SIGNAL ;
    PORT
      LAYER met3 ;
        RECT  0 138.76 4 139.36 ;
    END
  END porb_l
  PIN resetb_l
    DIRECTION INPUT ;
    USE SIGNAL ;
    PORT
      LAYER met3 ;
        RECT  0 145.56 4 146.16 ;
    END
  END resetb_l
  PIN vccd
    DIRECTION INOUT ;
    USE POWER ;
    PORT
      LAYER met5 ;
        RECT  373.67 989.55 732.07 992.65 ;
        RECT  8.97 989.55 372.07 992.65 ;
      LAYER met4 ;
        RECT  591.39 1006.16 594.49 1134.48 ;
      LAYER met5 ;
        RECT  2732.42 914.33 2914.34 917.43 ;
        RECT  2732.42 734.33 2914.34 737.43 ;
        RECT  2732.42 554.33 2914.34 557.43 ;
        RECT  5.28 1634.33 2914.34 1637.43 ;
        RECT  5.28 1454.33 2914.34 1457.43 ;
        RECT  5.28 1274.33 2914.34 1277.43 ;
        RECT  5.28 1094.33 2914.34 1097.43 ;
        RECT  5.28 914.33 573.22 917.43 ;
        RECT  5.28 734.33 573.22 737.43 ;
        RECT  5.28 554.33 573.22 557.43 ;
        RECT  5.28 14.33 2914.34 17.43 ;
      LAYER met4 ;
        RECT  2888.97 10.64 2892.07 1689.36 ;
        RECT  2708.97 978.265 2712.07 1689.36 ;
        RECT  2708.97 10.64 2712.07 164.255 ;
        RECT  2528.97 978.265 2532.07 1689.36 ;
        RECT  2528.97 10.64 2532.07 164.255 ;
        RECT  2348.97 978.265 2352.07 1689.36 ;
        RECT  2348.97 10.64 2352.07 164.255 ;
        RECT  2168.97 978.265 2172.07 1689.36 ;
        RECT  2168.97 10.64 2172.07 164.255 ;
        RECT  1988.97 978.265 1992.07 1689.36 ;
        RECT  1988.97 10.64 1992.07 142 ;
        RECT  1808.97 978.265 1812.07 1689.36 ;
        RECT  1808.97 10.64 1812.07 164.255 ;
        RECT  1628.97 978.265 1632.07 1689.36 ;
        RECT  1628.97 10.64 1632.07 164.255 ;
        RECT  1448.97 978.265 1452.07 1689.36 ;
        RECT  1448.97 10.64 1452.07 164.255 ;
        RECT  1268.97 978.265 1272.07 1689.36 ;
        RECT  1268.97 10.64 1272.07 164.255 ;
        RECT  1088.97 978.265 1092.07 1689.36 ;
        RECT  1088.97 10.64 1092.07 142 ;
        RECT  908.97 978.265 912.07 1689.36 ;
        RECT  908.97 10.64 912.07 164.255 ;
        RECT  728.97 978.265 732.07 1689.36 ;
        RECT  728.97 10.64 732.07 164.255 ;
        RECT  548.97 1565.385 552.07 1689.36 ;
        RECT  548.97 978.265 552.07 1021.335 ;
        RECT  548.97 10.64 552.07 164.255 ;
        RECT  368.97 1565.385 372.07 1689.36 ;
        RECT  368.97 978.265 372.07 1021.335 ;
        RECT  368.97 10.64 372.07 164.255 ;
        RECT  188.97 1565.385 192.07 1689.36 ;
        RECT  188.97 976.72 192.07 1021.335 ;
        RECT  188.97 10.64 192.07 142 ;
        RECT  8.97 10.64 12.07 1689.36 ;
    END
  END vccd
  PIN vssd
    DIRECTION INOUT ;
    USE GROUND ;
    PORT
      LAYER met5 ;
        RECT  373.67 1006.55 732.07 1009.65 ;
        RECT  8.97 1006.55 372.07 1009.65 ;
      LAYER met4 ;
        RECT  607.03 1006.16 610.13 1134.48 ;
      LAYER met5 ;
        RECT  2732.42 749.33 2914.34 752.43 ;
        RECT  2732.42 569.33 2914.34 572.43 ;
        RECT  5.28 1649.33 2914.34 1652.43 ;
        RECT  5.28 1469.33 2914.34 1472.43 ;
        RECT  5.28 1289.33 2914.34 1292.43 ;
        RECT  5.28 1109.33 2914.34 1112.43 ;
        RECT  5.28 749.33 573.22 752.43 ;
        RECT  5.28 569.33 573.22 572.43 ;
        RECT  5.28 209.33 2914.34 212.43 ;
        RECT  5.28 29.33 2914.34 32.43 ;
      LAYER met4 ;
        RECT  2903.97 10.64 2907.07 1689.36 ;
        RECT  2723.97 978.265 2727.07 1689.36 ;
        RECT  2723.97 10.64 2727.07 142 ;
        RECT  2543.97 978.265 2547.07 1689.36 ;
        RECT  2543.97 10.64 2547.07 164.255 ;
        RECT  2363.97 978.265 2367.07 1689.36 ;
        RECT  2363.97 10.64 2367.07 164.255 ;
        RECT  2183.97 978.265 2187.07 1689.36 ;
        RECT  2183.97 10.64 2187.07 142 ;
        RECT  2003.97 978.265 2007.07 1689.36 ;
        RECT  2003.97 10.64 2007.07 164.255 ;
        RECT  1823.97 978.265 1827.07 1689.36 ;
        RECT  1823.97 10.64 1827.07 142 ;
        RECT  1643.97 978.265 1647.07 1689.36 ;
        RECT  1643.97 10.64 1647.07 164.255 ;
        RECT  1463.97 978.265 1467.07 1689.36 ;
        RECT  1463.97 10.64 1467.07 164.255 ;
        RECT  1283.97 978.265 1287.07 1689.36 ;
        RECT  1283.97 10.64 1287.07 142 ;
        RECT  1103.97 978.265 1107.07 1689.36 ;
        RECT  1103.97 10.64 1107.07 164.255 ;
        RECT  923.97 978.265 927.07 1689.36 ;
        RECT  923.97 10.64 927.07 142 ;
        RECT  743.97 978.265 747.07 1689.36 ;
        RECT  743.97 10.64 747.07 164.255 ;
        RECT  563.97 978.265 567.07 1689.36 ;
        RECT  563.97 10.64 567.07 164.255 ;
        RECT  383.97 1565.385 387.07 1689.36 ;
        RECT  383.97 978.265 387.07 1021.335 ;
        RECT  383.97 10.64 387.07 142 ;
        RECT  203.97 1565.385 207.07 1689.36 ;
        RECT  203.97 978.265 207.07 1021.335 ;
        RECT  203.97 10.64 207.07 164.255 ;
        RECT  23.97 10.64 27.07 1689.36 ;
    END
  END vssd
  OBS
    LAYER li1 ;
     RECT  5.52 10.795 2914.1 138.805 ;
     RECT  160.12 163.515 2759.58 955.205 ;
     RECT  5.52 138.805 139.84 981.835 ;
     RECT  2780.24 138.805 2914.1 981.835 ;
     RECT  5.52 981.835 2914.1 1009.205 ;
     RECT  640.92 1022.635 734.3 1112.565 ;
     RECT  570.4 1009.205 629.74 1131.435 ;
     RECT  750.26 1009.205 2914.1 1131.435 ;
     RECT  155.52 1030.795 554.34 1558.645 ;
     RECT  5.52 1009.205 139.84 1582.955 ;
     RECT  570.4 1131.435 2914.1 1582.955 ;
     RECT  5.52 1582.955 2914.1 1689.205 ;
    LAYER met1 ;
     RECT  2.46 977.6 4.3 977.74 ;
     RECT  1.54 1022.14 4.3 1022.28 ;
     RECT  1.08 1261.16 4.3 1261.3 ;
     RECT  0.62 1538.26 4.3 1538.4 ;
     RECT  4.3 1140.12 5.22 1140.26 ;
     RECT  4.3 140.18 5.52 140.32 ;
     RECT  4.3 148 5.52 148.14 ;
     RECT  4.3 370.36 5.52 370.5 ;
     RECT  4.3 384.3 5.52 384.44 ;
     RECT  4.3 392.12 5.52 397.7 ;
     RECT  4.3 405.72 5.52 411.64 ;
     RECT  4.3 419.32 5.52 424.9 ;
     RECT  4.3 432.92 5.52 438.84 ;
     RECT  4.3 446.52 5.52 452.1 ;
     RECT  4.3 460.12 5.52 466.04 ;
     RECT  4.3 473.72 5.52 479.3 ;
     RECT  4.3 487.32 5.52 493.24 ;
     RECT  4.3 500.92 5.52 506.5 ;
     RECT  4.3 514.52 5.52 520.44 ;
     RECT  4.3 528.12 5.52 533.7 ;
     RECT  4.3 541.72 5.52 547.64 ;
     RECT  4.3 555.32 5.52 560.9 ;
     RECT  4.3 568.92 5.52 574.84 ;
     RECT  4.3 582.52 5.52 588.1 ;
     RECT  4.3 596.12 5.52 602.04 ;
     RECT  4.3 609.72 5.52 615.3 ;
     RECT  4.3 623.32 5.52 629.24 ;
     RECT  4.3 637.6 5.52 643.18 ;
     RECT  4.3 650.52 5.52 656.44 ;
     RECT  4.3 664.8 5.52 669.7 ;
     RECT  4.3 677.72 5.52 677.86 ;
     RECT  4.3 751.16 5.52 751.3 ;
     RECT  4.3 765.1 5.52 765.24 ;
     RECT  4.3 778.36 5.52 778.5 ;
     RECT  4.3 792.3 5.52 792.44 ;
     RECT  4.3 805.56 5.52 805.7 ;
     RECT  4.3 819.5 5.52 819.64 ;
     RECT  4.3 832.76 5.52 832.9 ;
     RECT  4.3 846.7 5.52 846.84 ;
     RECT  4.3 859.96 5.52 860.1 ;
     RECT  4.3 868.12 5.52 874.04 ;
     RECT  4.3 881.72 5.52 887.3 ;
     RECT  4.3 895.32 5.52 901.24 ;
     RECT  4.3 908.92 5.52 914.5 ;
     RECT  4.3 922.52 5.52 928.44 ;
     RECT  4.3 936.8 5.52 942.38 ;
     RECT  4.3 949.72 5.52 955.64 ;
     RECT  4.3 964 5.52 968.9 ;
     RECT  4.3 976.92 5.52 982.84 ;
     RECT  4.3 990.52 5.52 996.1 ;
     RECT  4.3 1004.12 5.52 1010.04 ;
     RECT  4.3 1017.72 5.52 1023.3 ;
     RECT  4.3 1031.32 5.52 1037.24 ;
     RECT  4.3 1044.92 5.52 1050.5 ;
     RECT  4.3 1058.52 5.52 1064.44 ;
     RECT  4.3 1072.12 5.52 1077.7 ;
     RECT  4.3 1085.72 5.52 1091.64 ;
     RECT  4.3 1099.32 5.52 1104.9 ;
     RECT  4.3 1112.92 5.52 1118.84 ;
     RECT  4.3 1126.52 5.52 1132.1 ;
     RECT  5.22 1140.12 5.52 1145.7 ;
     RECT  4.3 1213.56 5.52 1213.7 ;
     RECT  4.3 1227.84 5.52 1227.98 ;
     RECT  4.3 1255.04 5.52 1268.1 ;
     RECT  4.3 1281.9 5.52 1282.04 ;
     RECT  4.3 1295.16 5.52 1295.3 ;
     RECT  4.3 1309.1 5.52 1309.24 ;
     RECT  4.3 1316.92 5.52 1322.5 ;
     RECT  4.3 1330.52 5.52 1336.44 ;
     RECT  4.3 1344.12 5.52 1349.7 ;
     RECT  4.3 1357.72 5.52 1363.64 ;
     RECT  4.3 1371.32 5.52 1376.9 ;
     RECT  4.3 1384.92 5.52 1390.84 ;
     RECT  4.3 1398.52 5.52 1404.1 ;
     RECT  4.3 1412.12 5.52 1418.04 ;
     RECT  4.3 1425.72 5.52 1431.3 ;
     RECT  4.3 1439.32 5.52 1445.24 ;
     RECT  4.3 1452.92 5.52 1458.5 ;
     RECT  4.3 1466.52 5.52 1472.44 ;
     RECT  4.3 1480.12 5.52 1485.7 ;
     RECT  4.3 1493.72 5.52 1499.64 ;
     RECT  4.3 1507.32 5.52 1512.9 ;
     RECT  4.3 1520.92 5.52 1527.18 ;
     RECT  4.3 1535.2 5.52 1540.78 ;
     RECT  4.3 1548.12 5.52 1554.38 ;
     RECT  4.3 1562.4 5.52 1562.54 ;
     RECT  108.72 0.44 109.18 0.58 ;
     RECT  5.52 10.64 109.18 1689.36 ;
     RECT  109.18 0.44 139.84 1689.36 ;
     RECT  139.84 950.4 140.14 961.08 ;
     RECT  139.84 931.7 140.6 936.26 ;
     RECT  139.84 881.72 141.06 881.86 ;
     RECT  139.84 1518.54 141.52 1521.06 ;
     RECT  139.84 1529.08 141.52 1529.22 ;
     RECT  140.6 931.7 141.98 931.84 ;
     RECT  141.52 1520.92 141.98 1521.06 ;
     RECT  139.84 1048.32 142.44 1050.5 ;
     RECT  139.84 1480.12 142.44 1480.26 ;
     RECT  139.84 1058.52 142.9 1058.66 ;
     RECT  139.84 1137.4 144.28 1137.54 ;
     RECT  139.84 1498.14 144.28 1503.72 ;
     RECT  139.84 1561.72 145.2 1689.36 ;
     RECT  139.84 469.3 149.34 469.44 ;
     RECT  139.84 649.5 149.8 649.64 ;
     RECT  139.84 730.08 149.8 730.22 ;
     RECT  139.84 492.76 150.26 492.9 ;
     RECT  139.84 506.36 150.72 506.5 ;
     RECT  140.14 950.4 151.64 958.02 ;
     RECT  139.84 968.76 155.13 1025 ;
     RECT  142.44 1048.32 155.13 1048.46 ;
     RECT  139.84 1075.86 155.13 1076 ;
     RECT  139.84 1113.26 155.13 1113.4 ;
     RECT  139.84 1161.88 155.13 1162.02 ;
     RECT  144.28 1503.58 155.13 1503.72 ;
     RECT  139.84 161.94 155.32 162.08 ;
     RECT  151.64 950.4 160.12 950.54 ;
     RECT  151.64 957.88 160.12 958.02 ;
     RECT  155.13 968.76 160.12 1559.2 ;
     RECT  139.84 0.44 234.3 151.54 ;
     RECT  160.12 163.36 559.79 1559.2 ;
     RECT  145.2 1567.16 564.12 1689.36 ;
     RECT  559.79 1543.02 567.34 1543.16 ;
     RECT  559.79 1143.86 569.64 1144 ;
     RECT  559.79 1164.6 570.1 1164.74 ;
     RECT  559.79 163.36 570.4 1024.66 ;
     RECT  559.79 1073.82 570.4 1073.96 ;
     RECT  559.79 1123.8 570.4 1124.28 ;
     RECT  569.18 1133.66 570.4 1133.8 ;
     RECT  569.64 1143.86 570.4 1148.42 ;
     RECT  570.1 1157.8 570.4 1164.74 ;
     RECT  568.72 1486.92 570.4 1487.06 ;
     RECT  559.79 1535.2 570.4 1535.34 ;
     RECT  567.34 1543.02 570.4 1548.94 ;
     RECT  564.12 1563.08 570.4 1689.36 ;
     RECT  570.4 163.36 629.74 1689.36 ;
     RECT  629.74 1037.78 630.96 1037.92 ;
     RECT  629.74 1092.86 630.96 1093 ;
     RECT  629.74 163.36 640.92 1024.66 ;
     RECT  629.74 1068.38 640.92 1068.52 ;
     RECT  629.74 1100.34 640.92 1100.48 ;
     RECT  629.74 1117.68 640.92 1689.36 ;
     RECT  234.3 0.44 681.1 151.88 ;
     RECT  681.1 0.44 714.22 3.64 ;
     RECT  640.92 163.36 735.61 1689.36 ;
     RECT  714.22 0.44 747.34 3.3 ;
     RECT  735.61 163.36 750.26 1023.64 ;
     RECT  735.61 1100.34 750.26 1101.16 ;
     RECT  735.61 1108.5 750.26 1689.36 ;
     RECT  747.34 0.44 780.46 2.96 ;
     RECT  780.46 0.44 813.58 2.62 ;
     RECT  813.58 0.44 846.7 2.28 ;
     RECT  846.7 0.44 879.82 1.94 ;
     RECT  879.82 0.44 912.94 1.6 ;
     RECT  912.94 0.44 946.06 1.26 ;
     RECT  946.06 0.44 979.18 0.92 ;
     RECT  979.18 0.44 1045.42 0.58 ;
     RECT  1114.28 0.44 1141.88 0.58 ;
     RECT  1141.88 0.44 1227.9 0.92 ;
     RECT  681.1 10.64 1227.9 151.88 ;
     RECT  1227.9 0.44 1244.6 151.88 ;
     RECT  1244.6 0.44 1376.62 0.92 ;
     RECT  1376.62 0.44 1409.74 0.58 ;
     RECT  1244.6 10.64 1418.48 151.88 ;
     RECT  1418.48 10.64 2631.82 151.54 ;
     RECT  2631.82 10.64 2661.26 151.88 ;
     RECT  2661.26 10.64 2758.78 152.22 ;
     RECT  750.26 163.36 2758.78 1689.36 ;
     RECT  2758.78 10.64 2759.58 1689.36 ;
     RECT  2759.58 10.64 2761.22 162.76 ;
     RECT  2759.58 564.16 2766.74 564.3 ;
     RECT  2759.58 620.6 2766.74 620.74 ;
     RECT  2759.58 938.16 2766.74 938.3 ;
     RECT  2759.58 945.3 2766.97 949.18 ;
     RECT  2759.58 324.46 2767.2 324.6 ;
     RECT  2759.58 279.58 2769.04 279.72 ;
     RECT  2767.52 937.48 2769.96 937.62 ;
     RECT  2759.58 464.2 2770.42 464.34 ;
     RECT  2759.58 920.82 2770.74 920.96 ;
     RECT  2759.58 217.02 2770.88 217.16 ;
     RECT  2770.74 917.42 2771.34 920.96 ;
     RECT  2773.96 175.88 2775.8 176.7 ;
     RECT  2770.74 248.3 2777.64 248.44 ;
     RECT  2770.28 256.12 2777.64 256.26 ;
     RECT  2770.28 800.46 2778.1 800.6 ;
     RECT  2778.1 793.66 2778.56 800.6 ;
     RECT  2759.58 959.92 2778.56 960.06 ;
     RECT  2778.56 955.5 2779.02 960.06 ;
     RECT  2759.58 967.06 2779.02 1689.36 ;
     RECT  2761.22 10.64 2780.24 162.08 ;
     RECT  2775.8 175.88 2780.24 177.38 ;
     RECT  2777.18 226.2 2780.24 226.34 ;
     RECT  2777.64 248.3 2780.24 256.26 ;
     RECT  2759.58 289.44 2780.24 289.58 ;
     RECT  2759.58 355.06 2780.24 355.2 ;
     RECT  2777.64 413.88 2780.24 414.02 ;
     RECT  2778.56 793.66 2780.24 807.4 ;
     RECT  2771.34 917.42 2780.24 917.56 ;
     RECT  2766.97 945.3 2780.24 945.44 ;
     RECT  2779.02 955.5 2780.24 1689.36 ;
     RECT  2780.24 10.64 2914.1 1689.36 ;
     RECT  2914.1 254.42 2914.4 254.56 ;
     RECT  2914.1 299.64 2914.4 299.78 ;
     RECT  2914.1 388.38 2914.4 388.52 ;
     RECT  2914.1 1005.48 2914.4 1005.62 ;
     RECT  2914.1 241.16 2914.86 241.3 ;
     RECT  2914.1 1038.46 2914.86 1038.6 ;
     RECT  2914.1 214.3 2915.32 219.88 ;
     RECT  2914.1 1018.74 2915.32 1018.88 ;
     RECT  2914.1 330.92 2915.78 331.06 ;
     RECT  2914.1 1067.7 2915.78 1067.84 ;
    LAYER met2 ;
     RECT  103.2 0.27 103.34 0.44 ;
     RECT  103.2 0.44 108.86 0.78 ;
     RECT  133.1 1.8 133.24 2.14 ;
     RECT  129.88 2.14 133.24 2.48 ;
     RECT  103.2 0.78 116.68 2.82 ;
     RECT  129.42 2.48 133.24 2.82 ;
     RECT  52.6 3.67 54.58 3.74 ;
     RECT  144.6 1.46 144.74 3.74 ;
     RECT  154.72 1.12 154.86 3.74 ;
     RECT  416 0.95 416.14 3.74 ;
     RECT  714.08 3.5 714.22 3.74 ;
     RECT  747.2 3.16 747.34 3.74 ;
     RECT  780.32 2.82 780.46 3.74 ;
     RECT  813.44 2.48 813.58 3.74 ;
     RECT  846.56 2.14 846.7 3.74 ;
     RECT  879.68 1.8 879.82 3.74 ;
     RECT  912.8 1.46 912.94 3.74 ;
     RECT  945.92 1.12 946.06 3.74 ;
     RECT  979.04 0.78 979.18 3.74 ;
     RECT  1012.16 0.27 1012.3 3.74 ;
     RECT  1045.28 0.44 1045.42 3.74 ;
     RECT  1114.28 0.44 1114.42 3.74 ;
     RECT  1141.88 0.78 1142.02 3.74 ;
     RECT  1376.48 0.78 1376.62 3.74 ;
     RECT  1409.6 0.44 1409.74 3.74 ;
     RECT  1443.64 0.27 1443.78 3.74 ;
     RECT  2610.2 0.27 2610.34 3.74 ;
     RECT 648.300 4.000 648.440 4.180 ;
     RECT 52.140 4.000 54.580 4.490 ;
     RECT 52.350 3.740 54.580 4.000 ;
     RECT 416.000 4.000 416.600 4.490 ;
     RECT 416.000 3.740 416.390 4.000 ;
     RECT  647.84 4.18 648.44 4.49 ;
     RECT 680.960 4.000 681.560 4.490 ;
     RECT 680.960 3.840 681.350 4.000 ;
     RECT 714.080 4.000 714.680 4.490 ;
     RECT 714.080 3.740 714.470 4.000 ;
     RECT 747.200 4.000 747.800 4.490 ;
     RECT 747.200 3.740 747.590 4.000 ;
     RECT 780.320 4.000 780.920 4.490 ;
     RECT 780.320 3.740 780.710 4.000 ;
     RECT 813.440 4.000 814.040 4.490 ;
     RECT 813.440 3.740 813.830 4.000 ;
     RECT 846.560 4.000 847.160 4.490 ;
     RECT 846.560 3.740 846.950 4.000 ;
     RECT 879.680 4.000 880.280 4.490 ;
     RECT 879.680 3.740 880.070 4.000 ;
     RECT 912.800 4.000 913.400 4.490 ;
     RECT 912.800 3.740 913.190 4.000 ;
     RECT 945.920 4.000 946.520 4.490 ;
     RECT 945.920 3.740 946.310 4.000 ;
     RECT 979.040 4.000 979.640 4.490 ;
     RECT 979.040 3.740 979.430 4.000 ;
     RECT 1012.160 4.000 1012.760 4.490 ;
     RECT 1012.160 3.740 1012.550 4.000 ;
     RECT 1045.280 4.000 1045.880 4.490 ;
     RECT 1045.280 3.740 1045.670 4.000 ;
     RECT 1376.480 4.000 1377.080 4.490 ;
     RECT 1376.480 3.740 1376.870 4.000 ;
     RECT 1409.600 4.000 1410.200 4.490 ;
     RECT 1409.600 3.740 1409.990 4.000 ;
     RECT 1443.180 4.000 1443.780 4.490 ;
     RECT 1443.390 3.740 1443.780 4.000 ;
     RECT 103.200 4.000 133.240 4.520 ;
     RECT 103.200 2.820 118.310 4.000 ;
     RECT 118.590 2.820 133.240 4.000 ;
     RECT 615.180 4.000 615.320 4.660 ;
     RECT 582.060 4.000 582.200 5.000 ;
     RECT 2006.220 4.000 2006.360 5.710 ;
     RECT 1244.460 4.000 1244.600 6.700 ;
     RECT 19.020 4.000 19.160 10.695 ;
     RECT 383.340 4.000 383.480 10.695 ;
     RECT 1111.980 4.000 1114.420 10.695 ;
     RECT 1112.190 3.740 1114.420 4.000 ;
     RECT 1277.580 4.000 1277.720 10.695 ;
     RECT 1641.900 4.000 1642.040 10.695 ;
     RECT  2006.22 5.71 2007.28 10.695 ;
     RECT 2370.540 4.000 2370.680 10.695 ;
     RECT 2536.140 4.000 2536.280 10.695 ;
     RECT 2734.860 4.000 2735.000 10.695 ;
     RECT 2900.460 4.000 2900.600 10.695 ;
     RECT 1476.300 4.000 1476.440 11.460 ;
     RECT 1509.420 4.000 1509.560 11.460 ;
     RECT 1542.540 4.000 1542.680 11.460 ;
     RECT 1575.660 4.000 1575.800 11.460 ;
     RECT 1608.780 4.000 1608.920 11.460 ;
     RECT  1641.9 10.695 1646.93 11.46 ;
     RECT 1675.020 4.000 1675.160 11.460 ;
     RECT 1708.140 4.000 1708.280 11.460 ;
     RECT 1741.260 4.000 1741.400 11.460 ;
     RECT 1774.380 4.000 1774.520 11.460 ;
     RECT 1807.500 4.000 1807.640 11.460 ;
     RECT 1840.620 4.000 1840.760 11.460 ;
     RECT 1873.740 4.000 1873.880 11.460 ;
     RECT 1906.860 4.000 1907.000 11.460 ;
     RECT 1939.980 4.000 1940.120 11.460 ;
     RECT 1973.100 4.000 1973.240 11.460 ;
     RECT  2004.11 10.695 2007.28 11.46 ;
     RECT 2039.340 4.000 2039.480 11.460 ;
     RECT 2072.460 4.000 2072.600 11.460 ;
     RECT 2105.580 4.000 2105.720 11.460 ;
     RECT 2138.700 4.000 2138.840 11.460 ;
     RECT 2171.820 4.000 2171.960 11.460 ;
     RECT 2204.940 4.000 2205.080 11.460 ;
     RECT 2238.060 4.000 2238.200 11.460 ;
     RECT 2271.180 4.000 2271.320 11.460 ;
     RECT 2304.300 4.000 2304.440 11.460 ;
     RECT 2337.420 4.000 2337.560 11.460 ;
     RECT  2364.11 10.695 2370.68 11.46 ;
     RECT 2403.660 4.000 2403.800 11.460 ;
     RECT 2436.780 4.000 2436.920 11.460 ;
     RECT 2469.900 4.000 2470.040 11.460 ;
     RECT 2503.020 4.000 2503.160 11.460 ;
     RECT 2569.260 4.000 2569.400 11.460 ;
     RECT 2602.380 4.000 2610.340 11.460 ;
     RECT 2602.590 3.740 2610.340 4.000 ;
     RECT 2635.500 4.000 2635.640 11.460 ;
     RECT 2668.620 4.000 2668.760 11.460 ;
     RECT 2701.740 4.000 2701.880 11.460 ;
     RECT 2767.980 4.000 2768.120 11.460 ;
     RECT 2801.100 4.000 2801.240 11.460 ;
     RECT 2834.220 4.000 2834.360 11.460 ;
     RECT  2900.46 10.695 2906.93 11.46 ;
     RECT  1464.11 10.695 1466.93 12 ;
     RECT  2004.11 11.46 2006.93 12 ;
     RECT  2364.11 11.46 2366.93 12 ;
     RECT 2867.340 4.000 2867.480 12.000 ;
     RECT  1277.58 10.695 1286.93 12.14 ;
     RECT  2724.11 10.695 2735 12.14 ;
     RECT 548.940 4.000 549.080 12.510 ;
     RECT  2867.34 12 2871.62 13.02 ;
     RECT  19.02 10.695 26.93 13.415 ;
     RECT 184.620 4.000 184.760 13.415 ;
     RECT  548.48 12.51 549.08 13.415 ;
     RECT  1632.24 12 1632.38 13.415 ;
     RECT  1997.48 12 2006.93 13.415 ;
     RECT  2171.82 11.46 2171.93 13.415 ;
     RECT  2356.74 12 2366.93 13.415 ;
     RECT  2536.14 10.695 2546.93 13.415 ;
     RECT  2703.12 12 2703.26 13.415 ;
     RECT 1211.340 4.000 1211.480 17.240 ;
     RECT  103.2 4.52 134.16 17.44 ;
     RECT 144.600 4.000 154.860 17.440 ;
     RECT 144.600 3.740 151.430 4.000 ;
     RECT 151.710 3.740 154.860 4.000 ;
     RECT 1178.220 4.000 1178.360 17.580 ;
     RECT 1141.880 4.000 1145.240 17.920 ;
     RECT 1141.880 3.740 1145.030 4.000 ;
     RECT 1078.860 4.000 1079.000 18.600 ;
     RECT  54.44 4.49 54.58 34.43 ;
     RECT  54.44 34.43 55.04 34.57 ;
     RECT  1500.68 12 1500.82 37.5 ;
     RECT  2232.08 12 2232.22 37.5 ;
     RECT  2570.64 12 2570.78 37.5 ;
     RECT  2659.88 12 2660.02 37.5 ;
     RECT  2140.08 12 2140.22 40.22 ;
     RECT  2156.18 12 2156.32 40.22 ;
     RECT  2197.58 12 2197.72 40.22 ;
     RECT  2603.76 11.46 2610.34 40.22 ;
     RECT  1227.9 6.56 1228.04 41.38 ;
     RECT  1742.64 12 1742.78 42.94 ;
     RECT  1900.88 12 1901.02 42.94 ;
     RECT  2338.8 12 2338.94 42.94 ;
     RECT  2349.11 13.415 2366.93 42.94 ;
     RECT  1577.96 12 1578.1 45.66 ;
     RECT  1629.11 13.415 1632.38 45.66 ;
     RECT  1644.11 11.46 1646.93 45.66 ;
     RECT  1676.4 12 1676.54 45.66 ;
     RECT  1824.11 10.695 1826.93 45.66 ;
     RECT  1941.36 12 1941.5 45.66 ;
     RECT  1989.11 13.415 2006.93 45.66 ;
     RECT  2121.68 12 2121.82 45.66 ;
     RECT  2140.08 40.22 2156.32 45.66 ;
     RECT  2285.44 37.5 2285.58 45.66 ;
     RECT  2529.11 13.415 2546.93 45.66 ;
     RECT  2603.76 40.22 2616.32 45.66 ;
     RECT  2197.58 40.22 2199.1 50.9 ;
     RECT  1412.36 42.94 1412.5 51.1 ;
     RECT  1535.18 12 1535.32 51.1 ;
     RECT  1900.88 42.94 1907.46 51.1 ;
     RECT  2198.96 50.9 2199.1 51.1 ;
     RECT  2232.08 37.5 2237.74 51.1 ;
     RECT  1464.11 12 1473.22 51.24 ;
     RECT  1933.54 45.66 1941.5 51.24 ;
     RECT  2121.68 45.66 2156.32 51.24 ;
     RECT  2232.08 51.1 2238.2 51.24 ;
     RECT  2273.94 12 2274.08 51.24 ;
     RECT  2338.8 42.94 2366.93 51.24 ;
     RECT  2651.14 37.5 2660.02 51.24 ;
     RECT  1610.16 12 1610.3 52.12 ;
     RECT  1209.04 41.24 1209.18 52.26 ;
     RECT  1412.36 51.1 1413.42 52.26 ;
     RECT  1464.11 51.24 1467.24 52.26 ;
     RECT  1609.7 52.12 1615.82 52.26 ;
     RECT  1676.4 45.66 1682.06 52.26 ;
     RECT  1693.88 12 1694.02 52.26 ;
     RECT  1775.76 12 1775.9 52.26 ;
     RECT  1797.38 12 1797.52 52.26 ;
     RECT  1842 12 1842.14 52.26 ;
     RECT  1866.38 12 1866.52 52.26 ;
     RECT  1900.88 51.1 1907.92 52.26 ;
     RECT  1969.88 12 1970.02 52.26 ;
     RECT  1980.92 45.66 2007.74 52.26 ;
     RECT  2025.08 12 2025.22 52.26 ;
     RECT  2121.68 51.24 2149.88 52.26 ;
     RECT  2198.96 51.1 2199.56 52.26 ;
     RECT  2237.6 51.24 2238.2 52.26 ;
     RECT  2301.08 12 2301.22 52.26 ;
     RECT  2405.04 12 2405.18 52.26 ;
     RECT  2501.18 12 2501.32 52.26 ;
     RECT  2528.78 45.66 2546.93 52.26 ;
     RECT  2569.26 37.5 2570.78 52.26 ;
     RECT  2632.28 12 2632.42 52.26 ;
     RECT  2703.12 13.415 2711.93 52.26 ;
     RECT  2832.84 13.02 2832.98 52.6 ;
     RECT  1500.22 37.5 1500.82 52.77 ;
     RECT  1577.5 45.66 1578.1 52.77 ;
     RECT  2862.28 13.02 2871.62 52.94 ;
     RECT 250.860 4.000 251.000 53.140 ;
     RECT  1615.68 52.26 1615.82 53.28 ;
     RECT  2528.78 52.26 2532.6 53.28 ;
     RECT  1464.11 52.26 1466.93 53.82 ;
     RECT  1535.18 51.1 1539 53.96 ;
     RECT  1740.8 42.94 1742.78 53.96 ;
     RECT  2059.58 12 2059.72 53.96 ;
     RECT  2121.68 52.26 2149.42 53.96 ;
     RECT  2432.18 12 2432.32 53.96 ;
     RECT  2466.68 12 2466.82 53.96 ;
     RECT  1538.86 53.96 1539 56.68 ;
     RECT  2775.34 56.54 2775.48 57.9 ;
     RECT  2529.11 53.28 2532.6 58.21 ;
     RECT  2760.16 55.52 2760.3 58.24 ;
     RECT  2775.34 57.9 2779.62 58.24 ;
     RECT  2724.11 12.14 2726.93 58.58 ;
     RECT  2169.11 13.415 2171.93 58.92 ;
     RECT  2004.11 52.26 2007.74 59.26 ;
     RECT  2129.5 53.96 2138.38 60.42 ;
     RECT  2341.56 51.24 2366.93 60.42 ;
     RECT  2455.18 45.66 2455.32 60.42 ;
     RECT  2529.11 58.21 2532.14 60.42 ;
     RECT  2602.38 45.66 2616.32 60.42 ;
     RECT  2284.06 45.66 2285.58 60.76 ;
     RECT  1666.28 53.48 1666.42 61.98 ;
     RECT  1809.11 13.415 1811.93 61.98 ;
     RECT  1821.3 45.66 1826.93 61.98 ;
     RECT  1629.11 45.66 1646.93 62.12 ;
     RECT  1740.8 53.96 1740.94 62.12 ;
     RECT  1785.88 45.66 1786.02 62.12 ;
     RECT  2415.16 40.22 2415.3 63.14 ;
     RECT  2760.16 58.24 2779.62 63.68 ;
     RECT  2609.74 60.42 2616.32 63.82 ;
     RECT  2609.74 63.82 2610.34 64.16 ;
     RECT  1412.36 52.26 1412.5 65.72 ;
     RECT  1461.58 53.82 1466.93 65.86 ;
     RECT  2349.11 60.42 2366.93 65.86 ;
     RECT  2486.92 37.5 2487.06 65.86 ;
     RECT  2651.14 51.24 2651.28 65.86 ;
     RECT  1500.68 52.77 1500.82 67.56 ;
     RECT  2237.6 52.26 2237.74 67.56 ;
     RECT  1725.16 45.66 1725.3 69.26 ;
     RECT  1752.76 61.98 1752.9 69.26 ;
     RECT  1852.12 45.66 1852.26 69.26 ;
     RECT  2285.44 60.76 2285.58 69.26 ;
     RECT  2164.92 58.92 2171.93 71.16 ;
     RECT  2184.11 10.695 2186.93 71.16 ;
     RECT  2164.92 71.16 2186.93 71.3 ;
     RECT  1629.11 62.12 1631.93 72.18 ;
     RECT  1644.11 62.12 1646.93 72.18 ;
     RECT  1980.92 52.26 1991.93 72.18 ;
     RECT  1577.96 52.77 1578.1 72.32 ;
     RECT  1887.08 42.94 1887.22 72.32 ;
     RECT  244.42 53.14 251 72.49 ;
     RECT  2569.26 52.26 2569.4 72.49 ;
     RECT  1976.78 72.18 1991.93 76.6 ;
     RECT  2004.11 59.26 2015.1 76.6 ;
     RECT  2198.96 52.26 2199.1 76.6 ;
     RECT  1976.78 76.6 2015.1 76.74 ;
     RECT  2198.96 76.6 2208.3 76.74 ;
     RECT  2871.48 52.94 2871.62 76.74 ;
     RECT  1933.54 51.24 1933.68 79.32 ;
     RECT  1410.98 65.72 1412.5 79.46 ;
     RECT  1907.32 52.26 1907.46 79.46 ;
     RECT  2042.56 40.22 2042.7 79.46 ;
     RECT  2724.11 58.58 2732.7 83.2 ;
     RECT  1809.11 61.98 1826.93 86.26 ;
     RECT  2249.56 67.42 2249.7 86.26 ;
     RECT  2904.11 11.46 2906.93 89.18 ;
     RECT  1557.72 56.54 1557.86 89.32 ;
     RECT  2149.28 53.96 2149.42 93.06 ;
     RECT  2208.16 76.74 2208.3 95.78 ;
     RECT  1989.11 76.74 2015.1 96.46 ;
     RECT  2045.78 96.32 2045.92 99.72 ;
     RECT  1866.38 69.12 1866.52 99.86 ;
     RECT  1976.78 76.74 1976.92 99.86 ;
     RECT  1362.68 79.32 1362.82 106.86 ;
     RECT  1410.98 79.46 1411.12 107 ;
     RECT  2222.88 95.64 2223.02 108.36 ;
     RECT  2760.16 63.68 2787.9 110.6 ;
     RECT  2080.28 79.32 2080.42 110.74 ;
     RECT  2749.12 83.06 2749.26 110.74 ;
     RECT  1933.54 79.32 1935.52 113.66 ;
     RECT  2904.11 89.18 2913.48 113.66 ;
     RECT  1659.38 61.98 1666.42 113.8 ;
     RECT  1809.11 86.26 1812.7 113.8 ;
     RECT  1887.54 99.72 1887.68 113.8 ;
     RECT  2045.78 99.72 2049.6 113.8 ;
     RECT  2280.38 86.12 2280.52 117.54 ;
     RECT  1104.11 10.695 1114.42 120.77 ;
     RECT  1361.76 106.86 1362.82 124.34 ;
     RECT  103.2 17.44 154.86 128.28 ;
     RECT 482.700 4.000 482.840 128.420 ;
     RECT  1569.22 89.18 1569.36 128.42 ;
     RECT 515.820 4.000 515.960 128.760 ;
     RECT  1837.86 86.12 1838 128.76 ;
     RECT 85.260 4.000 85.400 128.960 ;
     RECT 449.580 4.000 449.720 129.100 ;
     RECT  2169.11 71.3 2186.93 129.1 ;
     RECT  85.26 128.96 89.54 129.3 ;
     RECT  102.74 128.28 154.86 129.3 ;
     RECT 283.980 4.000 284.120 129.440 ;
     RECT  1141.88 17.92 1142.02 132.33 ;
     RECT  1514.48 67.42 1514.62 132.33 ;
     RECT  2798.34 128.62 2798.48 134.4 ;
     RECT  1169.48 52.12 1169.62 134.54 ;
     RECT  1681.92 52.26 1682.06 134.54 ;
     RECT  1697.1 113.66 1697.24 134.74 ;
     RECT  2797.88 134.4 2798.48 134.74 ;
     RECT  2815.36 64.36 2815.5 134.74 ;
     RECT  1629.11 72.18 1646.93 134.88 ;
     RECT  1776.68 69.12 1776.82 134.88 ;
     RECT  1742.18 69.12 1742.32 135.22 ;
     RECT  1852.12 113.66 1852.26 135.56 ;
     RECT  204.11 10.695 206.93 136.185 ;
     RECT  383.34 10.695 386.93 136.185 ;
     RECT  564.11 10.695 566.93 136.185 ;
     RECT  744.11 10.695 746.93 136.185 ;
     RECT  924.11 10.695 926.93 136.185 ;
     RECT  1104.11 120.77 1106.93 136.185 ;
     RECT  1284.11 12.14 1286.93 136.185 ;
     RECT  1464.11 65.86 1466.93 136.185 ;
     RECT  1644.11 134.88 1646.93 136.185 ;
     RECT  1824.11 86.26 1826.93 136.185 ;
     RECT  1989.11 96.46 2006.93 136.185 ;
     RECT  2184.11 129.1 2186.93 136.185 ;
     RECT  2364.11 65.86 2366.93 136.185 ;
     RECT  2544.11 52.26 2546.93 136.185 ;
     RECT  2724.11 83.2 2726.93 136.185 ;
     RECT  1989.11 136.185 1997.62 136.58 ;
     RECT  2087.64 113.66 2087.78 136.58 ;
     RECT  2200.8 109.24 2200.94 136.92 ;
     RECT  1933.54 113.66 1938.74 137.26 ;
     RECT  2263.36 108.22 2263.5 137.26 ;
     RECT  2104.66 110.6 2104.8 137.6 ;
     RECT  2311.66 117.4 2311.8 137.6 ;
     RECT  1089.11 13.415 1091.93 137.8 ;
     RECT  1956.08 110.6 1956.22 137.8 ;
     RECT  1933.54 137.26 1933.68 137.94 ;
     RECT  184.62 13.415 191.93 138.905 ;
     RECT  369.11 13.415 371.93 138.905 ;
     RECT  548.48 13.415 551.93 138.905 ;
     RECT  729.11 13.415 731.93 138.905 ;
     RECT  909.11 13.415 911.93 138.905 ;
     RECT  1082.54 137.8 1091.93 138.905 ;
     RECT  1269.11 13.415 1271.93 138.905 ;
     RECT  1449.11 13.415 1451.93 138.905 ;
     RECT  1629.11 134.88 1631.93 138.905 ;
     RECT  1809.11 113.8 1811.93 138.905 ;
     RECT  1989.11 136.58 1991.93 138.905 ;
     RECT  2169.11 129.1 2171.93 138.905 ;
     RECT  2349.11 65.86 2351.93 138.905 ;
     RECT  2529.11 60.42 2531.93 138.905 ;
     RECT  2709.11 52.26 2711.93 138.905 ;
     RECT  9.11 13.415 26.93 139.67 ;
     RECT  85.26 129.3 154.86 139.84 ;
     RECT 217.740 4.000 217.880 140.660 ;
     RECT  250.86 72.49 251 141 ;
     RECT  85.26 139.84 156.24 141.2 ;
     RECT  1345.66 124.2 1345.8 141.34 ;
     RECT  1695.72 134.74 1697.24 141.34 ;
     RECT  1361.76 124.34 1361.9 141.68 ;
     RECT  676.82 137.12 676.96 142.02 ;
     RECT  2035.2 136.44 2035.34 142.02 ;
     RECT  548.48 138.905 548.62 142.36 ;
     RECT  2045.78 113.8 2045.92 142.36 ;
     RECT  85.26 141.2 158.08 142.56 ;
     RECT  2758.78 110.6 2787.9 142.56 ;
     RECT  2797.88 134.74 2815.5 142.56 ;
     RECT  383.34 136.185 383.48 142.7 ;
     RECT  2138.24 60.42 2138.38 142.7 ;
     RECT  82.5 142.56 158.08 142.9 ;
     RECT 350.220 4.000 350.360 143.040 ;
     RECT  2228.4 137.12 2228.54 143.04 ;
     RECT 317.100 4.000 317.240 143.380 ;
     RECT  2280.38 137.46 2280.52 143.38 ;
     RECT  2889.11 13.415 2891.93 143.58 ;
     RECT  2904.11 113.66 2913.94 145.93 ;
     RECT  2869.64 77.28 2869.78 147.8 ;
     RECT  2836.06 131 2836.2 148 ;
     RECT  2610.2 64.16 2610.34 149.19 ;
     RECT  1469.86 148.34 1470 150 ;
     RECT  2609.97 149.19 2610.34 150 ;
     RECT  2619.86 147.66 2620 150 ;
     RECT  1449.86 150 1450.14 150.38 ;
     RECT  1459.86 150 1460.14 150.38 ;
     RECT  1439.86 150 1440.14 150.55 ;
     RECT  1449.86 150.38 1460.14 150.55 ;
     RECT  1469.86 150 1470.14 150.55 ;
     RECT  1479.86 150 1480.14 150.55 ;
     RECT  82.04 142.9 158.08 150.72 ;
     RECT  2836.06 148 2843.1 151.4 ;
     RECT  2888.04 143.58 2891.93 151.4 ;
     RECT  1419.86 150 1420.14 151.74 ;
     RECT  2629.86 150 2630.14 151.74 ;
     RECT  2639.86 150 2640.14 151.74 ;
     RECT  2659.86 150 2660.14 151.91 ;
     RECT  2758.78 142.56 2815.5 151.91 ;
     RECT  82.04 150.72 158.54 153.74 ;
     RECT  184.62 138.905 184.76 153.74 ;
     RECT  234.3 150.38 234.44 153.74 ;
     RECT  303.76 141.54 303.9 153.74 ;
     RECT  1082.54 138.905 1082.68 153.74 ;
     RECT  1418.34 151.74 1420.14 153.74 ;
     RECT  1429.86 150 1430.14 153.74 ;
     RECT  1439.86 150.55 1460.14 153.74 ;
     RECT  1469.86 150.55 1480.14 153.74 ;
     RECT  1666.28 113.8 1666.42 153.74 ;
     RECT  1695.72 141.34 1695.86 153.74 ;
     RECT  1950.1 137.8 1956.22 153.74 ;
     RECT  2609.86 150 2610.34 153.74 ;
     RECT  2619.86 150 2620.14 153.74 ;
     RECT  2629.86 151.74 2640.14 153.74 ;
     RECT  2649.86 150 2650.14 153.74 ;
     RECT  2659.86 151.91 2661.4 153.74 ;
     RECT  2758.78 151.91 2815.96 153.74 ;
     RECT  4.3 139.67 26.93 153.95 ;
     RECT  82.04 153.74 2815.96 154.46 ;
     RECT  82.04 154.46 2819.18 158.88 ;
     RECT  2 153.95 26.93 160.75 ;
     RECT  2836.06 151.4 2850 161.43 ;
     RECT  2836.06 161.43 2856.9 175.88 ;
     RECT  82.04 158.88 2825.62 189.14 ;
     RECT  2836.06 175.88 2858.28 202.2 ;
     RECT  65.48 186.59 65.62 207.67 ;
     RECT  82.04 189.14 2826.54 207.67 ;
     RECT  65.48 207.67 2826.54 210.22 ;
     RECT  2836.06 202.2 2856.9 210.22 ;
     RECT  2904.11 145.93 2913.48 214.3 ;
     RECT  2875.62 202.74 2875.76 256.12 ;
     RECT  2866.88 256.12 2875.76 265.64 ;
     RECT  2887.58 151.4 2891.93 265.64 ;
     RECT  1.54 160.75 26.93 280.43 ;
     RECT  54.9 34.57 55.04 308.99 ;
     RECT  65.48 210.22 2856.9 308.99 ;
     RECT  2866.88 265.64 2891.93 321.4 ;
     RECT  2904.11 214.3 2915.32 330.92 ;
     RECT  54.9 308.99 2856.9 341.46 ;
     RECT  2866.88 321.4 2894.62 341.46 ;
     RECT  54.9 341.46 2894.62 355.06 ;
     RECT  2904.11 330.92 2915.78 355.06 ;
     RECT  54.9 355.06 2915.78 371.04 ;
     RECT  53.06 371.04 2915.78 379.54 ;
     RECT  48.92 379.54 2915.78 398.24 ;
     RECT  44.78 398.24 2915.78 406.74 ;
     RECT  38.34 406.74 2915.78 433.94 ;
     RECT  0.62 280.43 26.93 479.84 ;
     RECT  37.88 433.94 2915.78 479.84 ;
     RECT  0.62 479.84 2915.78 968.9 ;
     RECT  42.48 968.9 2915.78 969.39 ;
     RECT  168.03 969.39 2915.78 970 ;
     RECT  238.44 970 255.6 970.6 ;
     RECT  337.34 970 354.5 979.3 ;
     RECT  1505.28 970 1505.42 979.3 ;
     RECT  270.18 970 278.6 979.47 ;
     RECT  288.12 970 321.38 979.47 ;
     RECT  732.94 970 735.38 979.47 ;
     RECT  1753.68 970 1753.82 979.47 ;
     RECT  1635.92 970 1637.9 979.64 ;
     RECT  1650.18 970 1654.46 979.64 ;
     RECT  1919.28 970 1919.42 979.64 ;
     RECT  366.78 970 387.62 979.98 ;
     RECT  732.94 979.47 737.68 980.15 ;
     RECT  2084.88 970 2085.02 980.32 ;
     RECT  270.18 979.47 321.38 980.66 ;
     RECT  337.34 979.3 357.26 980.66 ;
     RECT  366.78 979.98 393.6 980.66 ;
     RECT  1635.92 979.64 1654.46 980.66 ;
     RECT  205.32 970 205.46 980.83 ;
     RECT  420.6 970 437.3 980.83 ;
     RECT  270.18 980.66 322.3 981 ;
     RECT  337.34 980.66 393.6 981 ;
     RECT  238.44 970.6 255.14 981.34 ;
     RECT  188.76 970 188.9 981.735 ;
     RECT  553.08 970 553.22 981.735 ;
     RECT  732.94 980.15 738.14 981.735 ;
     RECT  900.84 970 900.98 981.735 ;
     RECT  917.4 970 917.54 981.735 ;
     RECT  1083 970 1083.14 981.735 ;
     RECT  1099.56 970 1099.7 981.735 ;
     RECT  1248.6 970 1265.3 981.735 ;
     RECT  1455.6 970 1455.74 981.735 ;
     RECT  1621.2 970 1621.34 981.735 ;
     RECT  1635.92 980.66 1657.22 981.735 ;
     RECT  1798.3 970 1803.5 981.735 ;
     RECT  1819.92 970 1820.06 981.735 ;
     RECT  1985.52 970 1985.66 981.735 ;
     RECT  2167.68 970 2167.82 981.735 ;
     RECT  188.76 981.735 191.93 982.19 ;
     RECT  203.02 980.83 205.46 982.19 ;
     RECT  186.46 982.19 191.93 982.36 ;
     RECT  2267.04 970 2270.86 982.36 ;
     RECT  404.04 970 404.18 982.5 ;
     RECT  503.4 970 507.68 982.5 ;
     RECT  519.96 970 520.1 982.5 ;
     RECT  536.52 970 536.66 982.5 ;
     RECT  569.64 970 569.78 982.5 ;
     RECT  586.2 970 586.34 982.5 ;
     RECT  602.76 970 602.9 982.5 ;
     RECT  619.32 970 619.46 982.5 ;
     RECT  635.88 970 636.02 982.5 ;
     RECT  669 970 669.14 982.5 ;
     RECT  685.56 970 685.7 982.5 ;
     RECT  702.12 970 702.26 982.5 ;
     RECT  718.68 970 718.82 982.5 ;
     RECT  751.8 970 751.94 982.5 ;
     RECT  768.36 970 768.5 982.5 ;
     RECT  784.92 970 785.06 982.5 ;
     RECT  801.48 970 801.62 982.5 ;
     RECT  818.04 970 818.18 982.5 ;
     RECT  834.6 970 834.74 982.5 ;
     RECT  867.72 970 867.86 982.5 ;
     RECT  884.28 970 884.42 982.5 ;
     RECT  900.84 981.735 917.54 982.5 ;
     RECT  933.96 970 934.1 982.5 ;
     RECT  950.52 970 950.66 982.5 ;
     RECT  967.08 970 967.22 982.5 ;
     RECT  983.64 970 983.78 982.5 ;
     RECT  1000.2 970 1000.34 982.5 ;
     RECT  1016.76 970 1016.9 982.5 ;
     RECT  1033.32 970 1033.46 982.5 ;
     RECT  1049.88 970 1050.02 982.5 ;
     RECT  1066.44 970 1066.58 982.5 ;
     RECT  1083 981.735 1099.7 982.5 ;
     RECT  1116.12 970 1116.26 982.5 ;
     RECT  1132.68 970 1132.82 982.5 ;
     RECT  1149.24 970 1149.38 982.5 ;
     RECT  1165.8 970 1165.94 982.5 ;
     RECT  1182.36 970 1182.5 982.5 ;
     RECT  1198.92 970 1199.06 982.5 ;
     RECT  1215.48 970 1215.62 982.5 ;
     RECT  1232.04 970 1232.18 982.5 ;
     RECT  1248.6 981.735 1271.93 982.5 ;
     RECT  1281.72 970 1281.86 982.5 ;
     RECT  1298.28 970 1298.42 982.5 ;
     RECT  1314.84 970 1314.98 982.5 ;
     RECT  1331.4 970 1331.54 982.5 ;
     RECT  1356.24 970 1356.38 982.5 ;
     RECT  1372.8 970 1372.94 982.5 ;
     RECT  1389.36 970 1389.5 982.5 ;
     RECT  1405.92 970 1406.06 982.5 ;
     RECT  1418.34 970 1422.62 982.5 ;
     RECT  1439.04 970 1439.18 982.5 ;
     RECT  1449.11 981.735 1455.74 982.5 ;
     RECT  1488.72 970 1488.86 982.5 ;
     RECT  1521.84 970 1521.98 982.5 ;
     RECT  1538.4 970 1538.54 982.5 ;
     RECT  1571.52 970 1571.66 982.5 ;
     RECT  1604.64 970 1604.78 982.5 ;
     RECT  1621.2 981.735 1657.22 982.5 ;
     RECT  1670.88 970 1671.02 982.5 ;
     RECT  1680.54 970 1687.58 982.5 ;
     RECT  1704 970 1706.44 982.5 ;
     RECT  1720.56 970 1724.84 982.5 ;
     RECT  1737.12 970 1743.7 982.5 ;
     RECT  1770.24 970 1786.94 982.5 ;
     RECT  1798.3 981.735 1820.06 982.5 ;
     RECT  1847.98 970 1869.74 982.5 ;
     RECT  1880.18 970 1886.3 982.5 ;
     RECT  1902.72 970 1902.86 982.5 ;
     RECT  1916.06 979.64 1919.42 982.5 ;
     RECT  1935.84 970 1935.98 982.5 ;
     RECT  1952.4 970 1952.54 982.5 ;
     RECT  1968.96 970 1969.1 982.5 ;
     RECT  1985.52 981.735 1991.93 982.5 ;
     RECT  2002.08 970 2002.22 982.5 ;
     RECT  2035.2 970 2035.34 982.5 ;
     RECT  2068.32 970 2068.46 982.5 ;
     RECT  2101.44 970 2101.58 982.5 ;
     RECT  2118 970 2118.14 982.5 ;
     RECT  2133.64 970 2134.7 982.5 ;
     RECT  2147.9 970 2151.26 982.5 ;
     RECT  2167.68 981.735 2171.93 982.5 ;
     RECT  2195.74 970 2200.94 982.5 ;
     RECT  2210.46 970 2217.5 982.5 ;
     RECT  2227.48 970 2234.06 982.5 ;
     RECT  2244.04 970 2250.62 982.5 ;
     RECT  2283.6 970 2283.74 982.5 ;
     RECT  2296.02 970 2726.72 982.5 ;
     RECT  453.72 970 453.86 982.7 ;
     RECT  2015.88 970 2018.78 982.7 ;
     RECT  2262.44 982.36 2270.86 982.7 ;
     RECT  185.54 982.36 191.93 982.87 ;
     RECT  2261.98 982.7 2270.86 982.87 ;
     RECT  2261.06 982.87 2270.86 983.18 ;
     RECT  2300.16 982.5 2643.92 983.18 ;
     RECT  652.44 970 652.58 983.38 ;
     RECT  2300.16 983.18 2300.3 983.52 ;
     RECT  1553.58 970 1555.1 983.55 ;
     RECT  1742.18 982.5 1743.7 983.55 ;
     RECT  1753.68 979.47 1759.34 983.55 ;
     RECT  2701.74 982.5 2726.72 983.55 ;
     RECT  1472.16 970 1472.3 983.72 ;
     RECT  549.11 981.735 553.22 984.06 ;
     RECT  1680.54 982.5 1680.68 984.06 ;
     RECT  202.56 982.19 205.46 984.455 ;
     RECT  549.11 984.06 555.52 984.455 ;
     RECT  729.11 981.735 738.14 984.455 ;
     RECT  923.38 983.72 923.52 984.455 ;
     RECT  1472.16 983.72 1473.22 984.455 ;
     RECT  1830.5 970 1836.62 984.455 ;
     RECT  2015.88 982.7 2024.3 984.455 ;
     RECT  2184.24 970 2184.38 984.455 ;
     RECT  2195.74 982.5 2197.72 984.455 ;
     RECT  2083.96 980.32 2085.02 985.08 ;
     RECT  202.56 984.455 206.93 985.42 ;
     RECT  238.44 981.34 260.2 985.42 ;
     RECT  270.18 981 393.6 985.42 ;
     RECT  470.28 970 486.98 985.42 ;
     RECT  549.11 984.455 566.93 985.56 ;
     RECT  2003.46 984.455 2024.3 985.56 ;
     RECT  42.48 969.39 158.54 985.76 ;
     RECT  172.2 970 172.34 985.76 ;
     RECT  2227.48 982.5 2227.62 985.76 ;
     RECT  1501.14 979.3 1505.42 986.27 ;
     RECT  221.88 970 228 986.78 ;
     RECT  42.48 985.76 172.34 987.8 ;
     RECT  184.62 982.87 191.93 987.8 ;
     RECT  420.6 980.83 443.28 987.8 ;
     RECT  470.28 985.42 497.1 987.8 ;
     RECT  2701.74 983.55 2727.64 987.8 ;
     RECT  2743.14 970 2915.78 987.8 ;
     RECT  419.22 987.8 443.28 988.14 ;
     RECT  453.72 982.7 454.78 988.14 ;
     RECT  419.22 988.14 454.78 988.31 ;
     RECT  2169.11 982.5 2171.93 988.31 ;
     RECT  2184.11 984.455 2197.72 988.31 ;
     RECT  221.42 986.78 228 988.48 ;
     RECT  42.48 987.8 191.93 988.62 ;
     RECT  202.56 985.42 210.06 988.82 ;
     RECT  221.42 988.48 228.92 988.82 ;
     RECT  238.44 985.42 393.6 988.82 ;
     RECT  2051.3 970 2051.9 988.99 ;
     RECT  413.7 988.31 454.78 989.16 ;
     RECT  466.14 987.8 497.1 989.16 ;
     RECT  652.44 983.38 659.94 989.16 ;
     RECT  648.3 989.16 659.94 989.3 ;
     RECT  413.7 989.16 497.1 989.5 ;
     RECT  0.62 968.9 32.96 989.64 ;
     RECT  2003.46 985.56 2016.02 989.81 ;
     RECT  202.56 988.82 395.44 990.66 ;
     RECT  648.3 989.3 655.8 990.66 ;
     RECT  1464.11 984.455 1473.22 990.86 ;
     RECT  1501.14 986.27 1511.4 990.86 ;
     RECT  1521.38 990.52 1521.52 990.86 ;
     RECT  1584.86 970 1593.28 990.86 ;
     RECT  1615.22 986.78 1615.36 990.86 ;
     RECT  1823.14 984.455 1836.62 990.86 ;
     RECT  1847.98 982.5 1850.42 990.86 ;
     RECT  411.4 989.5 497.1 991 ;
     RECT  1605.1 990.86 1615.36 991 ;
     RECT  2225.18 985.76 2227.62 991 ;
     RECT  202.56 990.66 393.6 991.03 ;
     RECT  1989.11 982.5 1991.93 991.03 ;
     RECT  178.18 988.62 191.93 991.34 ;
     RECT  851.16 970 851.3 991.54 ;
     RECT  1501.14 990.86 1521.52 991.54 ;
     RECT  1553.58 983.55 1564.3 991.54 ;
     RECT  1629.11 982.5 1657.22 991.85 ;
     RECT  1989.11 991.03 1993.94 991.85 ;
     RECT  1464.11 990.86 1473.68 991.88 ;
     RECT  1430.3 983.38 1430.44 992.22 ;
     RECT  1724.7 982.5 1724.84 992.22 ;
     RECT  2244.04 982.5 2244.18 992.39 ;
     RECT  1428.46 992.22 1430.44 993.24 ;
     RECT  1449.11 982.5 1452.52 993.24 ;
     RECT  1495.62 991.54 1521.52 993.24 ;
     RECT  1539.78 990.52 1542.22 993.24 ;
     RECT  1642.36 991.85 1657.22 993.24 ;
     RECT  1680.08 984.06 1680.68 993.24 ;
     RECT  1823.14 990.86 1850.42 993.24 ;
     RECT  1860.86 982.5 1861 993.24 ;
     RECT  1552.2 991.54 1564.3 993.75 ;
     RECT  1407.3 992.22 1407.44 993.92 ;
     RECT  1642.36 993.24 1660.9 993.92 ;
     RECT  1809.11 982.5 1811.93 993.92 ;
     RECT  1823.14 993.24 1865.14 993.92 ;
     RECT  412.32 991 497.1 994.26 ;
     RECT  507.54 982.5 507.68 994.26 ;
     RECT  1418.34 982.5 1418.48 994.26 ;
     RECT  1428 993.24 1430.44 994.26 ;
     RECT  1583.48 990.86 1593.28 994.26 ;
     RECT  1880.18 982.5 1880.78 994.26 ;
     RECT  2133.64 982.5 2133.78 994.26 ;
     RECT  182.32 991.34 191.93 994.6 ;
     RECT  202.1 991.03 393.6 994.6 ;
     RECT  1406.84 993.92 1407.44 994.6 ;
     RECT  1418.34 994.26 1430.44 994.6 ;
     RECT  1449.11 993.24 1452.98 994.6 ;
     RECT  1680.08 993.24 1684.36 994.6 ;
     RECT  1880.18 994.26 1886.76 994.6 ;
     RECT  2118.46 994.43 2118.6 994.6 ;
     RECT  2128.58 994.26 2133.78 994.6 ;
     RECT  520.88 994.6 521.02 994.94 ;
     RECT  1401.78 994.6 1407.44 994.94 ;
     RECT  1344.74 994.6 1344.88 995.96 ;
     RECT  1742.18 983.55 1759.34 995.96 ;
     RECT  1809.11 993.92 1865.14 996.1 ;
     RECT  1552.2 993.75 1565.22 996.3 ;
     RECT  1642.36 993.92 1667.34 996.3 ;
     RECT  1680.08 994.6 1687.58 996.3 ;
     RECT  1706.3 982.5 1706.44 996.3 ;
     RECT  1720.1 992.22 1724.84 996.3 ;
     RECT  2118.46 994.6 2135.62 996.3 ;
     RECT  2147.9 982.5 2148.04 996.3 ;
     RECT  1418.34 994.6 1452.98 996.44 ;
     RECT  1642.36 996.3 1687.58 996.44 ;
     RECT  2118.46 996.3 2148.04 996.44 ;
     RECT  1344.74 995.96 1349.02 996.64 ;
     RECT  1552.2 996.3 1566.6 996.64 ;
     RECT  1582.1 994.26 1593.28 996.64 ;
     RECT  1701.24 996.3 1706.44 996.64 ;
     RECT  1720.1 996.3 1728.52 996.64 ;
     RECT  2140.08 996.44 2148.04 996.64 ;
     RECT  582.98 985.76 583.12 996.98 ;
     RECT  1341.98 996.64 1349.02 996.98 ;
     RECT  1362.22 996.3 1362.36 996.98 ;
     RECT  1383.84 996.3 1383.98 996.98 ;
     RECT  1398.56 994.94 1407.44 996.98 ;
     RECT  1719.18 996.64 1728.52 996.98 ;
     RECT  533.76 997.32 533.9 997.66 ;
     RECT  1269.11 982.5 1271.93 997.66 ;
     RECT  1284.11 984.455 1286.93 997.66 ;
     RECT  533.76 997.66 534.36 998.68 ;
     RECT  549.11 985.56 551.93 998.68 ;
     RECT  1464.11 991.88 1478.28 998.68 ;
     RECT  1776.68 982.5 1786.02 998.68 ;
     RECT  1824.11 996.1 1865.14 998.68 ;
     RECT  1880.18 994.6 1894.58 998.68 ;
     RECT  1916.06 982.5 1916.2 998.68 ;
     RECT  2140.08 996.64 2155.86 998.68 ;
     RECT  1311.16 997.66 1311.3 999.33 ;
     RECT  1916.06 998.68 1924.94 999.36 ;
     RECT  1341.98 996.98 1368.8 999.5 ;
     RECT  1552.2 996.64 1593.28 999.5 ;
     RECT  1916.06 999.36 1926.32 999.7 ;
     RECT  1913.76 999.7 1926.32 999.87 ;
     RECT  412.32 994.26 507.68 1000.04 ;
     RECT  520.88 994.94 522.4 1000.04 ;
     RECT  1331.4 997.32 1331.54 1000.04 ;
     RECT  1341.98 999.5 1349.02 1000.04 ;
     RECT  1773.46 998.68 1786.02 1000.04 ;
     RECT  412.32 1000.04 522.4 1000.38 ;
     RECT  533.76 998.68 551.93 1000.38 ;
     RECT  630.82 1000.04 630.96 1000.38 ;
     RECT  2244.04 992.39 2246.02 1000.38 ;
     RECT  1122.1 1000.04 1122.24 1000.43 ;
     RECT  1556.34 999.5 1593.28 1000.52 ;
     RECT  1122.1 1000.43 1122.7 1000.57 ;
     RECT  1495.62 993.24 1542.22 1000.57 ;
     RECT  1558.18 1000.52 1593.28 1001.4 ;
     RECT  1605.1 991 1613.98 1001.4 ;
     RECT  1629.11 991.85 1632.38 1001.4 ;
     RECT  1719.18 996.98 1729.44 1001.54 ;
     RECT  1904.1 999.02 1904.24 1001.74 ;
     RECT  1913.76 999.87 1927.7 1001.74 ;
     RECT  2083.96 985.08 2090.54 1001.88 ;
     RECT  1558.18 1001.4 1613.98 1002.08 ;
     RECT  1625.8 1001.4 1632.38 1002.08 ;
     RECT  1642.36 996.44 1684.36 1002.08 ;
     RECT  582.98 996.98 583.58 1002.42 ;
     RECT  1383.84 996.98 1407.44 1002.42 ;
     RECT  1418.34 996.44 1430.44 1002.42 ;
     RECT  2118.46 996.44 2127.34 1002.42 ;
     RECT  2169.11 988.31 2197.72 1002.42 ;
     RECT  2210.46 982.5 2215.66 1002.42 ;
     RECT  182.32 994.6 393.6 1003.1 ;
     RECT  181.86 1003.1 393.6 1003.24 ;
     RECT  243.04 1003.24 393.6 1004.12 ;
     RECT  404.5 1000.38 551.93 1004.12 ;
     RECT  1440.88 996.44 1452.98 1004.12 ;
     RECT  1464.11 998.68 1483.8 1004.12 ;
     RECT  1742.18 995.96 1760.26 1004.8 ;
     RECT  1940.9 988.31 1941.04 1004.8 ;
     RECT  1738.5 1004.8 1760.26 1004.94 ;
     RECT  2085.8 1001.88 2090.54 1004.94 ;
     RECT  1693.88 996.64 1706.44 1005.14 ;
     RECT  1904.1 1001.74 1927.7 1005.14 ;
     RECT  1940.9 1004.8 1943.34 1005.14 ;
     RECT  181.86 1003.24 233.06 1005.48 ;
     RECT  1693.88 1005.14 1709.66 1005.48 ;
     RECT  1719.18 1001.54 1728.52 1005.48 ;
     RECT  2268.42 983.18 2269.94 1005.48 ;
     RECT  618.4 1003.1 618.54 1006.215 ;
     RECT  564.11 985.56 566.93 1006.585 ;
     RECT  729.11 984.455 746.93 1006.585 ;
     RECT  704.42 1005.48 704.56 1006.84 ;
     RECT  243.04 1004.12 551.93 1006.98 ;
     RECT  686.02 1005.48 686.16 1006.98 ;
     RECT  630.82 1000.38 633.26 1007.18 ;
     RECT  697.98 1006.84 704.56 1007.18 ;
     RECT  1440.88 1004.12 1483.8 1007.18 ;
     RECT  1738.96 1004.94 1760.26 1007.18 ;
     RECT  1773.46 1000.04 1788.78 1007.18 ;
     RECT  1798.3 982.5 1798.44 1007.18 ;
     RECT  1809.11 996.1 1811.93 1007.18 ;
     RECT  2116.16 1002.42 2127.34 1007.18 ;
     RECT  2140.08 998.68 2156.32 1007.18 ;
     RECT  648.3 990.66 648.44 1007.32 ;
     RECT  696.14 1007.18 704.56 1007.32 ;
     RECT  1969.88 1005.14 1970.02 1007.32 ;
     RECT  2116.16 1007.18 2156.32 1007.32 ;
     RECT  696.14 1007.32 702.72 1007.52 ;
     RECT  1383.84 1002.42 1430.44 1007.52 ;
     RECT  1440.88 1007.18 1484.72 1007.52 ;
     RECT  1798.3 1007.18 1811.93 1007.66 ;
     RECT  2147.9 1007.32 2156.32 1007.66 ;
     RECT  2701.74 987.8 2915.78 1007.66 ;
     RECT  2148.82 1007.66 2156.32 1007.86 ;
     RECT  2169.11 1002.42 2215.66 1007.86 ;
     RECT  2739.46 1007.66 2915.78 1008 ;
     RECT  540.2 1006.98 551.93 1008.2 ;
     RECT  562.28 1007.86 562.42 1008.2 ;
     RECT  243.04 1006.98 528.84 1008.34 ;
     RECT  540.2 1008.2 562.42 1008.34 ;
     RECT  688.78 1007.52 702.72 1008.34 ;
     RECT  42.48 988.62 162.22 1008.54 ;
     RECT  175.88 1005.48 233.06 1008.68 ;
     RECT  582.98 1002.42 590.94 1008.935 ;
     RECT  179.1 1008.68 233.06 1009.305 ;
     RECT  549.11 1008.34 562.42 1009.305 ;
     RECT  729.11 1006.585 743.2 1009.305 ;
     RECT  688.78 1008.34 699.04 1010.04 ;
     RECT  736.16 1009.305 743.2 1010.04 ;
     RECT  1803.36 1007.66 1811.93 1010.24 ;
     RECT  2044.4 988.99 2056.5 1010.24 ;
     RECT  2268.42 1005.48 2277.3 1010.24 ;
     RECT  179.1 1009.305 185.22 1010.38 ;
     RECT  2044.4 1010.24 2058.8 1010.38 ;
     RECT  1359.46 999.5 1368.8 1010.58 ;
     RECT  1496.08 1000.57 1542.22 1010.58 ;
     RECT  1641.9 1002.08 1684.36 1010.58 ;
     RECT  1693.88 1005.48 1728.52 1010.58 ;
     RECT  1803.36 1010.24 1813.16 1010.58 ;
     RECT  1824.11 998.68 1894.58 1010.58 ;
     RECT  2051.3 1010.38 2058.8 1010.58 ;
     RECT  2288.2 1010.24 2288.34 1010.58 ;
     RECT  2301.54 1005.82 2301.68 1010.58 ;
     RECT  1641.9 1010.58 1728.52 1010.72 ;
     RECT  878.3 990.86 878.44 1010.92 ;
     RECT  2268.42 1010.24 2278.22 1010.92 ;
     RECT  2288.2 1010.58 2301.68 1010.92 ;
     RECT  0.62 989.64 26.93 1011.06 ;
     RECT  1331.4 1000.04 1349.02 1011.06 ;
     RECT  1383.84 1007.52 1484.72 1011.26 ;
     RECT  1496.08 1010.58 1548.66 1011.26 ;
     RECT  1383.84 1011.26 1548.66 1012.28 ;
     RECT  1382.92 1012.28 1548.66 1012.42 ;
     RECT  2268.42 1010.92 2301.68 1012.76 ;
     RECT  197.5 1009.305 233.06 1012.79 ;
     RECT  243.04 1008.34 249.62 1012.79 ;
     RECT  2237.6 1000.38 2246.02 1012.96 ;
     RECT  630.82 1007.18 636.48 1013.3 ;
     RECT  1359.46 1010.58 1373.4 1013.3 ;
     RECT  1382.92 1012.42 1406.06 1013.3 ;
     RECT  1558.18 1002.08 1632.38 1013.3 ;
     RECT  1641.9 1010.72 1698.16 1013.3 ;
     RECT  1953.32 1005.48 1953.46 1013.3 ;
     RECT  2237.6 1012.96 2246.48 1014.12 ;
     RECT  1979.54 1007.18 1979.68 1014.83 ;
     RECT  1989.11 991.85 1991.93 1014.83 ;
     RECT  1416.04 1012.42 1548.66 1015.14 ;
     RECT  2148.82 1007.86 2215.66 1015.34 ;
     RECT  2225.18 991 2225.78 1015.34 ;
     RECT  2148.82 1015.34 2225.78 1015.51 ;
     RECT  2237.6 1014.12 2246.02 1015.51 ;
     RECT  1341.98 1011.06 1349.02 1015.82 ;
     RECT  1803.36 1010.58 1894.58 1016.36 ;
     RECT  1904.1 1005.14 1943.34 1016.36 ;
     RECT  2258.3 1016.02 2258.44 1016.36 ;
     RECT  2268.42 1012.76 2299.84 1016.36 ;
     RECT  1558.18 1013.3 1698.16 1017.01 ;
     RECT  1341.98 1015.82 1342.12 1017.86 ;
     RECT  1607.4 1017.01 1698.16 1017.86 ;
     RECT  2745.44 1008 2915.78 1017.86 ;
     RECT  1803.36 1016.36 1943.34 1018.06 ;
     RECT  1953.32 1013.3 1958.98 1018.06 ;
     RECT  2256.92 1016.36 2299.84 1018.2 ;
     RECT  42.48 1008.54 164.52 1018.4 ;
     RECT  878.3 1010.92 887.18 1018.4 ;
     RECT  1708.14 1010.72 1728.52 1018.74 ;
     RECT  1738.96 1007.18 1788.78 1018.74 ;
     RECT  630.82 1013.3 636.94 1018.91 ;
     RECT  2311.2 983.18 2643.92 1019.08 ;
     RECT  182.78 1010.38 185.22 1019.42 ;
     RECT  197.5 1012.79 249.62 1019.42 ;
     RECT  197.5 1019.42 251.46 1019.59 ;
     RECT  261.44 1008.34 528.84 1019.59 ;
     RECT  42.02 1018.4 164.52 1020 ;
     RECT  182.78 1019.42 186.14 1020 ;
     RECT  197.5 1019.59 528.84 1020 ;
     RECT  1621.2 1017.86 1698.16 1020.44 ;
     RECT  1708.14 1018.74 1788.78 1020.44 ;
     RECT  2309.36 1019.08 2643.92 1020.58 ;
     RECT  42.02 1020 545.51 1020.78 ;
     RECT  560.9 1009.305 562.42 1020.78 ;
     RECT  1621.2 1020.44 1788.78 1020.78 ;
     RECT  2073.38 1005.48 2073.52 1020.78 ;
     RECT  2085.8 1004.94 2085.94 1020.78 ;
     RECT  1621.2 1020.78 1793.38 1021.46 ;
     RECT  1803.36 1018.06 1958.98 1021.46 ;
     RECT  2116.16 1007.32 2132.86 1021.46 ;
     RECT  2148.82 1015.51 2246.02 1021.46 ;
     RECT  1416.04 1015.14 1485.18 1021.6 ;
     RECT  572.4 1019.42 572.54 1021.8 ;
     RECT  582.98 1008.935 594.35 1021.8 ;
     RECT  764.22 991.54 764.36 1022.14 ;
     RECT  630.82 1018.91 637.4 1022.535 ;
     RECT  736.16 1010.04 741.82 1022.535 ;
     RECT  2004.11 989.81 2016.02 1023.5 ;
     RECT  630.82 1022.535 741.82 1023.64 ;
     RECT  1979.54 1014.83 1992.56 1023.84 ;
     RECT  2002.08 1023.5 2016.02 1023.84 ;
     RECT  822.18 1023.5 822.32 1024.18 ;
     RECT  1496.08 1015.14 1548.66 1024.18 ;
     RECT  1558.18 1017.01 1596.96 1024.18 ;
     RECT  1979.54 1023.84 2016.02 1024.18 ;
     RECT  607.17 1006.215 618.54 1024.52 ;
     RECT  630.82 1023.64 739.06 1024.52 ;
     RECT  42.02 1020.78 562.42 1024.66 ;
     RECT  607.17 1024.52 739.06 1024.66 ;
     RECT  761 1022.14 765.74 1024.86 ;
     RECT  843.34 991.54 853.6 1024.86 ;
     RECT  1122.56 1000.57 1122.7 1024.86 ;
     RECT  1269.11 997.66 1286.93 1025 ;
     RECT  2749.58 1017.86 2915.78 1025 ;
     RECT  843.34 1024.86 860.96 1026.02 ;
     RECT  1122.56 1024.86 1129.6 1026.02 ;
     RECT  843.34 1026.02 846.24 1026.36 ;
     RECT  973.98 1024.52 974.12 1026.39 ;
     RECT  1122.56 1026.02 1129.14 1026.56 ;
     RECT  2073.38 1020.78 2085.94 1026.56 ;
     RECT  859.44 1026.02 860.96 1026.7 ;
     RECT  965.24 1026.39 974.12 1026.7 ;
     RECT  1621.2 1021.46 1959.44 1026.7 ;
     RECT  2051.3 1010.58 2063.86 1026.7 ;
     RECT  860.82 1026.7 860.96 1026.9 ;
     RECT  878.3 1018.4 888.56 1026.9 ;
     RECT  1359.46 1013.3 1406.06 1026.9 ;
     RECT  2874.24 1025 2915.78 1027.21 ;
     RECT  1496.08 1024.18 1596.96 1027.24 ;
     RECT  1607.4 1017.86 1609.38 1027.24 ;
     RECT  1972.64 1024.18 2016.02 1027.24 ;
     RECT  2073.38 1026.56 2093.76 1027.24 ;
     RECT  2105.12 1024.18 2105.26 1027.24 ;
     RECT  860.82 1026.9 888.56 1027.38 ;
     RECT  2073.38 1027.24 2105.26 1027.58 ;
     RECT  865.88 1027.38 888.56 1028.74 ;
     RECT  1621.2 1026.7 1793.84 1028.94 ;
     RECT  2147.44 1021.46 2246.02 1028.94 ;
     RECT  2256.92 1018.2 2297.54 1028.94 ;
     RECT  1496.08 1027.24 1609.38 1029.62 ;
     RECT  1620.28 1028.94 1793.84 1029.62 ;
     RECT  1359 1026.9 1406.06 1029.96 ;
     RECT  1416.04 1021.6 1483.8 1029.96 ;
     RECT  909.11 982.5 911.93 1031.32 ;
     RECT  923.38 984.455 926.93 1031.32 ;
     RECT  572.4 1021.8 594.35 1031.46 ;
     RECT  881.98 1028.74 888.56 1031.46 ;
     RECT  2147.44 1028.94 2297.54 1031.46 ;
     RECT  2116.16 1021.46 2137.46 1031.66 ;
     RECT  2147.44 1031.46 2197.26 1031.66 ;
     RECT  1118.42 1026.56 1129.14 1031.97 ;
     RECT  586.66 1031.46 594.35 1032 ;
     RECT  607.17 1024.66 634.64 1032 ;
     RECT  1496.08 1029.62 1793.84 1032 ;
     RECT  2208.62 1031.46 2297.54 1032.14 ;
     RECT  1359 1029.96 1483.8 1032.34 ;
     RECT  1495.16 1032 1793.84 1032.34 ;
     RECT  2311.2 1020.58 2643.92 1032.34 ;
     RECT  2656.2 982.5 2689.46 1032.34 ;
     RECT  1359 1032.34 1793.84 1032.48 ;
     RECT  2070.62 1027.58 2105.26 1032.68 ;
     RECT  2116.16 1031.66 2197.26 1032.68 ;
     RECT  865.88 1028.74 871.08 1032.82 ;
     RECT  909.11 1031.32 926.93 1032.82 ;
     RECT  1968.96 1027.24 2016.02 1033.02 ;
     RECT  881.98 1031.46 887.18 1033.16 ;
     RECT  2701.74 1007.66 2727.64 1034.04 ;
     RECT  865.88 1032.82 869.24 1035.37 ;
     RECT  970.3 1026.7 972.28 1035.88 ;
     RECT  972.14 1035.88 972.28 1036.9 ;
     RECT  1014.46 1032 1014.6 1037.58 ;
     RECT  1118.42 1031.97 1127.3 1037.58 ;
     RECT  1968.96 1033.02 2017.86 1037.58 ;
     RECT  2875.62 1027.21 2915.78 1037.78 ;
     RECT  1376.48 1032.48 1793.84 1038.12 ;
     RECT  1803.36 1026.7 1959.44 1038.12 ;
     RECT  1026.88 1035.74 1027.02 1038.26 ;
     RECT  1376.48 1038.12 1959.44 1038.6 ;
     RECT  1968.96 1037.58 2016.02 1039.48 ;
     RECT  2875.16 1037.78 2915.78 1039.48 ;
     RECT  1966.66 1039.48 2016.02 1039.62 ;
     RECT  2749.58 1025 2860.58 1040.16 ;
     RECT  2870.1 1039.48 2915.78 1040.16 ;
     RECT  2070.62 1032.68 2197.26 1042.2 ;
     RECT  1966.66 1039.62 1969.1 1042.34 ;
     RECT  2701.74 1034.04 2732.7 1042.68 ;
     RECT  2070.62 1042.2 2197.72 1042.88 ;
     RECT  2068.78 1042.88 2197.72 1043.02 ;
     RECT  1359 1032.48 1361.44 1043.39 ;
     RECT  2311.2 1032.34 2689.46 1043.56 ;
     RECT  1118.42 1037.58 1118.56 1045.06 ;
     RECT  2051.3 1026.7 2058.8 1045.26 ;
     RECT  2068.78 1043.02 2196.8 1045.26 ;
     RECT  2210.46 1032.14 2297.54 1045.26 ;
     RECT  2309.36 1043.56 2689.46 1045.26 ;
     RECT  1979.54 1039.62 2016.02 1045.4 ;
     RECT  2051.3 1045.26 2196.8 1045.4 ;
     RECT  42.48 1024.66 562.42 1045.6 ;
     RECT  761 1024.86 773.56 1046.08 ;
     RECT  882.9 1033.16 887.18 1046.76 ;
     RECT  1321.28 1038.12 1321.42 1048.46 ;
     RECT  1331.4 1011.06 1331.54 1049 ;
     RECT  1328.18 1049 1331.54 1049.14 ;
     RECT  2053.14 1045.4 2196.8 1049.14 ;
     RECT  1358.54 1043.39 1361.44 1049.48 ;
     RECT  586.66 1032 634.64 1050.33 ;
     RECT  2053.14 1049.14 2129.18 1050.5 ;
     RECT  1358.54 1049.48 1360.98 1053.9 ;
     RECT  1376.48 1038.6 1955.3 1054.44 ;
     RECT  1966.66 1042.34 1968.64 1054.44 ;
     RECT  2140.54 1049.14 2196.8 1056.14 ;
     RECT  2210.46 1045.26 2689.46 1056.14 ;
     RECT  817.58 1024.18 822.32 1056.28 ;
     RECT  887.04 1046.76 887.18 1056.28 ;
     RECT  817.58 1056.28 820.94 1056.62 ;
     RECT  41.56 1045.6 562.42 1058.66 ;
     RECT  2140.54 1056.14 2689.46 1058.86 ;
     RECT  1317.6 1048.66 1317.74 1059.17 ;
     RECT  2085.8 1050.5 2129.18 1059.54 ;
     RECT  2140.54 1058.86 2691.76 1059.54 ;
     RECT  1376.48 1054.44 1968.64 1060.36 ;
     RECT  2749.58 1040.16 2915.78 1060.36 ;
     RECT  2085.8 1059.54 2691.76 1062.94 ;
     RECT  2053.14 1050.5 2073.52 1064.1 ;
     RECT  1401.78 1060.36 1968.64 1064.64 ;
     RECT  1401.78 1064.64 1969.56 1064.78 ;
     RECT  1538.86 1064.78 1969.56 1064.98 ;
     RECT  1979.54 1045.4 2006.93 1064.98 ;
     RECT  603.68 1050.33 634.64 1065.12 ;
     RECT  1538.86 1064.98 2007.74 1066.68 ;
     RECT  2026.92 1065.32 2027.06 1066.82 ;
     RECT  2875.62 1060.36 2915.78 1067.84 ;
     RECT  607.17 1065.12 634.64 1068.38 ;
     RECT  644.24 1024.66 739.06 1068.38 ;
     RECT  2083.96 1062.94 2691.76 1069.54 ;
     RECT  820.34 1056.62 820.94 1069.74 ;
     RECT  865.88 1035.37 866.02 1069.88 ;
     RECT  761 1046.08 764.36 1070.08 ;
     RECT  1538.86 1066.68 2011.42 1070.22 ;
     RECT  2749.58 1060.36 2860.58 1070.22 ;
     RECT  761 1070.08 765.74 1070.42 ;
     RECT  815.74 1069.74 820.94 1070.42 ;
     RECT  1376.48 1060.36 1390.88 1070.56 ;
     RECT  1378.78 1070.56 1390.88 1070.76 ;
     RECT  1401.78 1064.78 1529.34 1070.76 ;
     RECT  1257.8 982.5 1257.94 1072.26 ;
     RECT  2083.96 1069.54 2689.46 1072.6 ;
     RECT  1269.11 1025 1274.04 1073.14 ;
     RECT  2001.16 1070.22 2011.42 1073.14 ;
     RECT  2875.62 1067.84 2912.56 1073.28 ;
     RECT  2053.14 1064.1 2069.84 1073.31 ;
     RECT  754.1 1070.42 765.74 1073.82 ;
     RECT  815.28 1070.42 820.94 1074.98 ;
     RECT  2793.28 1070.22 2860.58 1075.18 ;
     RECT  2793.28 1075.18 2861.04 1075.49 ;
     RECT  2053.14 1073.31 2070.3 1075.66 ;
     RECT  794.58 1055.8 794.72 1075.86 ;
     RECT  2053.6 1075.66 2070.3 1075.86 ;
     RECT  2793.28 1075.49 2860.58 1076.17 ;
     RECT  1378.78 1070.76 1529.34 1076.2 ;
     RECT  1538.86 1070.22 1991.93 1076.2 ;
     RECT  2053.6 1075.86 2070.76 1076.2 ;
     RECT  1378.78 1076.2 1991.93 1076.34 ;
     RECT  752.26 1073.82 765.74 1077.39 ;
     RECT  776.64 1056.82 776.78 1077.39 ;
     RECT  572.4 1031.46 576.68 1077.7 ;
     RECT  2794.66 1076.17 2860.58 1077.7 ;
     RECT  1378.78 1076.34 1497.14 1078.04 ;
     RECT  1422.48 1078.04 1497.14 1078.38 ;
     RECT  752.26 1077.39 776.78 1079.26 ;
     RECT  2794.66 1077.7 2859.66 1079.4 ;
     RECT  752.26 1079.26 784.14 1080.42 ;
     RECT  1508.96 1076.34 1991.93 1081.64 ;
     RECT  2001.16 1073.14 2013.72 1081.64 ;
     RECT  755.02 1080.42 784.14 1083.14 ;
     RECT  1428 1078.38 1497.14 1083.48 ;
     RECT  1508.96 1081.64 2013.72 1083.68 ;
     RECT  2053.6 1076.2 2074.44 1083.68 ;
     RECT  2083.96 1072.6 2194.96 1083.68 ;
     RECT  1378.78 1078.04 1412.96 1083.82 ;
     RECT  1431.22 1083.48 1497.14 1084.16 ;
     RECT  2794.66 1079.4 2854.6 1084.84 ;
     RECT  2053.6 1083.68 2194.96 1085.72 ;
     RECT  755.02 1083.14 765.74 1086.2 ;
     RECT  2053.14 1085.72 2194.96 1086.4 ;
     RECT  2749.58 1070.22 2781 1086.88 ;
     RECT  2050.38 1086.4 2194.96 1087.08 ;
     RECT  2204.48 1072.6 2689.46 1087.08 ;
     RECT  1508.96 1083.68 2015.1 1087.22 ;
     RECT  1927.56 1087.22 2015.1 1087.42 ;
     RECT  1927.56 1087.42 2023.84 1088.58 ;
     RECT  24.11 1011.06 26.93 1088.78 ;
     RECT  42.48 1058.66 562.42 1088.78 ;
     RECT  794.58 1075.86 803.92 1088.92 ;
     RECT  1508.96 1087.22 1918.04 1088.92 ;
     RECT  2046.7 1087.08 2689.46 1089.26 ;
     RECT  776.64 1083.14 784.14 1089.6 ;
     RECT  1340.6 1086.06 1340.74 1089.8 ;
     RECT  1548.52 1088.92 1918.04 1091.3 ;
     RECT  2853.54 1084.84 2854.6 1091.5 ;
     RECT  2875.62 1073.28 2891.93 1091.5 ;
     RECT  2904.11 1073.28 2912.56 1091.5 ;
     RECT  802.4 1088.92 803.92 1091.64 ;
     RECT  815.74 1074.98 820.94 1091.81 ;
     RECT  2853.54 1091.5 2859.2 1092.35 ;
     RECT  1378.78 1083.82 1401.92 1092.86 ;
     RECT  1432.14 1084.16 1497.14 1092.86 ;
     RECT  1508.96 1088.92 1536.7 1092.86 ;
     RECT  2794.66 1084.84 2841.26 1093 ;
     RECT  1548.52 1091.3 1916.2 1094.02 ;
     RECT  2046.7 1089.26 2643.92 1094.02 ;
     RECT  2853.54 1092.35 2861.04 1094.02 ;
     RECT  1432.14 1092.86 1536.7 1094.36 ;
     RECT  1548.52 1094.02 1605.24 1094.36 ;
     RECT  1614.76 1094.02 1916.2 1094.36 ;
     RECT  1927.56 1088.58 2020.62 1094.36 ;
     RECT  1614.76 1094.36 1772.22 1095.04 ;
     RECT  1628.56 1095.04 1772.22 1095.72 ;
     RECT  2853.54 1094.02 2855.52 1095.72 ;
     RECT  1782.2 1094.36 1916.2 1096.74 ;
     RECT  1927.56 1094.36 2011.42 1097.08 ;
     RECT  1432.14 1094.36 1486.56 1097.17 ;
     RECT  1614.76 1095.04 1618.58 1097.17 ;
     RECT  1782.2 1096.74 1909.76 1097.42 ;
     RECT  1412.36 1083.82 1412.96 1097.62 ;
     RECT  1411.9 1097.62 1412.96 1097.96 ;
     RECT  1378.32 1092.86 1401.92 1098.1 ;
     RECT  573.32 1077.7 576.68 1098.3 ;
     RECT  2066.48 1094.02 2643.92 1098.44 ;
     RECT  2229.32 1098.44 2643.92 1099.46 ;
     RECT  1782.2 1097.42 1784.18 1099.8 ;
     RECT  1548.52 1094.36 1564.3 1100.34 ;
     RECT  923.38 1032.82 926.93 1100.48 ;
     RECT  755.02 1086.2 762.98 1100.51 ;
     RECT  2822.26 1093 2841.26 1100.65 ;
     RECT  607.17 1068.38 739.06 1101.02 ;
     RECT  1328.18 1049.14 1328.32 1101.02 ;
     RECT  1432.6 1097.17 1486.56 1102.86 ;
     RECT  1497 1094.36 1536.7 1103.06 ;
     RECT  1548.06 1100.34 1564.3 1103.06 ;
     RECT  586.66 1050.33 594.35 1103.74 ;
     RECT  572.4 1098.3 576.68 1103.88 ;
     RECT  1432.6 1102.86 1473.22 1103.88 ;
     RECT  2853.54 1095.72 2854.6 1103.88 ;
     RECT  752.26 1100.51 762.98 1104.9 ;
     RECT  1497 1103.06 1564.3 1107.62 ;
     RECT  1628.56 1095.72 1660.9 1107.96 ;
     RECT  1793.7 1097.42 1909.76 1107.96 ;
     RECT  1574.28 1094.36 1605.24 1108.16 ;
     RECT  1615.22 1097.17 1618.58 1108.16 ;
     RECT  1784.04 1099.8 1784.18 1108.16 ;
     RECT  1793.7 1107.96 1832.02 1108.16 ;
     RECT  1548.52 1107.62 1564.3 1108.64 ;
     RECT  2875.62 1091.5 2912.56 1108.64 ;
     RECT  1574.28 1108.16 1618.58 1108.84 ;
     RECT  1628.56 1107.96 1632.84 1108.84 ;
     RECT  1842 1107.96 1909.76 1108.84 ;
     RECT  1574.28 1108.84 1632.84 1108.98 ;
     RECT  1784.04 1108.16 1832.02 1108.98 ;
     RECT  1927.56 1097.08 2009.12 1109.32 ;
     RECT  1550.36 1108.64 1564.3 1110.54 ;
     RECT  1574.28 1108.98 1618.58 1110.54 ;
     RECT  2046.7 1094.02 2056.96 1110.68 ;
     RECT  1550.36 1110.54 1618.58 1111.02 ;
     RECT  1643.28 1107.96 1660.9 1111.02 ;
     RECT  1842 1108.84 1916.66 1111.22 ;
     RECT  1927.56 1109.32 1935.52 1111.22 ;
     RECT  2046.7 1110.68 2055.12 1111.22 ;
     RECT  1842 1111.22 1935.52 1111.36 ;
     RECT  2040.26 1111.22 2055.12 1111.36 ;
     RECT  2066.48 1098.44 2219.8 1111.36 ;
     RECT  2822.26 1100.65 2839.88 1111.36 ;
     RECT  1784.04 1108.98 1829.26 1111.9 ;
     RECT  2854.46 1103.88 2854.6 1112.04 ;
     RECT  1644.11 1111.02 1660.9 1113.4 ;
     RECT  1550.36 1111.02 1578.1 1113.74 ;
     RECT  2087.64 1111.36 2219.8 1113.94 ;
     RECT  2230.7 1099.46 2643.92 1113.94 ;
     RECT  1497 1107.62 1538.54 1114.08 ;
     RECT  2875.62 1108.64 2891.93 1114.25 ;
     RECT  1432.6 1103.88 1432.74 1115.98 ;
     RECT  1485.5 1102.86 1486.56 1116.12 ;
     RECT  607.17 1101.02 739.98 1116.29 ;
     RECT  1378.32 1098.1 1378.46 1116.29 ;
     RECT  1486.42 1116.12 1486.56 1116.46 ;
     RECT  2864.12 1107.99 2864.26 1116.46 ;
     RECT  1902.26 1111.36 1935.52 1116.8 ;
     RECT  1671.34 1095.72 1772.22 1117 ;
     RECT  1783.58 1111.9 1829.26 1117 ;
     RECT  1902.26 1116.8 1935.06 1117.14 ;
     RECT  675.51 1116.29 676.5 1118.33 ;
     RECT  1411.9 1097.96 1416.18 1118.5 ;
     RECT  573.32 1103.88 576.68 1119.04 ;
     RECT  586.66 1103.74 596 1119.04 ;
     RECT  1550.36 1113.74 1575.34 1119.04 ;
     RECT  703.5 1116.29 704.31 1119.18 ;
     RECT  1902.26 1117.14 1934.6 1119.52 ;
     RECT  659.8 1116.29 662.24 1119.69 ;
     RECT  731.56 1116.29 739.98 1119.69 ;
     RECT  1671.34 1117 1829.26 1119.72 ;
     RECT  1842 1111.36 1891.36 1119.72 ;
     RECT  802.4 1091.64 802.54 1119.86 ;
     RECT  607.17 1116.29 647.27 1120 ;
     RECT  661.25 1119.69 662.24 1120 ;
     RECT  675.51 1118.33 675.79 1120 ;
     RECT  689.7 1116.29 690.05 1120 ;
     RECT  704.03 1119.18 704.31 1120 ;
     RECT  718.29 1116.29 721.12 1120 ;
     RECT  732.55 1119.69 739.98 1120 ;
     RECT  1902.26 1119.52 1903.32 1120.2 ;
     RECT  689.7 1120 689.84 1120.88 ;
     RECT  662.1 1120 662.24 1121.22 ;
     RECT  573.32 1119.04 596 1121.42 ;
     RECT  1671.34 1119.72 1891.36 1121.56 ;
     RECT  2087.64 1113.94 2643.92 1121.56 ;
     RECT  1946.42 1109.32 2009.12 1122.1 ;
     RECT  2066.48 1111.36 2077.66 1122.1 ;
     RECT  2087.64 1121.56 2261.2 1122.1 ;
     RECT  2066.48 1122.1 2261.2 1122.24 ;
     RECT  573.32 1121.42 596.92 1122.78 ;
     RECT  607.17 1120 642 1122.92 ;
     RECT  24.11 1088.78 562.42 1124.14 ;
     RECT  755.02 1104.9 762.98 1124.96 ;
     RECT  1946.42 1122.1 2011.88 1124.96 ;
     RECT  2271.64 1121.56 2643.92 1125.16 ;
     RECT  2656.2 1089.26 2689.46 1125.16 ;
     RECT  762.38 1124.96 762.98 1125.5 ;
     RECT  1549.44 1119.04 1575.34 1127.34 ;
     RECT  1588.08 1111.02 1618.58 1128.22 ;
     RECT  1327.72 1101.02 1328.32 1129.38 ;
     RECT  1358.54 1053.9 1360.06 1130.06 ;
     RECT  1328.18 1129.38 1328.32 1130.74 ;
     RECT  2863.66 1128.22 2863.8 1130.94 ;
     RECT  2875.62 1114.25 2877.6 1130.94 ;
     RECT  735.7 1120 739.98 1131.335 ;
     RECT  1533.34 1114.08 1538.54 1132.1 ;
     RECT  2066.48 1122.24 2260.74 1132.3 ;
     RECT  1671.34 1121.56 1826.93 1132.44 ;
     RECT  2271.64 1125.16 2689.46 1132.64 ;
     RECT  762.38 1125.5 765.74 1132.78 ;
     RECT  1692.5 1132.44 1826.93 1132.78 ;
     RECT  1644.11 1113.4 1659.52 1132.98 ;
     RECT  1671.34 1132.44 1680.68 1132.98 ;
     RECT  2066.48 1132.3 2262.12 1132.98 ;
     RECT  2271.64 1132.64 2691.76 1132.98 ;
     RECT  2701.74 1042.68 2727.64 1132.98 ;
     RECT  776.64 1089.6 776.78 1133.12 ;
     RECT  1644.11 1132.98 1680.68 1133.12 ;
     RECT  735.7 1131.335 750.56 1133.46 ;
     RECT  24.11 1124.14 562.88 1133.66 ;
     RECT  572.86 1122.78 596.92 1133.66 ;
     RECT  2863.66 1130.94 2877.6 1133.66 ;
     RECT  2889.11 1114.25 2891.93 1133.66 ;
     RECT  720.98 1120 721.12 1134.055 ;
     RECT  735.7 1133.46 746.93 1134.055 ;
     RECT  909.11 1032.82 911.93 1134.68 ;
     RECT  1586.7 1128.22 1618.58 1135.02 ;
     RECT  2863.66 1133.66 2891.93 1135.02 ;
     RECT  2860.44 1135.02 2891.93 1135.33 ;
     RECT  2004.11 1124.96 2011.88 1135.36 ;
     RECT  1946.42 1124.96 1992.56 1135.5 ;
     RECT  2066.48 1132.98 2727.64 1135.5 ;
     RECT  1553.58 1127.34 1575.34 1135.7 ;
     RECT  1585.32 1135.02 1618.58 1135.7 ;
     RECT  1946.42 1135.5 1973.7 1136.04 ;
     RECT  2004.11 1135.36 2013.26 1136.04 ;
     RECT  2024.16 1108.84 2024.3 1136.04 ;
     RECT  1944.12 1136.04 1973.7 1136.18 ;
     RECT  24.11 1133.66 596.92 1136.38 ;
     RECT  607.17 1122.92 633.26 1136.38 ;
     RECT  1983.22 1135.5 1992.56 1136.52 ;
     RECT  2066.48 1135.5 2072.14 1141.48 ;
     RECT  1693.42 1132.78 1826.93 1141.96 ;
     RECT  1553.58 1135.7 1618.58 1142.98 ;
     RECT  2904.11 1108.64 2912.56 1143.18 ;
     RECT  2086.72 1135.5 2727.64 1143.66 ;
     RECT  2004.11 1136.04 2024.3 1144 ;
     RECT  1718.26 1141.96 1826.93 1146.38 ;
     RECT  1836.94 1121.56 1891.36 1147.4 ;
     RECT  2861.82 1135.33 2891.93 1148.42 ;
     RECT  2086.72 1143.66 2245.56 1148.76 ;
     RECT  2004.11 1144 2023.38 1149.1 ;
     RECT  1842 1147.4 1891.36 1150.12 ;
     RECT  1628.1 1108.98 1632.84 1151.14 ;
     RECT  0.62 1011.06 11.93 1151.34 ;
     RECT  24.11 1136.38 633.26 1151.34 ;
     RECT  1553.58 1142.98 1575.34 1152.16 ;
     RECT  2086.72 1148.76 2171.93 1152.16 ;
     RECT  2152.04 1152.16 2171.93 1155.56 ;
     RECT  1965.28 1136.18 1973.7 1156.58 ;
     RECT  2086.72 1152.16 2142.06 1156.92 ;
     RECT  1944.12 1136.18 1953.92 1157.12 ;
     RECT  1965.28 1156.58 1965.42 1157.12 ;
     RECT  1983.22 1136.52 1991.93 1157.12 ;
     RECT  2004.11 1149.1 2011.88 1157.12 ;
     RECT  1944.12 1157.12 1965.42 1158.28 ;
     RECT  2182.4 1148.76 2245.56 1159.3 ;
     RECT  2242.2 1159.3 2245.56 1159.64 ;
     RECT  2242.2 1159.64 2242.34 1159.98 ;
     RECT  1965.28 1158.28 1965.42 1162.02 ;
     RECT  2065.1 1141.48 2072.14 1163.24 ;
     RECT  2086.72 1156.92 2127.8 1165.08 ;
     RECT  2138.7 1156.92 2142.06 1166.3 ;
     RECT  2154.34 1155.56 2171.93 1166.3 ;
     RECT  2182.4 1159.3 2232.22 1166.3 ;
     RECT  2764.76 1086.88 2781 1167.32 ;
     RECT  2794.66 1093 2809.52 1167.32 ;
     RECT  1390.28 1098.1 1401.92 1168.48 ;
     RECT  1359.46 1130.06 1360.06 1169.02 ;
     RECT  2138.7 1166.3 2142.52 1172.93 ;
     RECT  2154.34 1166.3 2232.22 1173.92 ;
     RECT  2862.74 1148.42 2891.93 1174.46 ;
     RECT  2901.38 1143.18 2912.56 1174.46 ;
     RECT  1104.11 984.455 1106.93 1175.82 ;
     RECT  2255.08 1143.66 2727.64 1175.96 ;
     RECT  0.62 1151.34 633.26 1176.3 ;
     RECT  2290.96 1175.96 2727.64 1176.3 ;
     RECT  2297.86 1176.3 2727.64 1178.68 ;
     RECT  2138.24 1172.93 2142.52 1178.71 ;
     RECT  2154.34 1173.92 2173.8 1178.71 ;
     RECT  2138.24 1178.71 2173.8 1179.02 ;
     RECT  2255.08 1175.96 2279.14 1179.36 ;
     RECT  2764.76 1167.32 2809.52 1179.56 ;
     RECT  2822.26 1111.36 2836.66 1179.56 ;
     RECT  1314.38 1130.94 1314.52 1181.74 ;
     RECT  1983.22 1157.12 2011.88 1187.04 ;
     RECT  2065.1 1163.24 2074.44 1188.2 ;
     RECT  1340.6 1089.8 1349.02 1190.24 ;
     RECT  2184.11 1173.92 2232.22 1190.24 ;
     RECT  2851.24 1178.54 2851.38 1190.44 ;
     RECT  1432.6 1115.98 1433.66 1190.78 ;
     RECT  1842 1150.12 1873.42 1190.78 ;
     RECT  2851.24 1190.44 2852.3 1196.22 ;
     RECT  1396.26 1168.48 1401.92 1198.26 ;
     RECT  2862.74 1174.46 2912.56 1200.78 ;
     RECT  2863.66 1200.78 2912.56 1201.12 ;
     RECT  1644.11 1133.12 1676.08 1203.7 ;
     RECT  1553.58 1152.16 1567.52 1203.84 ;
     RECT  1693.42 1141.96 1707.82 1204.04 ;
     RECT  1718.26 1146.38 1776.36 1204.04 ;
     RECT  2154.34 1179.02 2173.8 1204.52 ;
     RECT  2655.74 1178.68 2727.64 1206.22 ;
     RECT  1230.2 1173.44 1230.34 1212 ;
     RECT  2138.24 1179.02 2142.52 1224.58 ;
     RECT  1432.6 1190.78 1438.72 1236.65 ;
     RECT  2851.24 1196.22 2853.22 1238.38 ;
     RECT  2864.12 1201.12 2912.56 1238.38 ;
     RECT  1432.6 1236.65 1433.66 1238.52 ;
     RECT  2851.24 1238.38 2912.56 1239.2 ;
     RECT  0.62 1176.3 601.06 1252.66 ;
     RECT  611.04 1176.3 633.26 1252.66 ;
     RECT  1693.42 1204.04 1776.36 1255.86 ;
     RECT  1561.4 1203.84 1567.52 1259.94 ;
     RECT  0.62 1252.66 633.26 1262.49 ;
     RECT  2656.2 1206.22 2727.64 1266.06 ;
     RECT  1840.16 1190.78 1873.42 1266.4 ;
     RECT  1693.42 1255.86 1707.82 1266.74 ;
     RECT  1497 1114.08 1520.14 1270.82 ;
     RECT  2851.24 1239.2 2891.93 1272.38 ;
     RECT  2681.04 1266.06 2727.64 1280 ;
     RECT  2764.76 1179.56 2836.66 1281.7 ;
     RECT  611.04 1262.49 633.26 1284.76 ;
     RECT  1718.26 1255.86 1776.36 1293.6 ;
     RECT  2115.7 1165.08 2127.8 1293.8 ;
     RECT  1644.11 1203.7 1680.22 1296.86 ;
     RECT  1693.42 1266.74 1706.9 1296.86 ;
     RECT  679.58 1211.35 679.72 1297.17 ;
     RECT  1585.32 1142.98 1618.58 1300.74 ;
     RECT  2790.98 1281.7 2836.66 1310.46 ;
     RECT  1644.11 1296.86 1706.9 1310.6 ;
     RECT  2115.24 1293.8 2127.8 1312.3 ;
     RECT  2297.86 1178.68 2643.92 1328.45 ;
     RECT  2851.24 1272.38 2894.62 1335.96 ;
     RECT  2904.11 1239.2 2912.56 1335.96 ;
     RECT  2790.98 1310.46 2839.42 1339.16 ;
     RECT  645.08 1191.8 645.22 1339.19 ;
     RECT  665.78 1297.03 665.92 1339.33 ;
     RECT  1974.48 1187.04 2011.88 1339.5 ;
     RECT  2851.24 1335.96 2912.56 1341.54 ;
     RECT  924.11 1100.48 926.93 1341.74 ;
     RECT  2196.2 1190.24 2232.22 1341.88 ;
     RECT  1915.6 1119.52 1934.6 1344.94 ;
     RECT  1944.12 1158.28 1953.92 1347.52 ;
     RECT  1737.58 1293.6 1776.36 1348 ;
     RECT  2297.86 1328.45 2383.56 1356.16 ;
     RECT  2851.24 1341.54 2853.22 1358.4 ;
     RECT  2868.26 1341.54 2912.56 1358.4 ;
     RECT  2851.24 1358.4 2912.56 1358.88 ;
     RECT  631.28 1284.76 633.26 1362.99 ;
     RECT  645.08 1339.19 651.2 1362.99 ;
     RECT  631.28 1362.99 651.2 1363.13 ;
     RECT  1944.12 1347.52 1959.9 1363.3 ;
     RECT  1903.18 1120.2 1903.32 1364.32 ;
     RECT  611.04 1284.76 618.08 1365.88 ;
     RECT  2851.24 1358.88 2860.58 1367.58 ;
     RECT  2850.32 1367.58 2860.58 1368.74 ;
     RECT  2301.54 1356.16 2383.56 1369.76 ;
     RECT  2086.72 1165.08 2105.72 1370.1 ;
     RECT  2851.24 1368.74 2860.58 1370.1 ;
     RECT  2023.24 1149.1 2023.38 1375.2 ;
     RECT  2870.56 1358.88 2912.56 1385.06 ;
     RECT  0.62 1262.49 601.06 1390.19 ;
     RECT  610.58 1365.88 618.08 1390.19 ;
     RECT  631.28 1363.13 645.22 1390.33 ;
     RECT  2394.92 1328.45 2643.92 1391.01 ;
     RECT  2420.22 1391.01 2643.92 1397.3 ;
     RECT  1944.12 1363.3 1955.76 1402.4 ;
     RECT  2870.56 1385.06 2891.93 1402.94 ;
     RECT  2901.38 1385.06 2912.56 1402.94 ;
     RECT  0.62 1390.19 618.08 1412.77 ;
     RECT  2870.56 1402.94 2912.56 1424.16 ;
     RECT  1915.6 1344.94 1916.66 1432.32 ;
     RECT  645.08 1390.33 645.22 1433.85 ;
     RECT  1840.16 1266.4 1855.02 1439.46 ;
     RECT  0.62 1412.77 601.06 1441.02 ;
     RECT  610.58 1412.77 618.08 1441.02 ;
     RECT  2681.04 1280 2726.93 1444.9 ;
     RECT  2630.9 1397.3 2643.92 1445.41 ;
     RECT  2851.24 1370.1 2860.12 1445.58 ;
     RECT  1944.12 1402.4 1953.92 1445.92 ;
     RECT  2870.56 1424.16 2892.32 1445.92 ;
     RECT  2904.11 1424.16 2912.56 1447.48 ;
     RECT  2794.66 1339.16 2839.42 1456.8 ;
     RECT  2420.22 1397.3 2618.62 1459.52 ;
     RECT  2821.34 1456.8 2839.42 1462.24 ;
     RECT  2681.04 1444.9 2689.46 1473.12 ;
     RECT  2870.56 1445.92 2891.93 1473.12 ;
     RECT  2086.72 1370.1 2105.26 1473.46 ;
     RECT  0.62 1441.02 618.08 1486.38 ;
     RECT  2420.22 1459.52 2457.62 1487.06 ;
     RECT  0.62 1486.38 13.64 1494.88 ;
     RECT  2851.24 1445.58 2853.22 1500.32 ;
     RECT  2875.62 1473.12 2891.93 1505.76 ;
     RECT  2851.24 1500.32 2851.38 1511.2 ;
     RECT  2821.34 1462.24 2836.66 1516.64 ;
     RECT  0.62 1494.88 13.18 1522.62 ;
     RECT  23.62 1486.38 618.08 1522.62 ;
     RECT  2901.38 1447.48 2912.56 1527.52 ;
     RECT  2468.98 1459.52 2618.62 1535.17 ;
     RECT  0.62 1522.62 618.08 1538.4 ;
     RECT  2630.9 1445.41 2631.04 1542.82 ;
     RECT  1390.28 1198.26 1401.92 1549.14 ;
     RECT  4.3 1538.4 618.08 1559.82 ;
     RECT  4.3 1559.82 601.06 1562.54 ;
     RECT  2904.11 1527.52 2912.56 1564.58 ;
     RECT  9.11 1562.54 601.06 1567.13 ;
     RECT  1866.84 1266.4 1873.42 1567.3 ;
     RECT  1718.26 1293.6 1723.92 1567.64 ;
     RECT  1718.26 1567.64 1720.24 1570.36 ;
     RECT  2255.08 1179.36 2260.74 1570.53 ;
     RECT  1644.11 1310.6 1680.22 1571.21 ;
     RECT  9.11 1567.13 169.12 1571.38 ;
     RECT  1533.34 1132.1 1536.7 1573.28 ;
     RECT  2701.74 1444.9 2726.93 1573.93 ;
     RECT  38.8 1571.38 169.12 1574.1 ;
     RECT  2086.72 1473.46 2102.04 1574.1 ;
     RECT  544.8 1567.13 601.06 1574.44 ;
     RECT  843.34 1026.36 843.48 1575.46 ;
     RECT  2822.26 1516.64 2836.66 1575.97 ;
     RECT  2316.72 1369.76 2383.56 1576.14 ;
     RECT  179.53 1567.13 531.14 1576.34 ;
     RECT  1501.14 1270.82 1520.14 1576.34 ;
     RECT  1533.34 1573.28 1539.46 1576.34 ;
     RECT  1261.48 1073.14 1274.04 1576.48 ;
     RECT  1449.11 1103.88 1473.22 1576.48 ;
     RECT  1567.38 1259.94 1567.52 1576.48 ;
     RECT  2822.26 1575.97 2829.76 1576.65 ;
     RECT  2556.84 1535.17 2618.62 1576.82 ;
     RECT  631.28 1390.33 633.26 1577.16 ;
     RECT  175.88 1576.34 531.14 1577.84 ;
     RECT  1585.32 1300.74 1618.12 1578.18 ;
     RECT  2468.98 1535.17 2546.93 1578.69 ;
     RECT  175.88 1577.84 530.22 1580.22 ;
     RECT  2420.22 1487.06 2439.22 1580.9 ;
     RECT  2301.54 1369.76 2303.06 1581.24 ;
     RECT  2829.16 1576.65 2829.76 1581.41 ;
     RECT  1359.46 1169.02 1360.98 1581.92 ;
     RECT  1325.88 1190.44 1326.02 1582.09 ;
     RECT  539.74 1581.27 539.88 1583.45 ;
     RECT  2115.7 1312.3 2127.8 1583.62 ;
     RECT  1927.1 1344.94 1934.6 1583.96 ;
     RECT  175.88 1580.22 529.3 1584.64 ;
     RECT  550.32 1574.44 601.06 1585.575 ;
     RECT  420.14 1584.64 529.3 1586.34 ;
     RECT  2794.66 1456.8 2809.52 1586.85 ;
     RECT  2705.88 1573.93 2726.93 1587.53 ;
     RECT  175.88 1584.64 408.78 1589.06 ;
     RECT  271.56 1589.06 310.34 1589.4 ;
     RECT  323.08 1589.06 408.78 1589.57 ;
     RECT  2656.2 1266.06 2668.76 1589.57 ;
     RECT  189.11 1589.06 262.04 1589.74 ;
     RECT  271.56 1589.4 309.88 1590.08 ;
     RECT  421.06 1586.34 529.3 1590.76 ;
     RECT  1615.22 1578.18 1618.12 1590.76 ;
     RECT  549.11 1585.575 601.06 1592.12 ;
     RECT  324 1589.57 408.78 1592.29 ;
     RECT  1737.58 1348 1760.72 1592.29 ;
     RECT  1360.84 1581.92 1360.98 1592.8 ;
     RECT  9.11 1571.38 26.93 1592.97 ;
     RECT  398.06 1592.29 408.78 1594.84 ;
     RECT  2681.04 1473.12 2681.18 1595.01 ;
     RECT  2065.1 1188.2 2072.14 1595.52 ;
     RECT  1390.28 1549.14 1404.22 1595.86 ;
     RECT  1089.11 982.5 1091.93 1597.08 ;
     RECT  1104.11 1175.82 1114.88 1597.08 ;
     RECT  407.72 1594.84 408.78 1597.22 ;
     RECT  421.06 1590.76 514.12 1597.22 ;
     RECT  2450.58 1487.06 2457.62 1597.22 ;
     RECT  523.64 1590.76 529.3 1597.42 ;
     RECT  1840.16 1439.46 1852.26 1597.56 ;
     RECT  2664.48 1589.57 2668.76 1597.73 ;
     RECT  611.04 1559.82 618.08 1597.9 ;
     RECT  523.64 1597.42 533.9 1598.24 ;
     RECT  292.72 1590.08 309.88 1598.41 ;
     RECT  2453.34 1597.22 2457.62 1598.41 ;
     RECT  189.11 1589.74 206.93 1599.63 ;
     RECT  38.8 1574.1 163.14 1600.28 ;
     RECT  448.66 1597.22 514.12 1600.28 ;
     RECT  217.28 1589.74 262.04 1600.48 ;
     RECT  271.56 1590.08 282.74 1600.48 ;
     RECT  217.28 1600.48 282.74 1600.62 ;
     RECT  407.72 1597.22 408.32 1600.62 ;
     RECT  421.06 1597.22 434.54 1601.13 ;
     RECT  2556.84 1576.82 2581.82 1601.3 ;
     RECT  720.98 1134.055 746.93 1601.81 ;
     RECT  457.86 1600.28 514.12 1602.49 ;
     RECT  2764.76 1281.7 2781 1602.66 ;
     RECT  462 1602.49 514.12 1603.34 ;
     RECT  421.06 1601.13 433.62 1603.68 ;
     RECT  2196.2 1341.88 2222.1 1604.36 ;
     RECT  38.8 1600.28 162.68 1605.38 ;
     RECT  2272.1 1179.36 2279.14 1605.38 ;
     RECT  2766.6 1602.66 2781 1605.89 ;
     RECT  1628.56 1151.14 1632.84 1607.11 ;
     RECT  549.11 1592.12 600.6 1607.79 ;
     RECT  909.11 1134.68 914.32 1607.79 ;
     RECT  1089.11 1597.08 1114.88 1607.79 ;
     RECT  1261.48 1576.48 1271.93 1607.79 ;
     RECT  1449.11 1576.48 1466.93 1607.79 ;
     RECT  2488.76 1578.69 2546.93 1607.93 ;
     RECT  324 1592.29 388.54 1608.1 ;
     RECT  728.34 1601.81 746.93 1608.1 ;
     RECT  908.2 1607.79 914.32 1608.1 ;
     RECT  1088.52 1607.79 1114.88 1608.1 ;
     RECT  1261.48 1607.79 1272.66 1608.1 ;
     RECT  1448.24 1607.79 1466.93 1608.1 ;
     RECT  2794.66 1586.85 2802.16 1608.44 ;
     RECT  1628.1 1607.11 1632.84 1608.47 ;
     RECT  217.28 1600.62 245.02 1608.78 ;
     RECT  2514.98 1607.93 2546.93 1608.78 ;
     RECT  2217.36 1604.36 2222.1 1609.12 ;
     RECT  2155.26 1204.52 2173.8 1609.46 ;
     RECT  1644.11 1571.21 1677.92 1609.8 ;
     RECT  189.11 1599.63 207.76 1609.97 ;
     RECT  1628.1 1608.47 1633.3 1609.97 ;
     RECT  631.28 1577.16 632.8 1610.82 ;
     RECT  2127.66 1583.62 2127.8 1611.16 ;
     RECT  337.8 1608.1 388.54 1611.5 ;
     RECT  1840.16 1597.56 1846.28 1611.5 ;
     RECT  2766.6 1605.89 2775.94 1612.01 ;
     RECT  2802.02 1608.44 2802.16 1612.18 ;
     RECT  424.28 1603.68 433.62 1612.52 ;
     RECT  217.28 1608.78 227.54 1614.05 ;
     RECT  324 1608.1 327.82 1614.05 ;
     RECT  463.38 1603.34 514.12 1614.42 ;
     RECT  1063.22 1577.02 1063.36 1614.59 ;
     RECT  1089.11 1608.1 1114.88 1614.59 ;
     RECT  1129.46 1431.84 1129.6 1614.59 ;
     RECT  1284.11 1025 1286.93 1614.59 ;
     RECT  444.06 1614.59 445.58 1614.73 ;
     RECT  1313.46 1614.59 1314.98 1614.73 ;
     RECT  2519.58 1608.78 2546.93 1614.73 ;
     RECT  1284.11 1614.59 1289.22 1614.76 ;
     RECT  1449.11 1608.1 1466.93 1614.76 ;
     RECT  1644.11 1609.8 1649.86 1614.76 ;
     RECT  337.8 1611.5 337.94 1614.9 ;
     RECT  424.28 1612.52 427.64 1614.9 ;
     RECT  1283.56 1614.76 1289.22 1614.9 ;
     RECT  1643.28 1614.76 1649.86 1614.9 ;
     RECT  348.38 1611.5 388.54 1615.24 ;
     RECT  2749.58 1086.88 2749.72 1615.24 ;
     RECT  2184.11 1190.24 2186.93 1615.27 ;
     RECT  444.06 1614.73 444.2 1615.41 ;
     RECT  1283.56 1614.9 1288.3 1615.41 ;
     RECT  1313.46 1614.73 1313.6 1615.41 ;
     RECT  1643.28 1614.9 1648.94 1615.41 ;
     RECT  348.38 1615.24 371.93 1616.09 ;
     RECT  398.06 1594.84 398.2 1616.09 ;
     RECT  1063.22 1614.59 1072.1 1616.09 ;
     RECT  2071.54 1595.52 2072.14 1616.09 ;
     RECT  2556.84 1601.3 2570.78 1616.26 ;
     RECT  524.1 1598.24 533.9 1616.6 ;
     RECT  2581.68 1601.3 2581.82 1616.6 ;
     RECT  382.42 1615.24 388.54 1616.63 ;
     RECT  527.78 1616.6 533.9 1616.63 ;
     RECT  548.48 1607.79 600.6 1616.63 ;
     RECT  729.11 1608.1 746.93 1616.63 ;
     RECT  909.11 1608.1 914.32 1616.63 ;
     RECT  924.11 1341.74 931.8 1616.63 ;
     RECT  1449.11 1614.76 1467.7 1616.63 ;
     RECT  1974.48 1339.5 2006.93 1616.63 ;
     RECT  1284.11 1615.41 1288.3 1616.77 ;
     RECT  2468.98 1578.69 2477.86 1616.77 ;
     RECT  1617.98 1590.76 1618.12 1616.94 ;
     RECT  909.11 1616.63 931.8 1617.28 ;
     RECT  217.28 1614.05 227.08 1617.45 ;
     RECT  2456.1 1598.41 2457.62 1617.45 ;
     RECT  424.28 1614.9 425.34 1617.62 ;
     RECT  631.74 1610.82 632.8 1617.62 ;
     RECT  2160.78 1609.46 2173.8 1617.96 ;
     RECT  382.42 1616.63 397.74 1618.13 ;
     RECT  729.11 1616.63 748.26 1618.13 ;
     RECT  922.46 1617.28 931.8 1618.13 ;
     RECT  1449.11 1616.63 1468.62 1618.13 ;
     RECT  1840.16 1611.5 1845.82 1618.13 ;
     RECT  2183.32 1615.27 2186.93 1618.13 ;
     RECT  2217.36 1609.12 2217.5 1618.13 ;
     RECT  462.46 1614.42 514.12 1618.98 ;
     RECT  226.94 1617.45 227.08 1619.32 ;
     RECT  2488.76 1607.93 2503.16 1619.32 ;
     RECT  1063.22 1616.09 1070.72 1619.49 ;
     RECT  1089.11 1614.59 1129.6 1619.49 ;
     RECT  1284.11 1616.77 1287.84 1619.49 ;
     RECT  1840.16 1618.13 1845.36 1619.49 ;
     RECT  527.78 1616.63 600.6 1620.17 ;
     RECT  1628.1 1609.97 1632.84 1620.17 ;
     RECT  1693.42 1310.6 1706.9 1621.56 ;
     RECT  1720.1 1570.36 1720.24 1621.56 ;
     RECT  1974.48 1616.63 2008.66 1621.56 ;
     RECT  382.88 1618.13 397.74 1621.7 ;
     RECT  631.74 1617.62 632.34 1621.7 ;
     RECT  1693.42 1621.56 1720.24 1621.7 ;
     RECT  1974.48 1621.56 2013.72 1621.7 ;
     RECT  2394.92 1391.01 2407.94 1622.04 ;
     RECT  324 1614.05 324.14 1622.21 ;
     RECT  2470.36 1616.77 2477.86 1622.38 ;
     RECT  189.11 1609.97 206.93 1622.72 ;
     RECT  2594.1 1576.82 2618.62 1622.89 ;
     RECT  2086.72 1574.1 2095.14 1623.06 ;
     RECT  464.3 1618.98 514.12 1623.4 ;
     RECT  2325 1576.14 2383.56 1623.4 ;
     RECT  2115.7 1583.62 2115.84 1624.28 ;
     RECT  1701.7 1621.7 1720.24 1624.42 ;
     RECT  1916.06 1432.32 1916.66 1624.76 ;
     RECT  254.54 1600.62 282.74 1624.93 ;
     RECT  2325 1623.4 2378.5 1624.93 ;
     RECT  1927.1 1583.96 1927.24 1624.96 ;
     RECT  464.3 1623.4 483.3 1625.1 ;
     RECT  765.6 1132.78 765.74 1625.3 ;
     RECT  1416.04 1118.5 1416.18 1625.3 ;
     RECT  408.18 1600.62 408.32 1625.44 ;
     RECT  815.74 1091.81 820.48 1625.44 ;
     RECT  1659.38 1609.8 1677.92 1625.44 ;
     RECT  1701.7 1624.42 1714.72 1625.44 ;
     RECT  397.6 1621.7 397.74 1625.61 ;
     RECT  2232.08 1341.88 2232.22 1625.61 ;
     RECT  1644.11 1615.41 1648.94 1625.64 ;
     RECT  1659.38 1625.44 1659.52 1625.64 ;
     RECT  1701.7 1625.44 1701.84 1625.78 ;
     RECT  254.54 1624.93 281.82 1627.14 ;
     RECT  2643.78 1445.41 2643.92 1627.14 ;
     RECT  1916.52 1624.76 1916.66 1627.65 ;
     RECT  294.56 1598.41 309.88 1628.33 ;
     RECT  294.56 1628.33 310.34 1628.47 ;
     RECT  266.5 1627.14 281.82 1628.5 ;
     RECT  2668.62 1597.73 2668.76 1628.5 ;
     RECT  349.3 1616.09 371.93 1628.87 ;
     RECT  1261.48 1608.1 1271.93 1628.87 ;
     RECT  271.56 1628.5 281.82 1629.01 ;
     RECT  548.48 1620.17 600.6 1629.01 ;
     RECT  2325 1624.93 2332.96 1629.01 ;
     RECT  1197.54 1629.72 1197.68 1630.06 ;
     RECT  310.2 1628.47 310.34 1630.2 ;
     RECT  2503.02 1619.32 2503.16 1630.2 ;
     RECT  349.3 1628.87 372.9 1630.23 ;
     RECT  382.88 1621.7 386.93 1630.23 ;
     RECT  527.78 1620.17 533.9 1630.23 ;
     RECT  729.11 1618.13 746.93 1630.23 ;
     RECT  864.96 1617.82 865.1 1630.23 ;
     RECT  924.11 1618.13 931.8 1630.23 ;
     RECT  1433.52 1238.52 1433.66 1630.23 ;
     RECT  1628.56 1620.17 1632.84 1630.23 ;
     RECT  2141.92 1224.58 2142.52 1630.23 ;
     RECT  2184.11 1618.13 2186.93 1630.23 ;
     RECT  1072.88 1628.87 1073.02 1630.37 ;
     RECT  1261.48 1628.87 1273.58 1630.37 ;
     RECT  527.78 1630.23 536.2 1630.54 ;
     RECT  2394.92 1622.04 2404.72 1630.54 ;
     RECT  2829.62 1581.41 2829.76 1631.05 ;
     RECT  1179.6 1210.84 1179.74 1631.08 ;
     RECT  1628.56 1630.23 1633.3 1631.22 ;
     RECT  1179.6 1631.08 1183.42 1631.42 ;
     RECT  1194.32 1630.06 1198.14 1631.42 ;
     RECT  347.46 1630.23 386.93 1631.73 ;
     RECT  533.76 1630.54 536.2 1631.73 ;
     RECT  727.42 1630.23 746.93 1631.73 ;
     RECT  861.74 1630.23 865.1 1631.73 ;
     RECT  923.38 1630.23 931.8 1631.73 ;
     RECT  1433.52 1630.23 1437.8 1631.73 ;
     RECT  1629.11 1631.22 1633.3 1631.73 ;
     RECT  1788.64 1146.38 1826.93 1631.73 ;
     RECT  1987.82 1621.7 2013.72 1631.73 ;
     RECT  2135.48 1630.23 2142.52 1631.73 ;
     RECT  2183.32 1630.23 2186.93 1631.73 ;
     RECT  1179.6 1631.42 1198.14 1632.58 ;
     RECT  1802.9 1631.73 1826.93 1633.09 ;
     RECT  274.78 1629.01 281.82 1633.77 ;
     RECT  2709.11 1587.53 2726.93 1633.77 ;
     RECT  496.96 1623.4 514.12 1635.16 ;
     RECT  2556.84 1616.26 2556.98 1635.64 ;
     RECT  281.68 1633.77 281.82 1635.98 ;
     RECT  2344.78 1624.93 2378.5 1635.98 ;
     RECT  2378.36 1635.98 2378.5 1636.32 ;
     RECT  2709.11 1633.77 2714.3 1636.49 ;
     RECT  349.3 1631.73 371.93 1636.66 ;
     RECT  2344.78 1635.98 2366.93 1636.66 ;
     RECT  496.96 1635.16 521.94 1637 ;
     RECT  2403.2 1630.54 2404.72 1637 ;
     RECT  349.3 1636.66 358.18 1637.17 ;
     RECT  501.56 1637 512.28 1637.17 ;
     RECT  294.56 1628.47 300.68 1637.85 ;
     RECT  521.8 1637 521.94 1638.36 ;
     RECT  42.48 1605.38 162.68 1638.7 ;
     RECT  617.94 1597.9 618.08 1638.7 ;
     RECT  2349.11 1636.66 2366.93 1638.7 ;
     RECT  1944.12 1445.92 1953 1639.04 ;
     RECT  1501.14 1576.34 1539.46 1639.24 ;
     RECT  66.86 1638.7 162.68 1639.38 ;
     RECT  501.56 1637.17 511.36 1639.38 ;
     RECT  1585.32 1578.18 1604.78 1639.38 ;
     RECT  254.54 1627.14 254.68 1639.58 ;
     RECT  1416.04 1625.3 1423.54 1639.72 ;
     RECT  397.6 1636.35 397.74 1639.89 ;
     RECT  240.74 1608.78 245.02 1640.6 ;
     RECT  254.54 1639.58 258.36 1640.6 ;
     RECT  1449.11 1618.13 1466.93 1640.6 ;
     RECT  1501.14 1639.24 1542.22 1640.74 ;
     RECT  469.36 1625.1 483.3 1641.08 ;
     RECT  469.36 1641.08 476.86 1641.11 ;
     RECT  1788.64 1631.73 1788.78 1641.25 ;
     RECT  2598.24 1622.89 2618.62 1641.76 ;
     RECT  1882.94 1150.12 1891.36 1641.93 ;
     RECT  382.88 1631.73 386.93 1642.3 ;
     RECT  729.11 1631.73 746.93 1642.3 ;
     RECT  924.11 1631.73 931.8 1642.3 ;
     RECT  1284.11 1619.49 1286.93 1642.3 ;
     RECT  349.3 1637.17 355.42 1642.44 ;
     RECT  1283.56 1642.3 1287.84 1642.61 ;
     RECT  2089.02 1623.06 2095.14 1642.61 ;
     RECT  349.3 1642.44 354.96 1643.15 ;
     RECT  533.76 1631.73 533.9 1643.15 ;
     RECT  549.11 1629.01 600.6 1643.15 ;
     RECT  1063.22 1619.49 1063.36 1643.15 ;
     RECT  1089.11 1619.49 1114.88 1643.15 ;
     RECT  1129.46 1619.49 1129.6 1643.15 ;
     RECT  1629.11 1631.73 1632.84 1643.15 ;
     RECT  444.06 1643.15 445.58 1643.29 ;
     RECT  217.28 1617.45 217.42 1643.32 ;
     RECT  240.74 1640.6 258.36 1643.66 ;
     RECT  2089.02 1642.61 2092.38 1643.8 ;
     RECT  382.88 1642.3 396.82 1643.83 ;
     RECT  729.11 1642.3 747.8 1643.83 ;
     RECT  923.38 1642.3 931.8 1643.83 ;
     RECT  1063.22 1643.15 1072.56 1643.83 ;
     RECT  1284.11 1642.61 1287.84 1643.83 ;
     RECT  1802.9 1633.09 1811.93 1643.83 ;
     RECT  1840.16 1619.49 1840.3 1643.83 ;
     RECT  1989.11 1631.73 2013.72 1643.83 ;
     RECT  347.46 1643.15 354.96 1643.97 ;
     RECT  444.06 1643.29 444.2 1643.97 ;
     RECT  533.76 1643.15 600.6 1643.97 ;
     RECT  1063.22 1643.83 1073.94 1643.97 ;
     RECT  2523.72 1614.73 2546.93 1643.97 ;
     RECT  201.64 1622.72 206.93 1644 ;
     RECT  217.28 1643.32 230.3 1644 ;
     RECT  240.74 1643.66 262.04 1644 ;
     RECT  240.28 1644 263.42 1644.14 ;
     RECT  1503.44 1640.74 1542.22 1644.14 ;
     RECT  1590.38 1639.38 1604.78 1644.14 ;
     RECT  2115.7 1624.28 2124.12 1644.14 ;
     RECT  2327.76 1629.01 2332.96 1644.14 ;
     RECT  2599.62 1641.76 2618.62 1644.65 ;
     RECT  66.86 1639.38 162.22 1644.82 ;
     RECT  1590.38 1644.14 1590.52 1644.82 ;
     RECT  1504.36 1644.14 1542.22 1645.02 ;
     RECT  1644.11 1625.64 1659.52 1645.02 ;
     RECT  2161.24 1617.96 2173.8 1645.02 ;
     RECT  349.3 1643.97 354.96 1645.16 ;
     RECT  2766.6 1612.01 2769.96 1645.19 ;
     RECT  240.28 1644.14 245.02 1645.33 ;
     RECT  382.42 1643.83 396.82 1645.33 ;
     RECT  922.46 1643.83 931.8 1645.33 ;
     RECT  1089.11 1643.15 1129.6 1645.33 ;
     RECT  382.88 1645.33 393.14 1646.01 ;
     RECT  1670.88 1625.44 1677.92 1646.01 ;
     RECT  1927.1 1624.96 1927.7 1646.04 ;
     RECT  1944.12 1639.04 1944.26 1646.04 ;
     RECT  2040.26 1111.36 2053.74 1646.04 ;
     RECT  2301.54 1581.24 2301.68 1646.04 ;
     RECT  705.34 1611.02 705.48 1646.18 ;
     RECT  666.24 1638.9 666.38 1646.38 ;
     RECT  729.11 1643.83 748.26 1646.38 ;
     RECT  799.18 1369.96 799.32 1646.38 ;
     RECT  831.84 1179.22 831.98 1646.38 ;
     RECT  864.96 1631.73 865.1 1646.38 ;
     RECT  898.54 1605.24 898.68 1646.38 ;
     RECT  996.52 1356.02 996.66 1646.38 ;
     RECT  1030.1 1638.56 1030.24 1646.38 ;
     RECT  1063.22 1643.97 1063.36 1646.38 ;
     RECT  1340.6 1190.24 1340.74 1646.38 ;
     RECT  1676.4 1646.01 1677.92 1646.38 ;
     RECT  1776.22 1348 1776.36 1646.38 ;
     RECT  1797.38 1643.83 1811.93 1646.38 ;
     RECT  1866.84 1567.3 1866.98 1646.38 ;
     RECT  1882.94 1641.93 1883.08 1646.38 ;
     RECT  1974.48 1621.7 1974.62 1646.38 ;
     RECT  2072 1616.09 2072.14 1646.38 ;
     RECT  2142.38 1631.73 2142.52 1646.38 ;
     RECT  2196.2 1604.36 2204.62 1646.38 ;
     RECT  2279 1605.38 2279.14 1646.38 ;
     RECT  2364.11 1638.7 2366.93 1646.38 ;
     RECT  2420.22 1580.9 2431.86 1646.38 ;
     RECT  2709.11 1636.49 2711.93 1646.38 ;
     RECT  1601.88 1644.14 1604.78 1646.52 ;
     RECT  1396.26 1595.86 1404.22 1646.55 ;
     RECT  255 1644.14 263.42 1646.69 ;
     RECT  1797.38 1646.38 1812.24 1646.69 ;
     RECT  1840.16 1643.83 1845.82 1646.69 ;
     RECT  1988.74 1643.83 2013.72 1646.69 ;
     RECT  201.64 1644 230.3 1646.72 ;
     RECT  467.52 1641.11 476.86 1646.72 ;
     RECT  1449.11 1640.6 1469.54 1646.72 ;
     RECT  1569.68 1578.04 1569.82 1646.72 ;
     RECT  1737.58 1592.29 1752.9 1646.86 ;
     RECT  1866.84 1646.38 1883.08 1646.86 ;
     RECT  1989.11 1646.69 2013.72 1646.86 ;
     RECT  2196.2 1646.38 2206.46 1646.86 ;
     RECT  2255.08 1570.53 2255.22 1646.86 ;
     RECT  1569.68 1646.72 1578.56 1647.06 ;
     RECT  201.64 1646.72 234.44 1647.2 ;
     RECT  467.06 1646.72 476.86 1647.2 ;
     RECT  501.56 1639.38 501.7 1647.2 ;
     RECT  533.76 1643.97 538.04 1647.2 ;
     RECT  631.74 1621.7 631.88 1647.2 ;
     RECT  665.32 1646.38 666.38 1647.2 ;
     RECT  765.6 1625.3 773.1 1647.2 ;
     RECT  798.26 1646.38 799.32 1647.2 ;
     RECT  830.92 1646.38 831.98 1647.2 ;
     RECT  864.04 1646.38 865.1 1647.2 ;
     RECT  896.7 1646.38 898.68 1647.2 ;
     RECT  924.11 1645.33 931.8 1647.2 ;
     RECT  964.32 1168 964.46 1647.2 ;
     RECT  995.6 1646.38 996.66 1647.2 ;
     RECT  1029.18 1646.38 1030.24 1647.2 ;
     RECT  1062.3 1646.38 1063.36 1647.2 ;
     RECT  1129.46 1645.33 1129.6 1647.2 ;
     RECT  1332.32 1646.38 1340.74 1647.2 ;
     RECT  1396.26 1646.55 1405.14 1647.2 ;
     RECT  1423.4 1639.72 1423.54 1647.2 ;
     RECT  1433.52 1631.73 1433.66 1647.2 ;
     RECT  1504.36 1645.02 1544.06 1647.2 ;
     RECT  1560.94 1647.06 1578.56 1647.2 ;
     RECT  1616.14 1625.3 1616.28 1647.2 ;
     RECT  1643.28 1645.02 1659.52 1647.2 ;
     RECT  1714.58 1625.44 1714.72 1647.2 ;
     RECT  1739.42 1646.86 1752.9 1647.2 ;
     RECT  1840.16 1646.69 1840.3 1647.2 ;
     RECT  1866.84 1646.86 1875.26 1647.2 ;
     RECT  1973.56 1646.38 1974.62 1647.2 ;
     RECT  2004.11 1646.86 2013.72 1647.2 ;
     RECT  2115.7 1644.14 2123.2 1647.2 ;
     RECT  2140.08 1646.38 2142.52 1647.2 ;
     RECT  2159.86 1645.02 2173.8 1647.2 ;
     RECT  2273.94 1646.38 2279.14 1647.2 ;
     RECT  2301.54 1646.04 2305.82 1647.2 ;
     RECT  2404.58 1637 2404.72 1647.2 ;
     RECT  2456.1 1617.45 2456.24 1647.2 ;
     RECT  2470.36 1622.38 2471.42 1647.2 ;
     RECT  2649.3 1644.68 2649.44 1647.2 ;
     RECT  66.86 1644.82 134.16 1647.37 ;
     RECT  265.58 1647.06 271.7 1647.37 ;
     RECT  1284.11 1643.83 1288.3 1647.37 ;
     RECT  1628.1 1643.15 1632.84 1647.37 ;
     RECT  1332.32 1647.2 1332.46 1647.4 ;
     RECT  1643.28 1647.2 1646.93 1647.4 ;
     RECT  728.8 1646.38 751.94 1647.54 ;
     RECT  1533.34 1647.2 1544.06 1647.54 ;
     RECT  424.28 1617.62 424.42 1647.74 ;
     RECT  537.9 1647.2 538.04 1647.88 ;
     RECT  2760.16 1645.19 2769.96 1647.88 ;
     RECT  1261.48 1630.37 1271.93 1649.1 ;
     RECT  130.8 1647.37 134.16 1649.24 ;
     RECT  1659.38 1647.2 1659.52 1649.24 ;
     RECT  1773.46 1646.38 1776.36 1649.58 ;
     RECT  201.64 1647.2 206.93 1650.09 ;
     RECT  2420.22 1646.38 2438.3 1650.09 ;
     RECT  298.7 1637.85 300.68 1650.12 ;
     RECT  42.48 1638.7 57.34 1650.6 ;
     RECT  549.11 1643.97 600.6 1651.62 ;
     RECT  66.86 1647.37 121.28 1651.96 ;
     RECT  549.11 1651.62 593.24 1651.96 ;
     RECT  220.04 1647.2 234.44 1652.13 ;
     RECT  130.8 1649.24 130.94 1652.3 ;
     RECT  1260.56 1649.1 1271.93 1652.5 ;
     RECT  2889.11 1505.76 2891.93 1652.5 ;
     RECT  2904.11 1564.58 2906.93 1652.5 ;
     RECT  1518.62 1647.2 1518.76 1652.64 ;
     RECT  2875.62 1505.76 2875.76 1652.64 ;
     RECT  2035.2 1646.04 2053.74 1652.81 ;
     RECT  220.04 1652.13 220.18 1652.98 ;
     RECT  9.11 1592.97 11.93 1653.18 ;
     RECT  24.11 1592.97 26.93 1653.18 ;
     RECT  768.82 1647.2 768.96 1653.32 ;
     RECT  66.86 1651.96 107.02 1654.34 ;
     RECT  1927.1 1646.04 1944.26 1654.34 ;
     RECT  382.88 1646.01 386.93 1654.68 ;
     RECT  424.28 1647.74 428.1 1654.85 ;
     RECT  2328.68 1644.14 2332.96 1654.85 ;
     RECT  2609.28 1644.65 2618.62 1655.02 ;
     RECT  511.22 1639.38 511.36 1655.53 ;
     RECT  2599.62 1644.65 2599.76 1655.9 ;
     RECT  2488.76 1619.32 2489.82 1656.21 ;
     RECT  383.8 1654.68 386.93 1657.06 ;
     RECT  42.48 1650.6 56.88 1657.4 ;
     RECT  924.11 1647.2 930.88 1657.43 ;
     RECT  78.82 1654.34 107.02 1657.74 ;
     RECT  2425.28 1650.09 2438.3 1657.74 ;
     RECT  94 1657.74 107.02 1658.08 ;
     RECT  2196.2 1646.86 2196.34 1658.08 ;
     RECT  202.1 1650.09 206.93 1658.25 ;
     RECT  78.82 1657.74 83.1 1658.42 ;
     RECT  2072 1646.38 2073.98 1658.42 ;
     RECT  94 1658.08 106.56 1658.76 ;
     RECT  1742.64 1647.2 1752.9 1658.76 ;
     RECT  923.38 1657.43 930.88 1658.93 ;
     RECT  1629.11 1647.37 1632.84 1659.78 ;
     RECT  1331.86 1647.4 1332.46 1660.12 ;
     RECT  1560.94 1647.2 1561.08 1660.12 ;
     RECT  2470.36 1647.2 2470.96 1660.29 ;
     RECT  296.4 1650.12 300.68 1660.46 ;
     RECT  1449.11 1646.72 1470 1660.97 ;
     RECT  117 1651.96 121.28 1663.01 ;
     RECT  2766.6 1647.88 2769.96 1663.01 ;
     RECT  354.82 1645.16 354.96 1663.18 ;
     RECT  2527.4 1643.97 2546.93 1663.52 ;
     RECT  80.66 1658.42 83.1 1663.69 ;
     RECT  2089.02 1643.8 2089.16 1663.69 ;
     RECT  81.12 1663.69 83.1 1663.86 ;
     RECT  2529.11 1663.52 2546.93 1663.86 ;
     RECT  66.86 1654.34 67 1664.2 ;
     RECT  2489.68 1656.21 2489.82 1664.2 ;
     RECT  2035.2 1652.81 2046.84 1665.22 ;
     RECT  2035.2 1665.22 2040.4 1665.56 ;
     RECT  42.48 1657.4 51.82 1665.9 ;
     RECT  1935.84 1654.34 1944.26 1665.9 ;
     RECT  94 1658.76 101.04 1666.24 ;
     RECT  1752.76 1658.76 1752.9 1666.24 ;
     RECT  255 1646.69 255.14 1666.41 ;
     RECT  1256.88 1652.5 1271.93 1666.44 ;
     RECT  1284.11 1647.37 1286.93 1666.44 ;
     RECT  244.42 1645.33 244.56 1666.58 ;
     RECT  175.88 1589.06 176.02 1666.92 ;
     RECT  579.76 1651.96 593.24 1666.92 ;
     RECT  150.12 1644.82 162.22 1667.94 ;
     RECT  2769.36 1663.01 2769.96 1667.94 ;
     RECT  234.3 1652.13 234.44 1668.45 ;
     RECT  1642.36 1647.4 1646.93 1669.13 ;
     RECT  42.48 1665.9 42.62 1670.66 ;
     RECT  2431.26 1657.74 2438.3 1670.66 ;
     RECT  94 1666.24 94.14 1671 ;
     RECT  1802.9 1646.69 1812.24 1671 ;
     RECT  155.18 1667.94 162.22 1671.34 ;
     RECT  1404.08 1647.2 1405.14 1671.34 ;
     RECT  121.14 1663.01 121.28 1671.68 ;
     RECT  586.66 1666.92 593.24 1671.68 ;
     RECT  156.56 1671.34 162.22 1672.02 ;
     RECT  588.96 1671.68 593.24 1672.02 ;
     RECT  1424.78 1647.4 1424.92 1673.38 ;
     RECT  1541.16 1647.54 1544.06 1673.72 ;
     RECT  271.56 1647.37 271.7 1680.18 ;
     RECT  189.11 1622.72 191.93 1680.38 ;
     RECT  204.11 1658.25 206.93 1680.38 ;
     RECT  1504.36 1647.2 1504.96 1680.52 ;
     RECT  1387.52 1647.4 1387.66 1681.54 ;
     RECT  217.28 1660.83 217.42 1684.8 ;
     RECT  1256.88 1666.44 1286.93 1684.94 ;
     RECT  1435.36 1659.98 1435.5 1685.28 ;
     RECT  524.56 1647.74 524.7 1685.48 ;
     RECT  1449.11 1660.97 1451.93 1685.48 ;
     RECT  549.11 1651.96 566.93 1685.62 ;
     RECT  699.36 1646.38 699.5 1685.62 ;
     RECT  830.92 1647.2 831.06 1685.62 ;
     RECT  896.7 1647.2 896.84 1685.62 ;
     RECT  1029.18 1647.2 1029.32 1685.62 ;
     RECT  1089.11 1645.33 1117.64 1685.62 ;
     RECT  2599.62 1655.9 2603.9 1685.62 ;
     RECT  621.16 1646.38 621.3 1685.82 ;
     RECT  951.9 1646.38 952.04 1685.82 ;
     RECT  1089.11 1685.62 1091.93 1685.82 ;
     RECT  156.56 1672.02 156.7 1685.96 ;
     RECT  593.1 1672.02 593.24 1685.96 ;
     RECT  665.32 1647.2 665.46 1685.96 ;
     RECT  728.8 1647.54 731.93 1685.96 ;
     RECT  798.26 1647.2 798.4 1685.96 ;
     RECT  864.04 1647.2 864.18 1685.96 ;
     RECT  924.11 1658.93 930.88 1685.96 ;
     RECT  995.6 1647.2 995.74 1685.96 ;
     RECT  1062.3 1647.2 1062.44 1685.96 ;
     RECT  1104.11 1685.62 1117.64 1685.96 ;
     RECT  1260.56 1684.94 1286.93 1685.96 ;
     RECT  9.11 1653.18 26.93 1686.585 ;
     RECT  189.11 1680.38 206.93 1686.585 ;
     RECT  384.11 1657.06 386.93 1686.585 ;
     RECT  564.11 1685.62 566.93 1686.585 ;
     RECT  744.11 1647.54 751.94 1686.585 ;
     RECT  924.11 1685.96 926.93 1686.585 ;
     RECT  1104.11 1685.96 1114.88 1686.585 ;
     RECT  1261.48 1685.96 1286.93 1686.585 ;
     RECT  1464.11 1660.97 1470 1686.585 ;
     RECT  1643.28 1669.13 1646.93 1686.585 ;
     RECT  1824.11 1633.09 1826.93 1686.585 ;
     RECT  2004.11 1647.2 2006.93 1686.585 ;
     RECT  2184.11 1631.73 2186.93 1686.585 ;
     RECT  2364.11 1646.38 2372.06 1686.585 ;
     RECT  2544.11 1663.86 2546.93 1686.585 ;
     RECT  2724.11 1633.77 2726.93 1686.585 ;
     RECT  2889.11 1652.5 2906.93 1686.585 ;
     RECT  255 1685.14 255.14 1686.98 ;
     RECT  296.4 1660.46 296.54 1686.98 ;
     RECT  1317.6 1652.84 1317.74 1686.98 ;
     RECT  1371.88 1685.82 1372.02 1686.98 ;
     RECT  1405 1671.34 1405.14 1686.98 ;
     RECT  2829.16 1666.27 2829.3 1686.98 ;
     RECT  217.28 1684.8 219.26 1687.32 ;
     RECT  1332.32 1660.12 1332.46 1687.32 ;
     RECT  9.11 1686.585 20.54 1687.66 ;
     RECT  82.96 1663.86 83.1 1687.66 ;
     RECT  96.3 1681.4 96.44 1687.66 ;
     RECT  119.76 1685.82 119.9 1687.66 ;
     RECT  189.11 1686.585 199.94 1687.66 ;
     RECT  217.74 1687.32 219.26 1687.66 ;
     RECT  351.6 1668.99 351.74 1687.66 ;
     RECT  414.16 1646.04 414.3 1687.66 ;
     RECT  427.96 1654.85 428.1 1687.66 ;
     RECT  467.06 1647.2 467.2 1687.66 ;
     RECT  651.06 1685.48 651.2 1687.66 ;
     RECT  682.8 1685.82 682.94 1687.66 ;
     RECT  782.16 1685.48 782.3 1687.66 ;
     RECT  815.28 1685.82 815.42 1687.66 ;
     RECT  848.4 1685.48 848.54 1687.66 ;
     RECT  882.9 1685.82 883.04 1687.66 ;
     RECT  980.88 1685.48 981.02 1687.66 ;
     RECT  1014 1685.82 1014.14 1687.66 ;
     RECT  1047.12 1685.48 1047.26 1687.66 ;
     RECT  1080.24 1685.82 1091.93 1687.66 ;
     RECT  1111.98 1686.585 1114.88 1687.66 ;
     RECT  1179.6 1632.58 1179.74 1687.66 ;
     RECT  1212.72 1685.82 1212.86 1687.66 ;
     RECT  1245.84 1673.58 1245.98 1687.66 ;
     RECT  1261.48 1686.585 1277.72 1687.66 ;
     RECT  1469.86 1686.585 1470 1687.66 ;
     RECT  1504.82 1680.52 1504.96 1687.66 ;
     RECT  1543.92 1673.72 1544.06 1687.66 ;
     RECT  1578.42 1647.2 1578.56 1687.66 ;
     RECT  1601.88 1646.52 1602.02 1687.66 ;
     RECT  1643.28 1686.585 1643.42 1687.66 ;
     RECT  1676.4 1646.38 1678.84 1687.66 ;
     RECT  1742.64 1658.76 1742.78 1687.66 ;
     RECT  1773.46 1649.58 1773.6 1687.66 ;
     RECT  1808.42 1671 1812.24 1687.66 ;
     RECT  1875.12 1647.2 1875.26 1687.66 ;
     RECT  1908.24 1646.38 1908.38 1687.66 ;
     RECT  1935.84 1665.9 1935.98 1687.66 ;
     RECT  1973.56 1647.2 1973.7 1687.66 ;
     RECT  1989.11 1646.86 1994.4 1687.66 ;
     RECT  2035.2 1665.56 2035.34 1687.66 ;
     RECT  2073.84 1658.42 2073.98 1687.66 ;
     RECT  2123.06 1647.2 2123.2 1687.66 ;
     RECT  2140.08 1647.2 2140.22 1687.66 ;
     RECT  2159.86 1647.2 2171.93 1687.66 ;
     RECT  2206.32 1646.86 2206.46 1687.66 ;
     RECT  2229.78 1646.38 2229.92 1687.66 ;
     RECT  2273.94 1647.2 2274.08 1687.66 ;
     RECT  2305.68 1647.2 2305.82 1687.66 ;
     RECT  2328.68 1654.85 2328.82 1687.66 ;
     RECT  2370.54 1686.585 2372.06 1687.66 ;
     RECT  2394.46 1645.02 2394.6 1687.66 ;
     RECT  2438.16 1670.66 2438.3 1687.66 ;
     RECT  2470.82 1660.29 2470.96 1687.66 ;
     RECT  2505.78 1646.38 2505.92 1687.66 ;
     RECT  2570.64 1616.26 2570.78 1687.66 ;
     RECT  2602.38 1685.62 2603.9 1687.66 ;
     RECT  2618.48 1655.02 2618.62 1687.66 ;
     RECT  2670 1640.6 2670.14 1687.66 ;
     RECT  2769.36 1667.94 2769.5 1687.66 ;
     RECT  2802.48 1651.99 2802.62 1687.66 ;
     RECT  2868.72 1680.04 2868.86 1687.66 ;
     RECT  2889.11 1686.585 2901.06 1687.66 ;
     RECT  517.2 1685.48 524.7 1688 ;
     RECT  616.56 1685.82 621.3 1688 ;
     RECT  747.66 1686.585 751.94 1688 ;
     RECT  947.76 1685.82 952.04 1688 ;
     RECT  1190.18 1632.58 1190.32 1688 ;
     RECT  189.11 1687.66 191.93 1688.54 ;
     RECT  549.11 1685.62 551.93 1688.54 ;
     RECT  909.11 1617.28 911.93 1688.54 ;
     RECT  1447.32 1685.48 1451.93 1688.54 ;
     RECT  1808.42 1687.66 1811.93 1688.54 ;
     RECT  2169.11 1687.66 2171.93 1688.54 ;
     RECT  2529.11 1663.86 2533.52 1688.54 ;
     RECT  2703.12 1646.38 2711.93 1688.54 ;
     RECT  9.11 1687.66 19.16 1689.305 ;
     RECT  184.62 1688.54 191.93 1689.305 ;
     RECT  369.11 1636.66 371.93 1689.305 ;
     RECT  548.48 1688.54 551.93 1689.305 ;
     RECT  729.11 1685.96 731.93 1689.305 ;
     RECT  909.11 1688.54 913.4 1689.305 ;
     RECT  1089.11 1687.66 1091.93 1689.305 ;
     RECT  1269.11 1687.66 1277.72 1689.305 ;
     RECT  1443.18 1688.54 1451.93 1689.305 ;
     RECT  1629.11 1659.78 1631.93 1689.305 ;
     RECT  1807.5 1688.54 1811.93 1689.305 ;
     RECT  1989.11 1687.66 1991.93 1689.305 ;
     RECT  2169.11 1688.54 2172.42 1689.305 ;
     RECT  2349.11 1638.7 2351.93 1689.305 ;
     RECT  2529.11 1688.54 2536.28 1689.305 ;
     RECT  2701.74 1688.54 2711.93 1689.305 ;
     RECT  2889.11 1687.66 2900.6 1689.305 ;
     RECT  548.48 1689.305 549.08 1690.21 ;
     RECT  2171.82 1689.305 2172.42 1691.57 ;
     RECT 19.020 1689.305 19.160 1696.000 ;
     RECT 52.140 1688.540 52.280 1696.000 ;
     RECT 85.260 1688.540 85.400 1696.000 ;
     RECT 118.380 1688.540 118.520 1696.000 ;
     RECT 151.500 1688.540 151.640 1696.000 ;
     RECT 184.620 1689.305 184.760 1696.000 ;
     RECT 217.740 1687.660 217.880 1696.000 ;
     RECT 250.860 1688.540 251.000 1696.000 ;
     RECT 283.980 1688.540 284.120 1696.000 ;
     RECT 317.100 1688.540 317.240 1696.000 ;
     RECT 350.220 1688.540 350.360 1696.000 ;
     RECT 383.340 1688.540 383.480 1696.000 ;
     RECT 416.460 1688.540 416.600 1696.000 ;
     RECT 449.580 1688.540 449.720 1696.000 ;
     RECT 482.700 1688.540 482.840 1696.000 ;
     RECT 515.820 1688.540 515.960 1696.000 ;
     RECT 548.940 1690.210 549.080 1696.000 ;
     RECT 582.060 1688.540 582.200 1696.000 ;
     RECT 615.180 1688.540 615.320 1696.000 ;
     RECT 648.300 1688.540 648.440 1696.000 ;
     RECT 681.420 1688.540 681.560 1696.000 ;
     RECT 714.540 1688.540 714.680 1696.000 ;
     RECT 747.660 1688.000 747.800 1696.000 ;
     RECT 780.780 1688.540 780.920 1696.000 ;
     RECT 813.900 1688.540 814.040 1696.000 ;
     RECT 847.020 1688.540 847.160 1696.000 ;
     RECT 880.140 1688.540 880.280 1696.000 ;
     RECT 913.260 1689.305 913.400 1696.000 ;
     RECT 946.380 1688.540 946.520 1696.000 ;
     RECT 979.500 1688.540 979.640 1696.000 ;
     RECT 1012.620 1688.540 1012.760 1696.000 ;
     RECT 1045.740 1688.540 1045.880 1696.000 ;
     RECT 1078.860 1688.540 1079.000 1696.000 ;
     RECT 1111.980 1687.660 1112.120 1696.000 ;
     RECT 1145.100 1688.540 1145.240 1696.000 ;
     RECT 1178.220 1688.540 1178.360 1696.000 ;
     RECT 1211.340 1688.540 1211.480 1696.000 ;
     RECT 1244.460 1688.540 1244.600 1696.000 ;
     RECT 1277.580 1689.305 1277.720 1696.000 ;
     RECT 1310.700 1688.540 1310.840 1696.000 ;
     RECT 1343.820 1688.540 1343.960 1696.000 ;
     RECT 1376.940 1688.540 1377.080 1696.000 ;
     RECT 1410.060 1688.540 1410.200 1696.000 ;
     RECT 1443.180 1689.305 1443.320 1696.000 ;
     RECT 1476.300 1688.540 1476.440 1696.000 ;
     RECT 1509.420 1688.540 1509.560 1696.000 ;
     RECT 1542.540 1688.540 1542.680 1696.000 ;
     RECT 1575.660 1688.540 1575.800 1696.000 ;
     RECT 1608.780 1688.540 1608.920 1696.000 ;
     RECT 1641.900 1688.540 1642.040 1696.000 ;
     RECT 1675.020 1688.540 1675.160 1696.000 ;
     RECT 1708.140 1688.540 1708.280 1696.000 ;
     RECT 1741.260 1688.540 1741.400 1696.000 ;
     RECT 1774.380 1688.540 1774.520 1696.000 ;
     RECT 1807.500 1689.305 1807.640 1696.000 ;
     RECT 1840.620 1688.540 1840.760 1696.000 ;
     RECT 1873.740 1688.540 1873.880 1696.000 ;
     RECT 1906.860 1688.540 1907.000 1696.000 ;
     RECT 1939.980 1688.540 1940.120 1696.000 ;
     RECT 1973.100 1688.540 1973.240 1696.000 ;
     RECT 2006.220 1686.585 2006.360 1696.000 ;
     RECT 2039.340 1688.540 2039.480 1696.000 ;
     RECT 2072.460 1688.540 2072.600 1696.000 ;
     RECT 2105.580 1688.540 2105.720 1696.000 ;
     RECT 2138.700 1688.540 2138.840 1696.000 ;
     RECT 2171.820 1691.570 2171.960 1696.000 ;
     RECT 2204.940 1688.540 2205.080 1696.000 ;
     RECT 2238.060 1688.540 2238.200 1696.000 ;
     RECT 2271.180 1688.540 2271.320 1696.000 ;
     RECT 2304.300 1688.540 2304.440 1696.000 ;
     RECT 2337.420 1688.540 2337.560 1696.000 ;
     RECT 2370.540 1687.660 2370.680 1696.000 ;
     RECT 2403.660 1688.540 2403.800 1696.000 ;
     RECT 2436.780 1688.540 2436.920 1696.000 ;
     RECT 2469.900 1688.540 2470.040 1696.000 ;
     RECT 2503.020 1688.540 2503.160 1696.000 ;
     RECT 2536.140 1689.305 2536.280 1696.000 ;
     RECT 2569.260 1688.540 2569.400 1696.000 ;
     RECT 2602.380 1687.660 2602.520 1696.000 ;
     RECT 2635.500 1688.540 2635.640 1696.000 ;
     RECT 2668.620 1688.540 2668.760 1696.000 ;
     RECT 2701.740 1689.305 2701.880 1696.000 ;
     RECT 2734.860 1687.860 2735.000 1696.000 ;
     RECT 2767.980 1688.540 2768.120 1696.000 ;
     RECT 2801.100 1688.540 2801.240 1696.000 ;
     RECT 2834.220 1688.540 2834.360 1696.000 ;
     RECT 2867.340 1688.540 2867.480 1696.000 ;
     RECT 2900.460 1689.305 2900.600 1696.000 ;
    LAYER met3 ;
     RECT  1.46 160.67 1.92 160.97 ;
     RECT 1.920 153.870 2.380 159.160 ;
     RECT 1.920 159.760 2.380 160.970 ;
     RECT  1.92 1013.39 2.84 1013.69 ;
     RECT 2.380 153.870 3.220 159.160 ;
     RECT 2.380 159.760 3.220 165.960 ;
     RECT 2.380 166.560 3.220 172.760 ;
     RECT 2.380 173.360 3.220 174.570 ;
     RECT  2.84 201.47 3.22 201.77 ;
     RECT  0.54 280.35 3.22 280.65 ;
     RECT  1 364.67 3.22 364.97 ;
     RECT 2.840 1007.950 3.220 1009.160 ;
     RECT 2.840 1009.760 3.220 1013.690 ;
     RECT 3.220 139.360 3.990 145.560 ;
     RECT 3.220 146.160 3.990 152.360 ;
     RECT 3.220 152.960 3.990 159.160 ;
     RECT 3.220 159.760 3.990 165.960 ;
     RECT 3.220 166.560 3.990 172.760 ;
     RECT 3.220 173.360 3.990 179.560 ;
     RECT 3.220 180.160 3.990 186.360 ;
     RECT 3.220 186.960 3.990 193.160 ;
     RECT 3.220 193.760 3.990 199.960 ;
     RECT 3.220 200.560 3.990 206.760 ;
     RECT 3.220 207.360 3.990 213.560 ;
     RECT 3.220 214.160 3.990 220.360 ;
     RECT 3.220 220.960 3.990 227.160 ;
     RECT 3.220 227.760 3.990 233.960 ;
     RECT 3.220 234.560 3.990 240.760 ;
     RECT 3.220 241.360 3.990 247.560 ;
     RECT 3.220 248.160 3.990 254.360 ;
     RECT 3.220 254.960 3.990 261.160 ;
     RECT 3.220 261.760 3.990 267.960 ;
     RECT 3.220 268.560 3.990 274.760 ;
     RECT 3.220 275.360 3.990 281.560 ;
     RECT 3.220 282.160 3.990 288.360 ;
     RECT 3.220 288.960 3.990 295.160 ;
     RECT 3.220 295.760 3.990 301.960 ;
     RECT 3.220 302.560 3.990 308.760 ;
     RECT 3.220 309.360 3.990 315.560 ;
     RECT 3.220 316.160 3.990 322.360 ;
     RECT 3.220 322.960 3.990 329.160 ;
     RECT 3.220 329.760 3.990 335.960 ;
     RECT 3.220 336.560 3.990 342.760 ;
     RECT 3.220 343.360 3.990 349.560 ;
     RECT 3.220 350.160 3.990 356.360 ;
     RECT 3.220 356.960 3.990 363.160 ;
     RECT 3.220 363.760 3.990 369.960 ;
     RECT 3.220 370.560 3.990 376.760 ;
     RECT 3.220 377.360 3.990 383.560 ;
     RECT 3.220 384.160 3.990 390.360 ;
     RECT 3.220 390.960 3.990 397.160 ;
     RECT 3.220 397.760 3.990 403.960 ;
     RECT 3.220 404.560 3.990 410.760 ;
     RECT 3.220 411.360 3.990 417.560 ;
     RECT 3.220 418.160 3.990 424.360 ;
     RECT 3.220 424.960 3.990 431.160 ;
     RECT 3.220 431.760 3.990 437.960 ;
     RECT 3.220 438.560 3.990 444.760 ;
     RECT 3.220 445.360 3.990 451.560 ;
     RECT 3.220 452.160 3.990 458.360 ;
     RECT 3.220 458.960 3.990 465.160 ;
     RECT 3.220 465.760 3.990 471.960 ;
     RECT 3.220 472.560 3.990 478.760 ;
     RECT 3.220 479.360 3.990 485.560 ;
     RECT 3.220 486.160 3.990 492.360 ;
     RECT 3.220 492.960 3.990 499.160 ;
     RECT 3.220 499.760 3.990 505.960 ;
     RECT 3.220 506.560 3.990 512.760 ;
     RECT 3.220 513.360 3.990 519.560 ;
     RECT 3.220 520.160 3.990 526.360 ;
     RECT 3.220 526.960 3.990 533.160 ;
     RECT 3.220 533.760 3.990 539.960 ;
     RECT 3.220 540.560 3.990 546.760 ;
     RECT 3.220 547.360 3.990 553.560 ;
     RECT 3.220 554.160 3.990 560.360 ;
     RECT 3.220 560.960 3.990 567.160 ;
     RECT 3.220 567.760 3.990 573.960 ;
     RECT 3.220 574.560 3.990 580.760 ;
     RECT 3.220 581.360 3.990 587.560 ;
     RECT 3.220 588.160 3.990 594.360 ;
     RECT 3.220 594.960 3.990 601.160 ;
     RECT 3.220 601.760 3.990 607.960 ;
     RECT 3.220 608.560 3.990 614.760 ;
     RECT 3.220 615.360 3.990 621.560 ;
     RECT 3.220 622.160 3.990 628.360 ;
     RECT 3.220 628.960 3.990 635.160 ;
     RECT 3.220 635.760 3.990 641.960 ;
     RECT 3.220 642.560 3.990 648.760 ;
     RECT 3.220 649.360 3.990 655.560 ;
     RECT 3.220 656.160 3.990 662.360 ;
     RECT 3.220 662.960 3.990 669.160 ;
     RECT 3.220 669.760 3.990 675.960 ;
     RECT 3.220 676.560 3.990 682.760 ;
     RECT 3.220 683.360 3.990 689.560 ;
     RECT 3.220 690.160 3.990 696.360 ;
     RECT 3.220 696.960 3.990 703.160 ;
     RECT 3.220 703.760 3.990 709.960 ;
     RECT 3.220 710.560 3.990 716.760 ;
     RECT 3.220 717.360 3.990 723.560 ;
     RECT 3.220 724.160 3.990 730.360 ;
     RECT 3.220 730.960 3.990 737.160 ;
     RECT 3.220 737.760 3.990 743.960 ;
     RECT 3.220 744.560 3.990 750.760 ;
     RECT 3.220 751.360 3.990 757.560 ;
     RECT 3.220 758.160 3.990 764.360 ;
     RECT 3.220 764.960 3.990 771.160 ;
     RECT 3.220 771.760 3.990 777.960 ;
     RECT 3.220 778.560 3.990 784.760 ;
     RECT 3.220 785.360 3.990 791.560 ;
     RECT 3.220 792.160 3.990 798.360 ;
     RECT 3.220 798.960 3.990 805.160 ;
     RECT 3.220 805.760 3.990 811.960 ;
     RECT 3.220 812.560 3.990 818.760 ;
     RECT 3.220 819.360 3.990 825.560 ;
     RECT 3.220 826.160 3.990 832.360 ;
     RECT 3.220 832.960 3.990 839.160 ;
     RECT 3.220 839.760 3.990 845.960 ;
     RECT 3.220 846.560 3.990 852.760 ;
     RECT 3.220 853.360 3.990 859.560 ;
     RECT 3.220 860.160 3.990 866.360 ;
     RECT 3.220 866.960 3.990 873.160 ;
     RECT 3.220 873.760 3.990 879.960 ;
     RECT 3.220 880.560 3.990 886.760 ;
     RECT 3.220 887.360 3.990 893.560 ;
     RECT 3.220 894.160 3.990 900.360 ;
     RECT 3.220 900.960 3.990 907.160 ;
     RECT 3.220 907.760 3.990 913.960 ;
     RECT 3.220 914.560 3.990 920.760 ;
     RECT 3.220 921.360 3.990 927.560 ;
     RECT 3.220 928.160 3.990 934.360 ;
     RECT 3.220 934.960 3.990 941.160 ;
     RECT 3.220 941.760 3.990 947.960 ;
     RECT 3.220 948.560 3.990 954.760 ;
     RECT 3.220 955.360 3.990 961.560 ;
     RECT 3.220 962.160 3.990 968.360 ;
     RECT 3.220 968.960 3.990 975.160 ;
     RECT 3.220 975.760 3.990 981.960 ;
     RECT 3.220 982.560 3.990 988.760 ;
     RECT 3.220 989.360 3.990 995.560 ;
     RECT 3.220 996.160 3.990 1002.360 ;
     RECT 3.220 1002.960 3.990 1009.160 ;
     RECT 3.220 1009.760 3.990 1015.960 ;
     RECT 3.220 1016.560 3.990 1022.760 ;
     RECT 3.220 1023.360 3.990 1029.560 ;
     RECT 3.220 1030.160 3.990 1036.360 ;
     RECT 3.220 1036.960 3.990 1043.160 ;
     RECT 3.220 1043.760 3.990 1049.960 ;
     RECT 3.220 1050.560 3.990 1056.760 ;
     RECT 3.220 1057.360 3.990 1063.560 ;
     RECT 3.220 1064.160 3.990 1070.360 ;
     RECT 3.220 1070.960 3.990 1077.160 ;
     RECT 3.220 1077.760 3.990 1083.960 ;
     RECT 3.220 1084.560 3.990 1090.760 ;
     RECT 3.220 1091.360 3.990 1097.560 ;
     RECT 3.220 1098.160 3.990 1104.360 ;
     RECT 3.220 1104.960 3.990 1111.160 ;
     RECT 3.220 1111.760 3.990 1117.960 ;
     RECT 3.220 1118.560 3.990 1124.760 ;
     RECT 3.220 1125.360 3.990 1131.560 ;
     RECT 3.220 1132.160 3.990 1138.360 ;
     RECT 3.220 1138.960 3.990 1145.160 ;
     RECT 3.220 1145.760 3.990 1151.960 ;
     RECT 3.220 1152.560 3.990 1158.760 ;
     RECT 3.220 1159.360 3.990 1165.560 ;
     RECT 3.220 1166.160 3.990 1172.360 ;
     RECT 3.220 1172.960 3.990 1179.160 ;
     RECT 3.220 1179.760 3.990 1185.960 ;
     RECT 3.220 1186.560 3.990 1192.760 ;
     RECT 3.220 1193.360 3.990 1199.560 ;
     RECT 3.220 1200.160 3.990 1206.360 ;
     RECT 3.220 1206.960 3.990 1213.160 ;
     RECT 3.220 1213.760 3.990 1219.960 ;
     RECT 3.220 1220.560 3.990 1226.760 ;
     RECT 3.220 1227.360 3.990 1233.560 ;
     RECT 3.220 1234.160 3.990 1240.360 ;
     RECT 3.220 1240.960 3.990 1247.160 ;
     RECT 3.220 1247.760 3.990 1253.960 ;
     RECT 3.220 1254.560 3.990 1260.760 ;
     RECT 3.220 1261.360 3.990 1267.560 ;
     RECT 3.220 1268.160 3.990 1274.360 ;
     RECT 3.220 1274.960 3.990 1281.160 ;
     RECT 3.220 1281.760 3.990 1287.960 ;
     RECT 3.220 1288.560 3.990 1294.760 ;
     RECT 3.220 1295.360 3.990 1301.560 ;
     RECT 3.220 1302.160 3.990 1308.360 ;
     RECT 3.220 1308.960 3.990 1315.160 ;
     RECT 3.220 1315.760 3.990 1321.960 ;
     RECT 3.220 1322.560 3.990 1328.760 ;
     RECT 3.220 1329.360 3.990 1335.560 ;
     RECT 3.220 1336.160 3.990 1342.360 ;
     RECT 3.220 1342.960 3.990 1349.160 ;
     RECT 3.220 1349.760 3.990 1355.960 ;
     RECT 3.220 1356.560 3.990 1362.760 ;
     RECT 3.220 1363.360 3.990 1369.560 ;
     RECT 3.220 1370.160 3.990 1376.360 ;
     RECT 3.220 1376.960 3.990 1383.160 ;
     RECT 3.220 1383.760 3.990 1389.960 ;
     RECT 3.220 1390.560 3.990 1396.760 ;
     RECT 3.220 1397.360 3.990 1403.560 ;
     RECT 3.220 1404.160 3.990 1410.360 ;
     RECT 3.220 1410.960 3.990 1417.160 ;
     RECT 3.220 1417.760 3.990 1423.960 ;
     RECT 3.220 1424.560 3.990 1430.760 ;
     RECT 3.220 1431.360 3.990 1437.560 ;
     RECT 3.220 1438.160 3.990 1444.360 ;
     RECT 3.220 1444.960 3.990 1451.160 ;
     RECT 3.220 1451.760 3.990 1457.960 ;
     RECT 3.220 1458.560 3.990 1464.760 ;
     RECT 3.220 1465.360 3.990 1471.560 ;
     RECT 3.220 1472.160 3.990 1478.360 ;
     RECT 3.220 1478.960 3.990 1485.160 ;
     RECT 3.220 1485.760 3.990 1491.960 ;
     RECT 3.220 1492.560 3.990 1498.760 ;
     RECT 3.220 1499.360 3.990 1505.560 ;
     RECT 3.220 1506.160 3.990 1512.360 ;
     RECT 3.220 1512.960 3.990 1519.160 ;
     RECT 3.220 1519.760 3.990 1525.960 ;
     RECT 3.220 1526.560 3.990 1532.760 ;
     RECT 3.220 1533.360 3.990 1539.560 ;
     RECT 3.220 1540.160 3.990 1546.360 ;
     RECT 3.220 1546.960 3.990 1553.160 ;
     RECT 3.220 1553.760 3.990 1559.960 ;
     RECT 3.990 139.360 9.130 145.560 ;
     RECT 3.990 146.160 9.130 152.360 ;
     RECT 4.000 145.560 9.130 146.160 ;
     RECT 4.000 138.910 9.130 139.360 ;
     RECT 3.990 152.960 9.130 159.160 ;
     RECT 3.990 159.760 9.130 165.960 ;
     RECT 3.990 166.560 9.130 172.760 ;
     RECT 3.990 173.360 9.130 179.560 ;
     RECT 3.990 180.160 9.130 186.360 ;
     RECT 3.990 186.960 9.130 193.160 ;
     RECT 3.990 193.760 9.130 199.960 ;
     RECT 3.990 200.560 9.130 206.760 ;
     RECT 3.990 207.360 9.130 213.560 ;
     RECT 3.990 214.160 9.130 220.360 ;
     RECT 4.000 213.560 9.130 214.160 ;
     RECT 4.000 206.760 9.130 207.360 ;
     RECT 4.000 199.960 9.130 200.560 ;
     RECT 4.000 193.160 9.130 193.760 ;
     RECT 4.000 186.360 9.130 186.960 ;
     RECT 4.000 179.560 9.130 180.160 ;
     RECT 4.000 172.760 9.130 173.360 ;
     RECT 4.000 165.960 9.130 166.560 ;
     RECT 4.000 159.160 9.130 159.760 ;
     RECT 3.990 220.960 9.130 227.160 ;
     RECT 3.990 227.760 9.130 233.960 ;
     RECT 3.990 234.560 9.130 240.760 ;
     RECT 3.990 241.360 9.130 247.560 ;
     RECT 3.990 248.160 9.130 254.360 ;
     RECT 3.990 254.960 9.130 261.160 ;
     RECT 3.990 261.760 9.130 267.960 ;
     RECT 3.990 268.560 9.130 274.760 ;
     RECT 3.990 275.360 9.130 281.560 ;
     RECT 3.990 282.160 9.130 288.360 ;
     RECT 3.990 288.960 9.130 295.160 ;
     RECT 3.990 295.760 9.130 301.960 ;
     RECT 3.990 302.560 9.130 308.760 ;
     RECT 3.990 309.360 9.130 315.560 ;
     RECT 3.990 316.160 9.130 322.360 ;
     RECT 3.990 322.960 9.130 329.160 ;
     RECT 3.990 329.760 9.130 335.960 ;
     RECT 3.990 336.560 9.130 342.760 ;
     RECT 3.990 343.360 9.130 349.560 ;
     RECT 3.990 350.160 9.130 356.360 ;
     RECT 3.990 356.960 9.130 363.160 ;
     RECT 3.990 363.760 9.130 369.960 ;
     RECT 4.000 363.160 9.130 363.760 ;
     RECT 4.000 356.360 9.130 356.960 ;
     RECT 4.000 349.560 9.130 350.160 ;
     RECT 4.000 342.760 9.130 343.360 ;
     RECT 4.000 335.960 9.130 336.560 ;
     RECT 4.000 329.160 9.130 329.760 ;
     RECT 4.000 322.360 9.130 322.960 ;
     RECT 4.000 315.560 9.130 316.160 ;
     RECT 4.000 308.760 9.130 309.360 ;
     RECT 4.000 301.960 9.130 302.560 ;
     RECT 4.000 295.160 9.130 295.760 ;
     RECT 4.000 288.360 9.130 288.960 ;
     RECT 4.000 281.560 9.130 282.160 ;
     RECT 4.000 274.760 9.130 275.360 ;
     RECT 4.000 267.960 9.130 268.560 ;
     RECT 4.000 261.160 9.130 261.760 ;
     RECT 4.000 254.360 9.130 254.960 ;
     RECT 4.000 247.560 9.130 248.160 ;
     RECT 4.000 240.760 9.130 241.360 ;
     RECT 4.000 233.960 9.130 234.560 ;
     RECT 4.000 227.160 9.130 227.760 ;
     RECT 4.000 220.360 9.130 220.960 ;
     RECT 4.000 152.360 9.130 152.960 ;
     RECT 3.990 370.560 9.130 376.760 ;
     RECT 3.990 377.360 9.130 383.560 ;
     RECT 3.990 384.160 9.130 390.360 ;
     RECT 3.990 390.960 9.130 397.160 ;
     RECT 3.990 397.760 9.130 403.960 ;
     RECT 3.990 404.560 9.130 410.760 ;
     RECT 3.990 411.360 9.130 417.560 ;
     RECT 3.990 418.160 9.130 424.360 ;
     RECT 3.990 424.960 9.130 431.160 ;
     RECT 3.990 431.760 9.130 437.960 ;
     RECT 4.000 431.160 9.130 431.760 ;
     RECT 4.000 424.360 9.130 424.960 ;
     RECT 4.000 417.560 9.130 418.160 ;
     RECT 4.000 410.760 9.130 411.360 ;
     RECT 4.000 403.960 9.130 404.560 ;
     RECT 4.000 397.160 9.130 397.760 ;
     RECT 4.000 390.360 9.130 390.960 ;
     RECT 4.000 383.560 9.130 384.160 ;
     RECT 4.000 376.760 9.130 377.360 ;
     RECT 3.990 438.560 9.130 444.760 ;
     RECT 3.990 445.360 9.130 451.560 ;
     RECT 3.990 452.160 9.130 458.360 ;
     RECT 3.990 458.960 9.130 465.160 ;
     RECT 3.990 465.760 9.130 471.960 ;
     RECT 3.990 472.560 9.130 478.760 ;
     RECT 3.990 479.360 9.130 485.560 ;
     RECT 3.990 486.160 9.130 492.360 ;
     RECT 3.990 492.960 9.130 499.160 ;
     RECT 3.990 499.760 9.130 505.960 ;
     RECT 3.990 506.560 9.130 512.760 ;
     RECT 3.990 513.360 9.130 519.560 ;
     RECT 3.990 520.160 9.130 526.360 ;
     RECT 3.990 526.960 9.130 533.160 ;
     RECT 3.990 533.760 9.130 539.960 ;
     RECT 3.990 540.560 9.130 546.760 ;
     RECT 3.990 547.360 9.130 553.560 ;
     RECT 3.990 554.160 9.130 560.360 ;
     RECT 3.990 560.960 9.130 567.160 ;
     RECT 3.990 567.760 9.130 573.960 ;
     RECT 3.990 574.560 9.130 580.760 ;
     RECT 3.990 581.360 9.130 587.560 ;
     RECT 3.990 588.160 9.130 594.360 ;
     RECT 3.990 594.960 9.130 601.160 ;
     RECT 3.990 601.760 9.130 607.960 ;
     RECT 3.990 608.560 9.130 614.760 ;
     RECT 3.990 615.360 9.130 621.560 ;
     RECT 3.990 622.160 9.130 628.360 ;
     RECT 3.990 628.960 9.130 635.160 ;
     RECT 3.990 635.760 9.130 641.960 ;
     RECT 3.990 642.560 9.130 648.760 ;
     RECT 3.990 649.360 9.130 655.560 ;
     RECT 3.990 656.160 9.130 662.360 ;
     RECT 3.990 662.960 9.130 669.160 ;
     RECT 3.990 669.760 9.130 675.960 ;
     RECT 3.990 676.560 9.130 682.760 ;
     RECT 3.990 683.360 9.130 689.560 ;
     RECT 3.990 690.160 9.130 696.360 ;
     RECT 3.990 696.960 9.130 703.160 ;
     RECT 3.990 703.760 9.130 709.960 ;
     RECT 3.990 710.560 9.130 716.760 ;
     RECT 3.990 717.360 9.130 723.560 ;
     RECT 3.990 724.160 9.130 730.360 ;
     RECT 3.990 730.960 9.130 737.160 ;
     RECT 4.000 730.360 9.130 730.960 ;
     RECT 4.000 723.560 9.130 724.160 ;
     RECT 4.000 716.760 9.130 717.360 ;
     RECT 4.000 709.960 9.130 710.560 ;
     RECT 4.000 703.160 9.130 703.760 ;
     RECT 4.000 696.360 9.130 696.960 ;
     RECT 4.000 689.560 9.130 690.160 ;
     RECT 4.000 682.760 9.130 683.360 ;
     RECT 4.000 675.960 9.130 676.560 ;
     RECT 3.990 737.760 9.130 743.960 ;
     RECT 3.990 744.560 9.130 750.760 ;
     RECT 3.990 751.360 9.130 757.560 ;
     RECT 3.990 758.160 9.130 764.360 ;
     RECT 3.990 764.960 9.130 771.160 ;
     RECT 3.990 771.760 9.130 777.960 ;
     RECT 3.990 778.560 9.130 784.760 ;
     RECT 3.990 785.360 9.130 791.560 ;
     RECT 3.990 792.160 9.130 798.360 ;
     RECT 3.990 798.960 9.130 805.160 ;
     RECT 3.990 805.760 9.130 811.960 ;
     RECT 3.990 812.560 9.130 818.760 ;
     RECT 3.990 819.360 9.130 825.560 ;
     RECT 3.990 826.160 9.130 832.360 ;
     RECT 3.990 832.960 9.130 839.160 ;
     RECT 3.990 839.760 9.130 845.960 ;
     RECT 3.990 846.560 9.130 852.760 ;
     RECT 3.990 853.360 9.130 859.560 ;
     RECT 3.990 860.160 9.130 866.360 ;
     RECT 3.990 866.960 9.130 873.160 ;
     RECT 3.990 873.760 9.130 879.960 ;
     RECT 3.990 880.560 9.130 886.760 ;
     RECT 3.990 887.360 9.130 893.560 ;
     RECT 3.990 894.160 9.130 900.360 ;
     RECT 3.990 900.960 9.130 907.160 ;
     RECT 3.990 907.760 9.130 913.960 ;
     RECT 3.990 914.560 9.130 920.760 ;
     RECT 3.990 921.360 9.130 927.560 ;
     RECT 3.990 928.160 9.130 934.360 ;
     RECT 3.990 934.960 9.130 941.160 ;
     RECT 3.990 941.760 9.130 947.960 ;
     RECT 3.990 948.560 9.130 954.760 ;
     RECT 3.990 955.360 9.130 961.560 ;
     RECT 3.990 962.160 9.130 968.360 ;
     RECT 4.000 961.560 9.130 962.160 ;
     RECT 4.000 954.760 9.130 955.360 ;
     RECT 4.000 947.960 9.130 948.560 ;
     RECT 4.000 941.160 9.130 941.760 ;
     RECT 4.000 934.360 9.130 934.960 ;
     RECT 4.000 927.560 9.130 928.160 ;
     RECT 4.000 920.760 9.130 921.360 ;
     RECT 4.000 913.960 9.130 914.560 ;
     RECT 4.000 907.160 9.130 907.760 ;
     RECT 4.000 900.360 9.130 900.960 ;
     RECT 4.000 893.560 9.130 894.160 ;
     RECT 4.000 886.760 9.130 887.360 ;
     RECT 4.000 879.960 9.130 880.560 ;
     RECT 4.000 873.160 9.130 873.760 ;
     RECT 4.000 866.360 9.130 866.960 ;
     RECT 4.000 859.560 9.130 860.160 ;
     RECT 4.000 852.760 9.130 853.360 ;
     RECT 4.000 845.960 9.130 846.560 ;
     RECT 4.000 839.160 9.130 839.760 ;
     RECT 4.000 832.360 9.130 832.960 ;
     RECT 4.000 825.560 9.130 826.160 ;
     RECT 4.000 818.760 9.130 819.360 ;
     RECT 4.000 811.960 9.130 812.560 ;
     RECT 4.000 805.160 9.130 805.760 ;
     RECT 4.000 798.360 9.130 798.960 ;
     RECT 4.000 791.560 9.130 792.160 ;
     RECT 4.000 784.760 9.130 785.360 ;
     RECT 4.000 777.960 9.130 778.560 ;
     RECT 4.000 771.160 9.130 771.760 ;
     RECT 4.000 764.360 9.130 764.960 ;
     RECT 4.000 757.560 9.130 758.160 ;
     RECT 4.000 750.760 9.130 751.360 ;
     RECT 4.000 743.960 9.130 744.560 ;
     RECT 4.000 737.160 9.130 737.760 ;
     RECT 4.000 669.160 9.130 669.760 ;
     RECT 3.990 968.960 9.130 975.160 ;
     RECT 3.990 975.760 9.130 981.960 ;
     RECT 3.990 982.560 9.130 988.760 ;
     RECT 3.990 989.360 9.130 995.560 ;
     RECT 3.990 996.160 9.130 1002.360 ;
     RECT 3.990 1002.960 9.130 1009.160 ;
     RECT 3.990 1009.760 9.130 1015.960 ;
     RECT 3.990 1016.560 9.130 1022.760 ;
     RECT 3.990 1023.360 9.130 1029.560 ;
     RECT 3.990 1030.160 9.130 1036.360 ;
     RECT 4.000 1029.560 9.130 1030.160 ;
     RECT 4.000 1022.760 9.130 1023.360 ;
     RECT 4.000 1015.960 9.130 1016.560 ;
     RECT 4.000 1009.160 9.130 1009.760 ;
     RECT 4.000 1002.360 9.130 1002.960 ;
     RECT 4.000 995.560 9.130 996.160 ;
     RECT 4.000 988.760 9.130 989.360 ;
     RECT 4.000 981.960 9.130 982.560 ;
     RECT 4.000 975.160 9.130 975.760 ;
     RECT 3.990 1036.960 9.130 1043.160 ;
     RECT 3.990 1043.760 9.130 1049.960 ;
     RECT 3.990 1050.560 9.130 1056.760 ;
     RECT 3.990 1057.360 9.130 1063.560 ;
     RECT 3.990 1064.160 9.130 1070.360 ;
     RECT 3.990 1070.960 9.130 1077.160 ;
     RECT 3.990 1077.760 9.130 1083.960 ;
     RECT 3.990 1084.560 9.130 1090.760 ;
     RECT 3.990 1091.360 9.130 1097.560 ;
     RECT 3.990 1098.160 9.130 1104.360 ;
     RECT 3.990 1104.960 9.130 1111.160 ;
     RECT 3.990 1111.760 9.130 1117.960 ;
     RECT 3.990 1118.560 9.130 1124.760 ;
     RECT 3.990 1125.360 9.130 1131.560 ;
     RECT 3.990 1132.160 9.130 1138.360 ;
     RECT 3.990 1138.960 9.130 1145.160 ;
     RECT 3.990 1145.760 9.130 1151.960 ;
     RECT 3.990 1152.560 9.130 1158.760 ;
     RECT 3.990 1159.360 9.130 1165.560 ;
     RECT 3.990 1166.160 9.130 1172.360 ;
     RECT 3.990 1172.960 9.130 1179.160 ;
     RECT 3.990 1179.760 9.130 1185.960 ;
     RECT 3.990 1186.560 9.130 1192.760 ;
     RECT 3.990 1193.360 9.130 1199.560 ;
     RECT 3.990 1200.160 9.130 1206.360 ;
     RECT 3.990 1206.960 9.130 1213.160 ;
     RECT 3.990 1213.760 9.130 1219.960 ;
     RECT 3.990 1220.560 9.130 1226.760 ;
     RECT 3.990 1227.360 9.130 1233.560 ;
     RECT 3.990 1234.160 9.130 1240.360 ;
     RECT 3.990 1240.960 9.130 1247.160 ;
     RECT 3.990 1247.760 9.130 1253.960 ;
     RECT 3.990 1254.560 9.130 1260.760 ;
     RECT 3.990 1261.360 9.130 1267.560 ;
     RECT 4.000 1260.760 9.130 1261.360 ;
     RECT 4.000 1253.960 9.130 1254.560 ;
     RECT 4.000 1247.160 9.130 1247.760 ;
     RECT 4.000 1240.360 9.130 1240.960 ;
     RECT 4.000 1233.560 9.130 1234.160 ;
     RECT 4.000 1226.760 9.130 1227.360 ;
     RECT 4.000 1219.960 9.130 1220.560 ;
     RECT 4.000 1213.160 9.130 1213.760 ;
     RECT 4.000 1206.360 9.130 1206.960 ;
     RECT 4.000 1199.560 9.130 1200.160 ;
     RECT 4.000 1192.760 9.130 1193.360 ;
     RECT 4.000 1185.960 9.130 1186.560 ;
     RECT 4.000 1179.160 9.130 1179.760 ;
     RECT 4.000 1172.360 9.130 1172.960 ;
     RECT 4.000 1165.560 9.130 1166.160 ;
     RECT 4.000 1158.760 9.130 1159.360 ;
     RECT 4.000 1151.960 9.130 1152.560 ;
     RECT 4.000 1145.160 9.130 1145.760 ;
     RECT 4.000 1138.360 9.130 1138.960 ;
     RECT 4.000 1131.560 9.130 1132.160 ;
     RECT 4.000 1124.760 9.130 1125.360 ;
     RECT 4.000 1117.960 9.130 1118.560 ;
     RECT 4.000 1111.160 9.130 1111.760 ;
     RECT 4.000 1104.360 9.130 1104.960 ;
     RECT 4.000 1097.560 9.130 1098.160 ;
     RECT 4.000 1090.760 9.130 1091.360 ;
     RECT 4.000 1083.960 9.130 1084.560 ;
     RECT 4.000 1077.160 9.130 1077.760 ;
     RECT 4.000 1070.360 9.130 1070.960 ;
     RECT 4.000 1063.560 9.130 1064.160 ;
     RECT 4.000 1056.760 9.130 1057.360 ;
     RECT 4.000 1049.960 9.130 1050.560 ;
     RECT 4.000 1043.160 9.130 1043.760 ;
     RECT 4.000 1036.360 9.130 1036.960 ;
     RECT 4.000 968.360 9.130 968.960 ;
     RECT 4.000 662.360 9.130 662.960 ;
     RECT 4.000 655.560 9.130 656.160 ;
     RECT 4.000 648.760 9.130 649.360 ;
     RECT 4.000 641.960 9.130 642.560 ;
     RECT 4.000 635.160 9.130 635.760 ;
     RECT 4.000 628.360 9.130 628.960 ;
     RECT 4.000 621.560 9.130 622.160 ;
     RECT 4.000 614.760 9.130 615.360 ;
     RECT 4.000 607.960 9.130 608.560 ;
     RECT 4.000 601.160 9.130 601.760 ;
     RECT 4.000 594.360 9.130 594.960 ;
     RECT 4.000 587.560 9.130 588.160 ;
     RECT 4.000 580.760 9.130 581.360 ;
     RECT 4.000 573.960 9.130 574.560 ;
     RECT 4.000 567.160 9.130 567.760 ;
     RECT 4.000 560.360 9.130 560.960 ;
     RECT 4.000 553.560 9.130 554.160 ;
     RECT 4.000 546.760 9.130 547.360 ;
     RECT 4.000 539.960 9.130 540.560 ;
     RECT 4.000 533.160 9.130 533.760 ;
     RECT 4.000 526.360 9.130 526.960 ;
     RECT 4.000 519.560 9.130 520.160 ;
     RECT 4.000 512.760 9.130 513.360 ;
     RECT 4.000 505.960 9.130 506.560 ;
     RECT 4.000 499.160 9.130 499.760 ;
     RECT 4.000 492.360 9.130 492.960 ;
     RECT 4.000 485.560 9.130 486.160 ;
     RECT 4.000 478.760 9.130 479.360 ;
     RECT 4.000 471.960 9.130 472.560 ;
     RECT 4.000 465.160 9.130 465.760 ;
     RECT 4.000 458.360 9.130 458.960 ;
     RECT 4.000 451.560 9.130 452.160 ;
     RECT 4.000 444.760 9.130 445.360 ;
     RECT 4.000 437.960 9.130 438.560 ;
     RECT 4.000 369.960 9.130 370.560 ;
     RECT 3.990 1268.160 9.130 1274.360 ;
     RECT 3.990 1274.960 9.130 1281.160 ;
     RECT 3.990 1281.760 9.130 1287.960 ;
     RECT 3.990 1288.560 9.130 1294.760 ;
     RECT 3.990 1295.360 9.130 1301.560 ;
     RECT 3.990 1302.160 9.130 1308.360 ;
     RECT 3.990 1308.960 9.130 1315.160 ;
     RECT 3.990 1315.760 9.130 1321.960 ;
     RECT 3.990 1322.560 9.130 1328.760 ;
     RECT 3.990 1329.360 9.130 1335.560 ;
     RECT 4.000 1328.760 9.130 1329.360 ;
     RECT 4.000 1321.960 9.130 1322.560 ;
     RECT 4.000 1315.160 9.130 1315.760 ;
     RECT 4.000 1308.360 9.130 1308.960 ;
     RECT 4.000 1301.560 9.130 1302.160 ;
     RECT 4.000 1294.760 9.130 1295.360 ;
     RECT 4.000 1287.960 9.130 1288.560 ;
     RECT 4.000 1281.160 9.130 1281.760 ;
     RECT 4.000 1274.360 9.130 1274.960 ;
     RECT 3.990 1336.160 9.130 1342.360 ;
     RECT 3.990 1342.960 9.130 1349.160 ;
     RECT 3.990 1349.760 9.130 1355.960 ;
     RECT 3.990 1356.560 9.130 1362.760 ;
     RECT 3.990 1363.360 9.130 1369.560 ;
     RECT 3.990 1370.160 9.130 1376.360 ;
     RECT 3.990 1376.960 9.130 1383.160 ;
     RECT 3.990 1383.760 9.130 1389.960 ;
     RECT 3.990 1390.560 9.130 1396.760 ;
     RECT 3.990 1397.360 9.130 1403.560 ;
     RECT 3.990 1404.160 9.130 1410.360 ;
     RECT 3.990 1410.960 9.130 1417.160 ;
     RECT 3.990 1417.760 9.130 1423.960 ;
     RECT 3.990 1424.560 9.130 1430.760 ;
     RECT 3.990 1431.360 9.130 1437.560 ;
     RECT 3.990 1438.160 9.130 1444.360 ;
     RECT 3.990 1444.960 9.130 1451.160 ;
     RECT 3.990 1451.760 9.130 1457.960 ;
     RECT 3.990 1458.560 9.130 1464.760 ;
     RECT 3.990 1465.360 9.130 1471.560 ;
     RECT 3.990 1472.160 9.130 1478.360 ;
     RECT 3.990 1478.960 9.130 1485.160 ;
     RECT 3.990 1485.760 9.130 1491.960 ;
     RECT 3.990 1492.560 9.130 1498.760 ;
     RECT 3.990 1499.360 9.130 1505.560 ;
     RECT 3.990 1506.160 9.130 1512.360 ;
     RECT 3.990 1512.960 9.130 1519.160 ;
     RECT 3.990 1519.760 9.130 1525.960 ;
     RECT 3.990 1526.560 9.130 1532.760 ;
     RECT 3.990 1533.360 9.130 1539.560 ;
     RECT 3.990 1540.160 9.130 1546.360 ;
     RECT 3.990 1546.960 9.130 1553.160 ;
     RECT 3.990 1553.760 9.130 1559.960 ;
     RECT 3.990 1560.560 9.130 1561.090 ;
     RECT 4.000 1559.960 9.130 1560.560 ;
     RECT 4.000 1553.160 9.130 1553.760 ;
     RECT 4.000 1546.360 9.130 1546.960 ;
     RECT 4.000 1539.560 9.130 1540.160 ;
     RECT 4.000 1532.760 9.130 1533.360 ;
     RECT 4.000 1525.960 9.130 1526.560 ;
     RECT 4.000 1519.160 9.130 1519.760 ;
     RECT 4.000 1512.360 9.130 1512.960 ;
     RECT 4.000 1505.560 9.130 1506.160 ;
     RECT 4.000 1498.760 9.130 1499.360 ;
     RECT 4.000 1491.960 9.130 1492.560 ;
     RECT 4.000 1485.160 9.130 1485.760 ;
     RECT 4.000 1478.360 9.130 1478.960 ;
     RECT 4.000 1471.560 9.130 1472.160 ;
     RECT 4.000 1464.760 9.130 1465.360 ;
     RECT 4.000 1457.960 9.130 1458.560 ;
     RECT 4.000 1451.160 9.130 1451.760 ;
     RECT 4.000 1444.360 9.130 1444.960 ;
     RECT 4.000 1437.560 9.130 1438.160 ;
     RECT 4.000 1430.760 9.130 1431.360 ;
     RECT 4.000 1423.960 9.130 1424.560 ;
     RECT 4.000 1417.160 9.130 1417.760 ;
     RECT 4.000 1410.360 9.130 1410.960 ;
     RECT 4.000 1403.560 9.130 1404.160 ;
     RECT 4.000 1396.760 9.130 1397.360 ;
     RECT 4.000 1389.960 9.130 1390.560 ;
     RECT 4.000 1383.160 9.130 1383.760 ;
     RECT 4.000 1376.360 9.130 1376.960 ;
     RECT 4.000 1369.560 9.130 1370.160 ;
     RECT 4.000 1362.760 9.130 1363.360 ;
     RECT 4.000 1355.960 9.130 1356.560 ;
     RECT 4.000 1349.160 9.130 1349.760 ;
     RECT 4.000 1342.360 9.130 1342.960 ;
     RECT 4.000 1335.560 9.130 1336.160 ;
     RECT 4.000 1267.560 9.130 1268.160 ;
     RECT  9.13 13.435 11.91 1689.285 ;
     RECT  11.91 13.435 24.13 1686.565 ;
     RECT  24.13 10.715 26.91 1686.565 ;
     RECT  26.91 180.39 37.41 357.49 ;
     RECT  26.91 1561.47 43.32 1561.77 ;
     RECT  26.91 978.03 47.92 1013.69 ;
     RECT  47.23 551.67 48 551.97 ;
     RECT  49.07 611.51 49.84 611.81 ;
     RECT  49.07 634.63 50.44 639.69 ;
     RECT  49.07 1443.15 50.52 1443.45 ;
     RECT  47.92 969.19 50.68 1013.69 ;
     RECT  50.44 630.55 50.98 639.69 ;
     RECT  50.98 630.55 51.21 634.93 ;
     RECT  51.36 1186.79 51.83 1187.09 ;
     RECT  51.14 1157.55 52.13 1157.85 ;
     RECT  51.83 1186.11 52.13 1187.09 ;
     RECT  50.68 969.19 53.9 1023.21 ;
     RECT  26.91 1592.75 54.59 1593.05 ;
     RECT  53.9 589.75 54.89 590.05 ;
     RECT  53.44 652.99 54.89 653.29 ;
     RECT  53.9 1228.95 54.89 1229.25 ;
     RECT  53.9 969.19 55.28 1025.25 ;
     RECT  54.59 1592.75 55.51 1599.85 ;
     RECT  55.28 969.19 56.05 1027.97 ;
     RECT  56.88 1046.71 57.65 1047.01 ;
     RECT  52.98 798.51 59.88 798.81 ;
     RECT  60.11 929.75 60.88 930.05 ;
     RECT  60.56 869.23 61.33 869.53 ;
     RECT  57.35 1643.07 62.87 1643.37 ;
     RECT  49.07 1660.07 62.87 1660.37 ;
     RECT  62.4 1150.07 63.17 1150.37 ;
     RECT  37.41 180.39 65.7 186.81 ;
     RECT  37.41 207.59 67.08 357.49 ;
     RECT  67.08 295.31 68 357.49 ;
     RECT  62.87 1643.07 68.16 1660.37 ;
     RECT  68 336.11 68.46 357.49 ;
     RECT  68.46 349.71 68.92 357.49 ;
     RECT  68.16 1638.99 71.84 1660.37 ;
     RECT  67.08 207.59 72.14 275.89 ;
     RECT  59.88 798.51 72.37 810.37 ;
     RECT  72.14 207.59 73.06 262.29 ;
     RECT  73.06 213.71 73.98 262.29 ;
     RECT  54.82 1213.99 74.83 1214.29 ;
     RECT  73.98 227.31 74.9 262.29 ;
     RECT  74.9 227.31 75.36 254.81 ;
     RECT  69.08 947.43 75.52 947.73 ;
     RECT  56.05 969.19 75.52 1027.29 ;
     RECT  75.36 227.31 75.82 241.21 ;
     RECT  43.32 1561.47 79.66 1563.13 ;
     RECT  71.84 1632.87 80.58 1660.37 ;
     RECT  74.83 137.55 82.19 137.85 ;
     RECT  74.83 1213.99 82.19 1225.85 ;
     RECT  80.58 1632.87 82.19 1663.77 ;
     RECT  82.19 1629.47 85.87 1663.77 ;
     RECT  52.98 1324.15 86.17 1324.45 ;
     RECT  75.82 227.31 87.32 233.05 ;
     RECT  82.19 137.55 88.63 151.45 ;
     RECT  82.19 1213.99 88.63 1234.01 ;
     RECT  75.52 947.43 89.85 1027.29 ;
     RECT  55.51 1592.75 92.54 1610.05 ;
     RECT  52.13 1186.11 92.84 1186.41 ;
     RECT  88.63 1201.07 95.14 1234.01 ;
     RECT  81.27 1282.67 95.99 1282.97 ;
     RECT  79.66 1561.47 99.44 1569.25 ;
     RECT  92.54 1590.03 99.44 1610.05 ;
     RECT  72.37 798.51 99.97 798.81 ;
     RECT  87.32 232.75 100.2 233.05 ;
     RECT  68 295.31 100.66 316.69 ;
     RECT  100.66 316.39 101.58 316.69 ;
     RECT  88.63 136.87 102.43 151.45 ;
     RECT  95.14 1201.07 102.43 1201.37 ;
     RECT  82.19 1250.03 109.79 1250.33 ;
     RECT  99.44 1561.47 113.24 1610.05 ;
     RECT  85.87 1627.43 113.24 1663.77 ;
     RECT  53.44 1391.47 113.77 1391.77 ;
     RECT  65.7 180.39 114.46 180.69 ;
     RECT  100.66 295.31 114.92 295.61 ;
     RECT  51.21 634.63 115.38 634.93 ;
     RECT  118.99 1380.59 120.6 1380.89 ;
     RECT  95.99 1274.51 120.83 1282.97 ;
     RECT  119.91 1364.27 120.83 1364.57 ;
     RECT  120.6 1379.91 120.83 1380.89 ;
     RECT  120.83 1274.51 121.75 1291.13 ;
     RECT  119.91 1396.91 121.82 1400.61 ;
     RECT  120.83 1364.27 122.67 1380.89 ;
     RECT  102.43 136.87 123.59 158.25 ;
     RECT  95.14 1225.55 123.59 1234.01 ;
     RECT  109.79 1250.03 123.59 1258.49 ;
     RECT  89.85 969.19 127.5 1027.29 ;
     RECT  89.85 947.43 127.57 947.73 ;
     RECT  60.8 1428.87 127.57 1429.17 ;
     RECT  103.12 0.19 130.03 0.49 ;
     RECT  123.59 1217.39 133.71 1258.49 ;
     RECT  121.75 1274.51 133.71 1299.29 ;
     RECT  102.43 1331.63 133.71 1331.93 ;
     RECT  122.67 1356.11 133.71 1380.89 ;
     RECT  127.5 969.19 134.63 1028.65 ;
     RECT  134.63 1315.31 135.55 1315.61 ;
     RECT  133.71 1331.63 135.55 1380.89 ;
     RECT  113.24 1561.47 136.24 1663.77 ;
     RECT  133.71 1217.39 136.47 1299.29 ;
     RECT  135.55 1315.31 136.47 1380.89 ;
     RECT  123.59 134.83 137.39 158.25 ;
     RECT  102.43 1192.91 137.39 1201.37 ;
     RECT  136.47 1217.39 137.39 1380.89 ;
     RECT  101.51 1176.59 137.62 1176.89 ;
     RECT  129.11 1127.63 138.08 1127.93 ;
     RECT  136.47 1143.95 138.08 1144.25 ;
     RECT  137.62 1168.43 138.08 1176.89 ;
     RECT  137.39 1192.91 138.08 1380.89 ;
     RECT  137.62 1054.19 138.54 1054.49 ;
     RECT  138.08 1454.03 138.54 1454.33 ;
     RECT  126.58 1517.27 138.54 1517.57 ;
     RECT  138.08 1535.63 138.54 1535.93 ;
     RECT  138.54 1511.15 139.46 1535.93 ;
     RECT  138.54 1478.51 140.38 1478.81 ;
     RECT  134.63 969.19 142.22 1030.01 ;
     RECT  142.22 969.19 142.68 1038.17 ;
     RECT  138.54 1054.19 142.68 1061.29 ;
     RECT  142.68 969.19 143.83 1061.29 ;
     RECT  135.55 1078.67 143.83 1078.97 ;
     RECT  138.08 1119.47 144.06 1127.93 ;
     RECT  138.08 1143.95 144.06 1152.41 ;
     RECT  139.46 1502.99 147.27 1535.93 ;
     RECT  136.24 1551.95 147.27 1663.77 ;
     RECT  138.54 1454.03 148.2 1462.49 ;
     RECT  140.38 1478.51 148.2 1486.97 ;
     RECT  148.2 1454.03 148.66 1486.97 ;
     RECT  147.27 1502.99 148.66 1663.77 ;
     RECT  138.08 1168.43 149.35 1380.89 ;
     RECT  121.82 1396.91 149.35 1397.21 ;
     RECT  142.91 1437.71 149.35 1438.01 ;
     RECT  143.83 969.19 150 1078.97 ;
     RECT  138.08 1094.99 150 1103.45 ;
     RECT  144.06 1119.47 150 1152.41 ;
     RECT  149.35 1168.43 150 1397.21 ;
     RECT  147.51 1413.23 150 1413.53 ;
     RECT  149.35 1428.19 150 1438.01 ;
     RECT  148.66 1454.03 150 1663.77 ;
     RECT  137.39 134.15 153.22 158.25 ;
     RECT  68.92 357.19 153.22 357.49 ;
     RECT  150 836.76 153.22 867.36 ;
     RECT  51.14 901.87 153.22 902.17 ;
     RECT  150 969.19 153.22 1663.77 ;
     RECT  153.22 134.15 154.87 1663.77 ;
     RECT  154.87 134.15 186.15 1671.25 ;
     RECT  130.03 0.19 189.13 1.17 ;
     RECT  186.15 132.11 189.13 1671.25 ;
     RECT  189.13 0.19 191.91 1689.285 ;
     RECT  191.91 0.19 206.91 1686.565 ;
     RECT  206.91 72.27 244.64 72.57 ;
     RECT  206.91 0.19 369.13 1.17 ;
     RECT  206.91 120.55 369.13 1671.25 ;
     RECT  369.13 0.19 371.91 1689.285 ;
     RECT  371.91 0.19 386.91 1686.565 ;
     RECT  386.91 0.19 416.22 1.17 ;
     RECT  416.22 0.19 549.13 0.49 ;
     RECT  386.91 120.55 549.13 1671.25 ;
     RECT  549.13 0.19 551.91 1689.285 ;
     RECT  551.91 0.19 560.23 1686.565 ;
     RECT  560.23 0.19 561.12 1074.89 ;
     RECT  560.23 1090.91 561.58 1123.85 ;
     RECT  561.58 1090.91 565.95 1116.37 ;
     RECT  561.12 0.19 566.91 1067.41 ;
     RECT  560.23 1505.71 566.91 1686.565 ;
     RECT  560.23 1458.11 572.16 1491.05 ;
     RECT  565.95 1091.59 572.62 1116.37 ;
     RECT  560.23 1138.51 572.62 1148.33 ;
     RECT  560.23 1162.99 572.62 1197.29 ;
     RECT  560.23 1213.31 572.62 1221.77 ;
     RECT  560.23 1236.43 572.62 1246.25 ;
     RECT  560.23 1262.27 572.62 1295.21 ;
     RECT  560.23 1311.23 572.62 1319.69 ;
     RECT  560.23 1335.71 572.62 1344.17 ;
     RECT  560.23 1392.83 572.62 1417.61 ;
     RECT  572.62 1392.83 573.08 1405.37 ;
     RECT  566.91 1505.71 573.08 1671.25 ;
     RECT  572.62 1213.31 574.46 1213.61 ;
     RECT  560.23 1433.63 576.23 1442.09 ;
     RECT  572.16 1458.11 576.23 1482.89 ;
     RECT  560.23 1360.19 578.6 1378.17 ;
     RECT  578.6 1368.35 580.21 1378.17 ;
     RECT  572.62 1335.71 582.67 1342.13 ;
     RECT  576.23 1433.63 582.74 1482.89 ;
     RECT  580.21 1377.87 589.11 1378.17 ;
     RECT  566.91 120.55 591.55 1067.41 ;
     RECT  572.62 1091.59 591.55 1091.89 ;
     RECT  572.62 1107.91 591.55 1116.37 ;
     RECT  572.62 1138.51 591.55 1138.81 ;
     RECT  573.08 1405.07 597.62 1405.37 ;
     RECT  572.62 1262.27 607.58 1262.57 ;
     RECT  597.62 1405.07 607.58 1412.85 ;
     RECT  591.55 120.55 609.97 1138.81 ;
     RECT  582.74 1470.35 611.72 1482.89 ;
     RECT  609.97 1058.95 615.86 1072.85 ;
     RECT  615.86 1065.75 616.09 1072.85 ;
     RECT  609.97 120.55 617.7 1042.93 ;
     RECT  617.7 120.55 617.93 1038.85 ;
     RECT  617.93 120.55 619.77 1032.05 ;
     RECT  616.09 1065.75 621.16 1066.05 ;
     RECT  572.62 1311.23 631.96 1311.53 ;
     RECT  609.97 1107.91 634.42 1117.05 ;
     RECT  632.35 1069.83 640 1070.13 ;
     RECT  619.77 120.55 644 1027.29 ;
     RECT  640 1069.68 644 1070.28 ;
     RECT  609.97 1091.59 644 1091.89 ;
     RECT  634.42 1107.91 644 1117.73 ;
     RECT  582.74 1433.63 645.3 1445.49 ;
     RECT  639.48 1362.91 651.28 1363.21 ;
     RECT  665.7 1296.95 679.8 1297.25 ;
     RECT  566.91 0.19 729.13 0.49 ;
     RECT  644 120.55 729.13 1117.73 ;
     RECT  609.97 1138.51 729.13 1138.81 ;
     RECT  572.62 1162.99 729.13 1187.77 ;
     RECT  679.5 1211.27 729.13 1211.57 ;
     RECT  572.62 1236.43 729.13 1236.73 ;
     RECT  572.62 1282.67 729.13 1282.97 ;
     RECT  582.67 1328.23 729.13 1342.13 ;
     RECT  589.11 1377.87 729.13 1391.09 ;
     RECT  607.58 1405.07 729.13 1405.37 ;
     RECT  645.3 1445.19 729.13 1445.49 ;
     RECT  611.72 1470.35 729.13 1470.65 ;
     RECT  573.08 1505.71 729.13 1506.01 ;
     RECT  573.08 1527.47 729.13 1535.25 ;
     RECT  573.08 1551.95 729.13 1671.25 ;
     RECT  729.13 1134.075 731.91 1689.285 ;
     RECT  729.13 0.19 736.38 1117.73 ;
     RECT  736.38 0.19 740 1116.37 ;
     RECT  731.91 1134.075 744.13 1686.565 ;
     RECT  740 0.19 746.91 1021.85 ;
     RECT  744.13 1131.355 746.91 1686.565 ;
     RECT  740 1074.59 752.48 1074.89 ;
     RECT  740 1100.43 752.48 1100.73 ;
     RECT  753.79 1072.55 754.56 1072.85 ;
     RECT  746.91 120.55 758.85 1021.85 ;
     RECT  767.59 1077.31 768.36 1077.61 ;
     RECT  814.51 1082.75 821.02 1083.05 ;
     RECT  758.85 120.55 865.8 1027.29 ;
     RECT  746.91 0.19 909.13 0.49 ;
     RECT  865.8 120.55 909.13 1035.45 ;
     RECT  889.95 1058.95 909.13 1059.25 ;
     RECT  740 1116.07 909.13 1116.37 ;
     RECT  746.91 1162.99 909.13 1187.77 ;
     RECT  746.91 1236.43 909.13 1236.73 ;
     RECT  746.91 1282.67 909.13 1282.97 ;
     RECT  746.91 1328.23 909.13 1342.13 ;
     RECT  746.91 1377.87 909.13 1391.09 ;
     RECT  746.91 1405.07 909.13 1405.37 ;
     RECT  746.91 1445.19 909.13 1445.49 ;
     RECT  746.91 1470.35 909.13 1470.65 ;
     RECT  746.91 1505.71 909.13 1506.01 ;
     RECT  746.91 1527.47 909.13 1535.25 ;
     RECT  746.91 1551.95 909.13 1671.25 ;
     RECT  909.13 0.19 911.91 1689.285 ;
     RECT  911.91 0.19 926.91 1686.565 ;
     RECT  926.91 0.19 1012.38 0.49 ;
     RECT  926.91 120.55 1089.13 1035.45 ;
     RECT  926.91 1058.95 1089.13 1059.25 ;
     RECT  926.91 1116.07 1089.13 1116.37 ;
     RECT  926.91 1162.99 1089.13 1187.77 ;
     RECT  926.91 1236.43 1089.13 1236.73 ;
     RECT  926.91 1282.67 1089.13 1282.97 ;
     RECT  926.91 1328.23 1089.13 1342.13 ;
     RECT  926.91 1377.87 1089.13 1391.09 ;
     RECT  926.91 1405.07 1089.13 1405.37 ;
     RECT  926.91 1445.19 1089.13 1445.49 ;
     RECT  926.91 1470.35 1089.13 1470.65 ;
     RECT  926.91 1505.71 1089.13 1506.01 ;
     RECT  926.91 1527.47 1089.13 1535.25 ;
     RECT  926.91 1551.95 1089.13 1671.25 ;
     RECT  1089.13 13.435 1091.91 1689.285 ;
     RECT  1091.91 13.435 1104.13 1686.565 ;
     RECT  1104.13 10.715 1106.91 1686.565 ;
     RECT  1106.91 120.55 1114.5 1035.45 ;
     RECT  1114.5 132.11 1127.31 1035.45 ;
     RECT  1127.31 132.11 1142.1 1043.61 ;
     RECT  1142.1 134.15 1269.13 1043.61 ;
     RECT  1106.91 1058.95 1269.13 1059.25 ;
     RECT  1106.91 1116.07 1269.13 1116.37 ;
     RECT  1106.91 1162.99 1269.13 1187.77 ;
     RECT  1106.91 1236.43 1269.13 1236.73 ;
     RECT  1106.91 1282.67 1269.13 1282.97 ;
     RECT  1106.91 1328.23 1269.13 1342.13 ;
     RECT  1106.91 1377.87 1269.13 1391.09 ;
     RECT  1106.91 1405.07 1269.13 1405.37 ;
     RECT  1106.91 1445.19 1269.13 1445.49 ;
     RECT  1106.91 1470.35 1269.13 1470.65 ;
     RECT  1106.91 1505.71 1269.13 1506.01 ;
     RECT  1106.91 1527.47 1269.13 1535.25 ;
     RECT  1106.91 1551.95 1269.13 1671.25 ;
     RECT  1269.13 13.435 1271.91 1689.285 ;
     RECT  1271.91 13.435 1284.13 1686.565 ;
     RECT  1284.13 10.715 1286.91 1686.565 ;
     RECT  1286.91 1058.95 1317.82 1059.25 ;
     RECT  1286.91 134.15 1358.76 1043.61 ;
     RECT  1286.91 1527.47 1360.14 1535.25 ;
     RECT  1286.91 1116.07 1378.54 1116.37 ;
     RECT  1443.56 0.19 1449.13 0.49 ;
     RECT  1358.76 134.15 1449.13 1035.45 ;
     RECT  1436.2 1058.95 1449.13 1059.25 ;
     RECT  1286.91 1162.99 1449.13 1187.77 ;
     RECT  1286.91 1236.43 1449.13 1236.73 ;
     RECT  1286.91 1282.67 1449.13 1282.97 ;
     RECT  1286.91 1328.23 1449.13 1342.13 ;
     RECT  1286.91 1377.87 1449.13 1391.09 ;
     RECT  1286.91 1405.07 1449.13 1405.37 ;
     RECT  1286.91 1445.19 1449.13 1445.49 ;
     RECT  1286.91 1470.35 1449.13 1470.65 ;
     RECT  1286.91 1505.71 1449.13 1506.01 ;
     RECT  1360.14 1534.95 1449.13 1535.25 ;
     RECT  1286.91 1551.95 1449.13 1671.25 ;
     RECT  1449.13 0.19 1451.91 1689.285 ;
     RECT  1451.91 0.19 1466.91 1686.565 ;
     RECT  1466.91 1162.99 1469.16 1187.77 ;
     RECT  1469.16 1175.91 1500.44 1187.77 ;
     RECT  1466.91 134.15 1514.4 1035.45 ;
     RECT  1466.91 1056.23 1527.74 1059.25 ;
     RECT  1514.4 132.11 1592.14 1035.45 ;
     RECT  1527.74 1050.79 1592.14 1059.25 ;
     RECT  1592.14 132.11 1605.02 1059.25 ;
     RECT  1466.91 0.19 1629.13 0.49 ;
     RECT  1605.02 132.11 1629.13 1065.37 ;
     RECT  1628.02 1092.27 1629.13 1092.57 ;
     RECT  1500.44 1175.91 1629.13 1178.93 ;
     RECT  1466.91 1282.67 1629.13 1282.97 ;
     RECT  1466.91 1328.23 1629.13 1342.13 ;
     RECT  1466.91 1377.87 1629.13 1391.09 ;
     RECT  1466.91 1405.07 1629.13 1405.37 ;
     RECT  1466.91 1445.19 1629.13 1445.49 ;
     RECT  1466.91 1470.35 1629.13 1470.65 ;
     RECT  1466.91 1505.71 1629.13 1506.01 ;
     RECT  1466.91 1534.95 1629.13 1535.25 ;
     RECT  1466.91 1551.95 1629.13 1671.25 ;
     RECT  1629.13 0.19 1631.91 1689.285 ;
     RECT  1631.91 0.19 1646.91 1686.565 ;
     RECT  1646.91 1092.27 1662.98 1092.57 ;
     RECT  1646.91 1282.67 1676.16 1282.97 ;
     RECT  1662.98 1091.59 1706.22 1092.57 ;
     RECT  1706.22 1084.11 1773.45 1092.57 ;
     RECT  1646.91 1377.87 1793.92 1391.09 ;
     RECT  1646.91 0.19 1809.13 0.49 ;
     RECT  1646.91 132.11 1809.13 1065.37 ;
     RECT  1773.45 1086.15 1809.13 1092.57 ;
     RECT  1646.91 1175.91 1809.13 1178.93 ;
     RECT  1646.91 1328.23 1809.13 1342.13 ;
     RECT  1793.92 1390.79 1809.13 1391.09 ;
     RECT  1646.91 1405.07 1809.13 1405.37 ;
     RECT  1646.91 1445.19 1809.13 1445.49 ;
     RECT  1646.91 1470.35 1809.13 1470.65 ;
     RECT  1646.91 1505.71 1809.13 1506.01 ;
     RECT  1646.91 1534.95 1809.13 1535.25 ;
     RECT  1646.91 1551.95 1809.13 1671.25 ;
     RECT  1809.13 0.19 1811.91 1689.285 ;
     RECT  1811.91 0.19 1826.91 1686.565 ;
     RECT  1826.91 1405.07 1844.06 1405.37 ;
     RECT  1826.91 1086.15 1908.16 1092.57 ;
     RECT  1908.16 1086.15 1917.82 1100.05 ;
     RECT  1826.91 1470.35 1950.32 1470.65 ;
     RECT  1826.91 1505.71 1951.24 1506.01 ;
     RECT  1917.82 1081.39 1973.48 1100.05 ;
     RECT  1931.62 1121.51 1973.48 1121.81 ;
     RECT  1826.91 132.11 1987.28 1067.41 ;
     RECT  1973.48 1081.39 1987.28 1121.81 ;
     RECT  1826.91 0.19 1989.13 0.49 ;
     RECT  1987.28 132.11 1989.13 1121.81 ;
     RECT  1826.91 1175.91 1989.13 1178.93 ;
     RECT  1826.91 1328.23 1989.13 1342.13 ;
     RECT  1826.91 1390.79 1989.13 1391.09 ;
     RECT  1826.91 1445.19 1989.13 1445.49 ;
     RECT  1826.91 1534.95 1989.13 1535.25 ;
     RECT  1826.91 1551.95 1989.13 1671.25 ;
     RECT  1989.13 0.19 1991.91 1689.285 ;
     RECT  1991.91 0.19 2006.91 1686.565 ;
     RECT  2006.91 1551.95 2049.68 1671.25 ;
     RECT  2049.68 1554.67 2052.21 1671.25 ;
     RECT  2006.91 132.11 2066.4 1121.81 ;
     RECT  2052.21 1554.67 2123.74 1668.53 ;
     RECT  2006.91 1175.91 2148.58 1178.93 ;
     RECT  2006.91 1534.95 2167.83 1535.25 ;
     RECT  2006.91 0.19 2169.13 0.49 ;
     RECT  2066.4 132.11 2169.13 1135.41 ;
     RECT  2148.58 1175.91 2169.13 1176.21 ;
     RECT  2006.91 1328.23 2169.13 1342.13 ;
     RECT  2006.91 1390.79 2169.13 1391.09 ;
     RECT  2006.91 1445.19 2169.13 1445.49 ;
     RECT  2167.83 1524.75 2169.13 1535.25 ;
     RECT  2123.74 1555.35 2169.13 1668.53 ;
     RECT  2169.13 0.19 2171.91 1689.285 ;
     RECT  2171.91 0.19 2186.91 1686.565 ;
     RECT  2186.91 1480.55 2232.23 1480.85 ;
     RECT  2232.23 1466.95 2232.53 1480.85 ;
     RECT  2186.91 0.19 2349.13 0.49 ;
     RECT  2186.91 132.11 2349.13 1135.41 ;
     RECT  2186.91 1175.91 2349.13 1176.21 ;
     RECT  2186.91 1328.23 2349.13 1342.13 ;
     RECT  2186.91 1390.79 2349.13 1391.09 ;
     RECT  2186.91 1445.19 2349.13 1445.49 ;
     RECT  2232.53 1466.95 2349.13 1467.25 ;
     RECT  2186.91 1534.95 2349.13 1535.25 ;
     RECT  2186.91 1562.15 2349.13 1668.53 ;
     RECT  2349.13 0.19 2351.91 1689.285 ;
     RECT  2351.91 0.19 2366.91 1686.565 ;
     RECT  2366.91 132.11 2380.88 1135.41 ;
     RECT  2380.88 1131.03 2388.93 1135.41 ;
     RECT  2366.91 1328.23 2391.46 1342.13 ;
     RECT  2366.91 1390.79 2416.76 1391.09 ;
     RECT  2366.91 1562.15 2432.86 1668.53 ;
     RECT  2366.91 1293.55 2438.61 1293.85 ;
     RECT  2366.91 0.19 2529.13 0.49 ;
     RECT  2366.91 63.43 2529.13 63.73 ;
     RECT  2380.88 132.11 2529.13 1114.33 ;
     RECT  2388.93 1135.11 2529.13 1135.41 ;
     RECT  2366.91 1175.91 2529.13 1176.21 ;
     RECT  2438.31 1246.63 2529.13 1246.93 ;
     RECT  2391.46 1341.83 2529.13 1342.13 ;
     RECT  2366.91 1445.19 2529.13 1445.49 ;
     RECT  2366.91 1534.95 2529.13 1535.25 ;
     RECT  2432.86 1567.59 2529.13 1668.53 ;
     RECT  2529.13 0.19 2531.91 1689.285 ;
     RECT  2531.91 0.19 2546.91 1686.565 ;
     RECT  2546.91 1246.63 2548.09 1246.93 ;
     RECT  2546.91 1534.95 2552.92 1535.25 ;
     RECT  2546.91 63.43 2569.18 63.73 ;
     RECT  2546.91 1341.83 2590.18 1342.13 ;
     RECT  2546.91 1567.59 2594.32 1668.53 ;
     RECT  2546.91 0.19 2610.42 0.49 ;
     RECT  2546.91 1230.99 2618.93 1231.29 ;
     RECT  2546.91 1445.19 2639.86 1445.49 ;
     RECT  2546.91 1135.11 2645.31 1135.41 ;
     RECT  2618.63 1213.99 2645.61 1214.29 ;
     RECT  2594.32 1567.59 2681.26 1612.09 ;
     RECT  2546.91 132.11 2683.95 1114.33 ;
     RECT  2645.31 1129.67 2684.25 1135.41 ;
     RECT  2569.18 63.43 2709.13 72.57 ;
     RECT  2683.95 132.11 2709.13 1115.01 ;
     RECT  2684.25 1135.11 2709.13 1135.41 ;
     RECT  2681.26 1567.59 2709.13 1587.61 ;
     RECT  2681.26 1602.95 2709.13 1612.09 ;
     RECT  2594.32 1630.15 2709.13 1668.53 ;
     RECT  2709.13 13.435 2711.91 1689.285 ;
     RECT  2711.91 13.435 2724.13 1686.565 ;
     RECT  2724.13 10.715 2726.91 1686.565 ;
     RECT  2726.91 63.43 2728.41 72.57 ;
     RECT  2728.41 63.43 2733.01 63.73 ;
     RECT  2726.91 132.11 2736.69 1114.33 ;
     RECT  2726.91 1630.15 2765.21 1668.53 ;
     RECT  2736.69 134.15 2767.74 1114.33 ;
     RECT  2765.21 1651.91 2769.58 1668.53 ;
     RECT  2767.74 134.15 2770 957.25 ;
     RECT  2770 134.15 2770.04 248.69 ;
     RECT  2770.04 248.39 2770.5 248.69 ;
     RECT  2770.04 134.15 2770.96 228.29 ;
     RECT  2770 315.03 2771.65 315.33 ;
     RECT  2770 369.43 2771.65 380.61 ;
     RECT  2770 576.15 2771.65 609.09 ;
     RECT  2770 956.95 2771.88 957.25 ;
     RECT  2770 543.51 2772.57 554.69 ;
     RECT  2765.21 1630.15 2772.57 1635.89 ;
     RECT  2770 402.07 2774.41 522.05 ;
     RECT  2770 630.55 2774.41 815.81 ;
     RECT  2770 336.79 2775.33 347.97 ;
     RECT  2772.57 543.51 2775.33 543.81 ;
     RECT  2770 837.27 2776.02 913.73 ;
     RECT  2726.91 1602.95 2776.02 1612.09 ;
     RECT  2771.65 587.03 2776.25 609.09 ;
     RECT  2767.74 972.59 2776.25 1114.33 ;
     RECT  2774.41 402.07 2776.48 456.09 ;
     RECT  2776.02 837.27 2776.48 902.85 ;
     RECT  2775.33 336.79 2776.94 337.09 ;
     RECT  2776.25 587.03 2777.17 598.21 ;
     RECT  2726.91 1567.59 2777.86 1586.93 ;
     RECT  2774.41 782.87 2778.09 815.81 ;
     RECT  2776.48 412.95 2780.85 456.09 ;
     RECT  2776.48 837.27 2781.08 891.97 ;
     RECT  2780.85 439.47 2781.54 456.09 ;
     RECT  2771.65 369.43 2781.77 369.73 ;
     RECT  2770.96 134.15 2782 206.53 ;
     RECT  2770.96 227.99 2782 228.29 ;
     RECT  2780.85 412.95 2782.46 424.13 ;
     RECT  2782 134.15 2788.21 161.65 ;
     RECT  2774.41 478.23 2788.21 522.05 ;
     RECT  2781.08 837.27 2788.21 881.09 ;
     RECT  2776.02 1602.95 2788.21 1611.41 ;
     RECT  2788.21 134.15 2789.13 137.17 ;
     RECT  2788.21 478.23 2789.13 500.29 ;
     RECT  2786.99 950.83 2791.59 951.13 ;
     RECT  2788.21 151.15 2794.65 161.65 ;
     RECT  2788.21 521.75 2794.65 522.05 ;
     RECT  2788.21 837.27 2794.65 837.57 ;
     RECT  2782.46 412.95 2794.88 413.25 ;
     RECT  2778.09 815.51 2794.88 815.81 ;
     RECT  2789.13 134.83 2795.57 137.17 ;
     RECT  2789.13 493.19 2795.57 500.29 ;
     RECT  2774.41 630.55 2795.57 761.41 ;
     RECT  2776.25 973.27 2795.57 1114.33 ;
     RECT  2795.57 136.87 2796.49 137.17 ;
     RECT  2789.13 478.23 2796.49 478.53 ;
     RECT  2778.09 782.87 2802.01 794.05 ;
     RECT  2788.21 1602.95 2802.01 1609.37 ;
     RECT  2788.21 859.03 2802.24 881.09 ;
     RECT  2769.58 1651.91 2802.7 1666.49 ;
     RECT  2802.24 859.03 2808.45 870.21 ;
     RECT  2808.45 869.91 2809.6 870.21 ;
     RECT  2777.86 1575.75 2809.6 1586.93 ;
     RECT  2802.01 782.87 2815.81 783.17 ;
     RECT  2802.01 1602.95 2815.81 1608.69 ;
     RECT  2794.65 151.83 2816.04 161.65 ;
     RECT  2795.57 630.55 2822.25 663.49 ;
     RECT  2795.57 684.95 2822.48 761.41 ;
     RECT  2822.25 630.55 2822.94 630.85 ;
     RECT  2795.57 975.99 2822.94 1114.33 ;
     RECT  2777.17 597.91 2829.38 598.21 ;
     RECT  2809.6 1575.75 2829.38 1581.49 ;
     RECT  2802.7 1657.35 2829.38 1666.49 ;
     RECT  2822.48 684.95 2829.61 750.53 ;
     RECT  2829.61 706.71 2829.84 750.53 ;
     RECT  2772.57 1630.15 2829.84 1631.13 ;
     RECT  2822.25 652.31 2835.13 663.49 ;
     RECT  2829.38 1657.35 2835.13 1658.33 ;
     RECT  2822.94 1018.83 2836.28 1114.33 ;
     RECT  2829.84 739.35 2836.74 750.53 ;
     RECT  2829.38 1575.75 2836.74 1576.05 ;
     RECT  2836.28 1056.23 2841.34 1114.33 ;
     RECT  2829.61 684.95 2843.64 685.25 ;
     RECT  2836.28 1018.83 2843.64 1035.45 ;
     RECT  2836.74 739.35 2844.33 739.65 ;
     RECT  2829.84 1630.15 2844.33 1630.45 ;
     RECT  2829.84 706.71 2846.17 717.89 ;
     RECT  2835.13 652.31 2849.85 652.61 ;
     RECT  2846.17 706.71 2850.77 707.01 ;
     RECT  2815.81 1608.39 2850.77 1608.69 ;
     RECT  2835.13 1657.35 2850.77 1657.65 ;
     RECT  2816.04 161.35 2856.98 161.65 ;
     RECT  2791.59 937.23 2857.44 951.13 ;
     RECT  2857.44 950.83 2858.36 951.13 ;
     RECT  2841.34 1056.23 2860.66 1092.57 ;
     RECT  2726.91 1135.11 2860.66 1135.41 ;
     RECT  2822.94 975.99 2861.12 1002.81 ;
     RECT  2860.66 1075.27 2861.12 1092.57 ;
     RECT  2841.34 1107.91 2864.34 1114.33 ;
     RECT  2861.12 978.03 2865.72 1002.81 ;
     RECT  2865.72 996.39 2867.56 1002.81 ;
     RECT  2867.56 996.39 2872.62 1002.13 ;
     RECT  2843.64 1026.99 2874.46 1035.45 ;
     RECT  2810.91 251.11 2889.13 251.41 ;
     RECT  2819.19 340.87 2889.13 341.17 ;
     RECT  2804.47 417.71 2889.13 418.01 ;
     RECT  2781.54 439.47 2889.13 439.77 ;
     RECT  2781.54 455.79 2889.13 456.09 ;
     RECT  2795.57 493.19 2889.13 493.49 ;
     RECT  2865.72 978.03 2889.13 978.33 ;
     RECT  2872.62 996.39 2889.13 996.69 ;
     RECT  2874.46 1029.71 2889.13 1035.45 ;
     RECT  2860.66 1056.23 2889.13 1056.53 ;
     RECT  2861.12 1086.15 2889.13 1086.45 ;
     RECT  2864.34 1114.03 2889.13 1114.33 ;
     RECT  2889.13 13.435 2891.91 1689.285 ;
     RECT  2891.91 13.435 2904.13 1686.565 ;
     RECT  2904.13 10.715 2906.91 1686.565 ;
     RECT 2906.910 133.920 2916.860 138.760 ;
     RECT 2906.910 139.360 2916.860 144.200 ;
     RECT 2906.910 144.800 2916.860 149.640 ;
     RECT 2906.910 150.240 2916.860 155.080 ;
     RECT 2906.910 155.680 2916.860 160.520 ;
     RECT 2906.910 161.120 2916.860 165.960 ;
     RECT 2906.910 166.560 2916.860 171.400 ;
     RECT 2906.910 172.000 2916.860 176.840 ;
     RECT 2906.910 177.440 2916.860 182.280 ;
     RECT 2906.910 182.880 2916.860 187.720 ;
     RECT 2906.910 182.280 2916.000 182.880 ;
     RECT 2906.910 176.840 2916.000 177.440 ;
     RECT 2906.910 171.400 2916.000 172.000 ;
     RECT 2906.910 165.960 2916.000 166.560 ;
     RECT 2906.910 160.520 2916.000 161.120 ;
     RECT 2906.910 155.080 2916.000 155.680 ;
     RECT 2906.910 149.640 2916.000 150.240 ;
     RECT 2906.910 144.200 2916.000 144.800 ;
     RECT 2906.910 138.760 2916.000 139.360 ;
     RECT 2906.910 188.320 2916.860 193.160 ;
     RECT 2906.910 193.760 2916.860 198.600 ;
     RECT 2906.910 199.200 2916.860 204.040 ;
     RECT 2906.910 204.640 2916.860 209.480 ;
     RECT 2906.910 210.080 2916.860 214.920 ;
     RECT 2906.910 215.520 2916.860 220.360 ;
     RECT 2906.910 220.960 2916.860 225.800 ;
     RECT 2906.910 226.400 2916.860 231.240 ;
     RECT 2906.910 231.840 2916.860 236.680 ;
     RECT 2906.910 237.280 2916.860 242.120 ;
     RECT 2906.910 242.720 2916.860 247.560 ;
     RECT 2906.910 248.160 2916.860 253.000 ;
     RECT 2906.910 253.600 2916.860 258.440 ;
     RECT 2906.910 259.040 2916.860 263.880 ;
     RECT 2906.910 264.480 2916.860 269.320 ;
     RECT 2906.910 269.920 2916.860 274.760 ;
     RECT 2906.910 275.360 2916.860 280.200 ;
     RECT 2906.910 280.800 2916.860 285.640 ;
     RECT 2906.910 286.240 2916.860 291.080 ;
     RECT 2906.910 291.680 2916.860 296.520 ;
     RECT 2906.910 297.120 2916.860 301.960 ;
     RECT 2906.910 302.560 2916.860 307.400 ;
     RECT 2906.910 308.000 2916.860 312.840 ;
     RECT 2906.910 313.440 2916.860 318.280 ;
     RECT 2906.910 318.880 2916.860 323.720 ;
     RECT 2906.910 324.320 2916.860 329.160 ;
     RECT 2906.910 329.760 2916.860 334.600 ;
     RECT 2906.910 335.200 2916.860 340.040 ;
     RECT 2906.910 340.640 2916.860 345.480 ;
     RECT 2906.910 346.080 2916.860 350.920 ;
     RECT 2906.910 351.520 2916.860 356.360 ;
     RECT 2906.910 356.960 2916.860 361.800 ;
     RECT 2906.910 362.400 2916.860 367.240 ;
     RECT 2906.910 367.840 2916.860 372.680 ;
     RECT 2906.910 373.280 2916.860 378.120 ;
     RECT 2906.910 378.720 2916.860 383.560 ;
     RECT 2906.910 384.160 2916.860 389.000 ;
     RECT 2906.910 389.600 2916.860 394.440 ;
     RECT 2906.910 395.040 2916.860 399.880 ;
     RECT 2906.910 400.480 2916.860 405.320 ;
     RECT 2906.910 405.920 2916.860 410.760 ;
     RECT 2906.910 411.360 2916.860 416.200 ;
     RECT 2906.910 416.800 2916.860 421.640 ;
     RECT 2906.910 422.240 2916.860 427.080 ;
     RECT 2906.910 421.640 2916.000 422.240 ;
     RECT 2906.910 416.200 2916.000 416.800 ;
     RECT 2906.910 410.760 2916.000 411.360 ;
     RECT 2906.910 405.320 2916.000 405.920 ;
     RECT 2906.910 399.880 2916.000 400.480 ;
     RECT 2906.910 394.440 2916.000 395.040 ;
     RECT 2906.910 389.000 2916.000 389.600 ;
     RECT 2906.910 383.560 2916.000 384.160 ;
     RECT 2906.910 378.120 2916.000 378.720 ;
     RECT 2906.910 427.680 2916.860 432.520 ;
     RECT 2906.910 433.120 2916.860 437.960 ;
     RECT 2906.910 438.560 2916.860 443.400 ;
     RECT 2906.910 444.000 2916.860 448.840 ;
     RECT 2906.910 449.440 2916.860 454.280 ;
     RECT 2906.910 454.880 2916.860 459.720 ;
     RECT 2906.910 460.320 2916.860 465.160 ;
     RECT 2906.910 465.760 2916.860 470.600 ;
     RECT 2906.910 471.200 2916.860 476.040 ;
     RECT 2906.910 476.640 2916.860 481.480 ;
     RECT 2906.910 482.080 2916.860 486.920 ;
     RECT 2906.910 487.520 2916.860 492.360 ;
     RECT 2906.910 492.960 2916.860 497.800 ;
     RECT 2906.910 498.400 2916.860 503.240 ;
     RECT 2906.910 503.840 2916.860 508.680 ;
     RECT 2906.910 509.280 2916.860 514.120 ;
     RECT 2906.910 514.720 2916.860 519.560 ;
     RECT 2906.910 520.160 2916.860 525.000 ;
     RECT 2906.910 525.600 2916.860 530.440 ;
     RECT 2906.910 531.040 2916.860 535.880 ;
     RECT 2906.910 536.480 2916.860 541.320 ;
     RECT 2906.910 541.920 2916.860 546.760 ;
     RECT 2906.910 547.360 2916.860 552.200 ;
     RECT 2906.910 552.800 2916.860 557.640 ;
     RECT 2906.910 558.240 2916.860 563.080 ;
     RECT 2906.910 563.680 2916.860 568.520 ;
     RECT 2906.910 569.120 2916.860 573.960 ;
     RECT 2906.910 574.560 2916.860 579.400 ;
     RECT 2906.910 580.000 2916.860 584.840 ;
     RECT 2906.910 585.440 2916.860 590.280 ;
     RECT 2906.910 590.880 2916.860 595.720 ;
     RECT 2906.910 596.320 2916.860 601.160 ;
     RECT 2906.910 601.760 2916.860 606.600 ;
     RECT 2906.910 607.200 2916.860 612.040 ;
     RECT 2906.910 612.640 2916.860 617.480 ;
     RECT 2906.910 618.080 2916.860 622.920 ;
     RECT 2906.910 623.520 2916.860 628.360 ;
     RECT 2906.910 628.960 2916.860 633.800 ;
     RECT 2906.910 634.400 2916.860 639.240 ;
     RECT 2906.910 639.840 2916.860 644.680 ;
     RECT 2906.910 645.280 2916.860 650.120 ;
     RECT 2906.910 650.720 2916.860 655.560 ;
     RECT 2906.910 656.160 2916.860 661.000 ;
     RECT 2906.910 661.600 2916.860 666.440 ;
     RECT 2906.910 661.000 2916.000 661.600 ;
     RECT 2906.910 655.560 2916.000 656.160 ;
     RECT 2906.910 650.120 2916.000 650.720 ;
     RECT 2906.910 644.680 2916.000 645.280 ;
     RECT 2906.910 639.240 2916.000 639.840 ;
     RECT 2906.910 633.800 2916.000 634.400 ;
     RECT 2906.910 628.360 2916.000 628.960 ;
     RECT 2906.910 622.920 2916.000 623.520 ;
     RECT 2906.910 617.480 2916.000 618.080 ;
     RECT 2906.910 667.040 2916.860 671.880 ;
     RECT 2906.910 672.480 2916.860 677.320 ;
     RECT 2906.910 677.920 2916.860 682.760 ;
     RECT 2906.910 683.360 2916.860 688.200 ;
     RECT 2906.910 688.800 2916.860 693.640 ;
     RECT 2906.910 694.240 2916.860 699.080 ;
     RECT 2906.910 699.680 2916.860 704.520 ;
     RECT 2906.910 705.120 2916.860 709.960 ;
     RECT 2906.910 710.560 2916.860 715.400 ;
     RECT 2906.910 716.000 2916.860 720.840 ;
     RECT 2906.910 721.440 2916.860 726.280 ;
     RECT 2906.910 726.880 2916.860 731.720 ;
     RECT 2906.910 732.320 2916.860 737.160 ;
     RECT 2906.910 737.760 2916.860 742.600 ;
     RECT 2906.910 743.200 2916.860 748.040 ;
     RECT 2906.910 748.640 2916.860 753.480 ;
     RECT 2906.910 754.080 2916.860 758.920 ;
     RECT 2906.910 759.520 2916.860 764.360 ;
     RECT 2906.910 764.960 2916.860 769.800 ;
     RECT 2906.910 770.400 2916.860 775.240 ;
     RECT 2906.910 775.840 2916.860 780.680 ;
     RECT 2906.910 781.280 2916.860 786.120 ;
     RECT 2906.910 786.720 2916.860 791.560 ;
     RECT 2906.910 792.160 2916.860 797.000 ;
     RECT 2906.910 797.600 2916.860 802.440 ;
     RECT 2906.910 803.040 2916.860 807.880 ;
     RECT 2906.910 808.480 2916.860 813.320 ;
     RECT 2906.910 813.920 2916.860 818.760 ;
     RECT 2906.910 819.360 2916.860 824.200 ;
     RECT 2906.910 824.800 2916.860 829.640 ;
     RECT 2906.910 830.240 2916.860 835.080 ;
     RECT 2906.910 835.680 2916.860 840.520 ;
     RECT 2906.910 841.120 2916.860 845.960 ;
     RECT 2906.910 846.560 2916.860 851.400 ;
     RECT 2906.910 845.960 2916.000 846.560 ;
     RECT 2906.910 840.520 2916.000 841.120 ;
     RECT 2906.910 835.080 2916.000 835.680 ;
     RECT 2906.910 829.640 2916.000 830.240 ;
     RECT 2906.910 824.200 2916.000 824.800 ;
     RECT 2906.910 818.760 2916.000 819.360 ;
     RECT 2906.910 813.320 2916.000 813.920 ;
     RECT 2906.910 807.880 2916.000 808.480 ;
     RECT 2906.910 802.440 2916.000 803.040 ;
     RECT 2906.910 797.000 2916.000 797.600 ;
     RECT 2906.910 791.560 2916.000 792.160 ;
     RECT 2906.910 786.120 2916.000 786.720 ;
     RECT 2906.910 780.680 2916.000 781.280 ;
     RECT 2906.910 775.240 2916.000 775.840 ;
     RECT 2906.910 769.800 2916.000 770.400 ;
     RECT 2906.910 764.360 2916.000 764.960 ;
     RECT 2906.910 758.920 2916.000 759.520 ;
     RECT 2906.910 753.480 2916.000 754.080 ;
     RECT 2906.910 748.040 2916.000 748.640 ;
     RECT 2906.910 742.600 2916.000 743.200 ;
     RECT 2906.910 737.160 2916.000 737.760 ;
     RECT 2906.910 731.720 2916.000 732.320 ;
     RECT 2906.910 726.280 2916.000 726.880 ;
     RECT 2906.910 720.840 2916.000 721.440 ;
     RECT 2906.910 715.400 2916.000 716.000 ;
     RECT 2906.910 709.960 2916.000 710.560 ;
     RECT 2906.910 704.520 2916.000 705.120 ;
     RECT 2906.910 699.080 2916.000 699.680 ;
     RECT 2906.910 693.640 2916.000 694.240 ;
     RECT 2906.910 688.200 2916.000 688.800 ;
     RECT 2906.910 682.760 2916.000 683.360 ;
     RECT 2906.910 677.320 2916.000 677.920 ;
     RECT 2906.910 671.880 2916.000 672.480 ;
     RECT 2906.910 666.440 2916.000 667.040 ;
     RECT 2906.910 612.040 2916.000 612.640 ;
     RECT 2906.910 606.600 2916.000 607.200 ;
     RECT 2906.910 601.160 2916.000 601.760 ;
     RECT 2906.910 595.720 2916.000 596.320 ;
     RECT 2906.910 590.280 2916.000 590.880 ;
     RECT 2906.910 584.840 2916.000 585.440 ;
     RECT 2906.910 579.400 2916.000 580.000 ;
     RECT 2906.910 573.960 2916.000 574.560 ;
     RECT 2906.910 568.520 2916.000 569.120 ;
     RECT 2906.910 563.080 2916.000 563.680 ;
     RECT 2906.910 557.640 2916.000 558.240 ;
     RECT 2906.910 552.200 2916.000 552.800 ;
     RECT 2906.910 546.760 2916.000 547.360 ;
     RECT 2906.910 541.320 2916.000 541.920 ;
     RECT 2906.910 535.880 2916.000 536.480 ;
     RECT 2906.910 530.440 2916.000 531.040 ;
     RECT 2906.910 525.000 2916.000 525.600 ;
     RECT 2906.910 519.560 2916.000 520.160 ;
     RECT 2906.910 514.120 2916.000 514.720 ;
     RECT 2906.910 508.680 2916.000 509.280 ;
     RECT 2906.910 503.240 2916.000 503.840 ;
     RECT 2906.910 497.800 2916.000 498.400 ;
     RECT 2906.910 492.360 2916.000 492.960 ;
     RECT 2906.910 486.920 2916.000 487.520 ;
     RECT 2906.910 481.480 2916.000 482.080 ;
     RECT 2906.910 476.040 2916.000 476.640 ;
     RECT 2906.910 470.600 2916.000 471.200 ;
     RECT 2906.910 465.160 2916.000 465.760 ;
     RECT 2906.910 459.720 2916.000 460.320 ;
     RECT 2906.910 454.280 2916.000 454.880 ;
     RECT 2906.910 448.840 2916.000 449.440 ;
     RECT 2906.910 443.400 2916.000 444.000 ;
     RECT 2906.910 437.960 2916.000 438.560 ;
     RECT 2906.910 432.520 2916.000 433.120 ;
     RECT 2906.910 427.080 2916.000 427.680 ;
     RECT 2906.910 372.680 2916.000 373.280 ;
     RECT 2906.910 367.240 2916.000 367.840 ;
     RECT 2906.910 361.800 2916.000 362.400 ;
     RECT 2906.910 356.360 2916.000 356.960 ;
     RECT 2906.910 350.920 2916.000 351.520 ;
     RECT 2906.910 345.480 2916.000 346.080 ;
     RECT 2906.910 340.040 2916.000 340.640 ;
     RECT 2906.910 334.600 2916.000 335.200 ;
     RECT 2906.910 329.160 2916.000 329.760 ;
     RECT 2906.910 323.720 2916.000 324.320 ;
     RECT 2906.910 318.280 2916.000 318.880 ;
     RECT 2906.910 312.840 2916.000 313.440 ;
     RECT 2906.910 307.400 2916.000 308.000 ;
     RECT 2906.910 301.960 2916.000 302.560 ;
     RECT 2906.910 296.520 2916.000 297.120 ;
     RECT 2906.910 291.080 2916.000 291.680 ;
     RECT 2906.910 285.640 2916.000 286.240 ;
     RECT 2906.910 280.200 2916.000 280.800 ;
     RECT 2906.910 274.760 2916.000 275.360 ;
     RECT 2906.910 269.320 2916.000 269.920 ;
     RECT 2906.910 263.880 2916.000 264.480 ;
     RECT 2906.910 258.440 2916.000 259.040 ;
     RECT 2906.910 253.000 2916.000 253.600 ;
     RECT 2906.910 247.560 2916.000 248.160 ;
     RECT 2906.910 242.120 2916.000 242.720 ;
     RECT 2906.910 236.680 2916.000 237.280 ;
     RECT 2906.910 231.240 2916.000 231.840 ;
     RECT 2906.910 225.800 2916.000 226.400 ;
     RECT 2906.910 220.360 2916.000 220.960 ;
     RECT 2906.910 214.920 2916.000 215.520 ;
     RECT 2906.910 209.480 2916.000 210.080 ;
     RECT 2906.910 204.040 2916.000 204.640 ;
     RECT 2906.910 198.600 2916.000 199.200 ;
     RECT 2906.910 193.160 2916.000 193.760 ;
     RECT 2906.910 187.720 2916.000 188.320 ;
     RECT 2906.910 133.470 2916.000 133.920 ;
     RECT 2906.910 852.000 2916.860 856.840 ;
     RECT 2906.910 857.440 2916.860 862.280 ;
     RECT 2906.910 862.880 2916.860 867.720 ;
     RECT 2906.910 868.320 2916.860 873.160 ;
     RECT 2906.910 873.760 2916.860 878.600 ;
     RECT 2906.910 879.200 2916.860 884.040 ;
     RECT 2906.910 884.640 2916.860 889.480 ;
     RECT 2906.910 890.080 2916.860 894.920 ;
     RECT 2906.910 895.520 2916.860 900.360 ;
     RECT 2906.910 900.960 2916.860 905.800 ;
     RECT 2906.910 900.360 2916.000 900.960 ;
     RECT 2906.910 894.920 2916.000 895.520 ;
     RECT 2906.910 889.480 2916.000 890.080 ;
     RECT 2906.910 884.040 2916.000 884.640 ;
     RECT 2906.910 878.600 2916.000 879.200 ;
     RECT 2906.910 873.160 2916.000 873.760 ;
     RECT 2906.910 867.720 2916.000 868.320 ;
     RECT 2906.910 862.280 2916.000 862.880 ;
     RECT 2906.910 856.840 2916.000 857.440 ;
     RECT 2906.910 906.400 2916.860 911.240 ;
     RECT 2906.910 911.840 2916.860 916.680 ;
     RECT 2906.910 917.280 2916.860 922.120 ;
     RECT 2906.910 922.720 2916.860 927.560 ;
     RECT 2906.910 928.160 2916.860 933.000 ;
     RECT 2906.910 933.600 2916.860 938.440 ;
     RECT 2906.910 939.040 2916.860 943.880 ;
     RECT 2906.910 944.480 2916.860 949.320 ;
     RECT 2906.910 949.920 2916.860 954.760 ;
     RECT 2906.910 955.360 2916.860 960.200 ;
     RECT 2906.910 960.800 2916.860 965.640 ;
     RECT 2906.910 966.240 2916.860 971.080 ;
     RECT 2906.910 971.680 2916.860 976.520 ;
     RECT 2906.910 977.120 2916.860 981.960 ;
     RECT 2906.910 982.560 2916.860 987.400 ;
     RECT 2906.910 988.000 2916.860 992.840 ;
     RECT 2906.910 993.440 2916.860 998.280 ;
     RECT 2906.910 998.880 2916.860 1003.720 ;
     RECT 2906.910 1004.320 2916.860 1009.160 ;
     RECT 2906.910 1009.760 2916.860 1014.600 ;
     RECT 2906.910 1015.200 2916.860 1020.040 ;
     RECT 2906.910 1020.640 2916.860 1025.480 ;
     RECT 2906.910 1026.080 2916.860 1030.920 ;
     RECT 2906.910 1031.520 2916.860 1036.360 ;
     RECT 2906.910 1036.960 2916.860 1041.800 ;
     RECT 2906.910 1042.400 2916.860 1047.240 ;
     RECT 2906.910 1047.840 2916.860 1052.680 ;
     RECT 2906.910 1053.280 2916.860 1058.120 ;
     RECT 2906.910 1058.720 2916.860 1063.560 ;
     RECT 2906.910 1064.160 2916.860 1069.000 ;
     RECT 2906.910 1069.600 2916.860 1074.440 ;
     RECT 2906.910 1075.040 2916.860 1079.880 ;
     RECT 2906.910 1080.480 2916.860 1085.320 ;
     RECT 2906.910 1085.920 2916.860 1090.760 ;
     RECT 2906.910 1091.360 2916.860 1096.200 ;
     RECT 2906.910 1096.800 2916.860 1101.640 ;
     RECT 2906.910 1102.240 2916.860 1107.080 ;
     RECT 2906.910 1107.680 2916.860 1112.520 ;
     RECT 2906.910 1113.120 2916.860 1117.960 ;
     RECT 2906.910 1118.560 2916.860 1123.400 ;
     RECT 2906.910 1124.000 2916.860 1128.840 ;
     RECT 2906.910 1129.440 2916.860 1134.280 ;
     RECT 2906.910 1134.880 2916.860 1139.720 ;
     RECT 2906.910 1140.320 2916.860 1145.160 ;
     RECT 2906.910 1139.720 2916.000 1140.320 ;
     RECT 2906.910 1134.280 2916.000 1134.880 ;
     RECT 2906.910 1128.840 2916.000 1129.440 ;
     RECT 2906.910 1123.400 2916.000 1124.000 ;
     RECT 2906.910 1117.960 2916.000 1118.560 ;
     RECT 2906.910 1112.520 2916.000 1113.120 ;
     RECT 2906.910 1107.080 2916.000 1107.680 ;
     RECT 2906.910 1101.640 2916.000 1102.240 ;
     RECT 2906.910 1096.200 2916.000 1096.800 ;
     RECT 2906.910 1145.760 2916.860 1150.600 ;
     RECT 2906.910 1151.200 2916.860 1156.040 ;
     RECT 2906.910 1156.640 2916.860 1161.480 ;
     RECT 2906.910 1162.080 2916.860 1166.920 ;
     RECT 2906.910 1167.520 2916.860 1172.360 ;
     RECT 2906.910 1172.960 2916.860 1177.800 ;
     RECT 2906.910 1178.400 2916.860 1183.240 ;
     RECT 2906.910 1183.840 2916.860 1188.680 ;
     RECT 2906.910 1189.280 2916.860 1194.120 ;
     RECT 2906.910 1194.720 2916.860 1199.560 ;
     RECT 2906.910 1200.160 2916.860 1205.000 ;
     RECT 2906.910 1205.600 2916.860 1210.440 ;
     RECT 2906.910 1211.040 2916.860 1215.880 ;
     RECT 2906.910 1216.480 2916.860 1221.320 ;
     RECT 2906.910 1221.920 2916.860 1226.760 ;
     RECT 2906.910 1227.360 2916.860 1232.200 ;
     RECT 2906.910 1232.800 2916.860 1237.640 ;
     RECT 2906.910 1238.240 2916.860 1243.080 ;
     RECT 2906.910 1243.680 2916.860 1248.520 ;
     RECT 2906.910 1249.120 2916.860 1253.960 ;
     RECT 2906.910 1254.560 2916.860 1259.400 ;
     RECT 2906.910 1260.000 2916.860 1264.840 ;
     RECT 2906.910 1265.440 2916.860 1270.280 ;
     RECT 2906.910 1270.880 2916.860 1275.720 ;
     RECT 2906.910 1276.320 2916.860 1281.160 ;
     RECT 2906.910 1281.760 2916.860 1286.600 ;
     RECT 2906.910 1287.200 2916.860 1292.040 ;
     RECT 2906.910 1292.640 2916.860 1297.480 ;
     RECT 2906.910 1298.080 2916.860 1302.920 ;
     RECT 2906.910 1303.520 2916.860 1308.360 ;
     RECT 2906.910 1308.960 2916.860 1313.800 ;
     RECT 2906.910 1314.400 2916.860 1319.240 ;
     RECT 2906.910 1319.840 2916.860 1324.680 ;
     RECT 2906.910 1325.280 2916.860 1330.120 ;
     RECT 2906.910 1324.680 2916.000 1325.280 ;
     RECT 2906.910 1319.240 2916.000 1319.840 ;
     RECT 2906.910 1313.800 2916.000 1314.400 ;
     RECT 2906.910 1308.360 2916.000 1308.960 ;
     RECT 2906.910 1302.920 2916.000 1303.520 ;
     RECT 2906.910 1297.480 2916.000 1298.080 ;
     RECT 2906.910 1292.040 2916.000 1292.640 ;
     RECT 2906.910 1286.600 2916.000 1287.200 ;
     RECT 2906.910 1281.160 2916.000 1281.760 ;
     RECT 2906.910 1275.720 2916.000 1276.320 ;
     RECT 2906.910 1270.280 2916.000 1270.880 ;
     RECT 2906.910 1264.840 2916.000 1265.440 ;
     RECT 2906.910 1259.400 2916.000 1260.000 ;
     RECT 2906.910 1253.960 2916.000 1254.560 ;
     RECT 2906.910 1248.520 2916.000 1249.120 ;
     RECT 2906.910 1243.080 2916.000 1243.680 ;
     RECT 2906.910 1237.640 2916.000 1238.240 ;
     RECT 2906.910 1232.200 2916.000 1232.800 ;
     RECT 2906.910 1226.760 2916.000 1227.360 ;
     RECT 2906.910 1221.320 2916.000 1221.920 ;
     RECT 2906.910 1215.880 2916.000 1216.480 ;
     RECT 2906.910 1210.440 2916.000 1211.040 ;
     RECT 2906.910 1205.000 2916.000 1205.600 ;
     RECT 2906.910 1199.560 2916.000 1200.160 ;
     RECT 2906.910 1194.120 2916.000 1194.720 ;
     RECT 2906.910 1188.680 2916.000 1189.280 ;
     RECT 2906.910 1183.240 2916.000 1183.840 ;
     RECT 2906.910 1177.800 2916.000 1178.400 ;
     RECT 2906.910 1172.360 2916.000 1172.960 ;
     RECT 2906.910 1166.920 2916.000 1167.520 ;
     RECT 2906.910 1161.480 2916.000 1162.080 ;
     RECT 2906.910 1156.040 2916.000 1156.640 ;
     RECT 2906.910 1150.600 2916.000 1151.200 ;
     RECT 2906.910 1145.160 2916.000 1145.760 ;
     RECT 2906.910 1090.760 2916.000 1091.360 ;
     RECT 2906.910 1330.720 2916.860 1335.560 ;
     RECT 2906.910 1336.160 2916.860 1341.000 ;
     RECT 2906.910 1341.600 2916.860 1346.440 ;
     RECT 2906.910 1347.040 2916.860 1351.880 ;
     RECT 2906.910 1352.480 2916.860 1357.320 ;
     RECT 2906.910 1357.920 2916.860 1362.760 ;
     RECT 2906.910 1363.360 2916.860 1368.200 ;
     RECT 2906.910 1368.800 2916.860 1373.640 ;
     RECT 2906.910 1374.240 2916.860 1379.080 ;
     RECT 2906.910 1379.680 2916.860 1384.520 ;
     RECT 2906.910 1379.080 2916.000 1379.680 ;
     RECT 2906.910 1373.640 2916.000 1374.240 ;
     RECT 2906.910 1368.200 2916.000 1368.800 ;
     RECT 2906.910 1362.760 2916.000 1363.360 ;
     RECT 2906.910 1357.320 2916.000 1357.920 ;
     RECT 2906.910 1351.880 2916.000 1352.480 ;
     RECT 2906.910 1346.440 2916.000 1347.040 ;
     RECT 2906.910 1341.000 2916.000 1341.600 ;
     RECT 2906.910 1335.560 2916.000 1336.160 ;
     RECT 2906.910 1385.120 2916.860 1389.960 ;
     RECT 2906.910 1390.560 2916.860 1395.400 ;
     RECT 2906.910 1396.000 2916.860 1400.840 ;
     RECT 2906.910 1401.440 2916.860 1406.280 ;
     RECT 2906.910 1406.880 2916.860 1411.720 ;
     RECT 2906.910 1412.320 2916.860 1417.160 ;
     RECT 2906.910 1417.760 2916.860 1422.600 ;
     RECT 2906.910 1423.200 2916.860 1428.040 ;
     RECT 2906.910 1428.640 2916.860 1433.480 ;
     RECT 2906.910 1434.080 2916.860 1438.920 ;
     RECT 2906.910 1439.520 2916.860 1444.360 ;
     RECT 2906.910 1444.960 2916.860 1449.800 ;
     RECT 2906.910 1450.400 2916.860 1455.240 ;
     RECT 2906.910 1455.840 2916.860 1460.680 ;
     RECT 2906.910 1461.280 2916.860 1466.120 ;
     RECT 2906.910 1466.720 2916.860 1471.560 ;
     RECT 2906.910 1472.160 2916.860 1477.000 ;
     RECT 2906.910 1477.600 2916.860 1482.440 ;
     RECT 2906.910 1483.040 2916.860 1487.880 ;
     RECT 2906.910 1488.480 2916.860 1493.320 ;
     RECT 2906.910 1493.920 2916.860 1498.760 ;
     RECT 2906.910 1499.360 2916.860 1504.200 ;
     RECT 2906.910 1504.800 2916.860 1509.640 ;
     RECT 2906.910 1510.240 2916.860 1515.080 ;
     RECT 2906.910 1515.680 2916.860 1520.520 ;
     RECT 2906.910 1521.120 2916.860 1525.960 ;
     RECT 2906.910 1526.560 2916.860 1531.400 ;
     RECT 2906.910 1532.000 2916.860 1536.840 ;
     RECT 2906.910 1537.440 2916.860 1542.280 ;
     RECT 2906.910 1542.880 2916.860 1547.720 ;
     RECT 2906.910 1548.320 2916.860 1553.160 ;
     RECT 2906.910 1553.760 2916.860 1558.600 ;
     RECT 2906.910 1559.200 2916.860 1564.040 ;
     RECT 2906.910 1564.040 2916.000 1564.490 ;
     RECT 2906.910 1558.600 2916.000 1559.200 ;
     RECT 2906.910 1553.160 2916.000 1553.760 ;
     RECT 2906.910 1547.720 2916.000 1548.320 ;
     RECT 2906.910 1542.280 2916.000 1542.880 ;
     RECT 2906.910 1536.840 2916.000 1537.440 ;
     RECT 2906.910 1531.400 2916.000 1532.000 ;
     RECT 2906.910 1525.960 2916.000 1526.560 ;
     RECT 2906.910 1520.520 2916.000 1521.120 ;
     RECT 2906.910 1515.080 2916.000 1515.680 ;
     RECT 2906.910 1509.640 2916.000 1510.240 ;
     RECT 2906.910 1504.200 2916.000 1504.800 ;
     RECT 2906.910 1498.760 2916.000 1499.360 ;
     RECT 2906.910 1493.320 2916.000 1493.920 ;
     RECT 2906.910 1487.880 2916.000 1488.480 ;
     RECT 2906.910 1482.440 2916.000 1483.040 ;
     RECT 2906.910 1477.000 2916.000 1477.600 ;
     RECT 2906.910 1471.560 2916.000 1472.160 ;
     RECT 2906.910 1466.120 2916.000 1466.720 ;
     RECT 2906.910 1460.680 2916.000 1461.280 ;
     RECT 2906.910 1455.240 2916.000 1455.840 ;
     RECT 2906.910 1449.800 2916.000 1450.400 ;
     RECT 2906.910 1444.360 2916.000 1444.960 ;
     RECT 2906.910 1438.920 2916.000 1439.520 ;
     RECT 2906.910 1433.480 2916.000 1434.080 ;
     RECT 2906.910 1428.040 2916.000 1428.640 ;
     RECT 2906.910 1422.600 2916.000 1423.200 ;
     RECT 2906.910 1417.160 2916.000 1417.760 ;
     RECT 2906.910 1411.720 2916.000 1412.320 ;
     RECT 2906.910 1406.280 2916.000 1406.880 ;
     RECT 2906.910 1400.840 2916.000 1401.440 ;
     RECT 2906.910 1395.400 2916.000 1396.000 ;
     RECT 2906.910 1389.960 2916.000 1390.560 ;
     RECT 2906.910 1384.520 2916.000 1385.120 ;
     RECT 2906.910 1330.120 2916.000 1330.720 ;
     RECT 2906.910 1085.320 2916.000 1085.920 ;
     RECT 2906.910 1079.880 2916.000 1080.480 ;
     RECT 2906.910 1074.440 2916.000 1075.040 ;
     RECT 2906.910 1069.000 2916.000 1069.600 ;
     RECT 2906.910 1063.560 2916.000 1064.160 ;
     RECT 2906.910 1058.120 2916.000 1058.720 ;
     RECT 2906.910 1052.680 2916.000 1053.280 ;
     RECT 2906.910 1047.240 2916.000 1047.840 ;
     RECT 2906.910 1041.800 2916.000 1042.400 ;
     RECT 2906.910 1036.360 2916.000 1036.960 ;
     RECT 2906.910 1030.920 2916.000 1031.520 ;
     RECT 2906.910 1025.480 2916.000 1026.080 ;
     RECT 2906.910 1020.040 2916.000 1020.640 ;
     RECT 2906.910 1014.600 2916.000 1015.200 ;
     RECT 2906.910 1009.160 2916.000 1009.760 ;
     RECT 2906.910 1003.720 2916.000 1004.320 ;
     RECT 2906.910 998.280 2916.000 998.880 ;
     RECT 2906.910 992.840 2916.000 993.440 ;
     RECT 2906.910 987.400 2916.000 988.000 ;
     RECT 2906.910 981.960 2916.000 982.560 ;
     RECT 2906.910 976.520 2916.000 977.120 ;
     RECT 2906.910 971.080 2916.000 971.680 ;
     RECT 2906.910 965.640 2916.000 966.240 ;
     RECT 2906.910 960.200 2916.000 960.800 ;
     RECT 2906.910 954.760 2916.000 955.360 ;
     RECT 2906.910 949.320 2916.000 949.920 ;
     RECT 2906.910 943.880 2916.000 944.480 ;
     RECT 2906.910 938.440 2916.000 939.040 ;
     RECT 2906.910 933.000 2916.000 933.600 ;
     RECT 2906.910 927.560 2916.000 928.160 ;
     RECT 2906.910 922.120 2916.000 922.720 ;
     RECT 2906.910 916.680 2916.000 917.280 ;
     RECT 2906.910 911.240 2916.000 911.840 ;
     RECT 2906.910 905.800 2916.000 906.400 ;
     RECT 2906.910 851.400 2916.000 852.000 ;
    LAYER met4 ;
     RECT 2712.070 10.640 2723.970 63.430 ;
     RECT 192.070 10.640 203.970 132.110 ;
     RECT 2712.070 63.430 2723.970 132.110 ;
     RECT 2727.070 63.430 2733.010 132.110 ;
     RECT  130.03 0.87 130.33 134.15 ;
     RECT  130.03 134.15 137.69 134.83 ;
     RECT  2788.83 134.15 2789.13 134.83 ;
     RECT  2788.83 134.83 2795.57 136.87 ;
     RECT  88.63 136.87 88.93 137.55 ;
     RECT  2788.83 136.87 2796.49 137.55 ;
     RECT  123.59 134.83 137.69 142.99 ;
     RECT 186.150 142.000 203.970 147.070 ;
     RECT 186.150 132.110 188.970 142.000 ;
     RECT 192.070 132.110 203.970 142.000 ;
     RECT  2767.67 143.67 2767.97 147.75 ;
     RECT  2787.91 137.55 2796.49 147.75 ;
     RECT  2767.67 147.75 2796.49 148.43 ;
     RECT  74.83 137.55 88.93 150.47 ;
     RECT 186.150 147.070 203.970 152.700 ;
     RECT 207.070 147.070 208.530 152.700 ;
     RECT 372.070 142.000 387.070 152.700 ;
     RECT 372.070 10.640 383.970 142.000 ;
     RECT 552.070 10.640 563.970 152.700 ;
     RECT 732.070 10.640 743.970 152.700 ;
     RECT 912.070 142.000 927.070 152.700 ;
     RECT 912.070 10.640 923.970 142.000 ;
     RECT 1088.970 142.000 1103.970 152.700 ;
     RECT 1092.070 10.640 1103.970 142.000 ;
     RECT 1272.070 142.000 1287.070 152.700 ;
     RECT 1272.070 10.640 1283.970 142.000 ;
     RECT 1452.070 10.640 1463.970 152.700 ;
     RECT 1632.070 10.640 1643.970 152.700 ;
     RECT 1812.070 142.000 1827.070 152.700 ;
     RECT 1812.070 10.640 1823.970 142.000 ;
     RECT 1988.970 142.000 2003.970 152.700 ;
     RECT 1992.070 10.640 2003.970 142.000 ;
     RECT 2172.070 142.000 2187.070 152.700 ;
     RECT 2172.070 10.640 2183.970 142.000 ;
     RECT 2352.070 10.640 2363.970 152.700 ;
     RECT 2532.070 10.640 2543.970 152.700 ;
     RECT 2712.070 142.000 2736.690 152.700 ;
     RECT 2712.070 132.110 2723.970 142.000 ;
     RECT 2727.070 132.110 2736.690 142.000 ;
     RECT  2625.64 152.7 2638.84 153.19 ;
     RECT  74.83 150.47 101.81 157.95 ;
     RECT 2712.070 152.700 2738.840 158.630 ;
     RECT 175.640 164.255 238.840 174.655 ;
     RECT 175.640 152.700 203.970 164.255 ;
     RECT 207.070 152.700 238.840 164.255 ;
     RECT  275.64 152.7 288.84 174.655 ;
     RECT  325.64 152.7 338.84 174.655 ;
     RECT 368.970 164.255 388.840 174.655 ;
     RECT 372.070 152.700 388.840 164.255 ;
     RECT  425.64 152.7 438.84 174.655 ;
     RECT  475.64 152.7 488.84 174.655 ;
     RECT 525.640 164.255 588.840 174.655 ;
     RECT 525.640 152.700 548.970 164.255 ;
     RECT 552.070 152.700 563.970 164.255 ;
     RECT 567.070 152.700 588.840 164.255 ;
     RECT  625.64 152.7 638.84 174.655 ;
     RECT  675.64 152.7 688.84 174.655 ;
     RECT 725.640 164.255 747.070 174.655 ;
     RECT 725.640 152.700 728.970 164.255 ;
     RECT 732.070 152.700 743.970 164.255 ;
     RECT  775.64 152.7 788.84 174.655 ;
     RECT  825.64 152.7 838.84 174.655 ;
     RECT  875.64 152.7 888.84 174.655 ;
     RECT 908.970 164.255 938.840 174.655 ;
     RECT 912.070 152.700 938.840 164.255 ;
     RECT  975.64 152.7 988.84 174.655 ;
     RECT  1025.64 152.7 1038.84 174.655 ;
     RECT 1075.640 164.255 1107.070 174.655 ;
     RECT 1075.640 152.700 1103.970 164.255 ;
     RECT  1125.64 152.7 1138.84 174.655 ;
     RECT  1175.64 152.7 1188.84 174.655 ;
     RECT  1225.64 152.7 1238.84 174.655 ;
     RECT 1268.970 164.255 1288.840 174.655 ;
     RECT 1272.070 152.700 1288.840 164.255 ;
     RECT  1325.64 152.7 1338.84 174.655 ;
     RECT  1375.64 152.7 1388.84 174.655 ;
     RECT 1425.640 164.255 1488.840 174.655 ;
     RECT 1425.640 152.700 1448.970 164.255 ;
     RECT 1452.070 152.700 1463.970 164.255 ;
     RECT 1467.070 152.700 1488.840 164.255 ;
     RECT  1525.64 152.7 1538.84 174.655 ;
     RECT  1575.64 152.7 1588.84 174.655 ;
     RECT 1625.640 164.255 1647.070 174.655 ;
     RECT 1625.640 152.700 1628.970 164.255 ;
     RECT 1632.070 152.700 1643.970 164.255 ;
     RECT  1675.64 152.7 1688.84 174.655 ;
     RECT  1725.64 152.7 1738.84 174.655 ;
     RECT  1775.64 152.7 1788.84 174.655 ;
     RECT 1808.970 164.255 1838.840 174.655 ;
     RECT 1812.070 152.700 1838.840 164.255 ;
     RECT  1875.64 152.7 1888.84 174.655 ;
     RECT  1925.64 152.7 1938.84 174.655 ;
     RECT 1975.640 164.255 2007.070 174.655 ;
     RECT 1975.640 152.700 2003.970 164.255 ;
     RECT  2025.64 152.7 2038.84 174.655 ;
     RECT  2075.64 152.7 2088.84 174.655 ;
     RECT  2125.64 152.7 2138.84 174.655 ;
     RECT 2168.970 164.255 2188.840 174.655 ;
     RECT 2172.070 152.700 2188.840 164.255 ;
     RECT  2225.64 152.7 2238.84 174.655 ;
     RECT  2275.64 152.7 2288.84 174.655 ;
     RECT 2325.640 164.255 2388.840 174.655 ;
     RECT 2325.640 152.700 2348.970 164.255 ;
     RECT 2352.070 152.700 2363.970 164.255 ;
     RECT 2367.070 152.700 2388.840 164.255 ;
     RECT  2425.64 152.7 2438.84 174.655 ;
     RECT  2475.64 152.7 2488.84 174.655 ;
     RECT 2525.640 164.255 2547.070 174.655 ;
     RECT 2525.640 152.700 2528.970 164.255 ;
     RECT 2532.070 152.700 2543.970 164.255 ;
     RECT  2575.64 152.7 2588.84 174.655 ;
     RECT  2625.64 153.19 2656.65 174.655 ;
     RECT  2675.64 152.7 2688.84 174.655 ;
     RECT 2708.970 164.255 2740.370 174.655 ;
     RECT 2712.070 158.630 2740.370 164.255 ;
     RECT 12.070 10.640 23.970 193.990 ;
     RECT 2892.070 10.640 2903.970 240.910 ;
     RECT  2763.99 148.43 2796.49 251.11 ;
     RECT  2763.99 251.11 2811.21 340.87 ;
     RECT  2763.99 340.87 2819.49 358.85 ;
     RECT  2765.58 358.85 2819.49 409.55 ;
     RECT 12.070 193.990 23.970 551.670 ;
     RECT 27.070 193.990 37.410 551.670 ;
     RECT  2763.07 409.55 2819.49 586.35 ;
     RECT 12.070 551.670 23.970 589.750 ;
     RECT 27.070 551.670 47.530 589.750 ;
     RECT  2760.31 586.35 2819.49 609.09 ;
     RECT  2763.07 609.09 2819.49 641.43 ;
     RECT 2892.070 240.910 2903.970 646.870 ;
     RECT 2907.070 240.910 2910.570 646.870 ;
     RECT  2763.07 641.43 2822.25 663.19 ;
     RECT  2849.55 652.31 2849.85 663.19 ;
     RECT  2763.07 663.19 2849.85 706.71 ;
     RECT 12.070 589.750 23.970 759.150 ;
     RECT 27.070 589.750 54.890 759.150 ;
     RECT  175.64 174.655 2740.37 803.95 ;
     RECT  2763.07 706.71 2850.77 803.95 ;
     RECT 12.070 759.150 23.970 810.070 ;
     RECT 27.070 759.150 53.970 810.070 ;
     RECT  74.83 157.95 102.73 810.07 ;
     RECT  175.64 803.95 2850.77 966.02 ;
     RECT  186.15 966.02 2850.77 967.865 ;
     RECT  123.59 142.99 155.17 969.19 ;
     RECT  123.59 969.19 157.01 974.25 ;
     RECT  261.59 967.865 290.41 981.05 ;
     RECT 186.150 967.865 207.070 976.720 ;
     RECT 186.150 976.720 188.970 982.410 ;
     RECT 192.070 976.720 207.070 978.265 ;
     RECT 192.070 978.265 203.970 982.410 ;
     RECT 12.070 810.070 23.970 983.090 ;
     RECT 27.070 810.070 102.730 983.090 ;
     RECT  60.11 983.09 102.73 984.45 ;
     RECT  261.59 981.05 279.37 986.49 ;
     RECT 2168.970 967.865 2187.070 978.265 ;
     RECT 2172.070 978.265 2183.970 987.550 ;
     RECT 368.970 967.865 387.070 978.265 ;
     RECT 372.070 978.265 383.970 990.270 ;
     RECT 2892.070 646.870 2903.970 996.690 ;
     RECT 2907.070 646.870 2911.490 996.690 ;
     RECT 360.030 990.270 368.970 1001.150 ;
     RECT 372.070 990.270 383.970 1001.150 ;
     RECT  468.59 997.75 468.89 1001.15 ;
     RECT 12.070 983.090 23.970 1001.450 ;
     RECT 27.070 983.090 37.410 1001.450 ;
     RECT  1380.31 967.865 1380.61 1001.45 ;
     RECT  310.35 1001.15 324.45 1007.27 ;
     RECT  468.59 1001.15 471.65 1007.57 ;
     RECT 358.190 1001.150 368.970 1008.250 ;
     RECT 372.070 1001.150 383.970 1008.250 ;
     RECT 360.030 1008.250 368.970 1008.930 ;
     RECT 372.070 1008.250 383.970 1008.930 ;
     RECT  310.35 1007.27 325.37 1009.61 ;
     RECT 365.550 1008.930 368.970 1011.650 ;
     RECT 372.070 1008.930 383.970 1011.650 ;
     RECT  279.07 986.49 279.37 1014.07 ;
     RECT  324.15 1009.61 325.37 1014.75 ;
     RECT  275.39 1014.07 279.37 1020.19 ;
     RECT  275.39 1020.19 296.85 1021.55 ;
     RECT  630.51 1004.55 630.81 1022.48 ;
     RECT 728.970 967.865 747.070 978.265 ;
     RECT 732.070 978.265 743.970 1022.480 ;
     RECT 188.970 1021.335 207.070 1022.910 ;
     RECT 192.070 982.410 203.970 1021.335 ;
     RECT  260.67 1021.55 296.85 1022.91 ;
     RECT  72.07 984.45 102.73 1027.67 ;
     RECT 2892.070 996.690 2903.970 1030.010 ;
     RECT 2907.070 996.690 2910.570 1030.010 ;
     RECT  123.59 974.25 155.17 1030.64 ;
     RECT  188.97 1022.91 218.65 1030.64 ;
     RECT 368.970 1021.335 387.070 1030.640 ;
     RECT 372.070 1011.650 383.970 1021.335 ;
     RECT  468.59 1007.57 468.89 1030.64 ;
     RECT  123.59 1030.64 218.65 1031.735 ;
     RECT  245.03 1022.91 296.85 1031.735 ;
     RECT  324.15 1014.75 338.25 1031.735 ;
     RECT  363.04 1030.64 403.04 1031.735 ;
     RECT  439.84 1030.64 441.44 1031.735 ;
     RECT  468.59 1030.64 479.84 1031.735 ;
     RECT  516.64 1030.64 518.24 1031.735 ;
     RECT 548.970 967.865 567.070 978.265 ;
     RECT 548.970 1021.335 563.970 1031.735 ;
     RECT 552.070 978.265 563.970 1021.335 ;
     RECT 594.490 1006.160 607.030 1038.550 ;
     RECT 630.510 1022.480 728.970 1038.550 ;
     RECT 732.070 1022.480 743.970 1038.550 ;
     RECT 2167.830 987.550 2168.970 1042.250 ;
     RECT 2172.070 987.550 2183.970 1042.250 ;
     RECT  1127.31 1031.75 1127.61 1043.61 ;
     RECT 594.490 1038.550 607.030 1059.250 ;
     RECT 610.130 1038.550 728.970 1059.250 ;
     RECT 732.070 1038.550 743.970 1059.250 ;
     RECT  889.95 1058.95 890.25 1066.05 ;
     RECT  767.59 1058.95 767.89 1077.61 ;
     RECT 123.590 1031.735 563.970 1087.130 ;
     RECT 2694.070 967.865 2850.770 978.265 ;
     RECT 2694.070 978.265 2708.970 1087.130 ;
     RECT 2712.070 978.265 2723.970 1087.130 ;
     RECT 2727.070 978.265 2850.770 1087.130 ;
     RECT 2694.070 1087.130 2708.970 1103.450 ;
     RECT 2712.070 1087.130 2723.970 1103.450 ;
     RECT 2727.070 1087.130 2728.410 1103.450 ;
     RECT 630.510 1059.250 728.970 1112.720 ;
     RECT 732.070 1059.250 743.970 1112.720 ;
     RECT 2694.070 1103.450 2708.970 1114.710 ;
     RECT 2712.070 1103.450 2723.970 1114.710 ;
     RECT  2652.67 967.865 2652.97 1129.67 ;
     RECT 2683.950 1114.710 2708.970 1129.970 ;
     RECT 2712.070 1114.710 2723.970 1129.970 ;
     RECT 594.490 1059.250 607.030 1134.480 ;
     RECT  55.51 1027.67 102.73 1157.55 ;
     RECT  51.83 1157.55 102.73 1187.09 ;
     RECT  55.51 1187.09 102.73 1193.21 ;
     RECT  55.51 1193.21 88.93 1201.37 ;
     RECT  123.59 1087.13 137.69 1209.53 ;
     RECT  2645.31 1129.67 2652.97 1214.29 ;
     RECT  123.59 1209.53 130.33 1217.69 ;
     RECT  55.51 1201.37 82.49 1228.95 ;
     RECT 2528.970 967.865 2547.070 978.265 ;
     RECT 2532.070 978.265 2543.970 1230.990 ;
     RECT  2618.63 1213.99 2618.93 1231.29 ;
     RECT  130.03 1217.69 130.33 1241.87 ;
     RECT 2532.070 1230.990 2543.970 1246.930 ;
     RECT 2547.070 1230.990 2548.090 1246.930 ;
     RECT  123.59 1241.87 130.33 1258.19 ;
     RECT  109.79 1258.19 130.33 1266.35 ;
     RECT  54.59 1228.95 82.49 1274.51 ;
     RECT  109.79 1266.35 134.01 1274.51 ;
     RECT  2438.31 1246.63 2438.61 1293.85 ;
     RECT  54.59 1274.51 134.01 1307.15 ;
     RECT 159.495 1087.130 563.970 1328.230 ;
     RECT  54.59 1307.15 136.77 1339.79 ;
     RECT  54.59 1339.79 137.69 1347.95 ;
     RECT 159.495 1328.230 563.970 1347.950 ;
     RECT 567.070 1328.230 582.970 1347.950 ;
     RECT 54.590 1347.950 563.970 1390.790 ;
     RECT 567.070 1347.950 582.970 1390.790 ;
     RECT 54.590 1390.790 563.970 1443.150 ;
     RECT 567.070 1390.790 589.410 1443.150 ;
     RECT  2232.23 1466.95 2232.53 1480.85 ;
     RECT 2172.070 1042.250 2183.970 1524.750 ;
     RECT 49.070 1443.150 563.970 1554.985 ;
     RECT 567.070 1443.150 589.410 1554.985 ;
     RECT 2167.830 1524.750 2168.970 1555.650 ;
     RECT 2172.070 1524.750 2183.970 1555.650 ;
     RECT  49.07 1554.985 227.85 1558.8 ;
     RECT  247.84 1554.985 260.05 1558.8 ;
     RECT  286.24 1554.985 287.84 1558.8 ;
     RECT  324.64 1554.985 337.33 1558.8 ;
     RECT  363.04 1554.985 414.61 1558.8 ;
     RECT  439.84 1554.985 441.44 1558.8 ;
     RECT  478.24 1554.985 479.84 1558.8 ;
     RECT  516.43 1554.985 518.24 1558.8 ;
     RECT  226.63 1558.8 227.85 1562.45 ;
     RECT  516.43 1558.8 517.65 1565.85 ;
     RECT  226.63 1562.45 226.93 1567.89 ;
     RECT  516.43 1565.85 516.73 1568.57 ;
     RECT 536.670 1554.985 563.970 1565.385 ;
     RECT 567.070 1554.985 589.410 1565.385 ;
     RECT 536.670 1565.385 548.970 1568.570 ;
     RECT 552.070 1565.385 563.970 1568.570 ;
     RECT 567.070 1565.385 589.410 1568.570 ;
     RECT 536.670 1568.570 548.970 1569.930 ;
     RECT 552.070 1568.570 563.970 1569.930 ;
     RECT 567.070 1568.570 582.970 1569.930 ;
     RECT  409.71 1558.8 414.61 1576.05 ;
     RECT  2749.27 1087.13 2850.77 1576.05 ;
     RECT  337.03 1558.8 337.33 1582.85 ;
     RECT  2652.67 1214.29 2652.97 1582.85 ;
     RECT  259.75 1558.8 260.05 1589.65 ;
     RECT 2694.070 1129.970 2708.970 1589.650 ;
     RECT 2712.070 1129.970 2723.970 1589.650 ;
     RECT 536.670 1569.930 548.970 1592.370 ;
     RECT 552.070 1569.930 563.970 1592.370 ;
     RECT 567.070 1569.930 580.210 1592.370 ;
     RECT  409.71 1576.05 410.01 1594.41 ;
     RECT  49.07 1558.8 161.61 1601.21 ;
     RECT  2761.23 1576.05 2850.77 1606.65 ;
     RECT  2821.95 1606.65 2850.77 1608.69 ;
     RECT  2761.23 1606.65 2802.01 1609.37 ;
     RECT  2761.23 1609.37 2788.21 1610.05 ;
     RECT  2763.07 1610.05 2788.21 1611.41 ;
     RECT  2388.63 1131.03 2388.93 1616.85 ;
     RECT  2821.95 1608.69 2849.85 1628.25 ;
     RECT 552.070 1592.370 563.970 1628.410 ;
     RECT 567.070 1592.370 580.210 1628.410 ;
     RECT  630.51 1112.72 630.81 1629.77 ;
     RECT  49.07 1601.21 156.09 1630.45 ;
     RECT  2821.95 1628.25 2850.77 1630.45 ;
     RECT  49.07 1630.45 110.09 1635.89 ;
     RECT  2763.07 1611.41 2772.57 1635.89 ;
     RECT  49.07 1635.89 102.73 1644.05 ;
     RECT  2763.07 1635.89 2771.65 1644.05 ;
     RECT  2763.07 1644.05 2765.21 1645.41 ;
     RECT  49.07 1644.05 81.57 1649.49 ;
     RECT  2764.91 1645.41 2765.21 1649.49 ;
     RECT  137.39 1630.45 156.09 1655.61 ;
     RECT  49.07 1649.49 63.17 1656.29 ;
     RECT  102.43 1644.05 102.73 1657.65 ;
     RECT  2834.83 1630.45 2850.77 1657.65 ;
     RECT  2834.83 1657.65 2835.13 1658.33 ;
     RECT  137.39 1655.61 155.17 1659.01 ;
     RECT  49.07 1656.29 49.37 1660.37 ;
     RECT  154.87 1659.01 155.17 1671.25 ;
     RECT  2051.91 1555.35 2052.21 1671.25 ;
     RECT 12.070 1001.450 23.970 1689.360 ;
     RECT 188.970 1558.800 207.070 1565.385 ;
     RECT 192.070 1565.385 203.970 1689.360 ;
     RECT 368.970 1558.800 387.070 1565.385 ;
     RECT 372.070 1565.385 383.970 1689.360 ;
     RECT 552.070 1628.410 563.970 1689.360 ;
     RECT 732.070 1112.720 743.970 1689.360 ;
     RECT 908.970 967.865 927.070 978.265 ;
     RECT 912.070 978.265 923.970 1689.360 ;
     RECT 1088.970 967.865 1107.070 978.265 ;
     RECT 1092.070 978.265 1103.970 1689.360 ;
     RECT 1268.970 967.865 1287.070 978.265 ;
     RECT 1272.070 978.265 1283.970 1689.360 ;
     RECT 1448.970 967.865 1467.070 978.265 ;
     RECT 1452.070 978.265 1463.970 1689.360 ;
     RECT 1628.970 967.865 1647.070 978.265 ;
     RECT 1632.070 978.265 1643.970 1689.360 ;
     RECT 1808.970 967.865 1827.070 978.265 ;
     RECT 1812.070 978.265 1823.970 1689.360 ;
     RECT 1988.970 967.865 2007.070 978.265 ;
     RECT 1992.070 978.265 2003.970 1689.360 ;
     RECT 2172.070 1555.650 2183.970 1689.360 ;
     RECT 2348.970 967.865 2367.070 978.265 ;
     RECT 2352.070 978.265 2363.970 1689.360 ;
     RECT 2532.070 1246.930 2543.970 1689.360 ;
     RECT 2712.070 1589.650 2723.970 1689.360 ;
     RECT 2892.070 1030.010 2903.970 1689.360 ;
    LAYER met5 ;
     RECT 8.970 992.650 59.460 1006.550 ;
     RECT 5.280 1637.430 112.820 1649.330 ;
     RECT 112.820 1615.900 122.020 1634.330 ;
     RECT 112.820 1637.430 122.020 1649.330 ;
     RECT 122.020 1602.300 147.780 1634.330 ;
     RECT 122.020 1637.430 147.780 1649.330 ;
     RECT 5.280 557.430 149.220 569.330 ;
     RECT 5.280 737.430 149.220 749.330 ;
     RECT 59.460 917.430 149.220 989.550 ;
     RECT 59.460 992.650 149.220 1006.550 ;
     RECT 147.780 1595.500 152.380 1634.330 ;
     RECT 147.780 1637.430 152.380 1649.330 ;
     RECT 149.220 152.700 217.700 209.330 ;
     RECT 149.220 212.430 217.700 554.330 ;
     RECT 149.220 557.430 217.700 569.330 ;
     RECT 149.220 572.430 217.700 734.330 ;
     RECT 149.220 737.430 217.700 749.330 ;
     RECT 149.220 752.430 217.700 914.330 ;
     RECT 149.220 917.430 217.700 989.550 ;
     RECT 149.220 992.650 217.700 1006.550 ;
     RECT 152.380 1575.100 323.500 1634.330 ;
     RECT 152.380 1637.430 323.500 1649.330 ;
     RECT 217.700 152.700 558.100 209.330 ;
     RECT 217.700 212.430 558.100 554.330 ;
     RECT 217.700 557.430 558.100 569.330 ;
     RECT 217.700 572.430 558.100 734.330 ;
     RECT 217.700 737.430 558.100 749.330 ;
     RECT 217.700 752.430 558.100 914.330 ;
     RECT 217.700 917.430 558.100 989.550 ;
     RECT 217.700 992.650 558.100 1006.550 ;
     RECT 217.700 1009.650 558.100 1025.900 ;
     RECT 372.070 1006.550 373.670 1009.650 ;
     RECT 372.070 989.550 373.670 992.650 ;
     RECT 5.280 1097.430 558.100 1109.330 ;
     RECT 323.500 1568.300 573.500 1634.330 ;
     RECT 323.500 1637.430 573.500 1649.330 ;
     RECT 558.100 152.700 1128.260 209.330 ;
     RECT 558.100 212.430 1128.260 554.330 ;
     RECT 558.100 557.430 1128.260 569.330 ;
     RECT 558.100 572.430 1128.260 734.330 ;
     RECT 573.220 569.330 1128.260 572.430 ;
     RECT 573.220 554.330 1128.260 557.430 ;
     RECT 558.100 737.430 1128.260 749.330 ;
     RECT 558.100 752.430 1128.260 914.330 ;
     RECT 573.220 749.330 1128.260 752.430 ;
     RECT 573.220 734.330 1128.260 737.430 ;
     RECT 558.100 917.430 1128.260 989.550 ;
     RECT 573.220 914.330 1128.260 917.430 ;
     RECT 558.100 992.650 1128.260 1006.550 ;
     RECT 558.100 1009.650 1128.260 1094.330 ;
     RECT 732.070 1006.550 1128.260 1009.650 ;
     RECT 558.100 1097.430 1128.260 1109.330 ;
     RECT 732.070 989.550 1128.260 992.650 ;
     RECT 1128.260 152.700 2168.780 209.330 ;
     RECT 1128.260 212.430 2168.780 988.500 ;
     RECT 573.500 1575.100 2750.220 1634.330 ;
     RECT 573.500 1637.430 2750.220 1649.330 ;
     RECT 2168.780 152.700 2770.480 209.330 ;
     RECT 2168.780 212.430 2770.480 554.330 ;
     RECT 2168.780 557.430 2770.480 569.330 ;
     RECT 2168.780 572.430 2770.480 734.330 ;
     RECT 2168.780 569.330 2732.420 572.430 ;
     RECT 2168.780 554.330 2732.420 557.430 ;
     RECT 2168.780 737.430 2770.480 749.330 ;
     RECT 2168.780 752.430 2770.480 914.330 ;
     RECT 2168.780 749.330 2732.420 752.430 ;
     RECT 2168.780 734.330 2732.420 737.430 ;
     RECT 2168.780 917.430 2770.480 966.020 ;
     RECT 2168.780 914.330 2732.420 917.430 ;
     RECT  2770.48 357.9 2772.3 410.5 ;
     RECT 2750.220 1595.500 2775.060 1634.330 ;
     RECT 2750.220 1637.430 2775.060 1649.330 ;
     RECT 2770.480 557.430 2777.820 569.330 ;
     RECT 2770.480 572.430 2777.820 604.300 ;
     RECT 2770.480 737.430 2778.740 749.330 ;
     RECT 2770.480 752.430 2778.740 804.900 ;
     RECT 2775.060 1602.300 2830.260 1634.330 ;
     RECT 2775.060 1637.430 2830.260 1649.330 ;
     RECT 2830.260 1622.700 2846.820 1634.330 ;
     RECT 2830.260 1637.430 2846.820 1649.330 ;
     RECT 5.280 17.430 2914.340 29.330 ;
     RECT 2777.820 557.430 2914.340 569.330 ;
     RECT 2778.740 737.430 2914.340 749.330 ;
     RECT 1128.260 1097.430 2914.340 1109.330 ;
     RECT 5.280 1277.430 2914.340 1289.330 ;
     RECT 5.280 1457.430 2914.340 1469.330 ;
     RECT 2846.820 1637.430 2914.340 1649.330 ;
  END
END CF_CARAVEL_SOC
END LIBRARY
